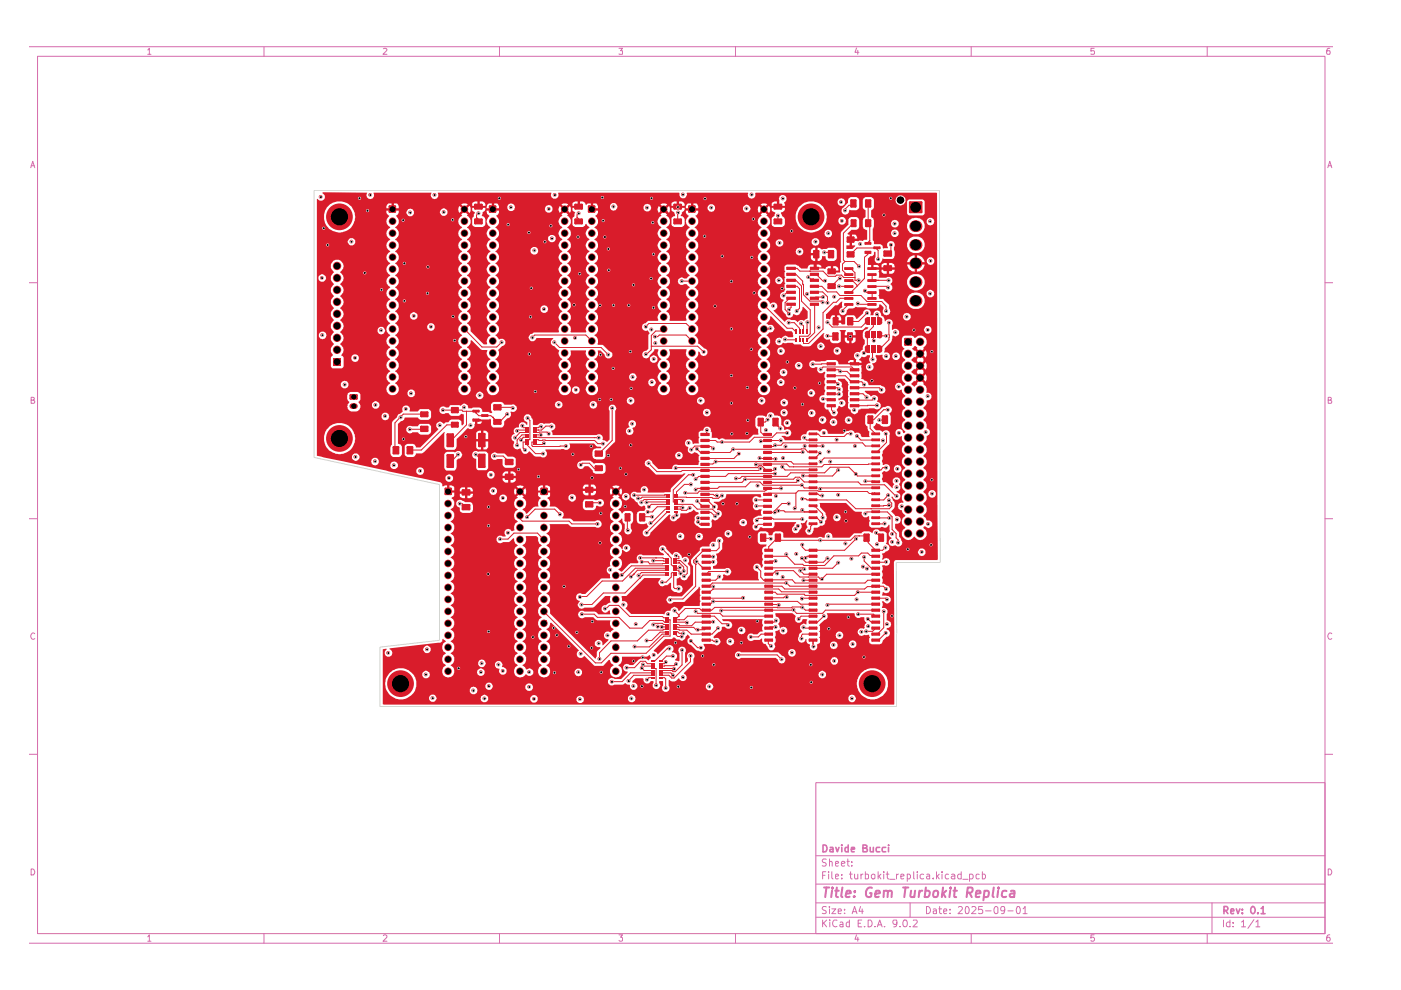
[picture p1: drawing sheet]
<svg xmlns="http://www.w3.org/2000/svg" width="297mm" height="210mm" viewBox="0 0 297 210" stroke-linecap="round" stroke-linejoin="round" font-family="sans-serif">
<g fill="none" stroke="#d56bad" stroke-width=".21">
<path d="M6.3 9.9h276.3M8 11.9h272.9v186.1h-272.9zM31.3 10.6l.4-.4v1.3M31.3 11.5h.7M56 9.9v2M81.3 10.3l.5-.1 .2 .4-.8 .9h.8M105.9 9.9v2M131.2 10.2h.8l-.4 .6h.4v.6h-.8M156 9.9v2M181.6 10.2l-.3 .9h.8M181.9 10.7v.8M205.9 9.9v2"/>
<path d="M232 10.2h-.7v.6h.6l.2 .2-.2 .5-.6-.1M255.9 9.9v2M281.9 10.2l-.5 .1-.1 .5v.6l.6 .1v-.7h-.5l-.1 .2M6.5 35.6l.4-1.4 .5 1.4M6.6 35.1h.7M281.5 35.6l.4-1.4 .5 1.4M281.6 35.1h.7M6.3 59.9h1.7M280.9 59.9h1.7M6.6 84.8h.6v-.5l-.6-.1v1.3h.6l.2-.4-.4-.3M281.6 84.8h.6v-.5l-.6-.1v1.3h.6l.2-.4-.4-.3M6.3 110h1.7"/>
<path d="M280.9 110h1.7M7.4 134.4a.57 .57 0 0 0-.8 0 .57 .57 0 0 0 0 .8l.3 .4 .5-.2M282.4 134.4a.57 .57 0 0 0-.8 0 .57 .57 0 0 0 0 .8l.3 .4 .5-.2M6.3 159.9h1.7M280.9 159.9h1.7M173 165.9h107.9v32.1h-107.9zM6.3 200h276.3M6.6 184.2a.71 .71 0 0 1 .7 .5 .71 .71 0 0 1-.2 .8h-.5zM31.3 198.6l.4-.4v1.4M31.3 199.6h.7M56 198v2M81.3 198.4l.1-.2h.4l.2 .4-.8 1h.8"/>
<path d="M105.9 198v2M131.2 198.2h.8l-.4 .5 .4 .2v.5l-.3 .2h-.3l-.2-.2M156 198v2M173 194.5h107.9M173 191.4h107.9M173 187.5h107.9M173 181.4h107.9M174.4 195.1v1.4M174.4 185.6h.5M174.6 195.7l.7 .8M175.1 184.8h-.7v1.6M175.2 192.3l-.6-.1-.3 .3 .3 .5 .5 .1v.5h-.8"/>
<path d="M175.2 182.2l-.6-.1-.3 .4 .3 .4h.3l.2 .1 .1 .4-.3 .2h-.6M175.3 195.1l-.9 .8M175.7 184.8v.2M175.7 185.3v1.1M175.9 192.2v.2M175.9 182.8l.1-.2 .4 .1v.9M175.9 182.1v1.5M175.9 192.7v1M175.9 195.1v.1M175.9 195.5v1M176.4 192.7h.8l-.8 1h.8M176.4 184.8v1.3l.2 .3"/>
<path d="M177.1 185.8l.7-.1-.2-.4-.4 .1-.1 .7 .2 .3 .4-.1M177.1 183.1l.7-.1-.2-.4-.4 .1-.1 .7 .2 .2h.4M177.5 195.2l-.6-.1a.74 .74 0 0 0-.4 .9 .74 .74 0 0 0 1 .4M177.7 193.2l.7-.1-.2-.4-.5 .1v.8h.6M178.1 195.6h.5l.1 .9M178.4 183.1l.8-.1-.1-.3-.5-.1-.2 .3 .1 .7h.6M178.5 186.2v.2M178.5 185.4v.2M178.7 195.9l-.6 .1v.2l.1 .3 .5-.1M179.1 193.6v.1M179.1 192.8v.2M179.6 182.6h.5"/>
<path d="M179.7 182.1v1.3l.4 .2M180.1 195.6l-.4-.1-.3 .3 .1 .6h.6M180.1 195.1v1.4M180.1 185.3h.6M180.3 184.8v1.3l.4 .3M180.6 183.5v.1M180.6 182.7v.2M180.7 193.7l.5-1.5 .5 1.5M180.8 193.3h.7M181.2 185.3l.1 1 .3 .1 .3-.2M181.6 198.2l-.3 .9h.8M181.9 185.3v1.1"/>
<path d="M181.9 198.7v.9M181.9 195.7h.6M182.5 192.2l-.4 1h.9M182.5 185.3v1.1M182.7 195.1h-.8v1.4h.8M182.8 192.7v1M183 185.3l-.5 .3M183.3 196.4v.1M183.5 185.4l.4-.1 .2 .2v.7l-.2 .2-.4-.1M183.5 184.8v1.6M184.1 195.1h.5a.78 .78 0 0 1 .3 .9 .78 .78 0 0 1-.8 .5zM184.7 185.6a.45 .45 0 0 1 .8-.1v.7l-.2 .2-.5-.2z"/>
<path d="M185.5 196.4v.1M186 196.5l.5-1.4 .5 1.4M186.2 196.1h.7M186.2 184.8v1.6M186.4 185.8l.4 .6M186.8 185.3l-.6 .6M187.4 184.8v.2M187.4 185.3v1.1M187.5 196.4v.1M187.9 185.3h.6M188.1 184.8v1.3l.4 .3M188.6 186.4h1.1"/>
<path d="M190.1 185.3v1.1M190.2 195.7l-.3 .3-.4-.1-.2-.2 .2-.6h.6a1.12 1.12 0 0 1-.4 1.4h-.2M190.5 185.3l-.4 .3M190.8 196.4v.1M191 185.8l.7-.1-.1-.3h-.6v.9h.6M191.6 195.2l.5-.1a.84 .84 0 0 1-.2 1.4l-.3-.1-.2-.4zM192.4 185.4l.4-.1 .2 .3v.4l-.2 .4-.4-.1M192.4 185.3v1.6M193 196.4v.1M193 191.4v3.1M193.6 195.2l.7-.1 .2 .4-1 1h1M193.7 184.8v1.5l.2 .1"/>
<path d="M194.5 184.8v.2M194.5 185.3v1.1M195.8 185.4a.52 .52 0 0 0-.7 .2l.1 .7h.6M196.4 192.2a.77 .77 0 0 1 .9 .8 .77 .77 0 0 1-.9 .7zM196.5 185.4h.5l.1 1M197.1 185.7l-.5 .1-.2 .2 .2 .4 .5-.1M197.9 192.8h.6v.9M197.9 186.2v.2M198.5 193.1l-.6 .1v.4h.6M198.5 184.8v1.6M198.7 185.8l.4 .6M199.1 192.7h.5"/>
<path d="M199.1 185.3l-.6 .6M199.2 192.2v1.3l.4 .2M199.7 184.8v.2M199.7 185.3v1.1M200.1 193.2l.6-.1-.1-.4-.4 .1-.1 .7 .1 .2 .5-.1M201.1 185.4l-.4-.1-.3 .3 .1 .6 .2 .2 .4-.1M201.4 193.6v.1M201.4 192.8v.2M201.8 185.4h.6v1M202.4 185.7l-.5 .1-.2 .2 .2 .4 .5-.1M203.2 192.4l.2-.2h.4a.45 .45 0 0 1 .2 .7l-.9 .8h.9M203.8 185.4l-.5-.1-.3 .3v.4l.3 .4 .5-.1"/>
<path d="M203.8 184.8v1.6M204.1 186.4h1.1M204.7 192.4l.3-.2a.88 .88 0 0 1 .1 1.5l-.4-.1zM205.6 185.4l.5-.1 .2 .3v.4l-.2 .4-.5-.1M205.6 185.3v1.6M205.9 198v2M206.1 192.4l.1-.2h.4l.2 .2 .1 .3-.9 1h.9M207.6 185.4l-.4-.1-.3 .3 .1 .7h.6M208.3 192.2h-.8l-.1 .8 .3-.2 .5 .1 .2 .2-.1 .5h-.9M208.3 185.4l.4-.1 .3 .3-.1 .6-.2 .2-.4-.1M208.3 184.8v1.6M209 193.1h1.1"/>
<path d="M211.1 192.2l.3 .1 .2 .2v1l-.4 .2a.81 .81 0 0 1-.6-.7 .81 .81 0 0 1 .5-.8zM213 192.9l-.1 .2-.6-.1a.6 .6 0 0 1 .1-.8l.5 .1a1.12 1.12 0 0 1-.3 1.4h-.3M213.7 193.1h1.1M215.6 192.3l.2-.1a.86 .86 0 0 1 .6 .7 .86 .86 0 0 1-.4 .8h-.2a1.1 1.1 0 0 1-.2-1.4zM216.9 192.7l.4-.5v1.5M216.9 193.7h.9M232 198.2h-.7v.7l.2-.2h.3l.3 .3v.3l-.3 .3h-.3l-.2-.2M255.9 198v2M257 191.4v6.6M259.4 195.1v1.4M260.8 195.6l-.5-.1-.3 .3 .1 .6h.7M260.8 195.1v1.4"/>
<path d="M261.5 196.4v.1M261.5 195.6v.1M263.2 195.5l.5-.4v1.4M263.2 196.5h.9M265.9 195l-1.3 1.8M266.3 195.5l.4-.4v1.4M266.3 196.5h.8M281.6 184.2a.71 .71 0 0 1 .7 .5 .71 .71 0 0 1-.2 .8h-.5zM281.9 198.2l-.5 .2a.92 .92 0 0 0 .1 1.2l.4-.1 .1-.5-.2-.3h-.3l-.2 .3"/>
</g>
<g fill="none" stroke="#d56bad" stroke-width=".34">
<path d="M174.5 179.2a.81 .81 0 0 1 .8 .4 .81 .81 0 0 1-.2 1h-.6zM176 179.7h.5l.1 .1v.8h-.6v-.5l.6-.1M177.2 179.7l.3 .9 .4-.9M178.5 179.2h.1M178.5 179.7v.9M179.8 179.2v1.4h-.5l-.1-.3v-.6h.6M183 179.8l.6-.1 .2-.1-.1-.4h-.7v1.4h.7l.2-.5-.4-.3M184.5 179.7l.1 .9 .6-.1M185.2 179.7v.9M186.5 179.7h-.6l-.1 .2 .1 .7h.6M187.8 179.7h-.6l-.2 .2 .2 .7h.6M188.4 179.2h.1"/>
<path d="M188.4 179.7v.9M180.5 180.1l.7-.1-.1-.3h-.5l-.1 .1 .1 .8h.5M259.5 193h.6a.47 .47 0 0 0 .3-.4 .47 .47 0 0 0-.3-.4h-.6v1.5M259.8 193l.5 .7M260.9 193.2l.7-.1-.1-.4-.5 .1-.1 .7 .2 .2 .4-.1M262.1 192.7l.4 1 .4-1M263.4 193.5v.2M263.4 192.8v.2M265.3 192.4l.3-.2a.82 .82 0 0 1 .5 .8 .82 .82 0 0 1-.5 .7 .93 .93 0 0 1-.3-1.3zM266.7 193.5v.2M267.4 192.6l.4-.4v1.5M267.4 193.7h.8"/>
</g>
<g fill="none" stroke="#d56bad" stroke-width=".42">
<path d="M174.7 188.2h1.1M175.2 188.2l-.2 2M176.4 188.8l-.2 1.4M176.5 188.2v.2M177.1 188.8h.7M177.4 188.2l-.2 1.7 .5 .3M178.6 188.2l-.2 1.7 .2 .3M179.4 189.5l1-.1-.1-.5h-.8l-.2 1 .2 .3 .6-.1M181.1 190l.1 .1h-.2l.1-.1v.2M181.2 188.9v.3M184.9 188.3a.77 .77 0 0 0-1 .2 1.18 1.18 0 0 0 0 1.6l.5 .1 .3-.2 .1-.6h-.4M185.5 189.5l1.1-.1-.1-.5-.6-.1-.3 .4-.1 .9h.8"/>
<path d="M187.4 189l.3-.2 .5 .1v1.3M187.4 188.8l-.1 1.4M188.3 189.2l.3-.4 .4 .1v1.3M191.5 188.2h1.1M192 188.2l-.3 2M193.2 188.8l-.1 1.3 .5 .1 .2-.2M194 188.8l-.2 1.4M194.9 188.8l-.1 1.4M195.5 188.8a.46 .46 0 0 0-.6 .5M196.2 188.9l.6-.1 .3 .2a.89 .89 0 0 1-.5 1.2l-.6-.1M196.3 188.2l-.3 2M198 189l.3-.2a.46 .46 0 0 1 .6 .5l-.1 .5a.52 .52 0 0 1-.5 .4 .52 .52 0 0 1-.5-.4z"/>
<path d="M199.9 188.2l-.2 2M199.9 189.4l.5 .8M200.6 188.8l-.8 .8M201.5 188.8l-.2 1.4M201.5 188.2v.2M202.1 188.8h.8M202.5 188.2l-.2 1.9 .4 .1M205 189.3l1-.1 .2-.4-.1-.5-.9-.1-.3 2M205.5 189.3l.5 .9M206.9 189.5l1-.1-.1-.5-.6-.1-.2 .4-.1 .9h.7M208.7 188.9a.64 .64 0 0 1 .9 .1l-.1 1-.3 .2-.5-.1M208.7 188.8l-.2 2.1"/>
<path d="M210.7 188.2l-.3 1.7 .3 .3M211.6 188.8l-.1 1.4M211.7 188.2v.2M213.4 188.9l-.5-.1-.3 .2-.1 1a.64 .64 0 0 0 .8 .1M214.3 188.9h.8l-.1 1.3M215.1 189.4h-.7l-.3 .3v.2l.2 .3 .7-.1"/>
</g>
<path d="M66.6 40.3h132.6l.1 79h-9.3l.1 30.5h-109.5v-12.6l12.6-1.4v-33.1l-26.6-5.7z" fill="none" stroke="#d0d2cd" stroke-width=".21"/>
<g fill="#d91c2b">
<path d="M193.3 81.2l.5-.5 .2 .2 .6-.7 .2 .4h.2l-.6 .6 .1 .2-.6 .6-.6-.5z"/>
<path d="M193.3 78.7l.5-.5 .2 .2 .6-.7 .2 .3 .2 .1-.6 .6 .1 .2-.1 .1 .6 .6-.4 .4-.6-.6a.64 .64 0 0 1-.7-.7z"/>
<path d="M193.3 76.2l.5-.6 .2 .2 .6-.7 .2 .4 .2 .1-.6 .6 .1 .1-.1 .2 .6 .6-.4 .3-.6-.6a.64 .64 0 0 1-.7-.6z"/>
<path d="M193.4 73.8l.7-.4 .4 .4-.1 .2 .6 .5-.4 .4-.6-.6-.2 .1-.4-.4z"/>
<path d="M68.5 40.8l9.4 .1-.1 .1a.89 .89 0 0 0 .8 1.2 .94 .94 0 0 0 .6-1.3h12.3v.1a.79 .79 0 0 0 .3 1.2 .79 .79 0 0 0 1.1-.6l-.1-.7h24.1a1.05 1.05 0 0 0 .4 1.2h.6l.3-.2 .2-.3v-.7h25.6l.1 .5 .5 .6h.5l.3-.2 .3-.5v-.4h12.8l.1 .8 .4 .3 .3 .1 5.8-.1 .2 .6-.1 1h1.2l-.2-.7 .3-.1 .3-.4-.1-.6a.81 .81 0 0 0-.9-.4 .81 .81 0 0 0-.7 .6h-5.5l.5-.3v-.8h.1h38.5l.1 77.7v.1h-8.9l-.4 .4 .1 30.2-108.3 .1-.1-.1v-4.5h.5a3.3 3.3 0 0 0 4.7 3.2h4.6v.3a.81 .81 0 0 0 .7 .5 .81 .81 0 0 0 .7-.4l.2-.4h9.3a.81 .81 0 0 0 .8 .9 .81 .81 0 0 0 .8-.8h8.9l.1 .4a.86 .86 0 0 0 1.5 0v-.3h8.2a.79 .79 0 0 0 .9 .9 .79 .79 0 0 0 .6-1.1h9.4v.4a.83 .83 0 0 0 1 .5 .83 .83 0 0 0 .6-.9h45.2l.2 .7 .3 .2h.5a.81 .81 0 0 0 .3-1.4 .81 .81 0 0 0-1.3 .5h-45.2v-.1a.77 .77 0 0 0-.9-.6 .77 .77 0 0 0-.7 .7h-9.4a.81 .81 0 0 0-.8-.5 .81 .81 0 0 0-.7 .7h-8.2v-.3a.84 .84 0 0 0-.9-.5 .84 .84 0 0 0-.7 .7h-8.9v-.2a.82 .82 0 0 0-.9-.6 .82 .82 0 0 0-.7 .7h-9.3l-.3-.5a.84 .84 0 0 0-1.3 .3v.2h-4.6a3.1 3.1 0 0 0 1.6-1.7h11.6v.4a.84 .84 0 0 0 1.3 .4 .84 .84 0 0 0 0-1.4 .84 .84 0 0 0-1.3 .5v.1h-11.6l.3-.9h14.6v.4a.81 .81 0 0 0 .7 .4 .81 .81 0 0 0 .8-.4v-.2h7v.3a.88 .88 0 0 0 1.3 .4l.2-.2a.83 .83 0 0 0-.1-.9 .83 .83 0 0 0-.8-.3l-.5 .3-.1 .4h-7v-.4l-.5-.5h-.5l-.2 .2-.3 .5h-14.6v-1l-.3-.8-.4-.6h1.9v.3l.3 .3 .2 .2h.6a.81 .81 0 0 0 .3-1.4 .81 .81 0 0 0-1.4 .6h-1.9l-.4-.5a3.3 3.3 0 0 0-3.5-.5 3.3 3.3 0 0 0-2 2.8h-.5v-7.1l.6-.2 .2 .2a.84 .84 0 0 0-.4 .8 .84 .84 0 0 0 .5 .7l.7-.1a1.04 1.04 0 0 0 .3-1.1l-.5-.4h7.1a.85 .85 0 0 0 1.4 .7l.1-.3a.84 .84 0 0 0-.7-1.1l-.4 .1-.4 .6h-7.1v-.1l10.8-1.2 .4-.3v-.4l.1-.2 .6 .5-.1 .2a1.19 1.19 0 0 0-.5 1.6l.1 .4 .5 .4-.1 .1a1.19 1.19 0 0 0-.5 1.7l.1 .4 .5 .3-.1 .2a1.19 1.19 0 0 0-.5 1.6 1.26 1.26 0 0 0 1.3 .8 1.26 1.26 0 0 0 1.1-1.1h4.8v.1a.84 .84 0 0 0 .8 .7 .84 .84 0 0 0 .8-.5v-.7a.85 .85 0 0 0-.9-.3 .85 .85 0 0 0-.7 .7h-4.8v-.5a1.1 1.1 0 0 0-.8-.9l.6-.5h5.3v.3a.81 .81 0 0 0 .7 .5 .81 .81 0 0 0 .7-.4l.1-.2h2v.4l.3 .4 .7 .2v.8a.86 .86 0 0 0 1.5-.1 1.16 1.16 0 0 0-1-1.1 .84 .84 0 0 0-.4-1.2h-.5l-.3 .1-.3 .5h-2a.78 .78 0 0 0-.6-.9 .78 .78 0 0 0-.9 .7h-5.3l.2-.5v-.8l-.8-.8 .6-.5 .2-1.1-.2-.5-.6-.5 .6-.5 .2-1.1-.2-.5-.6-.4 .6-.5 .2-1.1-.2-.5-.6-.4 .6-.6 .2-1.1-.2-.5-.6-.3 .2-.2a1.36 1.36 0 0 0 0-2.3l-.2-.1 .6-.5 .2-1.1-.2-.5-.6-.5 .6-.5 .2-1.1-.2-.5-.6-.4 .6-.5 .2-1.1-.2-.5-.6-.4 .1-.1a1.19 1.19 0 0 0 .6-1.6l-.1-.5-.6-.4a1.16 1.16 0 0 0 .8-1.3h9v.3a.79 .79 0 0 0 1.3 .3h1.3l.9-.8 .1 .1a1.49 1.49 0 0 0 .9 1.4l-.1 .2a1.19 1.19 0 0 0-.6 1.6l.2 .4 .5 .4-.2 .1a1.54 1.54 0 0 0-.5 1.8l.7 .6-.2 .2a1.36 1.36 0 0 0 0 2.2l.2 .1-.1 .2a1.19 1.19 0 0 0-.6 1.6l.2 .4 .5 .4-.1 .1a1.19 1.19 0 0 0-.6 1.7l.2 .4 .5 .3-.1 .2a1.26 1.26 0 0 0-.5 1.8l.6 .6-.2 .1a1.36 1.36 0 0 0 0 2.3l.2 .1-.1 .2a1.19 1.19 0 0 0-.6 1.6l.2 .4 .5 .3-.1 .2a1.19 1.19 0 0 0-.6 1.6l.2 .4 .5 .4-.1 .1a1.19 1.19 0 0 0-.6 1.7l.2 .4 .5 .3-.1 .2a1.19 1.19 0 0 0-.6 1.6 1.33 1.33 0 0 0 1.1 .8 1.33 1.33 0 0 0 1.3-.6h.1a.83 .83 0 0 0 1.1 .2 .83 .83 0 0 0 .3-1.1l-.7-.4-.8 .2-.2-.5-.5-.3 .5-.4 .2-.6v-.8l-.2-.4-.5-.3 .5-.5 .2-.6v-.6l-.2-.5-.5-.4 .5-.4 .2-.6v-.9l-.7-.6 .5-.4 .2-.6v-.7l-.2-.5-.5-.4 .5-.4 .2-.6v-.9l-.7-.6 .2-.2a1.36 1.36 0 0 0 0-2.3l-.2-.1 .5-.4 .2-.6v-.6l-.2-.5-.5-.5 .6-.5 .1-1.1-.2-.5-.5-.4 .6-.5 .1-1.1-.2-.5-.5-.4 .1-.1a1.19 1.19 0 0 0 .6-1.6l-.2-.5-.5-.4a1.1 1.1 0 0 0 .7-.9v-1h2.2l.4 .3 .2 1.1 .6 .5-.1 .2a1.19 1.19 0 0 0-.6 1.6l.1 .4 .6 .4-.2 .1a1.54 1.54 0 0 0-.5 1.8l.7 .6-.2 .2a1.36 1.36 0 0 0 0 2.2l.2 .1-.1 .2a1.19 1.19 0 0 0-.6 1.6l.1 .4 .6 .4-.1 .1a1.19 1.19 0 0 0-.6 1.7l.1 .4 .6 .3-.1 .2a1.26 1.26 0 0 0-.5 1.8l.6 .6-.2 .1a1.36 1.36 0 0 0 0 2.3l.2 .1-.1 .2a1.19 1.19 0 0 0-.6 1.6l.1 .4 .6 .3-.1 .2a1.19 1.19 0 0 0-.6 1.6l.1 .4 .6 .4-.1 .1a1.19 1.19 0 0 0-.6 1.7l.1 .4 .6 .3-.1 .2a1.19 1.19 0 0 0-.6 1.6 1.26 1.26 0 0 0 1.3 .8 1.26 1.26 0 0 0 1.1-1.1h5.2v.1a.82 .82 0 0 0 .7 .8 .82 .82 0 0 0 .9-.6v-.5l-.5-.5-.7 .1-.4 .6h-5.2a1.26 1.26 0 0 0-.7-1.4l.5-.4 .2-.6v-.8l-.2-.4-.5-.3 .5-.5 .2-.6v-.6l-.2-.5-.5-.4 .5-.4 .2-.6-.1-.9-.6-.6 .1-.2a1.34 1.34 0 0 0 .7-1.3h.2l5.8 5.9a.88 .88 0 0 0-.2 1.4 .88 .88 0 0 0 1.4-.2l2.2 2.1h1.8l1.2-1.3 .2 .1 .3 .7 .5 .3-.2 .2a1.54 1.54 0 0 0-.5 1.8 1.33 1.33 0 0 0 1.4 .6 1.33 1.33 0 0 0 1.1-1l-.1-.9-.7-.6 .6-.6 .2-.4v-.9h5.2l.7-.3 .2 .6-.5 .5-.5-.3h-1.2l-1.6 1.3h-.7a.84 .84 0 0 0-1.4 .4v.5l.2 .2 .3 .3h.5v.2l-1.4 1.4h-1.4a.82 .82 0 0 0-1.2 0 .82 .82 0 0 0 0 1.1 .82 .82 0 0 0 1.2 .1h1.7l.5-.4 .6 .4h.4a.91 .91 0 0 0 .3 .9 .91 .91 0 0 0 .9 .1l.4-.4a.84 .84 0 0 0-.2-.9 .84 .84 0 0 0-.8-.2v-.3l.6-.6h1.6l.1 .1v.5l.5 .5h.6l.5-.5h.5l.1 .4-.2 .3v.5l.5 .5h.5a.78 .78 0 0 0 .3-1.3l.1-.4h.7v1a.9 .9 0 0 0 .4 1.3h.5l.4-.3 .1-.3v-.6h7.7v.3a.81 .81 0 0 0 .7 .5 .81 .81 0 0 0 .8-.4 .79 .79 0 0 0-.4-1.1h31v.4a3.3 3.3 0 0 0 3.1 3.1 3.3 3.3 0 0 0 3.5-2.7 3.2 3.2 0 0 0-1.9-3.6 3.3 3.3 0 0 0-4.7 2.8l-31.4-.1-.6 .5-.1 .3-7.8-.1 .1-1.3 .6 .4h.5l.9-.7 .2 .1a.8 .8 0 0 0 .7 .5 .8 .8 0 0 0 .8-.5v-.5l-.4-.4h28.3a.83 .83 0 0 0 .7 .8 .83 .83 0 0 0 .9-.5l-.1-.7a.85 .85 0 0 0-.8-.3 .85 .85 0 0 0-.7 .7h-28.3l-.2-.2 1.9-2 .1-1.1 .3-.6-.1-.3h8.6v.3a.73 .73 0 0 0 .6 .6 .73 .73 0 0 0 .7-.2h7.4l.5 .4a.77 .77 0 0 0 .7 .8 .77 .77 0 0 0 .8-.6h9.6l.4 .7h.7a.81 .81 0 0 0 .1-1.4 .81 .81 0 0 0-1.2 .7h-9.6v-.5l-.2-.3-1.3-1h2.1a.83 .83 0 0 0 .6 .9 .83 .83 0 0 0 1-.6 .83 .83 0 0 0-.5-1l-.7 .1-.2 .2-.2 .4h-10l-.3-.2h-.5l-.3 .3-.2 .4h-8.6a.79 .79 0 0 0-1.1-.4 .79 .79 0 0 0-.3 1.2v.6l-.5 .4-.1-2.2a.8 .8 0 0 0-.1-1.1 .8 .8 0 0 0-1.1 .1 .8 .8 0 0 0 .1 1.1v1.6l-.2 .2-.8-.3 .5-.6-.1-.7-1-.5 .3-.4v-.5a1.02 1.02 0 0 0-1.6-.3l-1.7 1.7-.4-.4-.5-.3 2.4-2.5h1.4l.3-.3h.3l.5 .4 .7 .1a.85 .85 0 0 0 1.2-.8l.4-.3 .5 .4-.5 .7v.5l.1 .2 .5 .3 1.2 1.2 .5 .1a.86 .86 0 0 0 1.4-.7l-.4-.6 .1-.2h1.7l1.1 .4 .7-.5 .1-.5h1.3a.78 .78 0 0 0 .6 .9 .78 .78 0 0 0 .9-.6 .78 .78 0 0 0-.5-.9h-.5l-.4 .2-.1 .4h-1.4l-.3-.6h-1l-.1-.3 1.7-1.4h3.4v.3a.84 .84 0 0 0 1.2 .5 .86 .86 0 0 0 .4-.8 .86 .86 0 0 0-.6-.7 .78 .78 0 0 0-1 .7h-3.4v-.6l.6-.1a.84 .84 0 0 0 1.5 .1 .84 .84 0 0 0-.6-1.3h-1.1l-.3-.4h8.6v2.5a1.3 1.3 0 0 0-1.1 .7l-1.6-.2a.81 .81 0 0 0-.4 1.2 .81 .81 0 0 0 1.2 .2h1.3l.4-.4 .1 .7 .2 .4 .5 .1 .7 1.2 .3 .2 .7-.1 .4-.7-.1-.2a.57 .57 0 0 1 .2-.9l-.2-.8 .2-.5-.1-.9 .5-.1 .3-.2 .1 .5 .5 .5h.5l.5-.3a.89 .89 0 0 0-.7-1.3l-.7 .3-.4-1a.85 .85 0 0 0 .3-.9 .85 .85 0 0 0-.8-.6v-.7l3.6 .1a.8 .8 0 0 1 .4 1.3 .85 .85 0 0 0 .9 .7 .85 .85 0 0 0 .8-.8h.8l.2 .1-.2 .3v.7l-.7-.2-.7 .6v.5l.5 .6a1.61 1.61 0 0 0-.7 2l.2 .3a.94 .94 0 0 0 1.2-.6l.2-.1 .2 .9 .5 .2v.3a.74 .74 0 0 0 .6 1l.5-.1a.78 .78 0 0 0 .4-1.1h2.8v.3a.8 .8 0 0 0 1 .6 .8 .8 0 0 0 .5-1.1h2.5v.4a.86 .86 0 0 0 1.6 0l-.1-.7a.81 .81 0 0 0-.9-.4 .81 .81 0 0 0-.6 .7l-2.5-.1a.81 .81 0 0 0-.9-.4 .81 .81 0 0 0-.6 .7h-2.8l.7-.5v-.9h-.2l.2-.6h3.3a.82 .82 0 0 0 1 .8 .82 .82 0 0 0 .6-1.1 .82 .82 0 0 0-1.2-.4l-.4 .3v.4h-3.3v-.6l-.2-.1 .2-.4v-.8l-.2-.3 1.1-1.1 .5-.2 .2-.3-.1-.9h5.7l.1 .1v.4l.5 .5h.5l.3-.1h.8v.5l.4 .6-.4 .7a.31 .31 0 0 1 0 .4 .31 .31 0 0 1-.4 .1 .9 .9 0 0 0-1 1.2 .86 .86 0 0 0 1.4 .2l1 .1 .1 .4-.1 .2 .1 1.1 .4 .2h1.8a.74 .74 0 0 0 .6-.8l1.5-1.3v-.5l-.3-.4-.5-.2 .1-.2a.85 .85 0 0 0 .9-.8 .85 .85 0 0 0-.9-.9v-1.3l.2-.3v-.5l-.5-.5h-.7l.2-.5-.2-.8 .3-.1a1.03 1.03 0 0 0 1 .4l.5-.5a.91 .91 0 0 0-.9-1.1l-.9-.1 .2-.7h.1a.8 .8 0 0 0 1.4-.3v-.5l-.3-.4-1.4-.6 .2-.4v-.5l-.2-.2 .2-.6v-.5l-.2-.2 .2-1-.2-.3 .1-.2 .6 .1a.81 .81 0 0 0 1-.6v-.5l-.2-.1a.75 .75 0 0 0-1.3 0l-.2-.1 .2-.4v-.5l-.2-.2 .7-.5h6.9v.1a.84 .84 0 0 0 .7 .8 .84 .84 0 0 0 .9-.5v-.6l-.5-.5-.7 .1-.4 .6h-6.9a.85 .85 0 0 0 .9-.8 .85 .85 0 0 0-.8-.9l.2-.3v-1.9l-.6-.5h-.9l-.3-.3a.88 .88 0 0 0-1.2 .7l-.7-.4h-1.1l-.5 .5h-1.6l-1 .9h-3.6l-.1-.5a.8 .8 0 0 0-1.3-.4l-.3 .9-.7-.2-.7 .2h-7.2l-.1-.9-.6-.5h-1.1l-.4 .3-.3 .6h-.7l-.1-.6-.6-.3h-1.1l-.3 .2-.2 .4v1.7l.2 .4 .3 .1h1.3l-.1 .5a.76 .76 0 0 0-.8 .6v.5l.2 .2-.2 .5v.5l.2 .3-.2 1 .2 .4-.2 .5-.3-.1a.82 .82 0 0 0-.8-.8 .82 .82 0 0 0-.8 .8 .82 .82 0 0 0 .8 .8l.2 .3v1.2l.2 .5h-7.8l-.1-.2 .4-.5-.1-.5h.4a.82 .82 0 0 0 1.2-.3 .82 .82 0 0 0-.4-1.2h-.5l-.3 .2h-2.4l-.1-.6h.1a.88 .88 0 0 0 .5-1.4l.2-.7-.2-.4 .5-.2 .8-.8 .1-1.5a.87 .87 0 0 0-.4-1.2l-.6 .1a.74 .74 0 0 0-.4 1h-.2a.84 .84 0 0 0-1.2 .8v.2h-1.5l-.4 .2-.1 .7-1.9 1.9 .1 1 .3 .3v4.1l-2.3 2.3h-2.4a.83 .83 0 0 0-.9 .6 .83 .83 0 0 0 .6 1h.5l.4-.4h2.4l2.8-2.8 .1-.4 .3 .1 .1 .4-.1 .3v.8l.1 .2-.1 .2v.9l.1 .3-.1 .1-.1 .8h-3.3l-.9 1h-.3l-.2-.6-.6-.2-.7 .4-.1 .4h-.7l-.3 .2-.4 .6-7-.1-1.2-1.3a.77 .77 0 0 0 .5-.8 .77 .77 0 0 0-.6-.6l-.6-.1-.1-1h1l3.8-3.8h3.3l.2 .1a.8 .8 0 0 0-.4 1.2 .8 .8 0 0 0 1.2 .2 1.15 1.15 0 0 0 1.1-.5l.3 .1 .1 1.3 .4 .4 .6 .1a.82 .82 0 0 0 1.3-.5 .82 .82 0 0 0-1.1-.8l-.1-1.5 .6-.3 .2 .1a.8 .8 0 0 0 1.3 .4l.7-1.2v-1.5l-.5-.8a.8 .8 0 0 0-.2-1.3h-.5l-.4 .2-.2-.5a1.16 1.16 0 0 0-1.7-.5l-.2 .3h-.1l-1.2-1.2v-.3a.8 .8 0 0 0-.8-.5 .8 .8 0 0 0-.8 .6v.5l.3 .4 .8 .4-.1 .2h-4.4a.79 .79 0 0 0-1.2 .2 .79 .79 0 0 0 .2 1.1v.3l-.1 .1h-1.6l-1.7 1.8h-.3l-.5-.5 .6-.5 .2-1.1-.3-.5-.5-.4 .5-.4 .4-1.3a1 1 0 0 0 1.6 .1 .86 .86 0 0 0-.2-.9 .86 .86 0 0 0-.9-.2l-.5 .5v.4l-.1 .1-.8-.9a1.1 1.1 0 0 0 .8-.9l-.1-1-.7-.6a1.1 1.1 0 0 0 .8-1l-.1-.9-.7-.6 .7-.7 .2 .1v.7l.5 .3v1.1a.78 .78 0 0 0 .8 1.2 .78 .78 0 0 0 .4-1.3v-1h.3l.2-.6v-1.5l-.1-.3-.5-.3h-1.1l-.7 .5-.2-.4-.5-.3 .5-.4 .3-.6v-.8l-.3-.4-.5-.4 .3-.2-.1-.1h.6l.1 .5 .5 .3a.87 .87 0 0 0 1-.5l-.1-.6h.3l.1 .6 1.4 1.1a.78 .78 0 0 0 .4 .7 .78 .78 0 0 0 .9-.2 .74 .74 0 0 1 .1 1.2h-.9l-.5 .3-.2 .4 .1 1.7 .7 .4 1.3-.1 .4 .5-.5 .6-.3 .1-.3 .4-.1 .6 .1 .3a.82 .82 0 0 0 1.1 .2h6v.2a.82 .82 0 0 0 .9 .6 .82 .82 0 0 0 .7-.8h2.3v.3a.84 .84 0 0 0 1.2 .5l.4-.3 .1-.4-.2-.6-.3-.1h5l.1 .5 .8 .4 .7-.4v-.7a.84 .84 0 0 0-.8-.5 .84 .84 0 0 0-.8 .7l-5.6-.1-.4 .2-.2 .5h-2.3v-.2a.88 .88 0 0 0-1.4-.4l-.2 .6h-6l.4-.5v-.2l4-3.9 .3 .2-.2 .2v.5a.95 .95 0 0 0 .9 .5 .95 .95 0 0 0 .8-.5l.5-.5 .1-.7h1.4l1.4-.7 .4 .4 .6 .2v.3l-.6 .3-.2 .3v1.4l1.2 1 2.2-.1 .2-.3-.1-.9h6l.1 .6 .5 .2h.5l.5-.5v-.5a.84 .84 0 0 0-.9-.5 .84 .84 0 0 0-.7 .7h-6l.2-.6 .7 .3 .5-.3 .3-.4a.84 .84 0 0 0 .5-1.1 .84 .84 0 0 0-1-.5l.1-.3a.85 .85 0 0 0-.7-1.2l-.1-.2h1.1l.6-.5a.87 .87 0 0 0 1-1l7.2-.1 .2 .6-.5 .1a.84 .84 0 0 0-1.3 .3v.5l.2 .3a.91 .91 0 0 0 0 1.2 .91 .91 0 0 0 1 .3l.7-.1-.2 .4 .2 .9h-.8l-.2 .2a.83 .83 0 0 0-.8 .5 .83 .83 0 0 0 .1 .9v.2a.84 .84 0 0 0 .3 1.4l.6-.1 .5-.6h.4l.2 .2h2l.4-.5v-.8h4.6v.3h-.3l-.1 .5-.5 .5 .1 .6a.81 .81 0 0 0 .9 .5 .81 .81 0 0 0 .6-.8l.5-.5v-.5l-.2-.2 .1-.2a.77 .77 0 0 0 1.1-.6h.2l-.2 1 .2 .5a.83 .83 0 0 0 0 1.4 .83 .83 0 0 0 1.2-.6l.2-.7h.8l.5-.4h.5l.4-.3 .2-.4-.1-.3 .3-.4 .1-.5h1.4v.3a.84 .84 0 0 0 1.1 .5l.4-.5a.74 .74 0 0 0-.5-1h-.5l-.3 .2-.2 .5h-1.4l-.3-.4v-.4l-1.1-1.2-.1-1h5.6l1.7 1.7 .3 .2 1.4 .1a.86 .86 0 0 0 .5 1.1h.5l.3-.3 .2 .1v.7l.1 .2-.1 .3v.8l.4 .4h1.9l.5-.2a.84 .84 0 0 0 1.3-.4h.2l.1 1.2-.3 .5v.5l.6 .5-.1 .3a.79 .79 0 0 0-.4 1.1 .79 .79 0 0 0 1.2 .2l.2 .1a.86 .86 0 0 0 1 0 .86 .86 0 0 0 .4-.8l-.2-.3v-.3l-.5-.5-.1-1.1-.7-.7 .1-1a.86 .86 0 0 0 .9-.3 .86 .86 0 0 0 0-1l-.4-.3h-.6l-.9-1a1.55 1.55 0 0 0 .7-2l-.3-.4-.3-.6 .2-.1 .2 .2a.8 .8 0 0 0 .7 .5 .8 .8 0 0 0 .8-.5l-.1-.7-.8-.5 .5-.2 .4-.5v-.5l-.3-.5a.81 .81 0 0 0 .1-1 .81 .81 0 0 0-.8-.4l-.6 .5v.5l.3 .5-.5 .8-1-1.1-.9-.2-.2-.6 .2-1-.2-.4 .4-.3a.81 .81 0 0 0 1.3-.5h.8v.3l.5 .5 .7-.1a.92 .92 0 0 0 .4-1.1l-.6-.3a.72 .72 0 0 0-1 .7h-.8v-.5a.82 .82 0 0 0-1.3-.3h-.2l-.2-.8 .2-.4-.1-.6a2.45 2.45 0 0 1 1.2-2.4l.3-.3v-1.9a.84 .84 0 0 0-.5-.9 .84 .84 0 0 0-1 .3l-.5-.4h-.9l-.5-.5v-.3l.3-.1 .2-.6 .3 .1a.82 .82 0 0 1 .8 .5l.4 .2h1l.4-.2 .2-.4v-1.7l-.3-.4 .5-.6a.8 .8 0 0 0-.2-1 .8 .8 0 0 0-1.1 .1l-.6 .1-1.5 1.4-.3-.1h-1.4l-.5 .4v1.8l.3 .4 .2 .1 .1 .8 .4 .4v1.1h-1.6l-.4-.7-.2-.2h-1a.91 .91 0 0 0-1.3-.4 1.21 1.21 0 0 0-1.1 .6h-3.2l-.1-.1-.2-.7-.3-.2-.7 .1-.4 .4-.5-.3h-1.8a.76 .76 0 0 0-.6 .9h-.6l-.4 .2-.2 .3v.7h-3.4l-.7-.9h.7l.3 .2 .6-.1a.76 .76 0 0 0 .4-1.1l-.4-.3-.3-.1-.8 .1v-.5l-.5-.5v-.5h.5v.4a.82 .82 0 0 0 1.3 .3 .82 .82 0 0 0-.3-1.4h6.4v.4a.77 .77 0 0 0 .7 .6 .77 .77 0 0 0 .7-.4h.9l.1 .4a.86 .86 0 0 0 1.5-.1v-.5l-.2-.3h1.8a.82 .82 0 0 0 1.1 .8 .82 .82 0 0 0 .3-1.3 .82 .82 0 0 0-1.3 .2l-.1 .3h-1.8l-.1-.1a.9 .9 0 0 0-1.3 .6h-.8a.91 .91 0 0 0-.5-1.2h-.5l-.2 .1-.3 .5h-6.9l-.4 .3-.1 .4h-.5v-.7l-.2-.5-.3-.2-1-.1-.2-.4-.4-.3h1.9v.4l.5 .5 .7-.1 .3-.4v-.3h4.3v.3a.84 .84 0 0 0 1.2 .5l.3-.5a.74 .74 0 0 0-.5-1h-.5l-.3 .3-.2 .4h-4.3l-.2-.5a.84 .84 0 0 0-1.3 .2v.2h-2.4l-.3 .3-.2 .6h-.2l-.6-.2h-1l-.4 .2-.3 .4v1.6l.3 .5 .3 .2 .1 1.1-1.2 .1-.9 1h-5.1a.63 .63 0 0 0-1 0h-.2l-.4-.4h-1.2l.1-1.1-.2-.2v-.4l-.1-.4-.4-.2h-.6l-.3 .2-.2 .6h-.5l-.5 .4v.9l.2 .2-.2 .2 .1 .9-1.3 .2a.83 .83 0 0 0-.7-.9 .83 .83 0 0 0-1 .6 .83 .83 0 0 0 .7 1l-.1 .8 .3 .4 .6 .2 .7-.3 .4 .2 .5 .5-.2 .2v.9l.2 .1-.2 .7h-5.1l-.3 .3-.2 .6h-2.9l-1.3-1.2a.8 .8 0 0 0-.8-.8 .8 .8 0 0 0-.8 .8 .8 .8 0 0 0 .8 .8l1.6 1.6h5.6l.2-.2 .4 .1-3 3-.2 .9h-4.7l-.1-.1a.87 .87 0 0 0-.4-1.2l-.6 .1a.84 .84 0 0 0-.4 1.2h-.9l-.3-.1h-.5l-.3 .2-.2 .4h-.3a.81 .81 0 0 0-.9-.4 .81 .81 0 0 0-.6 .7h-.6l-.6-.6 .3-.3 .7 .6 .2-.4-.2-1-.7 .7-.3-.4 .7-.6a1.26 1.26 0 0 0-1.6 0l.8 .6-.4 .4-.7-.7-.2 .4 .2 1 .7-.6 .4 .3-.8 .7 .3 .2-.1 .1a1.19 1.19 0 0 0-.6 1.6l.2 .5 .5 .3-.1 .2a1.19 1.19 0 0 0-.6 1.6l.2 .4 .5 .3-.2 .2a1.47 1.47 0 0 0-.5 1.7l.2 .3 .5 .4-.2 .1a1.36 1.36 0 0 0 0 2.3l.2 .1-.1 .2a1.19 1.19 0 0 0-.6 1.6l.2 .4 .5 .4-.2 .1a1.47 1.47 0 0 0-.5 1.7 .9 .9 0 0 0-.8 .9 .9 .9 0 0 0 .7 .9v.8l-2 .1-3.1 3.2h-.9a.89 .89 0 0 0-1.2 .8l.2 .4 .6 .3v.2a.76 .76 0 0 0-.3 1 .76 .76 0 0 0 1 .4l.3-.2h1.9l2.5-2.4h1.1v1.4l-.4 .1-.5 .4h-.4l-.5 .5a.87 .87 0 0 0 .2 .9 .87 .87 0 0 0 .9 .1l.4-.4h.1l.2 .9h-2.5l-.8-.6h-2.2l-.2-.2a.9 .9 0 0 0-1.1 1.2 .86 .86 0 0 0 1.4 .2h1.8l.8 .6h2.8a1.57 1.57 0 0 0 .5 1.8l.2 .2-.8 .6a.81 .81 0 0 0-1.2 .4 .81 .81 0 0 0 .9 1v.3l-1.2 1.1-.1-.7a.8 .8 0 0 0-1.3-.3 .8 .8 0 0 0 .3 1.3h.5l.1 .3-.8 .7v1l-.3 .5-9.6-9.6v-.9l-.2-.5-.5-.3 .1-.2a1.36 1.36 0 0 0 0-2.3l-.1-.1 .6-.5 .1-1.1-.2-.5-.5-.5 .6-.5 .1-1.1-.2-.5-.5-.4 .6-.5 .1-1.1-.2-.5-.5-.4 .1-.1a1.19 1.19 0 0 0 .5-1.6l-.1-.5-.5-.4a1.1 1.1 0 0 0 .7-.9l-.1-1-.6-.6a1.1 1.1 0 0 0 .7-1l-.1-1h3.9l.8 .6h5a.8 .8 0 0 0 .9 .1 .8 .8 0 0 0 .4-.9l-.4-.5-.3-.1-.6 .2h-4.7l-.6-.6h-1.6v-.2l.2-.4v-.5l-.2-.2-1.6-1.2h-1.2l.1-.8h7v1l.2 .4 .4 .2h1.6a.93 .93 0 0 0 .6-1l1.1 .2a.84 .84 0 0 0 .5-1.2 .85 .85 0 0 0-1.4-.2l-.7-.1h-1.9l-.4 .7h-7l-.2-.7-.4-.3 .1-.1h4.4a.78 .78 0 0 0 .7 .8 .78 .78 0 0 0 .9-.6 .78 .78 0 0 0-.6-.9h-.5l-.3 .2-.2 .5h-4.3l.4-.4v-.7h-.9h7.9l.1 .4 .5 .2h1.6l.4-.2 .2-.7h-1.1v.9h-.5v-.9h-1.2v.3h-7.8l-.1-.4h.9v-.6h7v.2h2.8v-.3l-.5-.6h-.6v.9h-.5v-.9h-.8l-.4 .7h-7l-.1-.2-.5-.3h-.4v1h-.5v-1h-.4l-.6 .4v.7h.9v.4h-.9v.7l.6 .5-.4 .3-.2 .6 .1 .9h-.8l-.3 .2-1.4 1.3h-.2l-.2-.5-.5-.3 .6-.6 .1-.4v-.8l-.2-.4-.5-.4 .2-.2-.6-.7 .3-.3 .7 .6 .1-.4-.1-1-.7 .7-.3-.4 .6-.6a1.26 1.26 0 0 0-1.5 0l.8 .6-.4 .4-.7-.7-.2 .4 .2 1 .7-.6 .4 .3-.8 .7 .3 .2-.1 .1a1.19 1.19 0 0 0-.6 1.6l.2 .5 .5 .3-.1 .2a1.19 1.19 0 0 0-.6 1.6l.2 .4 .5 .4-.6 .5-.2 .4 .1 .9-.2 .1a.42 .42 0 0 1-.5 .1 .42 .42 0 0 1-.2-.4 .86 .86 0 0 0-1.2 .3 .86 .86 0 0 0 .2 1.2h-.6l-.3-.1h-.5l-.3 .2-.2 .5h-9a1.21 1.21 0 0 0-.8-1.1l.6-.5 .2-.6-.1-.9-.7-.6 .6-.6 .2-.4v-.8l-.8-.8 .6-.3 .2-1h.4a.88 .88 0 0 0 .8 1l.1 .8 .5 .3h1.6l.5-.5 .1-1.2-.4-.5-1.3-.1-.5-.3a.82 .82 0 0 0-1.4 .5h-.4v-.4l-.6-.7 .5-.3 .1-.4h1.2l.1 .5 .5 .2 7.8-.1a.8 .8 0 0 0 .6 .9 .8 .8 0 0 0 .9-.4l.1-.6a.84 .84 0 0 0-.9-.6 .84 .84 0 0 0-.7 .7h-6.1l.3-.1 .2-.7h-1.2v.9h-.5v-.9h-1.1v.2h-1.2v-.5h-.9v-.4h2.1v.2l6.3-.2v.2a.82 .82 0 0 0 .7 .7 .82 .82 0 0 0 .9-.5v-.6l-.5-.5-.7 .1-.4 .6h-3.5l-.2-.4-.3-.3h-.7v.9h-.5v-.9l-.9 .1-.2 .6h-2.1h.9l-.1-.8-.5-.3h-.4v1h-.5v-1h-.4l-.5 .3-.1-.6-.5-.4-4.4-.9h5.5v.3l.6 .6 .6-.1 .5-.5h10.5v.3l.5 .4h1.7l.5-.4v-.5h-1.1v.9h-.5v-.9h-1.1v.2h-10.5l-.1-.6-.6-.4h7.9v.4l.4 .4 .7 .1 .3-.3 .2-.6h1.7v.3h2.7v-.5l-.2-.3-.9-.2v1h-.5v-1l-.7 .1-.4 .6h-1.7l-.3-.6-.2-.1h-.6l-.5 .4v.3l-8.1-.1-.5 .3-.3 .5h-5.5l-7-1.5h6.4a.89 .89 0 0 0 1.3 .7l.2-.2a.83 .83 0 0 0-.1-.9 .83 .83 0 0 0-.8-.3l-.5 .3-.1 .4h-6.4l-9.5-2.1h6.3l.1 .6 .3 .3 .4 .1 3.3-.1a.83 .83 0 0 0 .6 .9 .83 .83 0 0 0 1-.6l-.1-.6a.82 .82 0 0 0-1.3-.3l-.2 .6h-2.9l.4-.5v-.5l-.5-.5-.7 .1-.2 .1-.2 .4h-6.3l-4.3-.9h6.5a.81 .81 0 0 0 1 .9 .81 .81 0 0 0 .6-1.1 .86 .86 0 0 0-1.6 0v.2h-6.5l-.9-.2v-3.8h1.5a3.3 3.3 0 0 0 2.3 3.3 3.3 3.3 0 0 0 3.7-1.2h8.1v1.6l.6 .4h1.2l.4-.2 .2-.4v-1.4h.6v1.6l.6 .4h1.2l.5-.4h6.1v2.7l.4 .6h1.8l.4-.7v-1.5l.4-.4a1.01 1.01 0 0 0 .8-.8h2.1l.2 .6 .7 .3v2l.4 .4h1.7l.4-.4v-2.7h.6v.4l.5 .5 1.9-.2 .1 1.3 .5 .6h1.7l.5-.4v-.3h13.1a.83 .83 0 0 0 .6 .9 .83 .83 0 0 0 1-.6h.8l.9 1 .1 .4 .5 .3h1.5l.4-.3 .2-.3v-1.1l-.3-.5-1.8-.1-.4 .1-.7-.6h-1.9l-.7 .3-.2 .5h-13.1v-1.3l-.2-.2-.3-.2h-1.1l-.7-.7h-1.5l-.6-.2-.5 .2-.3 .5h-.6v-.5l-.3-.3h-1.9l-.2-.2h-.5l-.2 .2-.3 .6h-2.1l-.4-.7-.7-.1-.3 .3-1.8-.1-.4 .3-.2 .4h-6.1l.1-.4h1.3l.4-.2 4.3-4.3v3.2l.4 .6h1.8l.4-.8h4.2v.4l.4 .3h1.7l.4-.4v-1.3h-1v1.7h-.5v-1.7h-1v1h-4.2v-1.5l1.1-1h3.1v1h2.5v-.3h4.9l.2 .5 .4 .3-.2 .7a.89 .89 0 0 0 .5 .8 .89 .89 0 0 0 .9 0l.1-.1 .1 .4a1.28 1.28 0 0 0 1.2 .8l.7-.5 .9 .9 .3 .2 1.9 .2 .6-.5v-.5l-.4-.5 .1-.2 3.8-.1 .3 .2h.5l.6-.5-.1-.9h5.1l.5 .6 1.1 .2-.1 .2h-1l-.5 .2-.3 .6a1.67 1.67 0 0 0 .3 1.4l.5 .2h1.3l.4-.2 .3-.4v-.3h14.7v.1a.82 .82 0 0 0 .8 .8 .82 .82 0 0 0 .8-.6v-.5l-.5-.5-.6 .1-.5 .6h-14.7v-.9l2-2v-2.3h2.3v.4a.84 .84 0 0 0 1.2 .5l.3-.4 .1-.3-.2-.7 .6-.5 .1-.7a.85 .85 0 0 0-1.2-.4 .85 .85 0 0 0-.1 1.4l-.6 .3-.2 .4h-2.3v-3.9h18.7a.79 .79 0 0 0 .8 .9 .79 .79 0 0 0 .7-1.1 .77 .77 0 0 0-.9-.5 .77 .77 0 0 0-.6 .7h-18.7v-.3a.82 .82 0 0 0-.3-1.3l-.6 .1a.75 .75 0 0 0-.3 1.2v6.1l-.5 .5-1-.4 .1-.7-.6-.5-.8 .1h-9.2l-.3-.9 .6-.2 .2-.4v-.5l-.2-.3-.4-.3-1.7 .3-.9-.2-.6 .4h-.8l-.1-1.1-.3-.4a.85 .85 0 0 0-.8-.7 .85 .85 0 0 0-.9 .7 1.12 1.12 0 0 0 .8 .9v.5h-.3v-.2l-.5-.3h-.5l-.5 .5v.6a.92 .92 0 0 0-.9 .4 .92 .92 0 0 0 0 1l-.6 .4-.1 .4h-4.9v-1.1l-.6-.4h-.4v1.8h-.5v-1.8a.78 .78 0 0 0-1 .8h-3.1l1.2-1.3a.95 .95 0 0 0 1.5-.7l-.1-.1 .2-.1h1.1l.4-.5h-1v.5h-.5v-.7l.3-.1v-.2h2.7l.2-.1 .2 .1v1.1l.4 .6h2l.4-.6v-.6l1.3-1.1 .1-1.1a.92 .92 0 0 0 1.3-.5 .88 .88 0 0 0-1-.9l-1.7-.1h10.7v.2a.81 .81 0 0 0 .9 .7 .81 .81 0 0 0 .8-.9h5.7v.4a.84 .84 0 0 0 1.2 .5l.3-.5a.78 .78 0 0 0-.5-1 .78 .78 0 0 0-1 .6h-5.7v-.1a.84 .84 0 0 0-.9-.6 .84 .84 0 0 0-.8 .7h-10.8l-.1-.2-.4-.3h-1.6l-.6 .5v1.2l.3 .4-.1 .3h-.4l-.3-.3h-1.3l-.2-.6-.5-.3-2.3 .2v-.3a.86 .86 0 0 0-.7-.7 .86 .86 0 0 0-.9 .5l-.3-.2h-1.9l-.4 .5h-.6l-.1-.2a.99 .99 0 0 0-1.2 .5l.1 .6a.75 .75 0 0 0 1.1 .3h.7l.3 .4 .3 .2h1.5l.5-.4h.6v2.1l-.4 .3-.1-.8-.6-.5h-1.5l-.7 .6h-.5l-.3 .4-.2-.1a.83 .83 0 0 0-.8-.4 .83 .83 0 0 0-.7 .6v.5l.4 .6-3.8 3.8h-.9l-.3-.6-.3-.2h-1.2l-.6 .4v.4h-.6a.73 .73 0 0 0-.8-.8v-3.1h1.7a.85 .85 0 0 0 1.2 .8l.1-.1h1.2l.6 .5h1.6l.4-.3 .2-.3v-1.2l-.4-.5h-2l-.4 .5-1.9-.1-.4 .3-.2 .4h-1.7v-1.1l.6-.6 .6-.3 .2-.5h2.8l.6 .5h1.6l.4-.2 .2-.4v-1.2l-.4-.5h-2l-.4 .5h-1.7v-.7a.83 .83 0 0 0-1.1-.5 .83 .83 0 0 0-.4 1.2l-.6 .6h-.3l-.3 .6-1 1-.1 4.9-.3 .6h-8.1l.3-.5a3.3 3.3 0 0 0-.7-3.8 3.3 3.3 0 0 0-3.7-.6 3.1 3.1 0 0 0-1.9 2.8h-1.5v-4.6h13.7v.3a.84 .84 0 0 0 1.2 .5l.3-.5a.74 .74 0 0 0-.5-1h-.5l-.2 .2-.3 .5h-13.7v-4.4h6.4v.8l.4 .5-.4 1 .2 .6 .7 .5h1.4a1.2 1.2 0 0 0 .4-1.4h2.6v.3l.2 .4 .3 .2h.5a.81 .81 0 0 0 .3-1.5 .81 .81 0 0 0-1.3 .6h-2.6l-.3-.6 .3-.3h56.6v.1a.81 .81 0 0 0 .9 .8 .81 .81 0 0 0 .7-.9h13.3v.3a.87 .87 0 0 0 1.2 .4l.3-.2 .1-.5h11.3a.81 .81 0 0 0 .5 .8 .81 .81 0 0 0 1-.4h3.3v.3l.2 .4 .3 .1h.5a.81 .81 0 0 0 .3-1.3 .81 .81 0 0 0-1.3 .5h-3.3l.1-.6-.5-.5-.7 .1-.4 .6h-11.3a.81 .81 0 0 0-.8-.7 .81 .81 0 0 0-.8 .7h-13.3v-.2a.84 .84 0 0 0-.9-.5 .84 .84 0 0 0-.7 .7h-56.6l.1-1.3-.6-.5h-1.5l-.5 .3-.2 .4h-6.4v-2.3h5.1v.2a.83 .83 0 0 0 1.2 .6 .83 .83 0 0 0 .2-1.3 .83 .83 0 0 0-1.4 .2v.3h-5.1v-10.5h.4v.3a.82 .82 0 0 0 1.3 .5 .82 .82 0 0 0 0-1.4 .82 .82 0 0 0-1.3 .5l-.4 .1v-12.1h.3v.3l.5 .5a.87 .87 0 0 0 .9-.2 .87 .87 0 0 0 .1-1 .82 .82 0 0 0-.8-.3 .82 .82 0 0 0-.7 .7h-.3v-2.6h2.9v.5l.7 1a1.37 1.37 0 0 0-.1 2.4l.1 .1a1.37 1.37 0 0 0-.1 2.4l.1 .2a1.37 1.37 0 0 0-.1 2.3l.1 .2a1.37 1.37 0 0 0-.1 2.4l.1 .1-.7 .9v.7l.7 1a1.37 1.37 0 0 0-.1 2.4l.1 .1a1.38 1.38 0 0 0-.2 2.2l-.5 .6v1.9l.4 .4 2.1-.1 .3-.3v-1.9h1.6v.2a.9 .9 0 0 0 1.3 .6l.2-.3a.83 .83 0 0 0-.1-.9 .83 .83 0 0 0-.8-.3l-.5 .3-.1 .4h-1.6l-.6-.4 .2-.3a1.27 1.27 0 0 0-.4-2.1l.4-.5a1.45 1.45 0 0 0-.4-2.1l.4-.4h7.6a.81 .81 0 0 0 .6 .9 .81 .81 0 0 0 .9-.6 .81 .81 0 0 0-.5-1h-.5l-.4 .3-.1 .4h-7.6l.1-.2a1.41 1.41 0 0 0-.5-1.9 1.37 1.37 0 0 0 .8-1.3 1.37 1.37 0 0 0-.8-1.2l.4-.5a1.45 1.45 0 0 0-.4-2.1 1.37 1.37 0 0 0 .8-1.2 1.37 1.37 0 0 0-.8-1.3l.4-.5a1.45 1.45 0 0 0-.4-2.1 1.36 1.36 0 0 0 .2-2.3 1.36 1.36 0 0 0-2.2 .9h-2.9v-5.1h6.5l.4 .7 .7 .1 .5-.5v-.6l-.5-.4h-.5l-.6 .7h-6.5v-5.4h1.5a3.3 3.3 0 0 0 2.8 3.4 3.3 3.3 0 0 0 3.6-2.3h6.8v.1a1.34 1.34 0 0 0 .9 1.2 1.37 1.37 0 0 0-.9 1.3 1.37 1.37 0 0 0 .9 1.3 1.37 1.37 0 0 0-.9 1.2 1.37 1.37 0 0 0 .9 1.3 1.37 1.37 0 0 0-.9 1.3 1.37 1.37 0 0 0 .9 1.2 1.37 1.37 0 0 0-.9 1.3 1.37 1.37 0 0 0 .9 1.3 1.37 1.37 0 0 0-.9 1.2 1.37 1.37 0 0 0 .9 1.3 1.37 1.37 0 0 0-.9 1.3 1.37 1.37 0 0 0 .9 1.3 1.41 1.41 0 0 0-.8 1.2 1.41 1.41 0 0 0 .8 1.3 1.37 1.37 0 0 0-.9 1.3 1.37 1.37 0 0 0 .9 1.2 1.37 1.37 0 0 0-.9 1.3 1.37 1.37 0 0 0 .9 1.3 1.37 1.37 0 0 0-.9 1.2 1.37 1.37 0 0 0 .9 1.3 1.37 1.37 0 0 0-.9 1.3 1.37 1.37 0 0 0 .9 1.3 1.37 1.37 0 0 0-.9 1.2 1.37 1.37 0 0 0 .9 1.3 1.37 1.37 0 0 0-.9 1.3 1.37 1.37 0 0 0 .9 1.2 1.35 1.35 0 0 0-.9 1.3 1.35 1.35 0 0 0 .9 1.3h.7l.7-.4h2.2v.2a.81 .81 0 0 0 1.3 .6 .81 .81 0 0 0 0-1.4 .81 .81 0 0 0-1.3 .6h-2.1l.2-.6v-.6l-.7-1a1.33 1.33 0 0 0 .4-2.1l-.4-.3 .7-1v-.7l-.4-.7-.3-.2v-.1l.3-.2a1.29 1.29 0 0 0-.2-2.1l-.1-.3 .3-.1 .4-.7v-.7l-.4-.7-.3-.1v-.2l.3-.2a1.36 1.36 0 0 0 .4-1.6h6.1v.2a.82 .82 0 0 0 .7 .7 .82 .82 0 0 0 .9-.5v-.6l-.5-.5-.7 .1-.4 .6h-6.1l-.7-.6 .7-1v-.7h2.4a.83 .83 0 0 0 .7 .9 .83 .83 0 0 0 .9-.5l-.1-.7a.85 .85 0 0 0-.8-.3 .85 .85 0 0 0-.7 .6h-2.4l-.4-.6-.3-.2v-.2l.4-.3a1.32 1.32 0 0 0-.3-2l-.1-.2 .4-.4a1.32 1.32 0 0 0-.3-1.9l-.1-.3 .3-.1a1.28 1.28 0 0 0 .4-1.6l-.1-.2-.6-.4v-.2l.3-.2a1.28 1.28 0 0 0 .4-1.5l-.4-.5-.3-.2 .7-1v-.7l-.4-.6-.3-.2v-.2l.4-.3a1.32 1.32 0 0 0-.3-2l-.1-.2 .6-.5 .1-.4v-.7l-.7-1 .6-.5 .1-.7h12.7v.1a1.34 1.34 0 0 0 .8 1.2 1.37 1.37 0 0 0-.8 1.3 1.37 1.37 0 0 0 .8 1.3 1.37 1.37 0 0 0-.8 1.2 1.37 1.37 0 0 0 .8 1.3 1.37 1.37 0 0 0-.8 1.3 1.37 1.37 0 0 0 .8 1.2 1.37 1.37 0 0 0-.8 1.3 1.37 1.37 0 0 0 .8 1.3 1.37 1.37 0 0 0-.8 1.2 1.37 1.37 0 0 0 .8 1.3 1.37 1.37 0 0 0-.8 1.3 1.37 1.37 0 0 0 .8 1.3 1.41 1.41 0 0 0-.8 1.2 1.41 1.41 0 0 0 .8 1.3 1.37 1.37 0 0 0-.8 1.3 1.37 1.37 0 0 0 .8 1.2 1.37 1.37 0 0 0-.8 1.3 1.37 1.37 0 0 0 .8 1.3 1.37 1.37 0 0 0-.9 1.2 1.37 1.37 0 0 0 .9 1.3 1.37 1.37 0 0 0-.8 1.3 1.37 1.37 0 0 0 .8 1.3 1.37 1.37 0 0 0-.8 1.2 1.37 1.37 0 0 0 .8 1.3 1.37 1.37 0 0 0-.8 1.3 1.37 1.37 0 0 0 .8 1.2 1.35 1.35 0 0 0-.8 1.3 1.35 1.35 0 0 0 .9 1.3h2.8l.4 .7 .7 .1a.81 .81 0 0 0 .5-.7 .81 .81 0 0 0-.4-.7l-.3-.2a1.02 1.02 0 0 0-.9 .8h-2.1l.2-.1a1.18 1.18 0 0 0 .6-1.8l-.6-.7a1.33 1.33 0 0 0 .4-2.1l-.4-.3 .8-1-.1-.9-.3-.5-.4-.2v-.1l.4-.2a1.29 1.29 0 0 0-.2-2.1l-.2-.3a1.66 1.66 0 0 0 .9-1.3v-.1l2.1 2 1.3 .2a1.49 1.49 0 0 0 .7 1.9 1.41 1.41 0 0 0-.7 1.8l.7 .7-.2 .2a1.19 1.19 0 0 0-.5 1.7l.7 .6-.2 .2a1.24 1.24 0 0 0-.6 1.2 1.24 1.24 0 0 0 .8 1.1l.8 .1 .6-.3a1.28 1.28 0 0 0 .3-1.5l-.3-.5-.4-.2 .1-.1a1.31 1.31 0 0 0 .1-2.3l-.2-.3 .4-.2 .4-.6-.1-.9-.3-.5-.4-.2v-.1l.4-.2a1.28 1.28 0 0 0 .3-1.5l-.1-.3 1.4-1 .1-.2v-.6l-.5-.5h-.5l-.2 .2-.4-.5h6.6l.2 .6 .3 .2h.6l.5-.6h3.5l.1 .1-.5 .5v.6l.3 .3 .5 .2 1 1a1.43 1.43 0 0 0 .7 1.8 1.41 1.41 0 0 0-.7 1.8l.7 .7-.2 .2a1.19 1.19 0 0 0-.5 1.7l.7 .6-.2 .2a1.24 1.24 0 0 0-.7 1.2 1.24 1.24 0 0 0 .9 1.1l.7 .1a1.16 1.16 0 0 0 1-1.2h.3v.3a.86 .86 0 0 0 1.3 .5l.2-.3a.83 .83 0 0 0-.1-.9 .83 .83 0 0 0-.8-.3l-.4 .3-.2 .4h-.3l-.1-.8-.6-.5v-.1a1.33 1.33 0 0 0 .4-2.1l-.4-.3 .7-1v-.7l-.1-.3-.6-.6v-.1l.3-.2a1.28 1.28 0 0 0 .3-1.5l3.3-.1a1.66 1.66 0 0 0 .8 1.9 1.41 1.41 0 0 0-.7 1.8l.7 .7-.2 .2a1.19 1.19 0 0 0-.5 1.7l.7 .6-.2 .2a1.24 1.24 0 0 0-.6 1.2 1.24 1.24 0 0 0 .8 1.1l.8 .1a1.21 1.21 0 0 0 1-1v-.6l-.2-.4-.6-.5 .3-.3h11.2v.3a.82 .82 0 0 0 1.3 .4 .82 .82 0 0 0-.3-1.4h-.5l-.3 .2-.2 .5h-11.2l.5-.7v-.4h6.6v.2a.8 .8 0 0 0 1.2 .4 .8 .8 0 0 0 0-1.3 .8 .8 0 0 0-1.2 .7h-6.6l-.3-.8-.5-.3 .8-1v-.7l-.8-1h11.8v.3a.82 .82 0 0 0 1.2 .5 .82 .82 0 0 0 .1-1.3l-.5-.3-.6 .3-.2 .5h-11.8l.5-.4 .3-.5v-.9h.5l.9 .9 .2 .5 .3 .3h.5l.6-.5v-.7l-.7-.4-1.2-1.2-1.2-.2v-1.2l-.7-.6 .8-1.1-.1-.8 9.4 .1a.96 .96 0 0 0 1.3 .7l.3 .5-.2 .5v2.9l-.5 .4h-.2a.81 .81 0 0 0-.5 1.3 .81 .81 0 0 0 1.4-.3l.9-.9 .1-.5h.8l.2 .2a1.35 1.35 0 0 0 .6 2 1.41 1.41 0 0 0-.7 1.8l.7 .7-.2 .2a1.19 1.19 0 0 0-.5 1.7l.7 .6-.2 .2a1.24 1.24 0 0 0-.7 1.2 1.24 1.24 0 0 0 .9 1.1l.7 .1a1.21 1.21 0 0 0 1-1v-.6l-.1-.4-.6-.5 .2-.3a1.24 1.24 0 0 0-.1-2.1l-.1-.3 .5-.3 .2-.5v-.7l-.2-.5-.5-.4 .7-1-.1-1.1h3.7a1.42 1.42 0 0 0 .7 2.1 1.37 1.37 0 0 0-.9 1.2 1.37 1.37 0 0 0 .9 1.3 1.37 1.37 0 0 0-.9 1.3 1.37 1.37 0 0 0 .9 1.2 1.35 1.35 0 0 0-.9 1.3 1.35 1.35 0 0 0 .9 1.3h.7l.6-.3 .4-.7v-.6l-.7-1a1.33 1.33 0 0 0 .4-2.1l-.4-.3 .7-1v-.7l-.4-.7-.3-.2v-.1l.3-.2a1.54 1.54 0 0 0 .4-1.4l.4 .2a.9 .9 0 0 0 1.3 .6l.2-.2a.88 .88 0 0 0-.7-1.3l-1.2-1v-.8l-.4-.7-.3-.1v-.2l.3-.2a1.29 1.29 0 0 0-.2-2.1l-.1-.2 .3-.2a1.28 1.28 0 0 0 .4-1.5l-.4-.5-.3-.2v-.2l.3-.2a1.29 1.29 0 0 0-.2-2.1l-.1-.2 .4-.4a1.32 1.32 0 0 0-.3-1.9l-.1-.3 .3-.1a1.28 1.28 0 0 0 .4-1.6l-.1-.2-.6-.4v-.2l.3-.2a1.28 1.28 0 0 0 .4-1.5l-.4-.5-.3-.2 .7-1v-.7l-.4-.6-.3-.2v-.2l.4-.3a1.32 1.32 0 0 0-.3-2l-.1-.2 .6-.5 .1-.4v-.7l-.7-1 .6-.5 .1-.7h12.7v.1a1.34 1.34 0 0 0 .8 1.2 1.37 1.37 0 0 0-.8 1.3 1.37 1.37 0 0 0 .8 1.3 1.37 1.37 0 0 0-.8 1.2 1.37 1.37 0 0 0 .8 1.3 1.37 1.37 0 0 0-.8 1.3 1.37 1.37 0 0 0 .8 1.2 1.37 1.37 0 0 0-.8 1.3 1.37 1.37 0 0 0 .8 1.3 1.37 1.37 0 0 0-.8 1.2 1.37 1.37 0 0 0 .8 1.3 1.37 1.37 0 0 0-.8 1.3 1.37 1.37 0 0 0 .8 1.3 1.41 1.41 0 0 0-.8 1.2 1.41 1.41 0 0 0 .8 1.3 1.37 1.37 0 0 0-.8 1.3 1.37 1.37 0 0 0 .8 1.2 1.37 1.37 0 0 0-.8 1.3 1.37 1.37 0 0 0 .8 1.3 1.37 1.37 0 0 0-.9 1.2 1.37 1.37 0 0 0 .9 1.3 1.37 1.37 0 0 0-.8 1.3 1.37 1.37 0 0 0 .8 1.3 1.37 1.37 0 0 0-.8 1.2 1.37 1.37 0 0 0 .8 1.3 1.37 1.37 0 0 0-.8 1.3 1.37 1.37 0 0 0 .8 1.2 1.35 1.35 0 0 0-.8 1.3 1.35 1.35 0 0 0 .9 1.3l.9-.1 .5-.4h8.2v.3a.81 .81 0 0 0 .7 .5 .81 .81 0 0 0 .8-.4 .77 .77 0 0 0-.5-1.1 .77 .77 0 0 0-1 .7h-8.2l.3-.5v-.6l-.8-1 .3-.2h1.9l.1 .4 .3 .3 .7 .1 .5-.5v-.6a.84 .84 0 0 0-.9-.5 .84 .84 0 0 0-.7 .8h-1.8a1.36 1.36 0 0 0-.1-2.1h2.5v.1a.9 .9 0 0 0 1.4 .6l.2-.4v-.5l-.5-.5-.7 .1-.2 .1-.2 .5h-2.7l-.1-.3 .6-.5 .2-.7h5.2a.82 .82 0 0 0 .7 .9 .82 .82 0 0 0 .9-.5v-.6h1.5l.1 .6a.78 .78 0 0 0 1.1 .1h.5v.7l.5 .5h.5l.4-.3 .3 .2-.2 .5v.5l.2 .2-.2 .5v.5l.2 .3-.2 1 .2 .4-.2 .9h-.3a.9 .9 0 0 0-.6 1.3l.4 .3h.6v1.1l.3 .3h.4l.1 .4 .6 .9a.86 .86 0 0 0 1.4-.7 .65 .65 0 0 1 .1-1.1v-.2a.83 .83 0 0 0 1.4-.2 .83 .83 0 0 0-.5-1.2l-.9 .1v-.3l.4-.1 .5-.5v-.5l-.2-.3 .2-.3v-.5l-.3-.6a.68 .68 0 0 0-.6-1l-.1-.4h1.4l.7 .8v.3l.2 .2-.2 .2v.9l.2 .1-.2 .3v.8l.2 .2-.2 .3v.8l.2 .2-.2 .2v.9l.5 .3a.9 .9 0 0 0 .5 .9 .9 .9 0 0 0 1-.2l.2-.6 .5-.2 2.9-.1 .1 .1a.99 .99 0 0 0 1.2-.5v-.5l-.1-.2-.6-.3 .1-.9a1.07 1.07 0 0 0-1.6-.3l-.1-.2-.5-.3-.6-.6 2.8-.1 .5 .6h.6a.74 .74 0 0 0 .6-.8 .74 .74 0 0 0-.6-.7h2.6l.1 .6 .4 .3 .9-.1a1.33 1.33 0 0 0 .7 1.2h.1l-.3 .3a1.26 1.26 0 0 0 .2 2.2l.1 .1-.3 .2a1.31 1.31 0 0 0 .2 2.2l.1 .1a1.38 1.38 0 0 0-.8 1.2 1.38 1.38 0 0 0 .7 1.3l.1 .1-.3 .2h-.2v-.1a.83 .83 0 0 0-1.4-.5 .83 .83 0 0 0 .3 1.4l.8-.1a1.43 1.43 0 0 0 .7 1.5l.1 .1-.3 .3a1.26 1.26 0 0 0 .2 2.2h.1l-.3 .3a1.26 1.26 0 0 0 .2 2.2l.1 .1-.3 .2a1.26 1.26 0 0 0 .2 2.2l.1 .1-.3 .3a1.26 1.26 0 0 0 .2 2.2l.1 .1-.6 .5a1.54 1.54 0 0 0 .2 1.8h-.1a.86 .86 0 0 0-1.1 .7 .74 .74 0 0 0 .8 .9l.2 .6 .6 .5a1.38 1.38 0 0 0-.8 1.2 1.38 1.38 0 0 0 .7 1.3l.1 .1-.3 .2a1.31 1.31 0 0 0-.2 1.8 1.31 1.31 0 0 0 1.8 .4l.5-.6a1.41 1.41 0 0 0 2 .6 1.27 1.27 0 0 0 .7-1.2 1.27 1.27 0 0 0-.7-1.1v-.3l.2-.2a.86 .86 0 0 0 1.2 .3 .86 .86 0 0 0 .3-1.2l-.4-.2h-.6l-.2-.5-.5-.5 .1-.2a1.34 1.34 0 0 0-.1-2.3l.1-.3a1.37 1.37 0 0 0 .2-2h.7v.2a.9 .9 0 0 0 1.4 .6l.2-.5v-.5l-.5-.5-.7 .1-.2 .2-.2 .4-.8-.1-.2-.4a1.27 1.27 0 0 0 .7-1.1 1.27 1.27 0 0 0-.7-1.2l.1-.2a1.34 1.34 0 0 0-.1-2.3l.1-.3a1.34 1.34 0 0 0-.1-2.3l.1-.2a1.34 1.34 0 0 0-.1-2.3v-.3l.7-.7 .1-.8a.78 .78 0 0 0 .6-.7 .78 .78 0 0 0-.6-.8l-.2-.2 .1-.7-.2-.5-.5-.4 .1-.2a1.34 1.34 0 0 0-.1-2.3v-.3l.7-.7v-.7l.6-.1 .3-.3v-.8a.89 .89 0 0 0-1-.5l.1-.9-.2-.4-.5-.4 .1-.3-.6-.6h.2l.1-.4 .6 .7 .1-.1a1.39 1.39 0 0 0 0-1.4l-.7 .6-.3-.4 .6-.6-.2-.1 .2-.2-.6-.7h.2l.1-.3 .6 .7 .1-.1a1.39 1.39 0 0 0 0-1.5l-.7 .6-.3-.3 .6-.6-.2-.2 .2-.1-.6-.7h.2l.1-.4 .6 .7 .1-.1a1.39 1.39 0 0 0 0-1.4l-.7 .6-.3-.4 .6-.5-.1-.4a1.35 1.35 0 0 0 .3-2 1.35 1.35 0 0 0-2.1 .1l-.7-.5h-1.5l-.4 .2-.2 .4v1.5l.3 .4 .2 .1v.2a1.26 1.26 0 0 0 .2 2.2l.1 .1-.6 .5a1.36 1.36 0 0 0 .5 1.9l.1 .2-.4 .3a1.24 1.24 0 0 0 .1 2l.3 .2-.4 .4-.3-.1a.77 .77 0 0 0-.8-.5 .77 .77 0 0 0-.7 .7h-2.6l-.5-.2-2.5-.1a1.01 1.01 0 0 0-.9-.9l-.3-.3-.4-.1 .1-2.9-4.9-.2v-.3h3.2v-.6h-.7l-.4 .3-.1 .3h-2l-.6-.6h-1.8l-.4 .3-1.1 .1h-1.1v-.2l-.5-.1-.3 .1-.3 .3-.1 .4h-1.5l-.5-.4h-.5l-.6 .6h-5.2l-.2-.6-.6-.6v-.1l.4-.2a1.44 1.44 0 0 0 .3-1.5h1.6l.3 .7a.86 .86 0 0 0 .9 0 .86 .86 0 0 0 .4-.8h10.3v.3a.82 .82 0 0 0 1.1 .5 .82 .82 0 0 0 .5-1.1 .86 .86 0 0 0-1.6 .1v.2h-10.3a.81 .81 0 0 0-.8-.7 .81 .81 0 0 0-.8 .8h-1.6l-.3-.5-.4-.2v-.2l.4-.1a1.28 1.28 0 0 0 .3-1.6l-.7-.8 .6-.5h.3a.82 .82 0 0 0 .8-.7 .82 .82 0 0 0-.6-.9l-.6 .1-.5-.4v-.1l.6-.6 .2-.8 .1-.1 3.1 3.1 1.4 .1 .2 .4v.9l-1-.1a.97 .97 0 0 0-1.4 .4l-.3-.1a.79 .79 0 0 0-.9 .6 .79 .79 0 0 0 .5 .9 .79 .79 0 0 0 1-.5h2.1l.3 .3h1.4l.5 .4h3v.3l.2 .3 .3 .2 .6-.1a.78 .78 0 0 0 .1-1.3 .78 .78 0 0 0-1.2 .6h-1.5l2.7-2.7h.3l-.2 .3v.5l.2 .3 .3 .2 .8-.1 .2 .6 .5 .3h1.1l.5-.3 .1-.4h.8l.2 .4 .4 .3h1.1l.6-.5v-.7h-.8v1.2h-.6v-1.2h-.9v.5h-.8v-1.7l-.3-.3 .1-.1 1.3 .1-.3 .5v.5h2.3v-.7l-.3-.3 .1-.1h1.6l.8-.7 .5 .2-.2 .3a.86 .86 0 0 0-1 .8 1.64 1.64 0 0 0 .4 1.5v.8l-.3 .5-.1 .7-.7 .6a.83 .83 0 0 0-1.1 .4 .83 .83 0 0 0 .5 1.1l-.1 .7h1.2l-.1-.3-.4-.3 .4-.7 .7 .1 .4-.1 .2-.3h.5v.5a1.15 1.15 0 0 0 .1 1.2 .84 .84 0 0 0-1 .9 .84 .84 0 0 0 1.2 .7 .84 .84 0 0 0 .2-1.4l.1-.2a.82 .82 0 0 0 .7-.4 .82 .82 0 0 0-.1-1v-.2l.3-.2 .7 .1 .4-.2 .2 .2-.1 .3a.88 .88 0 0 0 1.4 .5l.2-.6h.5a.83 .83 0 0 0 .6 .8 .83 .83 0 0 0 1-.5l-.1-.5a.79 .79 0 0 0-.8-.6 .79 .79 0 0 0-.7 .6v.2h-.5l-.2-.5-.3-.3-.6 .1v-.9l1.3-1.4 .3-.7v-.6l.7 .1 .6-.4 .1-.7-.3-.3h5.6l.2 .6a.84 .84 0 0 0 1.4-.3v-.5l-.5-.6-.7 .1-.4 .7h-5.6l-.7-.2-.4 .3v-1.1a.81 .81 0 0 0-.3-1.1 .81 .81 0 0 0-1.2 .3h-.1l-.1-.6-.3-.4h4.3v.3a.8 .8 0 0 0 1.1 .5 .8 .8 0 0 0 .3-1.2 .8 .8 0 0 0-1.3 0l-.1 .4h-4.3l-.4-.2a.84 .84 0 0 0-.5-1 .84 .84 0 0 0-1.1 .5l-.1 .4h-.6l.1-.6a.84 .84 0 0 0-1.2-.5l-.3 .3-.1 .4-1.3 1.2-.2-.1-.4-.7-1.6 .1-.3 .4-.1 1.5h-.6l-.1-.1v-.2h-1.2v-.3h-.2v-.3h1.4v-.5l-.5-.6h-.4v1.1h-.5v-1.1l-.7 .1-.3 .8-.9-.2v-.9l1.9-1.9h.6l.8-.7h.2v1.2h-.2a.8 .8 0 0 0-.4 .9 .8 .8 0 0 0 .6 .7 .86 .86 0 0 0 .9-1l.5-.4h.9l.4-.3 2.3 .1 .4 .2h1.9l.4-.2 .1-.6h.3l.6 .6v.3a.83 .83 0 0 0 .1 1.1 .83 .83 0 0 0 1.2 0 .83 .83 0 0 0-.1-1.2v-.8l-1-.9h4.8a1.82 1.82 0 0 0 1.4 1.8 1.87 1.87 0 0 0 1.9-.6 1.8 1.8 0 0 0-.1-2.5l-.5-.2h1.5v.3l.5 .5 .7-.1a.8 .8 0 0 0 0-1.3 .8 .8 0 0 0-1.2 .6l-1.6-.1a1.93 1.93 0 0 0-2.6 1.6h-4.8l-.3-.3-.8-.1v-.4l-.2-.2 .2-.3-.1-1h1.4a.82 .82 0 0 0 1 .3 .82 .82 0 0 0 .4-1l-.3-.5 .4-.5h3.1a1.85 1.85 0 0 0 2.3 1.9 1.85 1.85 0 0 0 1.2-2.7l-.3-.4a2.14 2.14 0 0 0-2.7 0l-.4 .7-.1 .5h-3.1v-.5l-.2-.2a.78 .78 0 0 0-1.1-.1h-1.5v-1.1l-.2-.3 .2-.1h.5l.1 .4 .3 .2h1.9l.3-.2 .2-.6h-1.2v.8h-.5v-.8h-1.1v.2h-.5v-.2h-1.4v-.3h-.3v-.2h1.7l-.1-.3h.6v.3h2.8l-.2-.7-.4-.2h-.6v.9h-.5v-.9h-.5l-.5 .2-.1 .4h-.6l-.2-.2h-.9v.5h-.5v-.5h-.7v-1.4l.4-.5h.6l.3-.3 .1-.6 .2 .1v1a.78 .78 0 0 0 0 1.1 .78 .78 0 0 0 1.1 0h6.6v.5l-1 .1a1.6 1.6 0 0 0 1.6 1.4v-.8h.5v.8l.3-.1a1.64 1.64 0 0 0 1.3-1.4h-1v-.5h1v-.4h.5v.2a.82 .82 0 0 0 .7 .8 .82 .82 0 0 0 .9-.6v-.5l-.5-.5h-.5l-.6 .6h-.5l-.5-.6-.8-.5h-.3v.9h-.5v-.9a1.8 1.8 0 0 0-1.6 1.5h-5.6l.4-.8 2.1 .1 .3-.2 .2-.5v-.9l-.2-.3 .2-1.2h2.6v.5a2.01 2.01 0 0 0 1.4 1.3 1.87 1.87 0 0 0 1.9-.6 1.76 1.76 0 0 0-.9-2.8 1.87 1.87 0 0 0-2 .6l-.4 1-2.6-.1a.84 .84 0 0 0-1.2-.5l-.4 .5 .2 .9-1.1 .1-.1-.7-.5-.2h-1.2l-.1-.6-.3-.3v-1.5h3.9a.82 .82 0 0 0 .5 .8h.7a.78 .78 0 0 0 .4-1.1l-.6-.4a.72 .72 0 0 0-1 .7h-3.9v-.9l.3-.5v-.6h3.6a.8 .8 0 0 0 .6 .8 .8 .8 0 0 0 1-.4h1.8v.5a2.01 2.01 0 0 0 1.4 1.4 1.87 1.87 0 0 0 1.9-.6 1.66 1.66 0 0 0 .2-2.2h-.1h.8a.79 .79 0 0 0 .8 .9 .79 .79 0 0 0 .7-1l-.1-.4-.2-.1-.7-.1-.4 .2-.1 .5h-.8a1.95 1.95 0 0 0-3.3 .5l-.1 .4h-1.8v-.2a.89 .89 0 0 0-.4-.8 .89 .89 0 0 0-.9 0l-.3 .6h-3.6l-.1-1-.5-.4v-1.4l.4-.3 .2-.3v-1.6h4.6v.1a1.09 1.09 0 0 0 .8 1 1.09 1.09 0 0 0 1.2-.5h.4v2.3l.3 .3 3 .1 .4-.3v-2.7l-.2-.3-3.1-.1-.3 .2-.1 .5-.4-.1a1.06 1.06 0 0 0-.7-1.5 1.06 1.06 0 0 0-1.3 1h-4.6l-.2-.4-.4-.2h-1.2l-.4 .2-.2 .4v1.6l.2 .3 .4 .3v1.4l-.4 .3-.2 .4v1.3l.2 .5 .8 .3v2h-.6l-.4 .3h-2.3v.9h.7v.2l-.6 .6h-1.2v-.8h.6v-1.4h1.6l-.2-.8-.2-.1h-.7v.9h-.5v-.9h-.3l-.1-.2 .8-.8h1.1l.3-.1 .3-.5v-1.5l-.3-.4-.3-.2h-1.1l-.4 .2-.2 .2v1.3l-1.6 1.6 .1 6.3-.3 .2 .1 1.9-1.7 .2-.1-.3-.3-.1v-.1h1.7a.78 .78 0 0 0-.6-1h-.5v1h-.6v-1h-.5l-.5 .3-.1 .3-2.5-.1v-.2h1.7l-.1-.4-.4-.2h-.7v.6h-.5v-.6h-.7a.93 .93 0 0 0-.6 .8h-1.3l-.6-.6-.6-.2h-1.9l-.4 .2-.1 1.1 .2 .2-.2 .2v.8l.2 .3-.2 .2v.8l.2 .3-.2 .1v.9l.2 .1a.72 .72 0 0 1-.7 .7l-.4 .4v.5l.3 .5 .5 .1-.4 .6v1.6l.3 .5a1.09 1.09 0 0 1 .7 .9l.3 .3h.5l.4-.3 .2-.5h.2a.85 .85 0 0 0 .8 .2 .85 .85 0 0 0 .6-.7l.3-.5 .1-.5 1 .9v1.4l-.7 .6-.2-.1a.78 .78 0 0 0-1.1 .4l-.7-.4h-.7l-.4-.2h-.4l-.7 .5-2.3-2.3v-.2a.82 .82 0 0 0 .8-.4 .82 .82 0 0 0-.2-.9l-.4-.3h-.4l-.5 .3-.4-.7-.4-.2v-.1l.4-.4a1.32 1.32 0 0 0-.2-1.9l-.2-.3 .6-.5 .2-.3v-.6h1.1v.3a.81 .81 0 0 0 .7 .5 .81 .81 0 0 0 .7-.4 .77 .77 0 0 0-.4-1.1 .77 .77 0 0 0-1 .7h-1.1l-.2-.5-.6-.4 .8-1.1-.1-.8-.3-.5-.4-.2v-.1l.6-.6 .2-.5h8.6l.2 .4 .4 .2h.3v-1.2h-.9v.6h-8.6l-.2-.8-.6-.6h6.2a.81 .81 0 0 0 .9 .9 .81 .81 0 0 0 .7-1h1.6v.4h.9v-1.1h.6v2.8l.5-.1a.74 .74 0 0 0 .4-.9h.7l.2 .8 .4 .2h1.2l.4-.2 .2-.4v-1.6l-.2-.3-.4-.3h-1.2l-.4 .3-.8 .1h-.3l-.4-.4h-1.2l-.4 .3-.2 .4h-1.6a.81 .81 0 0 0-1.2-.6l-.3 .4-.1 .3h-6.2l.4-.3a1.28 1.28 0 0 0 .3-1.5l-.1-.1h1.4a.83 .83 0 0 0 .6 .9 .83 .83 0 0 0 1-.5l-.1-.6h6.1v.3a.88 .88 0 0 0 1.3 .4l.3-.4v-.5a.84 .84 0 0 0-.9-.5 .84 .84 0 0 0-.7 .7h-6.1l-.1-.2a.84 .84 0 0 0-.8-.2 .84 .84 0 0 0-.6 .6h-1.4l-.2-.4-.4-.2v-.1l.6-.5 .2-.8h11.5v.2a.9 .9 0 0 0 1.3 .6 .83 .83 0 0 0-.1-1.4 .83 .83 0 0 0-1.2 .6h-11.5l-.2-.6-.6-.5 .8-1-.1-.8h.4l.1 1.4 .5 .2h1.6l.4-.2 .2-.4v-1.1l-.2-.3-.4-.3h2.9v.6a3.3 3.3 0 0 0 3.8 2.8 3.3 3.3 0 0 0 2.7-2.4h2.6l.2 .7a.86 .86 0 0 0 .9 0 .86 .86 0 0 0 .5-.8l-.5-.6-.6-.1-.4 .3-.1 .5h-2.6l.1-1-.3-1.2h3.4v.3a.84 .84 0 0 0 1.2 .5l.4-.3v-.6l1.6 .1 .4-.3 .2-.3v-1.6l-.5-.5-1.3-.1-.4 .2-.2 .4v.7l-1.2 1.1-.2 .4h-3.4l-.2-.3a2.8 2.8 0 0 0-2-1.5h4.8l.2 .6 .3 .2h.7a1.04 1.04 0 0 0 .3-1.1l-.5-.4a.72 .72 0 0 0-1 .7l-5.1-.1a3.4 3.4 0 0 0-3.8 3.1h-2.9l-.2-.7 .4-.2a.7 .7 0 0 0 .4-.8h-2.8l.1 .6 .6 .3 .1 .3-.2 .5-.5 .3-.1 .4h-.4l-.3-.6-.4-.1 .2-.3-.7-.7 .3-.1v-.3l.7 .8 .3-.5v-.6l-.3-.5-.7 .7v-.2l-.3-.1 .6-.6h1v.2h1.1v-.9h-.5l-.5 .3-.1 .4h-1l.1-.1a1.39 1.39 0 0 0-1.5 0l.7 .7-.1 .1-.2 .2-.7-.7a1.26 1.26 0 0 0 0 1.6l.7-.8 .3 .4-.7 .7 .3 .2-.8 .7v.5h-12.7v-.3l-.6-.9a.81 .81 0 0 0 .6-1h-1v-.5h1v-.2h2v.2a.81 .81 0 0 0 .8 .7 .81 .81 0 0 0 .8-.7h5.9v.3a.81 .81 0 0 0 .7 .5 .81 .81 0 0 0 .8-.4l.1-.4-.5-.7a.81 .81 0 0 0-1.1 .7h-5.9v-.4a.81 .81 0 0 0-.8-.5 .81 .81 0 0 0-.7 .6l-2.1 .1-.2-.8-.8-.1v1h-.5v-1h-.7l-.4 .6v.5h1v.5h-1a.81 .81 0 0 0 .6 1l-.2 .4a1.32 1.32 0 0 0 .5 2.1 1.37 1.37 0 0 0-.9 1.3 1.37 1.37 0 0 0 .9 1.3 1.37 1.37 0 0 0-.9 1.2 1.37 1.37 0 0 0 .9 1.3 1.37 1.37 0 0 0-.9 1.3 1.37 1.37 0 0 0 .9 1.2 1.37 1.37 0 0 0-.9 1.3 1.37 1.37 0 0 0 .9 1.3l-.7 .7-.9-.2a.8 .8 0 0 0-1 1 .8 .8 0 0 0 1.4 .3h.5l.7 .7-.2 .2a1.31 1.31 0 0 0-.7 1.2 1.31 1.31 0 0 0 .9 1.2 1.41 1.41 0 0 0-.8 1.2 1.41 1.41 0 0 0 .8 1.3 1.48 1.48 0 0 0-.7 1.9h-3.7l.1-1-.1-.4-.6-.4v-.2l.5-.3 .2-.5v-.7a1.06 1.06 0 0 0-.7-.9l.7-1-.1-.9-.6-.6 .7-1v-.7a1.06 1.06 0 0 0-.7-.8v-.2l.3-.2a1.28 1.28 0 0 0 .3-1.5l-.6-.8 .5-.4 .2-.5v-.7l-.7-1 .5-.3 .2-.5v-.7l-.1-.4-.5-.4-.1-.2 .6-.5 .1-.4v-.7a1.06 1.06 0 0 0-.7-.8l.7-1-.1-.8h.5v1.2l.6 .4h1.6l.4-.2 .2-.4v-1.1l-.5-.6h-.4l.3-.5v-.3l.4-.3 .2-.3v-.3h-2.8l.1 .6a.92 .92 0 0 1 .5 1.1l-.5 .3-.1 .4h-.5l-.1-.4-.5-.3 .1-.3-.6-.7 .2-.1 .2-.3 .7 .8 .1-.5-.1-.9v-.2l-.7 .7-.4-.3 .6-.6h1v.2h2.8a.78 .78 0 0 0-.6-.9h-.6v.9h-.5v-.9h-.5l-.5 .3-.1 .4-1-.1a1.39 1.39 0 0 0-1.4 0l.7 .7-.4 .3-.6-.7-.2 .5a.91 .91 0 0 0 .2 1l.6-.7 .4 .4-.7 .7 .3 .2-.2 .1a1.28 1.28 0 0 0-.5 1.8l.7 .6-.2 .2a1.19 1.19 0 0 0-.5 1.7l.7 .7-.2 .1a1.19 1.19 0 0 0-.5 1.7l.7 .7a1.37 1.37 0 0 0-.9 1.3 1.37 1.37 0 0 0 .9 1.2l-.6 .5-.3 .7 .1 .2a1.45 1.45 0 0 0 .8 1.2 1.41 1.41 0 0 0-.7 1.8l.6 .5 .1 .2-.2 .2a1.19 1.19 0 0 0-.5 1.7l.7 .7-.2 .1a1.19 1.19 0 0 0-.5 1.7l.7 .7-.2 .2a1.11 1.11 0 0 0-.5 1.6l-.1 .2h-2.1l-.5 .5-.6 .3-.2 .5h-9.4l-.7-.8 .6-.6 .2-.3v-.7l-.2-.4-.6-.4v-.2l.6-.5 .2-.3v-.7a1.06 1.06 0 0 0-.8-.9l.8-1-.1-.9-.7-.6 .8-1v-.7a1.06 1.06 0 0 0-.8-.8v-.2l.4-.2a1.28 1.28 0 0 0 .3-1.5l-.7-.8 .6-.6 .2-.3v-.7l-.8-1 .6-.5 .2-.3v-.7l-.2-.4-.6-.5v-.1l.6-.5 .2-.4v-.7a1.06 1.06 0 0 0-.8-.8l.8-1v-.7l-.3-.5-.3-.3 .1-.1a.87 .87 0 0 0 .5-1h-.9v-.5h.9v-.5h2.5v.4a.77 .77 0 0 0 .8 .6 .77 .77 0 0 0 .8-.7h5.5v.3a.83 .83 0 0 0 1.3 .4 .83 .83 0 0 0 0-1.3 .83 .83 0 0 0-1.3 .4v.2h-5.5a.75 .75 0 0 0-.6-.9h-.5l-.2 .1-.3 .5h-2.5l-.3-.5-.7-.1v1h-.5v-1h-.6l-.5 .4-.5-.7-.7-.1v1.1l-.3 .1v.2h-1.3l.1 .6 .5 .4-.2 .2v.5l-.4 .5 .1 1.6 .5 .2h1.6l.7-.6 .7 .7a1.41 1.41 0 0 0-.7 1.9l.7 .7-.2 .1a1.19 1.19 0 0 0-.5 1.7l.7 .7a1.37 1.37 0 0 0-.8 1.3 1.37 1.37 0 0 0 .8 1.2l-.5 .5-.3 .7v.2a1.45 1.45 0 0 0 .8 1.2 1.41 1.41 0 0 0-.7 1.8l.6 .5 .1 .2-.2 .2a1.19 1.19 0 0 0-.5 1.7l.7 .7-.2 .1a1.19 1.19 0 0 0-.5 1.7l.7 .7-.2 .2a1.19 1.19 0 0 0-.5 1.7l.7 .6-.2 .2a1.11 1.11 0 0 0-.5 1.6l-.1 .2-3.3-.1v-1.2l-.6-.6 .7-1-.1-1.1-.6-.4v-.2l.3-.2a1.36 1.36 0 0 0 .3-1.6l-.6-.6v-.1l.4-.4a1.32 1.32 0 0 0-.3-1.9l-.1-.3 .3-.1a1.28 1.28 0 0 0 .3-1.6v-.2l-.6-.4v-.2l.6-.4 .1-.5v-.6l-.1-.4-.6-.5 .7-1-.1-.8-.3-.5-.3-.2 .7-1-.1-1-.6-.6 .1-.2a1.29 1.29 0 0 0 .2-2.1l-.3-.2v-.2l.6-.5 .1-.3v-.7l-.4-.7-.3-.1 .1-.3-.6-.7 .2-.1 .2-.3 .7 .7a1.39 1.39 0 0 0 0-1.5l-.7 .7-.4-.3 .6-.6h1v.2h1.1v-.9h-.5l-.5 .3-.1 .4h-1l-.4-.3h-.6l-.4 .2 .7 .7-.1 .1-.3 .2-.6-.7-.2 .5a.91 .91 0 0 0 .2 1l.6-.7 .4 .4-.7 .7 .3 .2-.2 .1a1.28 1.28 0 0 0-.5 1.8l.7 .6-.2 .2a1.28 1.28 0 0 0-.5 1.8l.7 .6-.2 .1a1.28 1.28 0 0 0-.5 1.8l.7 .6a1.37 1.37 0 0 0-.9 1.3 1.37 1.37 0 0 0 .9 1.2l-.6 .5-.3 .6a1.56 1.56 0 0 0 .9 1.5 1.41 1.41 0 0 0-.7 1.8l.6 .5 .1 .2-.2 .2a1.19 1.19 0 0 0-.5 1.7l.7 .7-.2 .1a1.19 1.19 0 0 0-.5 1.7l.7 .7-.2 .2a1.19 1.19 0 0 0-.5 1.7l.7 .6-.2 .2a1.19 1.19 0 0 0-.5 1.7l-5.4 .1-.3 .2-.4 .1-.4 .7h-6.6l-.5-.3v-.2l.3-.1a1.28 1.28 0 0 0 .2-1.9l-.5-.4v-.1l.4-.2 .4-.7v-.7l-.2-.4-.6-.4v-.2l.5-.4h9.1v.2a.8 .8 0 0 0 1.2 .6 .8 .8 0 0 0 0-1.4 .8 .8 0 0 0-1.2 .6h-9.1l.3-.4v-.7l-.2-.4-.6-.5v-.1l.5-.4a1.32 1.32 0 0 0-.3-1.9l-.2-.3 .4-.1a1.28 1.28 0 0 0 .3-1.6l-.7-.8 .6-.4 .2-1.1-.8-1 .4-.2 .4-.7v-.7l-.8-1 7.5-.1v.3a.83 .83 0 0 0 1.3 .5 .83 .83 0 0 0 0-1.4 .83 .83 0 0 0-1.3 .5v.1h-7.2l.1-.1a1.36 1.36 0 0 0 .3-1.6l-.7-.6 .3-.3h10.9a.83 .83 0 0 0 .7 .9 .83 .83 0 0 0 .9-.6l-.1-.6a.85 .85 0 0 0-.8-.4 .85 .85 0 0 0-.7 .7h-10.8a1.29 1.29 0 0 0-.2-2.1l-.2-.3 .4-.1a1.28 1.28 0 0 0 .3-1.6l-.5-.7 .4-.3 .2-.7h-.9v-.5h.9v-.3h1.8a.82 .82 0 0 0 .5 .8h.7l.3-.5h6.4l.2 .6 .4 .3h.5l.5-.5v-.7a.92 .92 0 0 0-1.1-.3l-.4 .3-.1 .3h-6.4a.86 .86 0 0 0-.7-1.1 .73 .73 0 0 0-.8 .8h-1.8l-.3-.7-.7-.1v1h-.5v-1l-.8 .1-.2 .4-.1 .6h1v.5h-1l.1 .6 .5 .4v.1a1.43 1.43 0 0 0 .2 2.4 1.48 1.48 0 0 0-.7 2l.7 .6-.2 .1a1.28 1.28 0 0 0-.5 1.8l.7 .6a1.37 1.37 0 0 0-.8 1.3 1.37 1.37 0 0 0 .8 1.2l-.5 .5-.3 .6a1.56 1.56 0 0 0 .8 1.5 1.41 1.41 0 0 0-.7 1.8l.6 .5 .1 .2-.2 .2a1.19 1.19 0 0 0-.5 1.7l.7 .7-.2 .1a1.19 1.19 0 0 0-.5 1.7l.7 .7-.2 .2a1.19 1.19 0 0 0-.5 1.7l.7 .6-.2 .2a1.19 1.19 0 0 0-.5 1.7l.7 .7-.2 .1a1.6 1.6 0 0 0-.5 1.7l-.1 .1h-.6l-2.8-2.8-.1-1-.7-.6 .8-1-.1-.8-.3-.5-.4-.2v-.2l.4-.3a1.32 1.32 0 0 0-.2-2l-.2-.2 .4-.4a1.32 1.32 0 0 0-.2-1.9l-.2-.3 .4-.1a1.28 1.28 0 0 0 .3-1.6l-.3-.5-.4-.1v-.2l.4-.2a1.28 1.28 0 0 0 .3-1.5l-.3-.5-.4-.2 .8-1-.1-.8-.3-.5-.4-.2v-.2l.4-.3a1.32 1.32 0 0 0-.2-2l-.2-.2 .4-.2 .4-.7-.1-.8-.3-.5-.4-.2v-.2l.4-.1a1.31 1.31 0 0 0 .3-1.4l.4-.1 .1 1.4 .5 .2 1.8-.1 .4-.5v-1.1l-.4-.6h-.3l.1-.8 .2-.1a.7 .7 0 0 0 .4-.8h-2.8l.1 .6 .5 .4-.6 1.4h-.4l-.3-.6-.4-.1 .2-.3-.7-.7 .3-.1v-.3l.7 .8 .3-.5v-.6l-.3-.5-.7 .7v-.2l-.3-.1 .6-.6h1v.2h2.8a.78 .78 0 0 0-.6-.9h-.6v.9h-.5v-.9h-.5l-.5 .3-.1 .4h-1l.1-.1a1.39 1.39 0 0 0-1.5 0l.7 .7-.1 .1-.2 .2-.7-.7a1.26 1.26 0 0 0 0 1.6l.7-.8 .3 .4-.7 .7 .3 .2-.8 .7v.5h-12.7l-.1-.6-.5-.5 .6-.8h1.6l.5 .8h.6l.6-.5v-.4h5.5l.4 .8 .7 .1a.81 .81 0 0 0 .4-.7 .81 .81 0 0 0-.4-.8l-.2-.1a1.02 1.02 0 0 0-.9 .7l-5.5-.1a.82 .82 0 0 0-.9-.6 .82 .82 0 0 0-.8 .8h-1.6v-.3h-1v-.5h1v-.7l-.4-.4h-.6v1h-.5v-1h-.7l-.4 .6v.5h1v.5h-1a.81 .81 0 0 0 .6 1l-.5 .7-.1 .5h-6.8l.1-.1a3.4 3.4 0 0 0-2.8-4.1 3.2 3.2 0 0 0-3.7 3.1h-1.5v-3.6l.2-.1 .4 .4h.5l.4-.2 .2-.3v-.5l-.5-.5z"/>
</g>
<g fill="none" stroke="#d91c2b" stroke-width=".21">
<path d="M67.8 41.5h.4v.5h-.4zM68 58.7h.4v.5h-.4zM68.4 48.1h.4v.5h-.4zM69.2 51.7h.4v.4h-.4zM74.3 51h.4v.4h-.4zM76 41.8h.4v.4h-.4zM77.1 57.6h.4v.4h-.4zM77.7 44.4h.4v.4h-.4zM78.3 41.1h.4v.4h-.4zM85.2 46.4h.4v.5h-.4zM85.5 55.6h.4v.4h-.4zM86.7 44.8h.5v.5h-.5z"/>
<path d="M90.5 56.3h.4v.5h-.4zM91.9 41.1h.4v.4h-.4zM93.9 44.7h.4v.5h-.4zM95.7 46.3h.4v.5h-.4zM101 46.1l.4 .4M101.2 45h.4v.4h-.4zM101.3 46.6l.1 .3M101.3 46.3v.5M101.4 45.2l-.4 .4v.9M105.6 41.8h.4v.4h-.4zM107.5 47.4h.4v.4h-.4zM108.1 43.7h.4v.5h-.4z"/>
<path d="M111.9 49.1h.4v.4h-.4zM113.1 52.9h.4v.4h-.4zM115.3 51h.4v.4h-.4zM116.1 44.1h.4v.4h-.4zM116.6 47.6h.4v.5h-.4zM116.8 50.3h.4v.5h-.4zM117.4 41.1h.4v.4h-.4zM122.3 50h.4v.4h-.4zM122.3 46.1l.4 .3M122.5 45h.4v.4h-.4zM122.6 57.8h.5v.4h-.5zM122.7 45.2l-.4 .4v1l.4 .3"/>
<path d="M127.5 41.6h.4v.4h-.4zM127.6 46.5h.5v.5h-.5zM128 50h.4v.4h-.4zM128.7 52.5h.5v.5h-.5zM128.8 57h.4v.5h-.4zM129.8 43.6h.5v.4h-.5zM137 43.8h.4v.4h-.4zM137.8 58.8h.4v.4h-.4zM137.9 41.8h.4v.4h-.4zM138.1 46.9h.4v.5h-.4zM138.3 53.6h.4v.5h-.4zM143.5 43.6h.4v.5h-.4z"/>
<path d="M143.6 44.8h.4v.5h-.4zM143.8 45l-.1 1.9M144.3 59.4h.4v.4h-.4zM144.5 59.6h2.2M144.6 41h.4v.5h-.4zM149.1 49.8h.5v.5h-.5zM149.2 41.9h.4v.4h-.4zM150.6 43.8h.4v.4h-.4zM152.9 54h.4v.5h-.4zM154.8 59.4h.4v.4h-.4zM158 44h.4v.4h-.4zM159.1 41h.4v.5h-.4z"/>
<path d="M159.1 54.3h.4v.4h-.4zM159.5 46.2h.4v.4h-.4zM164.7 45.5h.4v.4h-.4zM164.9 59.2h.4v.5h-.4zM164.9 45.7v1.2M165.1 51.3h.4v.4h-.4zM165.7 41.9h.5v.4h-.5zM167.6 48.7h.4v.5h-.4zM167.7 59.4h1l1.2 1.2v3.2l1.9 1.9v5.1l-.5 .5h-1.8v.8M167.7 56.9h1.3l.6 .6h4.9l1.1 1.1h1.5l.3-.3h1l.5 .5h2.4M167.7 58.2h1l1.5 1.4v.6l.1 .2M169.3 53.1h.4v.5h-.4z"/>
<path d="M171.2 58.5h.4v.5h-.4zM171.4 58.8h.1M171.4 58.8l.5 .4M171.7 57.5h.1M171.9 59.2l.1 .2M171.9 59.2h.6M172.5 59.2h.1M172.5 59.2l.2 .2M172.7 51h.4v.4h-.4zM172.7 58.2h.4l1.5 1.5h.2l.1-.2M173.1 53.8v2.7l-.4 .4M174.5 53.3h.5v.4h-.5z"/>
<path d="M174.7 59.3h.4v.4h-.4zM174.8 53.5h1.1l.3 .3M175.4 49.2h.4v.5h-.4zM177.9 58.8h.4v.4h-.4zM178.1 59l-1.7 1.6M178.1 42.6h.4v.5h-.4zM178.3 46.6h.4v.4h-.4zM179 44.4h.4v.4h-.4zM179.2 55.5h1.9l1 1M179.2 55.5l-.6 .5v1.3l.9 .9h.4M179.6 59.4h1.1l1 1.1v.2M179.9 56.9h.4l1 .9v1.6h.7"/>
<path d="M180.3 53.9l1.4-1.3h4.2v.2l.3 .3v1.8M180.9 47.3l-2.1 2.1v5.7l.4 .4M180.9 43.2l.4 .3M181.4 43.5h-1.4l-.8 .9v.2M181.8 59.2h.4v.5h-.4zM181.9 56.3h.4v.4h-.4zM182.2 51.5h.4v.5h-.4zM184.1 47.3h.1M184.1 43.2v4.1M184.1 47.3l.3 .4v3.9M184.1 53.5l.1 .2M184.4 51l-.3 .6"/>
<path d="M184.4 53.5l-1.1 1v4.5l-1.6 1.7M184.9 59.4h.1M184.9 59.4h3.5M184.9 56.9h3.9M184.9 58.2v1.2M186 54.7h.4v.5h-.4zM187.2 45.3h.4v.5h-.4zM188.2 59.2h.4v.5h-.4zM188.6 41.8h.4v.4h-.4zM188.7 51.7h.4v.4h-.4zM188.9 51.9v1.9M189.4 47.2h.5v.4h-.5z"/>
<path d="M189.4 49.2h.5v.5h-.5zM197 46.7h.4v.4h-.4zM197.1 55.1h.4v.4h-.4zM68.1 70.8h.4v.5h-.4zM75.1 75.6h.4v.5h-.4zM80.6 69.8h.4v.4h-.4zM80.7 61.2h.4v.4h-.4zM85.5 63.5h.4v.5h-.4zM87.5 66.7h.4v.5h-.4zM90.4 61.9h.4v.5h-.4zM91.2 69h.4v.5h-.4zM95.8 66.8h.4v.5h-.4z"/>
<path d="M96.1 71.9h.5v.5h-.5zM98.5 69.8l3.7 3.8h3.1l1-1M106.1 72.3h.4v.5h-.4zM112 74.8h.4v.4h-.4zM112.2 66.9h.4v.5h-.4zM112.4 60.8h.4v.5h-.4zM112.7 71.3h.4v.5h-.4zM112.9 71.5l.5-.5h10.8l1.3 1.3M115.1 65.3h.4v.5h-.4zM117.3 72.3h.4v.5h-.4zM117.5 72.6l1.1 1.1h8.8l1.5 1.5M121.5 64.4h.4v.4h-.4z"/>
<path d="M121.7 71.4h.4v.5h-.4zM127 64.5h.4v.4h-.4zM127.1 75h.4v.4h-.4zM128.7 75h.5v.4h-.5zM129.8 77.8h.4v.5h-.4zM129.8 64.5h.5v.4h-.5zM133.1 64.5h.4v.4h-.4zM133.4 74.3h.4v.4h-.4zM133.9 79.7h.4v.4h-.4zM134.1 60.1h.4v.5h-.4zM136.7 69h.4v.5h-.4zM136.7 74.9h.4v.4h-.4z"/>
<path d="M136.9 69.3l.7-.7h7.9l1.2 1.2M137.9 69.6h.4v.5h-.4zM138.1 73.4h9.8l1.3 1.2M138.3 65h.4v.4h-.4zM138.4 75.9h.4v.4h-.4zM138.6 71.2h.5v.4h-.5zM138.7 72.5h.4v.5h-.4zM138.9 71.4h.5l.4-.4h5.7l1.2 1.3M140.7 69.8l-.4 .4h-1.3l-.9 .9v3.1l-1.2 .9M149 74.4h.4v.4h-.4zM151.3 64.6h.5v.5h-.5zM154.8 79.4h.4v.4h-.4z"/>
<path d="M154.8 69.5h.4v.4h-.4zM159.1 73.8h.4v.4h-.4zM159.6 61.8h.5v.5h-.5zM162 64.7l4.9 4.9h1.1l.7 .8M163.1 69.4h.4v.4h-.4zM163.3 69.6l-.1 .2h-1.2M163.7 64.6h.4v.5h-.4zM165 72.2h.4v.4h-.4zM165 72.4h.2M165.3 74.2h.4v.4h-.4zM165.6 60.9h.4v.5h-.4zM165.9 62.4h.4v.5h-.4z"/>
<path d="M165.9 78.7h.4v.4h-.4zM166.3 71.7h.4v.5h-.4zM166.5 72l2.2 .1M166.7 76.5h.4v.4h-.4zM167 68.2h.4v.4h-.4zM167.1 65.4h.4v.4h-.4zM167.1 66.3h.4v.5h-.4zM167.2 68.4h1.2l1.1 1.2v.8M167.7 63.2h-.3l-.9 1v1.4l.8 .9M167.7 62h-.8l-.8 .7M167.7 60.7h1.3l.5 .5v4.2l-.6 .6M167.7 64.5v.7l-.4 .4"/>
<path d="M168.7 65.7h.4v.5h-.4zM169.1 77.2h.4v.5h-.4zM169.5 62.1h.1M169.6 68.4h.4v.4h-.4zM169.8 68.6l.5 .5v1.3M170.3 60.3v.1M170.3 60.4h.1M170.3 60.4v2.1l1.4 1.3h2.5l.2 .3M170.9 62.1h.4v.4h-.4zM171 68.1h.4v.4h-.4zM171.2 68.3l-.1 2.1M172.1 77h.4v.4h-.4z"/>
<path d="M172.3 77.2h.1M172.7 60.7h.1M172.7 64.5v6l-1.6 1.6M172.7 62l1.7-.1 1 1v1.3M172.7 60.7h1.5l1.2 1.2h2l.7 .8h4.4l1.3 1.2h3.1l1 1v1.1M173.4 69.2h.4v.4h-.4zM173.8 78.1h.4v.4h-.4zM173.8 73.2h.4v.4h-.4zM174 78.3h.1M174 78.3l.5-.5h6.1l.6 .6M174.2 63.9h.4v.4h-.4zM174.3 62.8h.4v.4h-.4z"/>
<path d="M174.5 63h-1.5l-.3 .2M175.2 64h.4v.4h-.4zM175.2 68.1h.4v.4h-.4zM175.2 71h.4v.4h-.4zM175.4 64.2h.1M175.4 71.2l1.7 .1M176.3 77.1l-4 .1M176.3 78.4h1.5l.3 .3h1.5l.9 1h.7l.2 .1M176.3 79.7h2.9l1.3 1.2h2.2l.5 .6M176.7 62.7h.4v.4h-.4zM177.3 74.1h.4v.5h-.4zM177.7 60.5h.4v.4h-.4z"/>
<path d="M177.9 60.7h.1M177.9 60.7h2.4M177.9 78.5h.4v.5h-.4zM178.4 65.7h.5v.5h-.5zM179.4 61.8h.4l.1 .2M179.9 62h.1M179.9 63.2h-1.8l-.8 .9h-.6l-2.2 2.2v3.5l-3.1 3h-1.1v-.7M179.9 64.5l-1.3 1.4v.1M180.1 71.1h.4v.4h-.4zM181.6 75.1h.4v.5h-.4zM181.7 64.1h.4v.5h-.4zM181.7 60.7l-1.3 1.3h-.5"/>
<path d="M181.9 64.3l.2 .2h2.8M182.9 74.6h.4v.5h-.4zM183.2 61.4h.4v.5h-.4zM183.4 61.6l.3 .4h1.2v1.2M183.6 66.2h.4v.4h-.4zM183.8 66.4l-1.8 1.8h-1.7M183.9 68.1l-1.3 1.2h-6.2l-1-1M184.1 77.6h.4v.4h-.4zM184.8 76h.4v.4h-.4zM184.9 60.7h3.2l.2 .3M185 72h.5v.4h-.5zM185.2 74v.4l-.2 .2v1.6"/>
<path d="M185.2 68.1v1.2l-1.3 1.2v3.5M185.2 71l.1 1.2M185.7 66.4h.4v.5h-.4zM185.9 66.6l.3 .3v.8l.3 .4M186.5 71l.2 .2h1.2M187.7 65.7h.4v.5h-.4zM187.7 71h.4v.4h-.4zM187.7 75.3h.4v.4h-.4zM188.1 60.7h.4v.5h-.4zM188.3 68.2h.4v.4h-.4zM188.5 68.4v3.7l-2 1.9M189.6 70.2h.4v.5h-.4z"/>
<path d="M189.7 75.3h.4v.4h-.4zM192 66.9h.4v.5h-.4zM193.5 69.7h.4v.5h-.4zM196.5 69.7h.4v.5h-.4zM197 62h.4v.5h-.4zM197.3 74.3h.4v.4h-.4zM72.9 81.3h.4v.5h-.4zM75.1 96.6h.5v.5h-.5zM79.3 97.6h.4v.4h-.4zM79.4 85.6h.4v.5h-.4zM81.4 88h.4v.4h-.4zM83.3 98.4h.4v.5h-.4z"/>
<path d="M84.7 88.3h.4v.4h-.4zM84.9 88.4h.1M84.9 88.4v.1M84.9 88.4l-1.2 1.3v5.5l.3 .2M85.3 92.8h.4v.5h-.4zM85.8 86.5h.4v.4h-.4zM86.7 90.8h.4v.4h-.4zM86.9 83.2h.4v.4h-.4zM88.9 99.6h.4v.4h-.4zM89.2 90.4l.2 .3M89.2 90.4h.2l.5 .5M89.2 90.4v.6h-2.3"/>
<path d="M89.4 90.7h.3M89.4 90.7l.3 .2M89.9 87.8h-4.4l-.6 .6M93 89.9h.4v.5h-.4zM93.7 86.7h.4v.5h-.4zM93.9 87h4.1l.1 .2h2.4l.4 .3M96.4 90.1h-1.7l-5.4 5.3h-2.3M96.9 96.1h.4v.5h-.4zM97.1 96.4h.1M97.1 96.4l-1.3 1.4h-.4M98.2 86.1h.4v.5h-.4zM98.5 92.3h.4v.5h-.4z"/>
<path d="M98.9 87.2h.1M98.9 87.2v2.9l-3.2 3.3h-.3M99.5 89.9h.4v.5h-.4zM100.6 96.1h.4v.5h-.4zM100.8 96.4l1.4 1.3M100.9 87.5h.1M100.9 87.5l.6 .6h2.6l.4 .4M100.9 87.1v.4M101.5 83.6h.4v.4h-.4zM104.5 88.5h.1M104.6 96.5h.4v.4h-.4zM104.8 96.7h1.9l1.2 1.3"/>
<path d="M105.4 86.4h3.1l.2 .1M107.3 87.6h.4v.4h-.4zM107.5 87.8l-1.6 1.7h-.5l-.9-1M108.5 86.3h.4v.5h-.4zM109 92.6h.4v.4h-.4zM109.4 91.1h.4v.5h-.4zM109.4 94.2h.4v.4h-.4zM109.7 99.3h.4v.4h-.4zM110.3 93.1h.4v.4h-.4zM110.5 90h.4v.5h-.4zM110.7 90.3l.2 .4h.8M111.1 95.2h.4v.4h-.4z"/>
<path d="M111.6 88.4h.4v.5h-.4zM111.7 93.7h-.8v1.3l.4 .4M111.7 92.7h-.8l-.4 .6M111.7 92.2h-1l-1.1 1.1v1.1M111.7 91.2h-1.9l-.2 .2M111.7 91.7h-1.5l-1 1.1M111.7 94.2l1.8 2h1.6M111.8 88.6l.6 .6v4h-.7M113.2 82.8h.5v.4h-.5zM113.5 93.2h.6l.2 .2h11.8l.6 .7h1.1M113.5 93.7h-.7v.8l.1 .2 7.1-.1M113.5 92.7l13.4 .1"/>
<path d="M113.5 91.7l2.5-.1 .3 .4M113.5 92.2h1.1M114.1 91.2h.1M114.4 92h.4v.4h-.4zM114.5 90.2h.4v.4h-.4zM114.7 90.4h-.3l-.3 .3h-.6M114.9 96h.5v.4h-.5zM115.1 93.8h.4v.4h-.4zM115.3 94l-.2 .2h-1.6M116.1 91.7h.4v.5h-.4zM116.7 90.2h.4v.4h-.4zM116.9 90.4l-1.2-.1-.9 .9h-1.3"/>
<path d="M118.2 85.5h.5v.5h-.5zM119.8 94.4h.4v.4h-.4zM121.2 96h.4v.5h-.4zM121.9 82.4h.4v.5h-.4zM122.9 98.3h.4v.5h-.4zM123 98.7l.4-.5h1.6l1 1.1h1M125.1 94.4h.4v.4h-.4zM125.5 85.5h.4v.5h-.4zM126.7 92.6h.4v.4h-.4zM126.9 84.4h.4v.5h-.4zM127.6 93.8h.5v.5h-.5zM128.7 96.3h.5v.4h-.5z"/>
<path d="M129.3 84.4h.4v.5h-.4zM129.6 86.3h.4v.5h-.4zM129.8 86.5v6.9l-2.8 2.8M131.3 99h.4v.5h-.4zM133.2 91.1h.4v.5h-.4zM133.5 84.7h.4v.4h-.4zM133.5 94.1h.4v.4h-.4zM133.6 82.1h.4v.4h-.4zM133.8 89.6h.4v.5h-.4zM137.3 98h.4v.4h-.4zM137.5 98.2l1.8 1.8h5.1l.3-.3h4v.2M138 80.8h.4v.4h-.4z"/>
<path d="M143.1 99h.4v.5h-.4zM143.7 96.3h.4v.4h-.4zM145.8 93.7h.4v.4h-.4zM146.4 95.1h.4v.5h-.4zM147.5 94.9h.4v.5h-.4zM147.7 95.2l.8 .7h6.3l.6-.7h14.5h.8l.6 .6h1.1M148.3 84.7h.4v.4h-.4zM148.7 99.9h.1M149.7 87.2h.4v.5h-.4zM149.7 91h.4v.4h-.4zM149.9 91.2v.5l-.4 .4M151 94.9h.4v.4h-.4z"/>
<path d="M151.2 95.1l-.5-.4-3.4-.1-.7 .7M151.5 97.7h.4v.4h-.4zM151.7 97.9h.1M151.7 97.9l-.6 .5-1.6 .1M151.7 97.9h16l.5 .5h4.2M152.9 93.5h.4v.4h-.4zM154.8 85.2h.4v.5h-.4zM154.9 91.7h.4v.5h-.4zM155.2 95h.5v.5h-.5zM156.4 96h.4v.4h-.4zM156.6 96.2h.1M156.6 96.2l-1 1h-6.1"/>
<path d="M158.1 91.6h.4v.5h-.4zM158.2 81.9h.4v.4h-.4zM158.3 88.8h.4v.5h-.4zM160.1 98.2h.4v.5h-.4zM160.3 98.5h2.4M160.6 99.1h.1M160.6 99.1l.4-.4h.5l.9 1h1.6l.3-.3M160.6 99.1l-17.3 .1M160.8 96.9h.4v.4h-.4zM161 99.1h.4v.4h-.4zM161 97.1l2.3 .2M161.1 93.3h.4v.5h-.4z"/>
<path d="M161.2 99.3l-.3 .4h-12.1l-.1 .2M161.3 84.7h.4v.4h-.4zM162.2 91h.4v.4h-.4zM162.5 88.8h.4v.4h-.4zM162.7 98.5h.1M162.7 89l-.5 .5h-.9v2.1l.5 .5h.9M162.8 97.3h1.6M163.1 87.9h.4v.5h-.4zM164.1 99.2h.4v.4h-.4zM164.1 94.2h.4v.4h-.4zM164.2 97.1h.4v.4h-.4zM164.4 89.5v.3l1 1"/>
<path d="M165.2 90.6h.4v.5h-.4zM165.3 93.2h.4v.4h-.4zM165.3 80.8h.4v.4h-.4zM165.5 93.4h-2.8l-.1 .2h-1.3M165.7 98.8h.4v.4h-.4zM165.8 96.9h.4v.4h-.4zM165.9 99l.6 .7h5.9M166 85.1h.4v.5h-.4zM166 87.2h.4v.5h-.4zM166.3 94.4h.4v.5h-.4zM166.7 89.4h.4v.5h-.4zM166.7 91.6h.4v.4h-.4z"/>
<path d="M166.9 91.8h-2.2l-1 .9h-3.8l-1 1h-6.8l-.4-.3h-2.2M168.2 99h.1M168.3 82h.4v.4h-.4zM169.9 85.5h.4v.4h-.4zM170 95.6h.4v.5h-.4zM170.2 95.8l-7.5 .1M170.3 92.6h.4v.4h-.4zM170.4 94.4h.4v.4h-.4zM170.5 92.8l.5 .5h1.4M171.8 83.1h.4v.4h-.4zM171.8 87.3h.4v.5h-.4zM172.4 92h.1"/>
<path d="M172.4 97.1h.1M172.4 95.8h.1M172.4 93.3h.1M172.4 99.7h.1M172.4 94.6h.1M172.4 94.6h2M173.5 81h.4v.4h-.4zM173.6 95.9h.4v.4h-.4zM173.8 97.7h.4v.4h-.4zM173.8 96.1l-.9 1h-.5M174.1 88.8h.4v.4h-.4zM174.2 94.4h.4v.4h-.4z"/>
<path d="M174.3 84.4h.4v.4h-.4zM174.4 94.6h.1M174.5 91.6h.4v.4h-.4zM174.5 84.6h1.6l.2 .2M175.5 95.5h.4v.5h-.4zM175.8 97.7h.4v.4h-.4zM176.3 83.5h.1M176.3 86v.9l.5 .6M176.3 82.2h1.2l.4 .3M176.3 80.9h.8l.5 .5M176.3 83.5l1.6 .1M176.5 89.3h.4v.4h-.4z"/>
<path d="M176.6 87.2h.4v.5h-.4zM177.2 93h.4v.4h-.4zM177.4 81.2h.4v.5h-.4zM177.5 99.4h.4v.5h-.4zM177.7 83.3h.4v.5h-.4zM177.7 82.3h.4v.5h-.4zM177.7 99.7l-1.2 1.2-6.2-.1M178.2 85.2h.4v.5h-.4zM178.8 91h.4v.5h-.4zM179.7 88.8h.4v.5h-.4zM180.1 91.7h.4v.5h-.4zM180.3 91.9h-.7l-.6 .6h-5l-.5-.5h-1.1"/>
<path d="M180.9 86.7h.4v.5h-.4zM181.1 94.4h.4v.4h-.4zM181.2 83.5h1.8l.7 .7M181.2 82.2h5.2l.5 .4M181.5 92.2h.4v.5h-.4zM181.7 92.5l.8 .8h3.2M183 81.3h.4v.5h-.4zM183.5 84h.4v.5h-.4zM184.5 89.3h.1M184.6 80.5h.4v.4h-.4zM185.1 84.3h.4v.4h-.4zM185.3 84.5l-.4 .3h-3.7"/>
<path d="M185.7 97.1h.1M185.7 99.7h.1M185.7 95.8h.1M185.7 92h.1M185.7 93.3h.1M185.7 98.4l-10.9 .1-.6 .5h-6.8l-.6-.6-4.1 .1M185.7 97.1h-10.9l-.8 .8M185.7 94.6h-2.2l-.6-.7h-16.9l-.4 .5h-1.3l-.2 .3h-1.4M185.7 85.7h.4v.5h-.4zM185.9 85.9l-4.7 .1M186.2 88.8h.4v.5h-.4zM186.7 82.4h.4v.5h-.4z"/>
<path d="M187 93.2h.4v.4h-.4zM187.6 91.7h.4v.5h-.4zM187.6 89h.1M187.6 89l-1.2 .1M187.7 98.9h.4v.5h-.4zM187.8 91.9l.2 .2v1.7l-2 2h-.3M187.9 99.1h-.7l-.4 .6h-1.1M188 86.6h.4v.5h-.4zM188.4 86.9h-1l-2.1 2.1h-.8v1.8l1.2 1.2M190 99.2h.4v.4h-.4zM190.2 99.4v.2M190.3 81.7h.4v.5h-.4z"/>
<path d="M190.4 91.6h.4v.4h-.4zM192.5 80.1h.1M196.1 91.4h.4v.4h-.4zM196.5 83.8h.4v.4h-.4zM94.3 114.4h.1M95 101.1h.4v.5h-.4zM97.2 106.5h.5v.5h-.5zM97.5 106.8h.5l.8 .7M103.3 111.2h.5v.4h-.5zM103.3 107.2h.5v.5h-.5zM103.9 100.4h.4v.5h-.4zM104.4 103.8h.4v.5h-.4z"/>
<path d="M105.8 114.1h.4v.4h-.4zM106 114.3h1.7l1.3-1.3h5l1.2 1.4M106.4 105.4h.4v.4h-.4zM107.5 112.7h.4v.5h-.4zM109.6 109.3h.1M109.6 109.3l1.1 1.2h9.9l.6 .6h5.5M111.6 109.4h.4v.5h-.4zM111.8 109.6h.1M113.9 100.8h.4v.4h-.4zM115.2 114.4h.1M118.5 108.8h.4v.5h-.4zM118.7 109.1l-1.1-1.2h-4.1l-1.7 1.7"/>
<path d="M121 105.3h.4v.4h-.4zM125.3 101h.4v.5h-.4zM126.5 110.9h.4v.4h-.4zM126.7 111.1h.1M127 106.4h.4v.4h-.4zM127 114.8h.4v.5h-.4zM127.1 108.6h.4v.4h-.4zM127.2 106.6h-1.9l-.3 .3M130.8 109h.1M130.8 106.4h.1M130.8 109l-.3 .3M130.8 106.4l-.3 .4"/>
<path d="M132.3 107.1h.4v.5h-.4zM132.5 105h.4v.5h-.4zM132.5 100.3h.4v.4h-.4zM132.6 115.9h.4v.5h-.4zM132.9 112.2h.4v.5h-.4zM133 109.6l.1 2.8M134.2 104.8h.5v.4h-.5zM135.1 105.4h.4v.5h-.4zM135.5 118.1h.4v.4h-.4zM135.7 118.3h4.8l.2 .1h.7M135.8 106.3h.4v.4h-.4zM135.9 118.9h.4v.4h-.4z"/>
<path d="M136.1 119.1h1.3l.4 .4h3.6M136.4 103.6h.4v.4h-.4zM136.9 106.3h.4v.4h-.4zM136.9 112.7h.4v.5h-.4zM137.1 108.3h.4v.5h-.4zM137.4 107.2h.4v.5h-.4zM137.7 110.7h.4v.4h-.4zM138.1 109.3h.4v.5h-.4zM138.3 109.6h-2.2M138.3 118.6h.4v.5h-.4zM138.5 108.3h.1M138.5 108.3l-.2 .2h-1"/>
<path d="M138.5 118.9l2.9 .1M139 118.3h.1M140.3 116.2h.4v.4h-.4zM140.5 116.4l1.1 1.1M141 104.9h.1M141 104.9h.6M141 104.9l-6.5 .1M141.4 120h-7.5l-2.1 1.9M141.6 117.5h.1M141.6 117.5l.7 .9v1.3l.3 .3h.6M141.6 107.4h.1M141.6 107.4h-2.2l-.9 .9"/>
<path d="M141.6 105.9h-5l-.6 .6M141.6 107.9h-.5l-3 3h-.2M141.6 108.5l-4.5 4.4M141.6 106.9h-3.5l-.5 .5M141.6 106.4l-4.5 .1M141.6 105.4h-5.5l-.2 .3h-.6M142.5 109.5h.5v.5h-.5zM143.1 117.5h.4v.5h-.4zM143.2 119l1.1-.1 1.4 1.3v1.4l-.7 .6M143.2 109h.4v.4h-.4zM143.3 117.8l.6 .2v.4h-.7M143.4 108.5h.1"/>
<path d="M143.4 109.2h.1M143.4 107.4h1.2l.1 .2M143.4 105.9h1.3v.3M143.4 106.9h3.4l1 1h3.2l1 1h.2M143.4 108.5v.7M143.9 118.9h.1M144 113.5h.4v.4h-.4zM144 119.3h.1M144 119.3l-.8 .2M144 119.3l.9 .9v.9M144.1 105.9h.1M144.5 105.9h.4v.5h-.4z"/>
<path d="M144.5 107.4h.4v.4h-.4zM145.1 104.3h.4v.4h-.4zM145.1 118.6h.4v.4h-.4zM145.8 117.3h.5v.4h-.5zM146 107.5h.4v.4h-.4zM146.2 107.7l-.7 .5h-1l-.2-.3h-.9M146.3 102.5h.4v.4h-.4zM146.5 102.7h-1.4l-1.7 1.6v.6M146.8 100.4h.4v.5h-.4zM147 100.7h-1l-3.3 3.2v2.5h.7M147.3 103.6h.4v.4h-.4zM147.3 101.4h.4v.4h-.4z"/>
<path d="M147.5 118.8h.4v.5h-.4zM147.5 119.6h.1M147.5 118.4h.1M147.5 119.6v4.7l-2.7 2.7h-2.6l-.1 .2M147.5 118.4l-.4 .4v.5l.4 .3M147.6 106h.4v.5h-.4zM147.7 119l1.4 1.5h.7M147.8 109.6h.4v.4h-.4zM147.8 110.4h.4v.5h-.4zM147.8 106.3l1.1 1.1h.6M148 113.5h.4v.4h-.4zM148 109.8l1.5 .1"/>
<path d="M148 110.7l.3 .5h1.2M149.5 101h.1M149.5 104.8h1.7l.3 .3h.5M149.5 106.1h.5l1.4 1.3M149.5 108.6h1.2l.9 .9M149.8 117.9l1.4 .1M150.5 105.5h.1M151 118.9h.4v.4h-.4zM151 117.8h.4v.4h-.4zM151 115.3h.4v.5h-.4zM151.2 107.2h.4v.5h-.4zM151.2 119.1l-1.4 .1"/>
<path d="M151.4 109.3h.4v.4h-.4zM151.8 104.8h.4v.5h-.4zM152 108.7h.4v.4h-.4zM152.3 114.4h.4v.5h-.4zM152.5 114.6v1.6l-.6 .6-2.7-.1-1.7 1.7M152.9 104.8h.4v.5h-.4zM153 106.5h.5v.5h-.5zM153.1 105.1l-.8 .6h-1.2l-.1-.2-7.6-.1M154.1 112.9h.5v.4h-.5zM155.8 101.2h.4v.5h-.4zM156 106.5h.4v.5h-.4zM157.4 110.5h.4v.5h-.4z"/>
<path d="M157.8 101.4h.4v.4h-.4zM158 101.6h.1M158 101.6h10.2l.5-.4h.8l1 1h11.4l.6 .6h5l2.4 2.4h.2M158 101.6l-.7 .7h-7.8M158.7 113.6h.4v.4h-.4zM160.1 105.8h.4v.4h-.4zM160.1 111.5h.4v.4h-.4zM160.2 107.1h.4v.4h-.4zM160.2 110.1h.4v.4h-.4zM160.3 106l2.4 .1M160.4 107.3l2.3 .1M160.4 102.7h.4v.5h-.4z"/>
<path d="M161.8 114l.1 .1 1.5 .1M162.7 109.9h.1M162.7 103.5l-.6 .6h-13.8l-.4 .5-2.6-.1M162.7 111.2h-1.9l-.5 .5M163.2 114h.4v.4h-.4zM164 108.4h.5v.4h-.5zM164.1 100.2h.4v.4h-.4zM164.2 118.7h.4v.5h-.4zM164.3 104.9h.4v.5h-.4zM164.3 100.4h-9.9l-.6 .6h-5.6l-.7 .6M164.4 119h-1.2l-.2 .2M164.5 114.4h.1"/>
<path d="M164.8 108.1h.4v.4h-.4zM164.9 114h.1M164.9 114l-1.9 1.9v.8M165 108.3h1.2l.3 .2h5.9M165.4 103.3h.4v.5h-.4zM165.6 103.5h-2.8l-.4 .4M166.5 117.3h.4v.4h-.4zM166.7 117.5l.1 .4M166.8 117.9l1.7 1.7h1.7l.2 .3h4.4l2-2h5.2l.6-.6h1.4l.5 .5h.9l.3 .1M166.8 117.9h-3.8M167 106.5h.4v.5h-.4zM167.2 106.8h.1"/>
<path d="M167.2 106.8h-1.4l-1.5 1.5v.3h-1.6M168.3 107.6h.4v.4h-.4zM168.5 112h.4v.4h-.4zM168.6 117.2h.4v.5h-.4zM168.7 104.6l.5-.5h4.2l.3 .1h10.2l.4 .4h1l.1-.1 .3 .2M168.7 104.6h-5.7l-.3 .2M168.7 104.6v3l-.2 .2M169 111.3h.4v.4h-.4zM169 101.6h.4v.5h-.4zM169.2 101.9l-.4 .4h-6.1M169.8 102.6h.4v.5h-.4zM169.8 118.1h.4v.5h-.4z"/>
<path d="M169.9 105.5h.4v.5h-.4zM169.9 107.9h.4v.4h-.4zM169.9 115.3h.4v.4h-.4zM169.9 109.8h.4v.5h-.4zM170 118.4l.9 .8h3.7l.8-.8M170.1 100.6h.4v.5h-.4zM170.1 110.1h.1M170.1 105.7h.8l.2 .3h8.4l1.9 1.9h7.2l.5-.5v-.7l-.6-.6M170.1 110.1h-6.1l-.2-.2h-3l-.4 .4M170.1 108.1l.4 .4M170.6 118.1h.4v.4h-.4zM171.3 112.3h.4v.4h-.4z"/>
<path d="M171.6 119.2h.1M172.4 103.5h.1M172.4 104.7h.1M172.4 106h.1M172.4 107.3h.1M172.4 108.5h.1M172.4 111.1h.1M172.4 117.9h.1M172.4 103.5h-1.9l-.5-.6h-8.2l-.7-.7h-2l-1 1h-5.6l-.4 .3h-4.3l-.3 .3M172.4 104.7h1l.4 .4h.5M172.4 107.3l.5 .1 1.5 1.6v.7M172.4 109.8h.1"/>
<path d="M172.4 111.1l-.5 .5v.6l-.4 .3M172.4 117.9h-1.3l-.3 .4M172.5 109.8h.1M172.5 109.8l.8 .1M173.2 109.8l.9 .9M173.7 103.4h.4v.5h-.4zM173.7 114.3h.4v.5h-.4zM173.9 110.4h.4v.5h-.4zM174.1 104.8h.4v.5h-.4zM174.2 109.5h.4v.5h-.4zM175.2 118.1h.4v.5h-.4zM175.4 113.5h.4v.4h-.4z"/>
<path d="M177.2 109.4h.4v.5h-.4zM177.5 104.7h.4v.4h-.4zM177.5 119.1h.4v.4h-.4zM177.7 119.3l-1.2 1.2h-4.1M179 108.2h.4v.5h-.4zM179 115h.4v.5h-.4zM179.1 110.2h.4v.4h-.4zM180.3 118.2h.4v.5h-.4zM181.2 100.3h.4v.4h-.4zM181.3 114h.4v.4h-.4zM181.5 114.2l-2.4 2.5h-8.3l-.7-.7v-.5M182.1 113.6h.1"/>
<path d="M182.8 119.9h.4v.5h-.4zM183 117.9h.4v.4h-.4zM183.2 118.1v.9l1.5 1.5h1l-.2 .1M183.3 108.7h.4v.4h-.4zM183.3 101.8h.4v.4h-.4zM183.3 113.6h.1M183.3 113.6l.2 .1M183.5 113.7h.1M183.5 113.7l.1 .1M183.5 113.7l.6 .3v1.1l1.6 1.6M183.5 108.9l.3-.4h4.3l1 1.1v2.7l.9 .8v.9l.4 .5v.6M183.5 102h2l.2 .2"/>
<path d="M183.6 113.6h-2.3l-1 1h-14.8l-.6-.6M184.1 114.4h.1M184.7 107.9h.1M185.6 112.7h.4v.5h-.4zM185.6 102.1h.1M185.7 116.7h.1M185.7 117.9h.1M185.7 103.5h.1M185.7 104.7h.1M185.7 100.9h.1M185.7 111.1h.1M185.7 109.8h.1"/>
<path d="M185.7 107.3h.1M185.7 108.5h.1M185.7 105.9h.1M185.7 119.2h.1M185.7 100.9h-3.9l-1.8-1.8h-4l-1.2 1.1h-7.2l-.7 .8h-9.6l-.4 .4h-.9M185.7 103.5h-11.5l-.3 .1M185.7 109.8h2.9M185.7 105.9h.2M185.7 115.2h.4v.4h-.4zM185.8 112.9l.2 .3M185.9 105.9h.1M186 113.2h.1"/>
<path d="M186 113.2l.7 .3 .4 .5M186.9 113.8h.1M187 113.9h.1M187.3 110.8h.4v.4h-.4zM187.5 115.9h.4v.4h-.4zM187.5 111l-1.8 .1M187.7 118.9h.4v.4h-.4zM187.7 116.1l-.6 .6h-1.4M187.9 119.1l-2.2 .1M188.1 104.8h.4v.4h-.4zM188.3 105.9h.4v.4h-.4zM188.3 106.9h.4v.4h-.4z"/>
<path d="M188.3 105l-.9 1-1.7-.1M188.3 109.6h.5v.4h-.5zM188.5 106.1h.1M188.5 107.1l-2.8 .2M188.9 114.7h.4v.4h-.4zM188.9 113h.4v.4h-.4zM189.9 101.7h.4v.5h-.4zM189.9 103.1h.4v.4h-.4zM189.9 104.9h.4v.5h-.4zM190 109.9h.4v.5h-.4zM190.2 114.8h.4v.5h-.4zM191 107.1h.4v.5h-.4z"/>
<path d="M192.2 116.2h.5v.4h-.5zM195.2 116.8h.4v.4h-.4zM196.6 110.9h.4v.4h-.4zM197.2 115.3h.4v.4h-.4zM197.3 101.5h.4v.4h-.4zM197.4 104.4h.4v.5h-.4zM82.1 138.2h.4v.5h-.4zM90.3 137.4h.4v.5h-.4zM103.3 121.4h.4v.5h-.4zM103.3 133.6h.5v.5h-.5zM112.7 134.8h.4v.5h-.4zM115.2 127.1h.1"/>
<path d="M115.2 127.1l.5 .3M115.2 129.6l11 10.9h1.3l2-2h7.5l3.7-3.6h1.4v-3.5h-.7M115.4 139.6h.1M115.4 139.6l-.2 .2M115.6 131.8h.1M115.8 131.6l-.6 .6M117.1 132.9h.5v.4h-.5zM117.8 134.4h.4v.4h-.4zM119.3 124.1h.5v.4h-.5zM120.4 136.8h.4v.4h-.4zM122.1 133.8h.4v.4h-.4zM122.7 126.4h.4v.4h-.4z"/>
<path d="M122.9 138.4h.4v.4h-.4zM123.1 128h.4v.4h-.4zM123.2 130h.4v.4h-.4zM123.3 128.2h.1M123.4 130.2h2.6l.7 .7h4.5l2.3 2.3h2.6l1.7-1.6h2.7l.4 .3h.5M125.2 137.1h.4v.5h-.4zM125.4 131.5h.4v.5h-.4zM126.7 136.2h.4v.4h-.4zM126.9 139.5h.4v.4h-.4zM128.1 128.8h.4v.5h-.4zM128.3 129h.2l.7-.6h1.9l2.4 2.3h7l.2 .3h.7M128.6 134.5h.4v.4h-.4z"/>
<path d="M129.2 120.6h.4v.4h-.4zM130.6 139.6h.1M130.7 139.5l-.2 .3M131.6 121.7h.4v.4h-.4zM132 128h.4v.4h-.4zM133.6 122h.4v.5h-.4zM134.1 139.9h.4v.4h-.4zM134.3 136.9h.4v.4h-.4zM134.5 121.7h.1M134.5 121.7l-.7 .6M134.6 132.1h.4v.5h-.4zM135.2 121.8h.4v.4h-.4z"/>
<path d="M135.6 122.6h.1M136 122.3h.1M136 139.1h.4v.5h-.4zM136.9 135.6h.4v.4h-.4zM138.3 132.2h.4v.4h-.4zM138.4 138.6h.4v.5h-.4zM138.5 132.4l.2-.2h1.8l.2 .2h.7M139.2 132.6h.4v.5h-.4zM140.1 132.7h.4v.4h-.4zM140.2 123.2h.4v.5h-.4zM140.3 132.9h.1M140.3 132.9h1.1"/>
<path d="M141.4 134.5h-1l-2.7 2.7-3.2-.1M141.4 120.5h-6.7l-2.7 2.7h-4.3l-3.3 3.3-1.5 .1M141.4 121.9h-5.1l-3.8 3.8h-4.6l-2.4 2.5h-2.2M141.4 133.4h-.7l-.2 .2h-3l-2.4 2.3h-5.6l-2.4 2.5v1.3M141.4 133.9l-1.4 .1-1.8 1.8h-1.1M141.4 121.4h-5.4l-.6 .6M141.4 120.9h-6.3l-.6 .8M141.4 130h.5v.4h-.5zM141.7 137.3h.4v.4h-.4zM141.9 126.9h.4v.5h-.4zM141.9 137.5h-.4l-2.7 2.7h-.4M142.5 138.9h.4v.4h-.4z"/>
<path d="M142.7 139.1h-1.4l-1.1 1.1M142.7 121.9h.1M142.7 121.9h.5M142.7 121.9l.1 2.6 .3 .3h.7M142.8 129.2h.4v.5h-.4zM143 136h.4v.5h-.4zM143 129.5l.9 .9M143.2 133.9h.5l.3 .4h.9M143.2 120.9h.7v.3l.4 .4M143.2 132.9l3.9 .1 .5 .5h1.8l.4-.3M143.2 131.4h1.8l.8-.8h5.7l1.6 1.6h1.1l.1 .3M143.2 131.9l2.4 .1"/>
<path d="M143.2 134.5l.5 .5h.9M143.2 121.4h-.7l-.2 .2v.7l-1.1 1.1h-.8M143.6 124.6h.5v.4h-.5zM143.9 120.1h.4v.4h-.4zM143.9 130.6h.1M143.9 131.4h.1M143.9 130.4v.2M143.9 130.6l-.3 .4h-.4M144.1 121.4h.4v.4h-.4zM144.1 120.3l-.1 .2h-.8M144.3 134.7h.4v.5h-.4zM144.4 137.6h.4v.5h-.4z"/>
<path d="M144.6 137.8v3.2l-1.4 1.4h-.5l-.2-.2h-2.3M144.7 134.1h.4v.4h-.4zM144.7 120.9h.5v.4h-.5zM144.8 122h.4v.4h-.4zM145.4 131.8h.4v.4h-.4zM146.2 138.8h.4v.4h-.4zM146.3 135.7h.4v.4h-.4zM146.4 139v1.3l-3.5 3.5h-.5l-.6-.6h-1.6M146.5 135.9l1.4 1.4h.7M147.3 129.4h.4v.4h-.4zM147.5 129.6l.4 .4h4.8l.5 .6h9.8M147.7 133.3h.4v.4h-.4z"/>
<path d="M148.4 137.1h.4v.5h-.4zM148.7 138.8h.4v.4h-.4zM149.8 135.7h1.2l.3 .3h.6M149.8 128.1h.8l.6-.6h17.9l.7 .6h2.6M149.8 124.3h.6l.6-.7h15.7l.8 .7h4.9M150.6 125.4l-.1 .2M150.6 125.4h-.7l-.1 .2M151 127.3h.4v.4h-.4zM151 124.2h.4v.4h-.4zM151 131.6h.4v.4h-.4zM151.2 131.8l-3.8 .1-.8 .8h-2.5l-.2-.3h-.7M151.2 124.9h13.9l.6 .6 6.7 .1"/>
<path d="M151.2 124.4v.5M151.2 124.9l-.6 .5M151.7 135.8h.4v.4h-.4zM152 133h.4v.4h-.4zM152.2 133.2l-1.2 1.3h-4.4l-1-.9h-1.6l-.1-.2h-.7M152.3 122h.4v.5h-.4zM152.5 122.3l-.8 .7h-1.9M152.7 129.2h.4v.5h-.4zM154 120.9h.4v.5h-.4zM154.1 132.3h.5v.4h-.5zM154.2 121.2h-3.9l-.5 .6M154.6 135.8h.4v.4h-.4z"/>
<path d="M156.3 138.6h.5v.5h-.5zM156.5 138.9h8.3l.9 .9M156.9 136h.4v.5h-.4zM156.9 133.4h.4v.4h-.4zM157.4 126.5h.4v.5h-.4zM157.6 126.7l-7.8 .1M159 134.8h.4v.5h-.4zM160.2 120h.4v.4h-.4zM160.3 131.4h.4v.5h-.4zM160.4 120.2l.9 .9v1.2l.6 .7 6.1-.1 .6 .7h14.8l.6-.6h1.7M163 124.3h2.8l.6 .6h16.9l.6-.5 1.8-.1v.2M163 134.5h-1.6l-.6 .5h-1.6"/>
<path d="M163 135.7l-.1 .8 .6 .5M163 128.1l2.1 .2M163 120.5l7.3-.1 .2 .2M163 121.8h.7l.8-.8h3.7l1.4 1.3h4l.3 .5h.3l1.1-1h10.4M163 125.6h1.3l.5 .4h5.7l.2 .2h10.5l.7-.6h3.8M163.3 136.8h.4v.4h-.4zM164.2 132.7h.4v.4h-.4zM164.3 131.3h.4v.5h-.4zM164.4 132.9h-1.2l-.2 .3M164.5 131.6l-.4 .3h-1.1M164.6 121.4h.4v.4h-.4zM164.9 128h.4v.5h-.4z"/>
<path d="M165.5 139.6h.4v.4h-.4zM165.7 122.1h.5v.5h-.5zM165.8 133.5h.4v.4h-.4zM166.5 123.4h.4v.4h-.4zM166.6 126.4h.4v.4h-.4zM166.8 126.6h.1M166.8 126.6h-.5l-.2 .1-3.1 .1M167.7 138.1h.4v.5h-.4zM168 129.1h.4v.4h-.4zM168.2 129.3v.1M168.2 129.4l-15.3 .1M168.2 129.4l.7 .6h5.5l.6-.6h10.7"/>
<path d="M169.1 131h.4v.5h-.4zM169.5 120.8h.4v.4h-.4zM169.7 121l.7 .8h2M169.7 135.2h.4v.4h-.4zM169.8 126.7h.4v.4h-.4zM169.9 128.6h.4v.4h-.4zM170.1 122.8h.5v.4h-.5zM170.1 132.8h.5v.4h-.5zM170.3 120.4h.4v.5h-.4zM170.3 133l.3 .2h1.8M170.3 123h2.1M172.3 136.9h.4v.4h-.4z"/>
<path d="M172.4 135.9h.1M172.4 125.6h.1M172.4 124.3h.1M172.4 128.1h.1M172.4 126.8h.1M172.4 123h.1M172.4 121.8h.1M172.4 120.5h.1M172.4 133.2h.1M172.4 131.9h.1M172.4 134.5h.1M172.4 129.4h.1"/>
<path d="M172.4 130.6h.1M172.4 135.7l.1 1.4M172.4 134.5h-2.2l-.3 .2v.7M172.4 129.4h-1.6l-.8-.7h-2l-.2 .2-16.2-.1-.7 .6h-2.2l-.4-.4h-3l-1.4 1.4M172.4 130.6h-2.6l-.5 .6M172.4 126.8l-2.4 .1M174 122.5h.4v.5h-.4zM174.5 130.4h.4v.5h-.4zM174.7 130.6l-1.4 1.3h-.9M175.2 128h.4v.5h-.4zM175.5 133h.4v.5h-.4zM176.5 136.5h.4v.5h-.4z"/>
<path d="M176.7 139.9h.4v.4h-.4zM177.8 134.5h.4v.4h-.4zM179.6 130.6h.4v.4h-.4zM180.6 136.3h.4v.5h-.4zM181.4 126.9h.4v.4h-.4zM181.7 125.3h.4v.5h-.4zM181.7 130h.5v.4h-.5zM181.9 130.2h3.3l.5 .4M182.4 133.7h.4v.5h-.4zM182.9 139.1h.4v.4h-.4zM183.4 133.6h.4v.5h-.4zM183.6 120.3h.4v.5h-.4z"/>
<path d="M183.8 131h.4v.5h-.4zM183.9 132.5h.4v.5h-.4zM184 131.2l.7 .7h1M185.3 120.5l.2 .1M185.5 120.6h.1M185.7 121.8h.1M185.7 128.1h.1M185.7 125.6h.1M185.7 124.5h.1M185.7 126.8h.1M185.7 133.2h.1M185.7 134.5h.1"/>
<path d="M185.7 135.7h.1M185.7 131.9h.1M185.7 130.6h.1M185.7 129.4h.1M185.7 128.1h-10.2l-.1 .2M185.7 126.8h2.1l.2 .3M185.7 121.8l.1 .2h.4M185.7 133.2l-.7 .7h-1.4M185.9 124.3h1.4l.6 .6M187.2 129.4h.4v.4h-.4zM187.4 129.6v3.5l-1.2 1.2h-.4l-.1 .2M187.6 134h.4v.4h-.4z"/>
<path d="M187.7 124.7h.4v.4h-.4zM187.8 134.2l-1.5 1.5h-.6M187.8 132.1h.4v.5h-.4zM187.8 126.9h.4v.4h-.4zM188.9 130.3h.4v.5h-.4zM90.1 142.8h.4v.4h-.4zM91.5 147.8h.4v.4h-.4zM97 141.4h.4v.5h-.4zM100.1 146.2h.4v.4h-.4zM101.7 142.3h.4v.4h-.4zM101.9 140.4h.4v.5h-.4zM102.5 147.9h.4v.4h-.4z"/>
<path d="M103.4 145.2h.4v.5h-.4zM105.5 140.7h.4v.4h-.4zM106.4 142h.4v.5h-.4zM112 142.3h.4v.4h-.4zM112 145.4h.4v.4h-.4zM113 147.9h.4v.5h-.4zM117.3 142.4h.4v.4h-.4zM122.4 142.3h.4v.4h-.4zM122.7 148h.4v.5h-.4zM127.2 142.3h.4v.4h-.4zM129.5 144.3h.4v.4h-.4zM132.6 141.3h.4v.5h-.4z"/>
<path d="M133.1 144.1h.4v.5h-.4zM133.3 144.4h.1M133.7 147.9h.4v.4h-.4zM134.1 145.2h.4v.5h-.4zM135.9 141.4h.4v.5h-.4zM135.9 145.2h.4v.5h-.4zM136.1 141.6l.5 .6h1.8M136.1 140.7h.4v.4h-.4zM136.3 140.9l.4 .3h1.7M137 143.9h.4v.4h-.4zM138.4 142.7h-4.7l-1.8 1.8h-2.2M138.4 143.2h-4l-1.1 1.2"/>
<path d="M138.4 140.7h-1.2l-.4-.5h-1l-1.3 1.4h-1.7M138.4 143.7h-.8l-.4 .4M138.4 141.7h.7v3.6M138.9 145.1h.4v.4h-.4zM140.2 143.7h.7l.2 .2v2M140.2 142.7h2l.5 .5M140.2 141.7l2.7 .1M140.9 140.2h.4v.4h-.4zM140.9 145.7h.4v.4h-.4zM141.1 140.4l-.2 .3h-.7M142.5 142.9h.4v.5h-.4zM142.7 141.6h.4v.4h-.4z"/>
<path d="M143.1 140.6h.4v.4h-.4zM143.3 140.8l-.4 .3-2.7 .1M143.6 145.3h.4v.5h-.4zM144.6 143.4h.4v.4h-.4zM150.2 145.3h.4v.5h-.4zM151.1 140.7h.4v.4h-.4zM159.1 145.5h.4v.4h-.4zM171.7 140.7h.4v.4h-.4zM171.8 144.4h.4v.4h-.4zM174.1 142.8h.4v.4h-.4zM180.4 147.9h.4v.4h-.4z"/>
</g>
<path d="M148.9 122.9h1.6v.3h-1.6z" fill="#d91c2b"/>
<path d="M148.9 122.9h1.6v.3h-1.6z" fill="none" stroke="#d91c2b" stroke-width=".34"/>
<path d="M148.9 124.1h1.6v.4h-1.6z" fill="#d91c2b"/>
<path d="M148.9 124.1h1.6v.4h-1.6z" fill="none" stroke="#d91c2b" stroke-width=".34"/>
<path d="M148.9 125.4h1.6v.3h-1.6z" fill="#d91c2b"/>
<path d="M148.9 125.4h1.6v.3h-1.6z" fill="none" stroke="#d91c2b" stroke-width=".34"/>
<path d="M148.9 126.7h1.6v.3h-1.6z" fill="#d91c2b"/>
<path d="M148.9 126.7h1.6v.3h-1.6z" fill="none" stroke="#d91c2b" stroke-width=".34"/>
<path d="M148.9 127.9h1.6v.4h-1.6z" fill="#d91c2b"/>
<path d="M148.9 127.9h1.6v.4h-1.6z" fill="none" stroke="#d91c2b" stroke-width=".34"/>
<path d="M148.9 129.2h1.6v.3h-1.6z" fill="#d91c2b"/>
<path d="M148.9 129.2h1.6v.3h-1.6z" fill="none" stroke="#d91c2b" stroke-width=".34"/>
<path d="M148.9 130.5h1.6v.3h-1.6z" fill="#d91c2b"/>
<path d="M148.9 130.5h1.6v.3h-1.6z" fill="none" stroke="#d91c2b" stroke-width=".34"/>
<path d="M148.9 131.7h1.6v.4h-1.6z" fill="#d91c2b"/>
<path d="M148.9 131.7h1.6v.4h-1.6z" fill="none" stroke="#d91c2b" stroke-width=".34"/>
<path d="M148.9 133h1.6v.3h-1.6z" fill="#d91c2b"/>
<path d="M148.9 133h1.6v.3h-1.6z" fill="none" stroke="#d91c2b" stroke-width=".34"/>
<path d="M148.9 134.3h1.6v.3h-1.6z" fill="#d91c2b"/>
<path d="M148.9 134.3h1.6v.3h-1.6z" fill="none" stroke="#d91c2b" stroke-width=".34"/>
<path d="M148.9 135.6h1.6v.3h-1.6z" fill="#d91c2b"/>
<path d="M148.9 135.6h1.6v.3h-1.6z" fill="none" stroke="#d91c2b" stroke-width=".34"/>
<path d="M162.2 135.6h1.5v.3h-1.5z" fill="#d91c2b"/>
<path d="M162.2 135.6h1.5v.3h-1.5z" fill="none" stroke="#d91c2b" stroke-width=".34"/>
<path d="M162.2 134.3h1.5v.3h-1.5z" fill="#d91c2b"/>
<path d="M162.2 134.3h1.5v.3h-1.5z" fill="none" stroke="#d91c2b" stroke-width=".34"/>
<path d="M162.2 133h1.5v.3h-1.5z" fill="#d91c2b"/>
<path d="M162.2 133h1.5v.3h-1.5z" fill="none" stroke="#d91c2b" stroke-width=".34"/>
<path d="M162.2 131.7h1.5v.4h-1.5z" fill="#d91c2b"/>
<path d="M162.2 131.7h1.5v.4h-1.5z" fill="none" stroke="#d91c2b" stroke-width=".34"/>
<path d="M162.2 130.5h1.5v.3h-1.5z" fill="#d91c2b"/>
<path d="M162.2 130.5h1.5v.3h-1.5z" fill="none" stroke="#d91c2b" stroke-width=".34"/>
<path d="M162.2 129.2h1.5v.3h-1.5z" fill="#d91c2b"/>
<path d="M162.2 129.2h1.5v.3h-1.5z" fill="none" stroke="#d91c2b" stroke-width=".34"/>
<path d="M162.2 127.9h1.5v.4h-1.5z" fill="#d91c2b"/>
<path d="M162.2 127.9h1.5v.4h-1.5z" fill="none" stroke="#d91c2b" stroke-width=".34"/>
<path d="M162.2 126.7h1.5v.3h-1.5z" fill="#d91c2b"/>
<path d="M162.2 126.7h1.5v.3h-1.5z" fill="none" stroke="#d91c2b" stroke-width=".34"/>
<g fill="#d91c2b">
<path d="M162.2 125.4h1.5v.3h-1.5z"/>
<circle cx="115.3" cy="116.9" r=".8"/>
<circle cx="115.3" cy="119.5" r=".8"/>
<circle cx="115.3" cy="122" r=".8"/>
<circle cx="115.3" cy="124.5" r=".8"/>
<circle cx="115.3" cy="127.1" r=".8"/>
<circle cx="115.3" cy="129.6" r=".8"/>
<circle cx="115.3" cy="132.2" r=".8"/>
<circle cx="115.3" cy="134.7" r=".8"/>
<circle cx="115.3" cy="137.2" r=".8"/>
<circle cx="115.3" cy="139.8" r=".8"/>
<circle cx="115.3" cy="142.3" r=".8"/>
<circle cx="130.6" cy="142.3" r=".8"/>
<circle cx="130.6" cy="139.8" r=".8"/>
<circle cx="130.6" cy="137.2" r=".8"/>
<circle cx="130.6" cy="134.7" r=".8"/>
<circle cx="130.6" cy="132.2" r=".8"/>
<circle cx="130.6" cy="129.6" r=".8"/>
<circle cx="130.6" cy="127.1" r=".8"/>
<circle cx="130.6" cy="124.5" r=".8"/>
<circle cx="130.6" cy="122" r=".8"/>
<circle cx="130.6" cy="119.5" r=".8"/>
<circle cx="130.6" cy="116.9" r=".8"/>
<circle cx="130.6" cy="114.4" r=".8"/>
</g>
<path d="M162.2 125.4h1.5v.3h-1.5z" fill="none" stroke="#d91c2b" stroke-width=".34"/>
<path d="M162.2 124.1h1.5v.4h-1.5z" fill="#d91c2b"/>
<path d="M162.2 124.1h1.5v.4h-1.5z" fill="none" stroke="#d91c2b" stroke-width=".34"/>
<path d="M162.2 122.9h1.5v.3h-1.5z" fill="#d91c2b"/>
<path d="M162.2 122.9h1.5v.3h-1.5z" fill="none" stroke="#d91c2b" stroke-width=".34"/>
<path d="M162.2 121.6h1.5v.3h-1.5z" fill="#d91c2b"/>
<path d="M162.2 121.6h1.5v.3h-1.5z" fill="none" stroke="#d91c2b" stroke-width=".34"/>
<path d="M162.2 120.3h1.5v.4h-1.5z" fill="#d91c2b"/>
<path d="M162.2 120.3h1.5v.3h-1.5z" fill="none" stroke="#d91c2b" stroke-width=".34"/>
<path d="M162.2 119h1.5v.4h-1.5z" fill="#d91c2b"/>
<path d="M162.2 119h1.5v.4h-1.5z" fill="none" stroke="#d91c2b" stroke-width=".34"/>
<path d="M162.2 117.8h1.5v.3h-1.5z" fill="#d91c2b"/>
<path d="M162.2 117.8h1.5v.3h-1.5z" fill="none" stroke="#d91c2b" stroke-width=".34"/>
<path d="M162.2 116.5h1.5v.3h-1.5z" fill="#d91c2b"/>
<path d="M162.2 116.5h1.5v.3h-1.5z" fill="none" stroke="#d91c2b" stroke-width=".34"/>
<path d="M171.6 116.5h1.5v.3h-1.5z" fill="#d91c2b"/>
<path d="M171.6 116.5h1.5v.3h-1.5z" fill="none" stroke="#d91c2b" stroke-width=".34"/>
<path d="M171.6 117.8h1.5v.3h-1.5z" fill="#d91c2b"/>
<path d="M171.6 117.8h1.5v.3h-1.5z" fill="none" stroke="#d91c2b" stroke-width=".34"/>
<path d="M171.6 119h1.5v.4h-1.5z" fill="#d91c2b"/>
<path d="M171.6 119h1.5v.4h-1.5z" fill="none" stroke="#d91c2b" stroke-width=".34"/>
<path d="M171.6 120.3h1.5v.4h-1.5z" fill="#d91c2b"/>
<path d="M171.6 120.3h1.5v.3h-1.5z" fill="none" stroke="#d91c2b" stroke-width=".34"/>
<path d="M171.6 121.6h1.5v.3h-1.5z" fill="#d91c2b"/>
<path d="M171.6 121.6h1.5v.3h-1.5z" fill="none" stroke="#d91c2b" stroke-width=".34"/>
<path d="M171.6 122.9h1.5v.3h-1.5z" fill="#d91c2b"/>
<path d="M171.6 122.9h1.5v.3h-1.5z" fill="none" stroke="#d91c2b" stroke-width=".34"/>
<path d="M171.6 124.1h1.5v.4h-1.5z" fill="#d91c2b"/>
<path d="M171.6 124.1h1.5v.4h-1.5z" fill="none" stroke="#d91c2b" stroke-width=".34"/>
<path d="M171.6 125.4h1.5v.3h-1.5z" fill="#d91c2b"/>
<path d="M171.6 125.4h1.5v.3h-1.5z" fill="none" stroke="#d91c2b" stroke-width=".34"/>
<path d="M171.6 126.7h1.5v.3h-1.5z" fill="#d91c2b"/>
<path d="M171.6 126.7h1.5v.3h-1.5z" fill="none" stroke="#d91c2b" stroke-width=".34"/>
<path d="M171.6 127.9h1.5v.4h-1.5z" fill="#d91c2b"/>
<path d="M171.6 127.9h1.5v.4h-1.5z" fill="none" stroke="#d91c2b" stroke-width=".34"/>
<path d="M171.6 129.2h1.5v.3h-1.5z" fill="#d91c2b"/>
<path d="M171.6 129.2h1.5v.3h-1.5z" fill="none" stroke="#d91c2b" stroke-width=".34"/>
<path d="M171.6 130.5h1.5v.3h-1.5z" fill="#d91c2b"/>
<path d="M171.6 130.5h1.5v.3h-1.5z" fill="none" stroke="#d91c2b" stroke-width=".34"/>
<path d="M171.6 131.7h1.5v.4h-1.5z" fill="#d91c2b"/>
<path d="M171.6 131.7h1.5v.4h-1.5z" fill="none" stroke="#d91c2b" stroke-width=".34"/>
<path d="M171.6 133h1.5v.3h-1.5z" fill="#d91c2b"/>
<path d="M171.6 133h1.5v.3h-1.5z" fill="none" stroke="#d91c2b" stroke-width=".34"/>
<path d="M171.6 134.3h1.5v.3h-1.5z" fill="#d91c2b"/>
<path d="M171.6 134.3h1.5v.3h-1.5z" fill="none" stroke="#d91c2b" stroke-width=".34"/>
<path d="M171.6 135.6h1.5v.3h-1.5z" fill="#d91c2b"/>
<path d="M171.6 135.6h1.5v.3h-1.5z" fill="none" stroke="#d91c2b" stroke-width=".34"/>
<path d="M184.9 135.6h1.5v.3h-1.5z" fill="#d91c2b"/>
<path d="M184.9 135.6h1.5v.3h-1.5z" fill="none" stroke="#d91c2b" stroke-width=".34"/>
<path d="M184.9 134.3h1.5v.3h-1.5z" fill="#d91c2b"/>
<path d="M184.9 134.3h1.5v.3h-1.5z" fill="none" stroke="#d91c2b" stroke-width=".34"/>
<path d="M184.9 133h1.5v.3h-1.5z" fill="#d91c2b"/>
<path d="M184.9 133h1.5v.3h-1.5z" fill="none" stroke="#d91c2b" stroke-width=".34"/>
<path d="M184.9 131.7h1.5v.4h-1.5z" fill="#d91c2b"/>
<path d="M184.9 131.7h1.5v.4h-1.5z" fill="none" stroke="#d91c2b" stroke-width=".34"/>
<path d="M184.9 130.5h1.5v.3h-1.5z" fill="#d91c2b"/>
<path d="M184.9 130.5h1.5v.3h-1.5z" fill="none" stroke="#d91c2b" stroke-width=".34"/>
<g fill="#d91c2b">
<path d="M184.9 129.2h1.5v.3h-1.5z"/>
<circle cx="184.9" cy="144.9" r="2.84"/>
</g>
<path d="M184.9 129.2h1.5v.3h-1.5z" fill="none" stroke="#d91c2b" stroke-width=".34"/>
<path d="M184.9 127.9h1.5v.4h-1.5z" fill="#d91c2b"/>
<path d="M184.9 127.9h1.5v.4h-1.5z" fill="none" stroke="#d91c2b" stroke-width=".34"/>
<path d="M184.9 126.7h1.5v.3h-1.5z" fill="#d91c2b"/>
<path d="M184.9 126.7h1.5v.3h-1.5z" fill="none" stroke="#d91c2b" stroke-width=".34"/>
<path d="M184.9 125.4h1.5v.3h-1.5z" fill="#d91c2b"/>
<path d="M184.9 125.4h1.5v.3h-1.5z" fill="none" stroke="#d91c2b" stroke-width=".34"/>
<path d="M184.9 124.1h1.5v.4h-1.5z" fill="#d91c2b"/>
<path d="M184.9 124.1h1.5v.4h-1.5z" fill="none" stroke="#d91c2b" stroke-width=".34"/>
<path d="M184.9 122.9h1.5v.3h-1.5z" fill="#d91c2b"/>
<path d="M184.9 122.9h1.5v.3h-1.5z" fill="none" stroke="#d91c2b" stroke-width=".34"/>
<path d="M184.9 121.6h1.5v.3h-1.5z" fill="#d91c2b"/>
<path d="M184.9 121.6h1.5v.3h-1.5z" fill="none" stroke="#d91c2b" stroke-width=".34"/>
<path d="M184.9 120.3h1.5v.4h-1.5z" fill="#d91c2b"/>
<path d="M184.9 120.3h1.5v.3h-1.5z" fill="none" stroke="#d91c2b" stroke-width=".34"/>
<path d="M184.9 119h1.5v.4h-1.5z" fill="#d91c2b"/>
<path d="M184.9 119h1.5v.4h-1.5z" fill="none" stroke="#d91c2b" stroke-width=".34"/>
<path d="M184.9 117.8h1.5v.3h-1.5z" fill="#d91c2b"/>
<path d="M184.9 117.8h1.5v.3h-1.5z" fill="none" stroke="#d91c2b" stroke-width=".34"/>
<path d="M184.9 116.5h1.5v.3h-1.5z" fill="#d91c2b"/>
<path d="M184.9 116.5h1.5v.3h-1.5z" fill="none" stroke="#d91c2b" stroke-width=".34"/>
<g fill="#d91c2b">
<path d="M141 130.8h.8v.3h-.8z"/>
<path d="M141 131.3h.8v.3h-.8z"/>
<path d="M141 131.8h.8v.3h-.8z"/>
<path d="M141 132.2h.8v.4h-.8z"/>
<path d="M141 132.8h.8v.3h-.8z"/>
<path d="M141 133.3h.8v.3h-.8z"/>
<path d="M141 133.8h.8v.3h-.8z"/>
<path d="M141 134.3h.8v.3h-.8z"/>
<path d="M142.7 134.3h.9v.3h-.9z"/>
<path d="M142.7 133.8h.9v.3h-.9z"/>
<path d="M142.7 133.3h.9v.3h-.9z"/>
<path d="M142.7 132.8h.9v.3h-.9z"/>
<path d="M142.7 132.2h.9v.4h-.9z"/>
<path d="M142.7 131.8h.9v.3h-.9z"/>
<path d="M142.7 131.3h.9v.3h-.9z"/>
<path d="M142.7 130.8h.9v.3h-.9z"/>
<path d="M139.8 143.5h.8v.3h-.8z"/>
<path d="M139.8 143.1h.8v.2h-.8z"/>
<path d="M139.8 142.6h.8v.2h-.8z"/>
<path d="M139.8 142.1h.8v.2h-.8z"/>
<path d="M139.8 141.6h.8v.2h-.8z"/>
<path d="M139.8 141.1h.8v.2h-.8z"/>
<path d="M139.8 140.5h.8v.4h-.8z"/>
<path d="M139.8 140h.8v.4h-.8z"/>
<path d="M138 140h.9v.4h-.9z"/>
<path d="M138 140.5h.9v.4h-.9z"/>
<path d="M138 141.1h.9v.2h-.9z"/>
<path d="M138 141.6h.9v.2h-.9z"/>
<path d="M138 142.1h.9v.2h-.9z"/>
<path d="M138 142.6h.9v.2h-.9z"/>
<path d="M138 143.1h.9v.2h-.9z"/>
<path d="M138 143.5h.9v.3h-.9z"/>
<path d="M171.6 98.2h1.5v.3h-1.5z"/>
</g>
<path d="M171.6 98.2h1.5v.3h-1.5z" fill="none" stroke="#d91c2b" stroke-width=".34"/>
<path d="M171.6 99.5h1.5v.2h-1.5z" fill="#d91c2b"/>
<path d="M171.6 99.5h1.5v.2h-1.5z" fill="none" stroke="#d91c2b" stroke-width=".34"/>
<path d="M171.6 100.8h1.5v.2h-1.5z" fill="#d91c2b"/>
<path d="M171.6 100.8h1.5v.2h-1.5z" fill="none" stroke="#d91c2b" stroke-width=".34"/>
<path d="M171.6 102h1.5v.3h-1.5z" fill="#d91c2b"/>
<path d="M171.6 102h1.5v.3h-1.5z" fill="none" stroke="#d91c2b" stroke-width=".34"/>
<path d="M171.6 103.3h1.5v.2h-1.5z" fill="#d91c2b"/>
<path d="M171.6 103.3h1.5v.2h-1.5z" fill="none" stroke="#d91c2b" stroke-width=".34"/>
<path d="M171.6 104.6h1.5v.2h-1.5z" fill="#d91c2b"/>
<path d="M171.6 104.6h1.5v.2h-1.5z" fill="none" stroke="#d91c2b" stroke-width=".34"/>
<path d="M171.6 105.8h1.5v.3h-1.5z" fill="#d91c2b"/>
<path d="M171.6 105.8h1.5v.3h-1.5z" fill="none" stroke="#d91c2b" stroke-width=".34"/>
<path d="M171.6 107.1h1.5v.3h-1.5z" fill="#d91c2b"/>
<path d="M171.6 107.1h1.5v.3h-1.5z" fill="none" stroke="#d91c2b" stroke-width=".34"/>
<path d="M171.6 108.4h1.5v.2h-1.5z" fill="#d91c2b"/>
<path d="M171.6 108.4h1.5v.2h-1.5z" fill="none" stroke="#d91c2b" stroke-width=".34"/>
<path d="M171.6 109.6h1.5v.3h-1.5z" fill="#d91c2b"/>
<path d="M171.6 109.6h1.5v.3h-1.5z" fill="none" stroke="#d91c2b" stroke-width=".34"/>
<path d="M171.6 110.9h1.5v.3h-1.5z" fill="#d91c2b"/>
<path d="M171.6 110.9h1.5v.3h-1.5z" fill="none" stroke="#d91c2b" stroke-width=".34"/>
<path d="M184.9 110.9h1.5v.3h-1.5z" fill="#d91c2b"/>
<path d="M184.9 110.9h1.5v.3h-1.5z" fill="none" stroke="#d91c2b" stroke-width=".34"/>
<path d="M184.9 109.6h1.5v.3h-1.5z" fill="#d91c2b"/>
<path d="M184.9 109.6h1.5v.3h-1.5z" fill="none" stroke="#d91c2b" stroke-width=".34"/>
<path d="M184.9 108.4h1.5v.2h-1.5z" fill="#d91c2b"/>
<path d="M184.9 108.4h1.5v.2h-1.5z" fill="none" stroke="#d91c2b" stroke-width=".34"/>
<path d="M186.4 113.4h.8v1.2h-.8z" fill="#d91c2b"/>
<path d="M186.4 113.4h.8v1.2h-.8z" fill="none" stroke="#d91c2b" stroke-width=".51"/>
<path d="M183.3 113.4h.8v1.2h-.8z" fill="#d91c2b"/>
<path d="M183.3 113.4h.8v1.2h-.8z" fill="none" stroke="#d91c2b" stroke-width=".51"/>
<path d="M184.9 107.1h1.5v.3h-1.5z" fill="#d91c2b"/>
<path d="M184.9 107.1h1.5v.3h-1.5z" fill="none" stroke="#d91c2b" stroke-width=".34"/>
<path d="M184.9 105.8h1.5v.3h-1.5z" fill="#d91c2b"/>
<path d="M184.9 105.8h1.5v.3h-1.5z" fill="none" stroke="#d91c2b" stroke-width=".34"/>
<path d="M184.9 104.6h1.5v.2h-1.5z" fill="#d91c2b"/>
<path d="M184.9 104.6h1.5v.2h-1.5z" fill="none" stroke="#d91c2b" stroke-width=".34"/>
<path d="M184.9 103.3h1.5v.2h-1.5z" fill="#d91c2b"/>
<path d="M184.9 103.3h1.5v.2h-1.5z" fill="none" stroke="#d91c2b" stroke-width=".34"/>
<path d="M184.9 102h1.5v.3h-1.5z" fill="#d91c2b"/>
<path d="M184.9 102h1.5v.3h-1.5z" fill="none" stroke="#d91c2b" stroke-width=".34"/>
<path d="M184.9 100.8h1.5v.2h-1.5z" fill="#d91c2b"/>
<path d="M184.9 100.8h1.5v.2h-1.5z" fill="none" stroke="#d91c2b" stroke-width=".34"/>
<path d="M184.9 99.5h1.5v.2h-1.5z" fill="#d91c2b"/>
<path d="M184.9 99.5h1.5v.2h-1.5z" fill="none" stroke="#d91c2b" stroke-width=".34"/>
<path d="M184.9 98.2h1.5v.3h-1.5z" fill="#d91c2b"/>
<path d="M184.9 98.2h1.5v.3h-1.5z" fill="none" stroke="#d91c2b" stroke-width=".34"/>
<path d="M184.9 96.9h1.5v.3h-1.5z" fill="#d91c2b"/>
<path d="M184.9 96.9h1.5v.3h-1.5z" fill="none" stroke="#d91c2b" stroke-width=".34"/>
<path d="M184.9 95.7h1.5v.2h-1.5z" fill="#d91c2b"/>
<path d="M184.9 95.7h1.5v.2h-1.5z" fill="none" stroke="#d91c2b" stroke-width=".34"/>
<path d="M146.1 43.8h1.1v1.1h-1.1z" fill="#d91c2b"/>
<path d="M146.1 43.8h1.1v1.1h-1.1z" fill="none" stroke="#d91c2b" stroke-width=".51"/>
<g fill="#d91c2b">
<path d="M164 88.8h.8v1.4h-.8z"/>
<circle cx="146.7" cy="46.9" r=".8"/>
<circle cx="146.7" cy="49.4" r=".8"/>
<circle cx="146.7" cy="52" r=".8"/>
<circle cx="146.7" cy="54.5" r=".8"/>
<circle cx="146.7" cy="57.1" r=".8"/>
<circle cx="146.7" cy="59.6" r=".8"/>
<circle cx="146.7" cy="62.1" r=".8"/>
<circle cx="146.7" cy="64.7" r=".8"/>
<circle cx="146.7" cy="67.2" r=".8"/>
<circle cx="146.7" cy="69.8" r=".8"/>
<circle cx="146.7" cy="72.3" r=".8"/>
<circle cx="146.7" cy="74.8" r=".8"/>
<circle cx="146.7" cy="77.4" r=".8"/>
<circle cx="146.7" cy="79.9" r=".8"/>
<circle cx="162" cy="74.8" r=".8"/>
<circle cx="162" cy="72.3" r=".8"/>
<circle cx="162" cy="69.8" r=".8"/>
<circle cx="162" cy="67.2" r=".8"/>
<circle cx="162" cy="64.7" r=".8"/>
<circle cx="162" cy="62.1" r=".8"/>
<circle cx="162" cy="59.6" r=".8"/>
<circle cx="162" cy="57.1" r=".8"/>
<circle cx="162" cy="54.5" r=".8"/>
<circle cx="162" cy="52" r=".8"/>
<circle cx="162" cy="82.5" r=".8"/>
<circle cx="162" cy="79.9" r=".8"/>
<circle cx="162" cy="77.4" r=".8"/>
</g>
<path d="M164 88.8h.8v1.4h-.8z" fill="none" stroke="#d91c2b" stroke-width=".51"/>
<path d="M160.9 88.8h.8v1.4h-.8z" fill="#d91c2b"/>
<path d="M160.9 88.8h.8v1.4h-.8z" fill="none" stroke="#d91c2b" stroke-width=".51"/>
<path d="M148.7 91.9h1.6v.4h-1.6z" fill="#d91c2b"/>
<path d="M148.7 91.9h1.6v.4h-1.6z" fill="none" stroke="#d91c2b" stroke-width=".34"/>
<path d="M148.7 93.2h1.6v.4h-1.6z" fill="#d91c2b"/>
<path d="M148.7 93.2h1.6v.4h-1.6z" fill="none" stroke="#d91c2b" stroke-width=".34"/>
<path d="M148.7 94.5h1.6v.3h-1.6z" fill="#d91c2b"/>
<path d="M148.7 94.5h1.6v.3h-1.6z" fill="none" stroke="#d91c2b" stroke-width=".34"/>
<path d="M148.7 95.8h1.6v.3h-1.6z" fill="#d91c2b"/>
<path d="M148.7 95.8h1.6v.3h-1.6z" fill="none" stroke="#d91c2b" stroke-width=".34"/>
<path d="M148.7 97h1.6v.4h-1.6z" fill="#d91c2b"/>
<path d="M148.7 97h1.6v.4h-1.6z" fill="none" stroke="#d91c2b" stroke-width=".34"/>
<path d="M162 104.6h1.5v.4h-1.5z" fill="#d91c2b"/>
<path d="M162 104.6h1.5v.4h-1.5z" fill="none" stroke="#d91c2b" stroke-width=".34"/>
<path d="M162 103.4h1.5v.3h-1.5z" fill="#d91c2b"/>
<path d="M162 103.4h1.5v.3h-1.5z" fill="none" stroke="#d91c2b" stroke-width=".34"/>
<path d="M162 102.1h1.5v.3h-1.5z" fill="#d91c2b"/>
<path d="M162 102.1h1.5v.3h-1.5z" fill="none" stroke="#d91c2b" stroke-width=".34"/>
<path d="M162 100.8h1.5v.4h-1.5z" fill="#d91c2b"/>
<path d="M162 100.8h1.5v.4h-1.5z" fill="none" stroke="#d91c2b" stroke-width=".34"/>
<path d="M162 99.6h1.5v.3h-1.5z" fill="#d91c2b"/>
<path d="M162 99.6h1.5v.3h-1.5z" fill="none" stroke="#d91c2b" stroke-width=".34"/>
<path d="M162 98.3h1.5v.3h-1.5z" fill="#d91c2b"/>
<path d="M162 98.3h1.5v.3h-1.5z" fill="none" stroke="#d91c2b" stroke-width=".34"/>
<path d="M162 97h1.5v.4h-1.5z" fill="#d91c2b"/>
<path d="M162 97h1.5v.4h-1.5z" fill="none" stroke="#d91c2b" stroke-width=".34"/>
<path d="M162 95.8h1.5v.3h-1.5z" fill="#d91c2b"/>
<path d="M162 95.8h1.5v.3h-1.5z" fill="none" stroke="#d91c2b" stroke-width=".34"/>
<path d="M162 94.5h1.5v.3h-1.5z" fill="#d91c2b"/>
<path d="M162 94.5h1.5v.3h-1.5z" fill="none" stroke="#d91c2b" stroke-width=".34"/>
<path d="M162 93.2h1.5v.4h-1.5z" fill="#d91c2b"/>
<path d="M162 93.2h1.5v.4h-1.5z" fill="none" stroke="#d91c2b" stroke-width=".34"/>
<path d="M162 91.9h1.5v.4h-1.5z" fill="#d91c2b"/>
<path d="M162 91.9h1.5v.4h-1.5z" fill="none" stroke="#d91c2b" stroke-width=".34"/>
<path d="M114.8 103.6h1.1v1.1h-1.1z" fill="#d91c2b"/>
<path d="M114.8 103.6h1.1v1.1h-1.1z" fill="none" stroke="#d91c2b" stroke-width=".51"/>
<g fill="#d91c2b">
<path d="M132.7 109.1h.7v1.2h-.7z"/>
<circle cx="115.3" cy="106.8" r=".8"/>
<circle cx="115.3" cy="109.3" r=".8"/>
<circle cx="115.3" cy="111.8" r=".8"/>
<circle cx="115.3" cy="114.4" r=".8"/>
<circle cx="130.6" cy="111.8" r=".8"/>
<circle cx="130.6" cy="109.3" r=".8"/>
</g>
<path d="M132.7 109.1h.7v1.2h-.7z" fill="none" stroke="#d91c2b" stroke-width=".51"/>
<path d="M135.7 109.1h.9v1.2h-.9z" fill="#d91c2b"/>
<path d="M135.7 109.1h.9v1.2h-.9z" fill="none" stroke="#d91c2b" stroke-width=".51"/>
<g fill="#d91c2b">
<path d="M141 118.3h.8v.3h-.8z"/>
<path d="M141 118.8h.8v.3h-.8z"/>
<path d="M141 119.3h.8v.2h-.8z"/>
<path d="M141 119.8h.8v.3h-.8z"/>
<path d="M141 120.3h.8v.3h-.8z"/>
<path d="M141 120.8h.8v.3h-.8z"/>
<path d="M141 121.3h.8v.3h-.8z"/>
<path d="M141 121.8h.8v.3h-.8z"/>
<path d="M142.7 121.8h.9v.3h-.9z"/>
<path d="M142.7 121.3h.9v.3h-.9z"/>
<path d="M142.7 120.8h.9v.3h-.9z"/>
<path d="M142.7 120.3h.9v.3h-.9z"/>
<path d="M142.7 119.8h.9v.3h-.9z"/>
<path d="M142.7 119.3h.9v.2h-.9z"/>
<path d="M142.7 118.8h.9v.3h-.9z"/>
<path d="M142.7 118.3h.9v.3h-.9z"/>
<path d="M141.2 104.8h.9v.3h-.9z"/>
<path d="M141.2 105.3h.9v.3h-.9z"/>
<path d="M141.2 105.7h.9v.4h-.9z"/>
<path d="M141.2 106.3h.9v.3h-.9z"/>
<path d="M141.2 106.8h.9v.3h-.9z"/>
<path d="M141.2 107.3h.9v.3h-.9z"/>
<path d="M141.2 107.8h.9v.3h-.9z"/>
<path d="M141.2 108.3h.9v.3h-.9z"/>
<path d="M124.3 103.5h1.3v.7h-1.3z"/>
<circle cx="130.6" cy="106.8" r=".8"/>
<circle cx="130.6" cy="104.2" r=".8"/>
</g>
<path d="M124.3 103.5h1.3v.7h-1.3z" fill="none" stroke="#d91c2b" stroke-width=".51"/>
<path d="M124.3 106.5h1.3v.9h-1.3z" fill="#d91c2b"/>
<path d="M124.3 106.5h1.3v.9h-1.3z" fill="none" stroke="#d91c2b" stroke-width=".51"/>
<path d="M126.3 98.9h1.3v.8h-1.3z" fill="#d91c2b"/>
<path d="M126.3 98.9h1.3v.8h-1.3z" fill="none" stroke="#d91c2b" stroke-width=".51"/>
<path d="M126.3 95.8h1.3v.8h-1.3z" fill="#d91c2b"/>
<path d="M126.3 95.8h1.3v.8h-1.3z" fill="none" stroke="#d91c2b" stroke-width=".51"/>
<g fill="#d91c2b">
<path d="M143 46.6h1.4v.7h-1.4z"/>
<circle cx="146.7" cy="82.5" r=".8"/>
<circle cx="140.7" cy="82.5" r=".8"/>
<circle cx="140.7" cy="79.9" r=".8"/>
<circle cx="140.7" cy="74.8" r=".8"/>
<circle cx="125.5" cy="77.4" r=".8"/>
<circle cx="125.5" cy="79.9" r=".8"/>
<circle cx="125.5" cy="82.5" r=".8"/>
<circle cx="140.7" cy="77.4" r=".8"/>
<circle cx="140.7" cy="72.3" r=".8"/>
<circle cx="140.7" cy="69.8" r=".8"/>
<circle cx="140.7" cy="67.2" r=".8"/>
<circle cx="140.7" cy="64.7" r=".8"/>
<circle cx="140.7" cy="62.1" r=".8"/>
<circle cx="140.7" cy="59.6" r=".8"/>
<circle cx="140.7" cy="57.1" r=".8"/>
<circle cx="140.7" cy="54.5" r=".8"/>
<circle cx="140.7" cy="52" r=".8"/>
<circle cx="140.7" cy="49.4" r=".8"/>
<circle cx="140.7" cy="46.9" r=".8"/>
<circle cx="140.7" cy="44.4" r=".8"/>
</g>
<path d="M143 46.6h1.4v.7h-1.4z" fill="none" stroke="#d91c2b" stroke-width=".51"/>
<path d="M148.9 120.3h1.6v.4h-1.6z" fill="#d91c2b"/>
<path d="M148.9 120.3h1.6v.3h-1.6z" fill="none" stroke="#d91c2b" stroke-width=".34"/>
<path d="M148.9 121.6h1.6v.3h-1.6z" fill="#d91c2b"/>
<path d="M148.9 121.6h1.6v.3h-1.6z" fill="none" stroke="#d91c2b" stroke-width=".34"/>
<path d="M161.4 113.4h.8v1.2h-.8z" fill="#d91c2b"/>
<path d="M161.4 113.4h.8v1.2h-.8z" fill="none" stroke="#d91c2b" stroke-width=".51"/>
<path d="M164.5 113.4h.9v1.2h-.9z" fill="#d91c2b"/>
<path d="M164.5 113.4h.9v1.2h-.9z" fill="none" stroke="#d91c2b" stroke-width=".51"/>
<path d="M148.9 116.5h1.6v.3h-1.6z" fill="#d91c2b"/>
<path d="M148.9 116.5h1.6v.3h-1.6z" fill="none" stroke="#d91c2b" stroke-width=".34"/>
<path d="M148.9 117.8h1.6v.3h-1.6z" fill="#d91c2b"/>
<path d="M148.9 117.8h1.6v.3h-1.6z" fill="none" stroke="#d91c2b" stroke-width=".34"/>
<path d="M148.9 119h1.6v.4h-1.6z" fill="#d91c2b"/>
<path d="M148.9 119h1.6v.4h-1.6z" fill="none" stroke="#d91c2b" stroke-width=".34"/>
<g fill="#d91c2b">
<path d="M143 108.3h.8v.3h-.8z"/>
<path d="M148.7 108.5h1.6v.3h-1.6z"/>
</g>
<path d="M148.7 108.5h1.6v.3h-1.6z" fill="none" stroke="#d91c2b" stroke-width=".34"/>
<path d="M148.7 109.7h1.6v.4h-1.6z" fill="#d91c2b"/>
<path d="M148.7 109.7h1.6v.4h-1.6z" fill="none" stroke="#d91c2b" stroke-width=".34"/>
<path d="M148.7 111h1.6v.3h-1.6z" fill="#d91c2b"/>
<path d="M148.7 111h1.6v.3h-1.6z" fill="none" stroke="#d91c2b" stroke-width=".34"/>
<g fill="#d91c2b">
<path d="M143 107.8h.8v.3h-.8z"/>
<path d="M143 107.3h.8v.3h-.8z"/>
<path d="M143 106.8h.8v.3h-.8z"/>
<path d="M143 106.3h.8v.3h-.8z"/>
<path d="M143 105.7h.8v.4h-.8z"/>
<path d="M143 105.3h.8v.3h-.8z"/>
<path d="M143 104.8h.8v.3h-.8z"/>
<path d="M148.7 98.3h1.6v.3h-1.6z"/>
</g>
<path d="M148.7 98.3h1.6v.3h-1.6z" fill="none" stroke="#d91c2b" stroke-width=".34"/>
<path d="M148.7 99.6h1.6v.3h-1.6z" fill="#d91c2b"/>
<path d="M148.7 99.6h1.6v.3h-1.6z" fill="none" stroke="#d91c2b" stroke-width=".34"/>
<path d="M148.7 100.8h1.6v.4h-1.6z" fill="#d91c2b"/>
<path d="M148.7 100.8h1.6v.4h-1.6z" fill="none" stroke="#d91c2b" stroke-width=".34"/>
<path d="M148.7 102.1h1.6v.3h-1.6z" fill="#d91c2b"/>
<path d="M148.7 102.1h1.6v.3h-1.6z" fill="none" stroke="#d91c2b" stroke-width=".34"/>
<path d="M148.7 103.4h1.6v.3h-1.6z" fill="#d91c2b"/>
<path d="M148.7 103.4h1.6v.3h-1.6z" fill="none" stroke="#d91c2b" stroke-width=".34"/>
<path d="M148.7 104.6h1.6v.4h-1.6z" fill="#d91c2b"/>
<path d="M148.7 104.6h1.6v.4h-1.6z" fill="none" stroke="#d91c2b" stroke-width=".34"/>
<path d="M148.7 105.9h1.6v.4h-1.6z" fill="#d91c2b"/>
<path d="M148.7 105.9h1.6v.4h-1.6z" fill="none" stroke="#d91c2b" stroke-width=".34"/>
<path d="M148.7 107.2h1.6v.3h-1.6z" fill="#d91c2b"/>
<path d="M148.7 107.2h1.6v.3h-1.6z" fill="none" stroke="#d91c2b" stroke-width=".34"/>
<path d="M162 111h1.5v.3h-1.5z" fill="#d91c2b"/>
<path d="M162 111h1.5v.3h-1.5z" fill="none" stroke="#d91c2b" stroke-width=".34"/>
<path d="M162 109.7h1.5v.4h-1.5z" fill="#d91c2b"/>
<path d="M162 109.7h1.5v.4h-1.5z" fill="none" stroke="#d91c2b" stroke-width=".34"/>
<path d="M162 108.5h1.5v.3h-1.5z" fill="#d91c2b"/>
<path d="M162 108.5h1.5v.3h-1.5z" fill="none" stroke="#d91c2b" stroke-width=".34"/>
<path d="M162 107.2h1.5v.3h-1.5z" fill="#d91c2b"/>
<path d="M162 107.2h1.5v.3h-1.5z" fill="none" stroke="#d91c2b" stroke-width=".34"/>
<path d="M162 105.9h1.5v.4h-1.5z" fill="#d91c2b"/>
<path d="M162 105.9h1.5v.4h-1.5z" fill="none" stroke="#d91c2b" stroke-width=".34"/>
<g fill="#d91c2b">
<path d="M104.8 85.9h1.3v.9h-1.3z"/>
<circle cx="104.5" cy="69.8" r=".8"/>
<circle cx="104.5" cy="72.3" r=".8"/>
<circle cx="104.5" cy="74.8" r=".8"/>
<circle cx="98.5" cy="74.8" r=".8"/>
<circle cx="98.5" cy="72.3" r=".8"/>
<circle cx="98.5" cy="69.8" r=".8"/>
<circle cx="104.5" cy="82.5" r=".8"/>
<circle cx="119.7" cy="82.5" r=".8"/>
<circle cx="119.7" cy="79.9" r=".8"/>
<circle cx="119.7" cy="77.4" r=".8"/>
</g>
<path d="M104.8 85.9h1.3v.9h-1.3z" fill="none" stroke="#d91c2b" stroke-width=".51"/>
<g fill="#d91c2b">
<path d="M70.6 75.9h1.7v1.7h-1.7z"/>
<path d="M94.9 92.1h1.1v2.5h-1.1z"/>
<circle cx="71.5" cy="74.2" r=".89"/>
<circle cx="71.5" cy="71.6" r=".89"/>
<circle cx="71.5" cy="69.1" r=".89"/>
<circle cx="71.5" cy="66.5" r=".89"/>
</g>
<path d="M94.9 92.1h1.1v2.5h-1.1z" fill="none" stroke="#d91c2b" stroke-width=".51"/>
<path d="M94.9 96.5h1.1v2.5h-1.1z" fill="#d91c2b"/>
<path d="M94.9 96.5h1.1v2.5h-1.1z" fill="none" stroke="#d91c2b" stroke-width=".51"/>
<path d="M89.3 87.5h1.3v.7h-1.3z" fill="#d91c2b"/>
<path d="M89.3 87.5h1.3v.7h-1.3z" fill="none" stroke="#d91c2b" stroke-width=".51"/>
<path d="M95.8 86.5h1.2v.9h-1.2z" fill="#d91c2b"/>
<path d="M95.8 86.5h1.2v.9h-1.2z" fill="none" stroke="#d91c2b" stroke-width=".51"/>
<path d="M95.8 89.7h1.2v.7h-1.2z" fill="#d91c2b"/>
<path d="M95.8 89.7h1.2v.7h-1.2z" fill="none" stroke="#d91c2b" stroke-width=".51"/>
<path d="M89.3 90.5h1.3v.9h-1.3z" fill="#d91c2b"/>
<path d="M89.3 90.5h1.3v.9h-1.3z" fill="none" stroke="#d91c2b" stroke-width=".51"/>
<path d="M83.5 94.8h.9v1.3h-.9z" fill="#d91c2b"/>
<path d="M83.5 94.8h.9v1.3h-.9z" fill="none" stroke="#d91c2b" stroke-width=".51"/>
<path d="M86.4 94.8h1v1.3h-1z" fill="#d91c2b"/>
<path d="M86.4 94.8h1v1.3h-1z" fill="none" stroke="#d91c2b" stroke-width=".51"/>
<g fill="#d91c2b">
<path d="M74.3 83.8h1.3v.7h-1.3z"/>
<circle cx="72" cy="93" r="2.84"/>
</g>
<path d="M74.3 83.8h1.3v.7h-1.3z" fill="none" stroke="#d91c2b" stroke-width=".51"/>
<path d="M74.7 86.1h.6" fill="none" stroke="#d91c2b" stroke-width="1.2"/>
<g fill="#d91c2b">
<path d="M124.9 43.8h1.1v1.1h-1.1z"/>
<circle cx="83.2" cy="69.8" r=".8"/>
<circle cx="83.2" cy="72.3" r=".8"/>
<circle cx="83.2" cy="74.8" r=".8"/>
<circle cx="83.2" cy="77.4" r=".8"/>
<circle cx="83.2" cy="79.9" r=".8"/>
<circle cx="83.2" cy="82.5" r=".8"/>
<circle cx="104.5" cy="77.4" r=".8"/>
<circle cx="104.5" cy="79.9" r=".8"/>
<circle cx="98.5" cy="82.5" r=".8"/>
<circle cx="98.5" cy="79.9" r=".8"/>
<circle cx="98.5" cy="77.4" r=".8"/>
<circle cx="119.7" cy="69.8" r=".8"/>
<circle cx="119.7" cy="67.2" r=".8"/>
<circle cx="119.7" cy="64.7" r=".8"/>
<circle cx="125.5" cy="67.2" r=".8"/>
<circle cx="119.7" cy="62.1" r=".8"/>
<circle cx="119.7" cy="59.6" r=".8"/>
<circle cx="119.7" cy="57.1" r=".8"/>
<circle cx="119.7" cy="54.5" r=".8"/>
<circle cx="125.5" cy="62.1" r=".8"/>
<circle cx="125.5" cy="64.7" r=".8"/>
<circle cx="119.7" cy="49.4" r=".8"/>
<circle cx="119.7" cy="46.9" r=".8"/>
<circle cx="119.7" cy="44.4" r=".8"/>
</g>
<path d="M124.9 43.8h1.1v1.1h-1.1z" fill="none" stroke="#d91c2b" stroke-width=".51"/>
<g fill="#d91c2b">
<path d="M122 43.4h1.4v.8h-1.4z"/>
<circle cx="125.5" cy="46.9" r=".8"/>
</g>
<path d="M122 43.4h1.4v.8h-1.4z" fill="none" stroke="#d91c2b" stroke-width=".51"/>
<path d="M122 46.6h1.4v.7h-1.4z" fill="#d91c2b"/>
<path d="M122 46.6h1.4v.7h-1.4z" fill="none" stroke="#d91c2b" stroke-width=".51"/>
<g fill="#d91c2b">
<path d="M100.3 87h1.2v.3h-1.2z"/>
<circle cx="119.7" cy="52" r=".8"/>
<circle cx="125.5" cy="49.4" r=".8"/>
<circle cx="125.5" cy="52" r=".8"/>
<circle cx="125.5" cy="54.5" r=".8"/>
<circle cx="125.5" cy="57.1" r=".8"/>
<circle cx="125.5" cy="59.6" r=".8"/>
<circle cx="119.7" cy="74.8" r=".8"/>
<circle cx="119.7" cy="72.3" r=".8"/>
<circle cx="125.5" cy="69.8" r=".8"/>
<circle cx="125.5" cy="72.3" r=".8"/>
<circle cx="125.5" cy="74.8" r=".8"/>
</g>
<path d="M100.3 87h1.2v.3h-1.2z" fill="none" stroke="#d91c2b" stroke-width=".34"/>
<path d="M100.3 88.9h1.2v.3h-1.2z" fill="#d91c2b"/>
<path d="M100.3 88.9h1.2v.3h-1.2z" fill="none" stroke="#d91c2b" stroke-width=".34"/>
<path d="M102.2 88h1.2v.2h-1.2z" fill="#d91c2b"/>
<path d="M102.2 88h1.2v.2h-1.2z" fill="none" stroke="#d91c2b" stroke-width=".34"/>
<g fill="#d91c2b">
<path d="M111.3 90.6h.7v.2h-.7z"/>
<path d="M104.8 89.1h1.3v.7h-1.3z"/>
</g>
<path d="M104.8 89.1h1.3v.7h-1.3z" fill="none" stroke="#d91c2b" stroke-width=".51"/>
<path d="M101.6 92h1.1v2.6h-1.1z" fill="#d91c2b"/>
<path d="M101.6 92h1.1v2.6h-1.1z" fill="none" stroke="#d91c2b" stroke-width=".51"/>
<path d="M101.6 96.4h1.1v2.6h-1.1z" fill="#d91c2b"/>
<path d="M101.6 96.4h1.1v2.6h-1.1z" fill="none" stroke="#d91c2b" stroke-width=".51"/>
<path d="M107.3 100.7h1.3v.8h-1.3z" fill="#d91c2b"/>
<path d="M107.3 100.7h1.3v.8h-1.3z" fill="none" stroke="#d91c2b" stroke-width=".51"/>
<path d="M107.3 97.5h1.3v.9h-1.3z" fill="#d91c2b"/>
<path d="M107.3 97.5h1.3v.9h-1.3z" fill="none" stroke="#d91c2b" stroke-width=".51"/>
<g fill="#d91c2b">
<path d="M111.3 91.1h.7v.3h-.7z"/>
<path d="M111.3 91.5h.7v.4h-.7z"/>
<path d="M111.3 92h.7v.4h-.7z"/>
<path d="M111.3 92.5h.7v.4h-.7z"/>
<path d="M111.3 93h.7v.4h-.7z"/>
<path d="M111.3 93.6h.7v.3h-.7z"/>
<path d="M111.3 94.1h.7v.2h-.7z"/>
<path d="M113 94.1h.9v.2h-.9z"/>
<path d="M113 93.6h.9v.3h-.9z"/>
<path d="M113 93h.9v.4h-.9z"/>
<path d="M113 92.5h.9v.4h-.9z"/>
<path d="M113 92h.9v.4h-.9z"/>
<path d="M113 91.5h.9v.4h-.9z"/>
<path d="M113 91.1h.9v.3h-.9z"/>
<path d="M113 90.6h.9v.2h-.9z"/>
<path d="M82.6 43.8h1.1v1.1h-1.1z"/>
<circle cx="104.5" cy="49.4" r=".8"/>
<circle cx="104.5" cy="52" r=".8"/>
<circle cx="104.5" cy="54.5" r=".8"/>
<circle cx="98.5" cy="49.4" r=".8"/>
<circle cx="104.5" cy="57.1" r=".8"/>
<circle cx="104.5" cy="59.6" r=".8"/>
<circle cx="104.5" cy="62.1" r=".8"/>
<circle cx="98.5" cy="59.6" r=".8"/>
<circle cx="98.5" cy="57.1" r=".8"/>
<circle cx="98.5" cy="54.5" r=".8"/>
<circle cx="98.5" cy="52" r=".8"/>
<circle cx="71.5" cy="64" r=".89"/>
<circle cx="71.5" cy="61.5" r=".89"/>
<circle cx="71.5" cy="58.9" r=".89"/>
<circle cx="71.5" cy="56.4" r=".89"/>
<circle cx="72" cy="46" r="2.84"/>
</g>
<path d="M82.6 43.8h1.1v1.1h-1.1z" fill="none" stroke="#d91c2b" stroke-width=".51"/>
<g fill="#d91c2b">
<path d="M103.9 43.8h1.1v1.1h-1.1z"/>
<circle cx="83.2" cy="46.9" r=".8"/>
<circle cx="83.2" cy="49.4" r=".8"/>
<circle cx="83.2" cy="52" r=".8"/>
<circle cx="83.2" cy="54.5" r=".8"/>
<circle cx="83.2" cy="57.1" r=".8"/>
<circle cx="83.2" cy="59.6" r=".8"/>
<circle cx="83.2" cy="62.1" r=".8"/>
<circle cx="83.2" cy="64.7" r=".8"/>
<circle cx="83.2" cy="67.2" r=".8"/>
<circle cx="104.5" cy="64.7" r=".8"/>
<circle cx="104.5" cy="67.2" r=".8"/>
<circle cx="98.5" cy="67.2" r=".8"/>
<circle cx="98.5" cy="64.7" r=".8"/>
<circle cx="98.5" cy="62.1" r=".8"/>
</g>
<path d="M103.9 43.8h1.1v1.1h-1.1z" fill="none" stroke="#d91c2b" stroke-width=".51"/>
<g fill="#d91c2b">
<path d="M100.8 43.4h1.3v.8h-1.3z"/>
<circle cx="104.5" cy="46.9" r=".8"/>
<circle cx="98.5" cy="46.9" r=".8"/>
<circle cx="98.5" cy="44.4" r=".8"/>
</g>
<path d="M100.8 43.4h1.3v.8h-1.3z" fill="none" stroke="#d91c2b" stroke-width=".51"/>
<path d="M100.8 46.6h1.3v.7h-1.3z" fill="#d91c2b"/>
<path d="M100.8 46.6h1.3v.7h-1.3z" fill="none" stroke="#d91c2b" stroke-width=".51"/>
<path d="M94.5 103.6h1.1v1.1h-1.1z" fill="#d91c2b"/>
<path d="M94.5 103.6h1.1v1.1h-1.1z" fill="none" stroke="#d91c2b" stroke-width=".51"/>
<g fill="#d91c2b">
<path d="M98.1 104h1.4v.8h-1.4z"/>
<circle cx="95" cy="106.8" r=".8"/>
<circle cx="95" cy="109.3" r=".8"/>
<circle cx="95" cy="111.8" r=".8"/>
<circle cx="95" cy="114.4" r=".8"/>
</g>
<path d="M98.1 104h1.4v.8h-1.4z" fill="none" stroke="#d91c2b" stroke-width=".51"/>
<path d="M98.1 107.1h1.4v.9h-1.4z" fill="#d91c2b"/>
<path d="M98.1 107.1h1.4v.8h-1.4z" fill="none" stroke="#d91c2b" stroke-width=".51"/>
<g fill="#d91c2b">
<path d="M166.9 56.7h1.7v.4h-1.7z"/>
<circle cx="95" cy="116.9" r=".8"/>
<circle cx="95" cy="119.5" r=".8"/>
<circle cx="95" cy="122" r=".8"/>
<circle cx="95" cy="124.5" r=".8"/>
<circle cx="95" cy="127.1" r=".8"/>
<circle cx="95" cy="129.6" r=".8"/>
<circle cx="95" cy="132.2" r=".8"/>
<circle cx="95" cy="134.7" r=".8"/>
<circle cx="95" cy="137.2" r=".8"/>
<circle cx="95" cy="139.8" r=".8"/>
<circle cx="84.9" cy="144.9" r="2.84"/>
<circle cx="95" cy="142.3" r=".8"/>
<circle cx="110.2" cy="142.3" r=".8"/>
<circle cx="110.2" cy="139.8" r=".8"/>
<circle cx="110.2" cy="137.2" r=".8"/>
<circle cx="110.2" cy="134.7" r=".8"/>
<circle cx="110.2" cy="132.2" r=".8"/>
<circle cx="110.2" cy="129.6" r=".8"/>
<circle cx="110.2" cy="127.1" r=".8"/>
<circle cx="110.2" cy="124.5" r=".8"/>
<circle cx="110.2" cy="122" r=".8"/>
<circle cx="110.2" cy="119.5" r=".8"/>
<circle cx="110.2" cy="116.9" r=".8"/>
<circle cx="110.2" cy="114.4" r=".8"/>
<circle cx="110.2" cy="111.8" r=".8"/>
<circle cx="110.2" cy="109.3" r=".8"/>
<circle cx="110.2" cy="106.8" r=".8"/>
<circle cx="110.2" cy="104.2" r=".8"/>
<circle cx="162" cy="49.4" r=".8"/>
<circle cx="162" cy="46.9" r=".8"/>
<circle cx="162" cy="44.4" r=".8"/>
</g>
<path d="M166.9 56.7h1.7v.4h-1.7z" fill="none" stroke="#d91c2b" stroke-width=".34"/>
<path d="M164.3 43.4h1.3v.8h-1.3z" fill="#d91c2b"/>
<path d="M164.3 43.4h1.3v.8h-1.3z" fill="none" stroke="#d91c2b" stroke-width=".51"/>
<path d="M164.3 46.6h1.3v.7h-1.3z" fill="#d91c2b"/>
<path d="M164.3 46.6h1.3v.7h-1.3z" fill="none" stroke="#d91c2b" stroke-width=".51"/>
<path d="M143 43.4h1.4v.8h-1.4z" fill="#d91c2b"/>
<path d="M143 43.4h1.4v.8h-1.4z" fill="none" stroke="#d91c2b" stroke-width=".51"/>
<path d="M193 42.9h2.3v2.1h-2.3z" fill="#d91c2b"/>
<path d="M193 42.9h2.3v2.1h-2.3z" fill="none" stroke="#d91c2b" stroke-width=".51"/>
<path d="M194 48h.4M194 51.9h.4" fill="none" stroke="#d91c2b" stroke-width="2.5"/>
<path d="M180.5 42.5h.9v1.3h-.9z" fill="#d91c2b"/>
<path d="M180.5 42.5h.9v1.3h-.9z" fill="none" stroke="#d91c2b" stroke-width=".51"/>
<path d="M179.7 50.4h1.2v.8h-1.2z" fill="#d91c2b"/>
<path d="M179.7 50.4h1.2v.8h-1.2z" fill="none" stroke="#d91c2b" stroke-width=".51"/>
<g fill="#d91c2b">
<path d="M180.6 46.7h.8v1.2h-.8z"/>
<circle cx="172" cy="46" r="2.84"/>
</g>
<path d="M180.6 46.7h.8v1.2h-.8z" fill="none" stroke="#d91c2b" stroke-width=".51"/>
<path d="M166.9 64.3h1.7v.4h-1.7z" fill="#d91c2b"/>
<path d="M166.9 64.3h1.7v.4h-1.7z" fill="none" stroke="#d91c2b" stroke-width=".34"/>
<path d="M171.9 64.3h1.6v.4h-1.6z" fill="#d91c2b"/>
<path d="M171.9 64.3h1.6v.4h-1.6z" fill="none" stroke="#d91c2b" stroke-width=".34"/>
<path d="M171.9 63.1h1.6v.3h-1.6z" fill="#d91c2b"/>
<path d="M171.9 63.1h1.6v.3h-1.6z" fill="none" stroke="#d91c2b" stroke-width=".34"/>
<path d="M171.9 61.8h1.6v.3h-1.6z" fill="#d91c2b"/>
<path d="M171.9 61.8h1.6v.3h-1.6z" fill="none" stroke="#d91c2b" stroke-width=".34"/>
<path d="M171.9 60.5h1.6v.4h-1.6z" fill="#d91c2b"/>
<path d="M171.9 60.5h1.6v.4h-1.6z" fill="none" stroke="#d91c2b" stroke-width=".34"/>
<path d="M171.9 59.3h1.6v.3h-1.6z" fill="#d91c2b"/>
<path d="M171.9 59.3h1.6v.3h-1.6z" fill="none" stroke="#d91c2b" stroke-width=".34"/>
<path d="M171.9 58h1.6v.3h-1.6z" fill="#d91c2b"/>
<path d="M171.9 58h1.6v.3h-1.6z" fill="none" stroke="#d91c2b" stroke-width=".34"/>
<path d="M171.9 56.7h1.6v.4h-1.6z" fill="#d91c2b"/>
<path d="M171.9 56.7h1.6v.4h-1.6z" fill="none" stroke="#d91c2b" stroke-width=".34"/>
<path d="M194 55.8h.4M194 59.8h.4M194 63.8h.4" fill="none" stroke="#d91c2b" stroke-width="2.5"/>
<path d="M187.5 56.5h1.4v.7h-1.4z" fill="#d91c2b"/>
<path d="M187.5 56.5h1.4v.7h-1.4z" fill="none" stroke="#d91c2b" stroke-width=".51"/>
<path d="M184.1 56.8h1.6v.3h-1.6z" fill="#d91c2b"/>
<path d="M184.1 56.8h1.6v.3h-1.6z" fill="none" stroke="#d91c2b" stroke-width=".34"/>
<path d="M175.7 57.2h1.3v.7h-1.3z" fill="#d91c2b"/>
<path d="M175.7 57.1h1.3v.8h-1.3z" fill="none" stroke="#d91c2b" stroke-width=".51"/>
<path d="M175.7 60.3h1.3v.7h-1.3z" fill="#d91c2b"/>
<path d="M175.7 60.3h1.3v.7h-1.3z" fill="none" stroke="#d91c2b" stroke-width=".51"/>
<path d="M179.7 53.5h1.2v.9h-1.2z" fill="#d91c2b"/>
<path d="M179.7 53.5h1.2v.9h-1.2z" fill="none" stroke="#d91c2b" stroke-width=".51"/>
<path d="M172.6 53.3h.9v1.2h-.9z" fill="#d91c2b"/>
<path d="M172.6 53.3h.9v1.2h-.9z" fill="none" stroke="#d91c2b" stroke-width=".51"/>
<path d="M175.8 53.3h.8v1.2h-.8z" fill="#d91c2b"/>
<path d="M175.8 53.3h.8v1.2h-.8z" fill="none" stroke="#d91c2b" stroke-width=".51"/>
<path d="M179.2 56.8h1.6v.3h-1.6z" fill="#d91c2b"/>
<path d="M179.2 56.8h1.6v.3h-1.6z" fill="none" stroke="#d91c2b" stroke-width=".34"/>
<path d="M183.6 42.5h.9v1.3h-.9z" fill="#d91c2b"/>
<path d="M183.6 42.5h.9v1.3h-.9z" fill="none" stroke="#d91c2b" stroke-width=".51"/>
<path d="M187.5 53.3h1.4v.9h-1.4z" fill="#d91c2b"/>
<path d="M187.5 53.3h1.4v.9h-1.4z" fill="none" stroke="#d91c2b" stroke-width=".51"/>
<path d="M183.6 46.7h.9v1.2h-.9z" fill="#d91c2b"/>
<path d="M183.6 46.7h.9v1.2h-.9z" fill="none" stroke="#d91c2b" stroke-width=".51"/>
<path d="M183.5 51.5h1.1v.2h-1.1z" fill="#d91c2b"/>
<path d="M183.5 51.5h1.1v.2h-1.1z" fill="none" stroke="#d91c2b" stroke-width=".34"/>
<path d="M183.5 53.3h1.1v.4h-1.1z" fill="#d91c2b"/>
<path d="M183.5 53.3h1.1v.4h-1.1z" fill="none" stroke="#d91c2b" stroke-width=".34"/>
<path d="M185.3 52.4h1.2v.3h-1.2z" fill="#d91c2b"/>
<path d="M185.3 52.4h1.2v.3h-1.2z" fill="none" stroke="#d91c2b" stroke-width=".34"/>
<path d="M166.9 58h1.7v.3h-1.7z" fill="#d91c2b"/>
<path d="M166.9 58h1.7v.3h-1.7z" fill="none" stroke="#d91c2b" stroke-width=".34"/>
<path d="M166.9 59.3h1.7v.3h-1.7z" fill="#d91c2b"/>
<path d="M166.9 59.3h1.7v.3h-1.7z" fill="none" stroke="#d91c2b" stroke-width=".34"/>
<path d="M166.9 60.5h1.7v.4h-1.7z" fill="#d91c2b"/>
<path d="M166.9 60.5h1.7v.4h-1.7z" fill="none" stroke="#d91c2b" stroke-width=".34"/>
<path d="M166.9 61.8h1.7v.3h-1.7z" fill="#d91c2b"/>
<path d="M166.9 61.8h1.7v.3h-1.7z" fill="none" stroke="#d91c2b" stroke-width=".34"/>
<path d="M166.9 63.1h1.7v.3h-1.7z" fill="#d91c2b"/>
<path d="M166.9 63.1h1.7v.3h-1.7z" fill="none" stroke="#d91c2b" stroke-width=".34"/>
<g fill="#d91c2b">
<path d="M168.6 71.6h.3v.9h-.3z"/>
<path d="M169.3 71.6h.5v.9h-.5z"/>
<path d="M170.2 71.6h.3v.9h-.3z"/>
<path d="M170.9 71.6h.5v.9h-.5z"/>
<path d="M170.9 69.8h.5v1h-.5z"/>
<path d="M170.2 69.8h.3v1h-.3z"/>
<path d="M169.3 69.8h.5v1h-.5z"/>
<path d="M168.6 69.8h.3v1h-.3z"/>
<path d="M179.8 70.7h.8v1.3h-.8z"/>
</g>
<path d="M179.8 70.7h.8v1.3h-.8z" fill="none" stroke="#d91c2b" stroke-width=".51"/>
<path d="M176.7 70.7h.8v1.3h-.8z" fill="#d91c2b"/>
<path d="M176.7 70.7h.8v1.3h-.8z" fill="none" stroke="#d91c2b" stroke-width=".51"/>
<g fill="#d91c2b">
<path d="M183.4 70.7h1v.5h-1z"/>
<path d="M183.9 70.3h.6v1.4h-.6z"/>
<path d="M176.8 67.5h.7v1.2h-.7z"/>
<circle cx="183.9" cy="71.2" r=".55"/>
<circle cx="183.9" cy="70.7" r=".55"/>
</g>
<path d="M176.8 67.5h.7v1.2h-.7z" fill="none" stroke="#d91c2b" stroke-width=".51"/>
<path d="M179.8 67.5h.9v1.2h-.9z" fill="#d91c2b"/>
<path d="M179.8 67.5h.9v1.2h-.9z" fill="none" stroke="#d91c2b" stroke-width=".51"/>
<g fill="#d91c2b">
<path d="M183.4 67.8h1v.5h-1z"/>
<path d="M183.9 67.3h.6v1.5h-.6z"/>
<path d="M184.7 67.3h1v1.5h-1z"/>
<path d="M186 67.8h1v.5h-1z"/>
<path d="M185.9 67.3h.6v1.5h-.6z"/>
<path d="M179.2 58.1h1.6v.2h-1.6z"/>
<circle cx="183.9" cy="68.3" r=".55"/>
<circle cx="183.9" cy="67.8" r=".55"/>
<circle cx="186.5" cy="68.3" r=".55"/>
<circle cx="186.5" cy="67.8" r=".55"/>
</g>
<path d="M179.2 58.1h1.6v.2h-1.6z" fill="none" stroke="#d91c2b" stroke-width=".34"/>
<path d="M179.2 59.4h1.6v.2h-1.6z" fill="#d91c2b"/>
<path d="M179.2 59.4h1.6v.2h-1.6z" fill="none" stroke="#d91c2b" stroke-width=".34"/>
<path d="M179.2 60.6h1.6v.3h-1.6z" fill="#d91c2b"/>
<path d="M179.2 60.6h1.6v.3h-1.6z" fill="none" stroke="#d91c2b" stroke-width=".34"/>
<path d="M179.2 61.9h1.6v.2h-1.6z" fill="#d91c2b"/>
<path d="M179.2 61.9h1.6v.2h-1.6z" fill="none" stroke="#d91c2b" stroke-width=".34"/>
<path d="M179.2 63.2h1.6v.2h-1.6z" fill="#d91c2b"/>
<path d="M179.2 63.2h1.6v.2h-1.6z" fill="none" stroke="#d91c2b" stroke-width=".34"/>
<path d="M179.2 64.4h1.6v.3h-1.6z" fill="#d91c2b"/>
<path d="M179.2 64.4h1.6v.3h-1.6z" fill="none" stroke="#d91c2b" stroke-width=".34"/>
<path d="M184.1 64.4h1.6v.3h-1.6z" fill="#d91c2b"/>
<path d="M184.1 64.4h1.6v.3h-1.6z" fill="none" stroke="#d91c2b" stroke-width=".34"/>
<path d="M184.1 63.2h1.6v.2h-1.6z" fill="#d91c2b"/>
<path d="M184.1 63.2h1.6v.2h-1.6z" fill="none" stroke="#d91c2b" stroke-width=".34"/>
<path d="M184.1 61.9h1.6v.2h-1.6z" fill="#d91c2b"/>
<path d="M184.1 61.9h1.6v.2h-1.6z" fill="none" stroke="#d91c2b" stroke-width=".34"/>
<path d="M184.1 60.6h1.6v.3h-1.6z" fill="#d91c2b"/>
<path d="M184.1 60.6h1.6v.3h-1.6z" fill="none" stroke="#d91c2b" stroke-width=".34"/>
<path d="M184.1 59.4h1.6v.2h-1.6z" fill="#d91c2b"/>
<path d="M184.1 59.4h1.6v.2h-1.6z" fill="none" stroke="#d91c2b" stroke-width=".34"/>
<path d="M184.1 58.1h1.6v.2h-1.6z" fill="#d91c2b"/>
<path d="M184.1 58.1h1.6v.2h-1.6z" fill="none" stroke="#d91c2b" stroke-width=".34"/>
<path d="M171.6 91.9h1.5v.2h-1.5z" fill="#d91c2b"/>
<path d="M171.6 91.9h1.5v.2h-1.5z" fill="none" stroke="#d91c2b" stroke-width=".34"/>
<path d="M171.6 93.1h1.5v.3h-1.5z" fill="#d91c2b"/>
<path d="M171.6 93.1h1.5v.3h-1.5z" fill="none" stroke="#d91c2b" stroke-width=".34"/>
<path d="M171.6 94.4h1.5v.3h-1.5z" fill="#d91c2b"/>
<path d="M171.6 94.4h1.5v.3h-1.5z" fill="none" stroke="#d91c2b" stroke-width=".34"/>
<path d="M171.6 95.7h1.5v.2h-1.5z" fill="#d91c2b"/>
<path d="M171.6 95.7h1.5v.2h-1.5z" fill="none" stroke="#d91c2b" stroke-width=".34"/>
<path d="M171.6 96.9h1.5v.3h-1.5z" fill="#d91c2b"/>
<path d="M171.6 96.9h1.5v.3h-1.5z" fill="none" stroke="#d91c2b" stroke-width=".34"/>
<path d="M184.9 94.4h1.5v.3h-1.5z" fill="#d91c2b"/>
<path d="M184.9 94.4h1.5v.3h-1.5z" fill="none" stroke="#d91c2b" stroke-width=".34"/>
<path d="M184.9 93.1h1.5v.3h-1.5z" fill="#d91c2b"/>
<path d="M184.9 93.1h1.5v.3h-1.5z" fill="none" stroke="#d91c2b" stroke-width=".34"/>
<path d="M184.9 91.9h1.5v.2h-1.5z" fill="#d91c2b"/>
<path d="M184.9 91.9h1.5v.2h-1.5z" fill="none" stroke="#d91c2b" stroke-width=".34"/>
<path d="M187.2 88.3h.8v1.4h-.8z" fill="#d91c2b"/>
<path d="M187.2 88.3h.8v1.4h-.8z" fill="none" stroke="#d91c2b" stroke-width=".51"/>
<path d="M184.1 88.3h.8v1.4h-.8z" fill="#d91c2b"/>
<path d="M184.1 88.3h.8v1.4h-.8z" fill="none" stroke="#d91c2b" stroke-width=".51"/>
<path d="M175.4 77h1.6v.3h-1.6z" fill="#d91c2b"/>
<path d="M175.4 77h1.6v.3h-1.6z" fill="none" stroke="#d91c2b" stroke-width=".34"/>
<path d="M175.4 78.2h1.6v.4h-1.6z" fill="#d91c2b"/>
<path d="M175.4 78.2h1.6v.4h-1.6z" fill="none" stroke="#d91c2b" stroke-width=".34"/>
<path d="M175.4 79.5h1.6v.3h-1.6z" fill="#d91c2b"/>
<path d="M175.4 79.5h1.6v.3h-1.6z" fill="none" stroke="#d91c2b" stroke-width=".34"/>
<path d="M175.4 80.8h1.6v.3h-1.6z" fill="#d91c2b"/>
<path d="M175.4 80.8h1.6v.3h-1.6z" fill="none" stroke="#d91c2b" stroke-width=".34"/>
<path d="M175.4 82h1.6v.4h-1.6z" fill="#d91c2b"/>
<path d="M175.4 82h1.6v.4h-1.6z" fill="none" stroke="#d91c2b" stroke-width=".34"/>
<path d="M175.4 83.3h1.6v.4h-1.6z" fill="#d91c2b"/>
<path d="M175.4 83.3h1.6v.4h-1.6z" fill="none" stroke="#d91c2b" stroke-width=".34"/>
<path d="M175.4 84.6h1.6v.3h-1.6z" fill="#d91c2b"/>
<path d="M175.4 84.6h1.6v.3h-1.6z" fill="none" stroke="#d91c2b" stroke-width=".34"/>
<path d="M175.4 85.9h1.6v.3h-1.6z" fill="#d91c2b"/>
<path d="M175.4 85.9h1.6v.3h-1.6z" fill="none" stroke="#d91c2b" stroke-width=".34"/>
<path d="M180.3 85.9h1.7v.3h-1.7z" fill="#d91c2b"/>
<path d="M180.3 85.9h1.7v.3h-1.7z" fill="none" stroke="#d91c2b" stroke-width=".34"/>
<path d="M180.3 84.6h1.7v.3h-1.7z" fill="#d91c2b"/>
<path d="M180.3 84.6h1.7v.3h-1.7z" fill="none" stroke="#d91c2b" stroke-width=".34"/>
<path d="M180.3 83.3h1.7v.4h-1.7z" fill="#d91c2b"/>
<path d="M180.3 83.3h1.7v.4h-1.7z" fill="none" stroke="#d91c2b" stroke-width=".34"/>
<path d="M180.3 82h1.7v.4h-1.7z" fill="#d91c2b"/>
<path d="M180.3 82h1.7v.4h-1.7z" fill="none" stroke="#d91c2b" stroke-width=".34"/>
<path d="M180.3 80.8h1.7v.3h-1.7z" fill="#d91c2b"/>
<path d="M180.3 80.8h1.7v.3h-1.7z" fill="none" stroke="#d91c2b" stroke-width=".34"/>
<path d="M180.3 79.5h1.7v.3h-1.7z" fill="#d91c2b"/>
<path d="M180.3 79.5h1.7v.3h-1.7z" fill="none" stroke="#d91c2b" stroke-width=".34"/>
<path d="M180.3 78.2h1.7v.4h-1.7z" fill="#d91c2b"/>
<path d="M180.3 78.2h1.7v.4h-1.7z" fill="none" stroke="#d91c2b" stroke-width=".34"/>
<path d="M180.3 77h1.7v.3h-1.7z" fill="#d91c2b"/>
<path d="M180.3 77h1.7v.3h-1.7z" fill="none" stroke="#d91c2b" stroke-width=".34"/>
<g fill="#d91c2b">
<path d="M183.4 73.7h1v.6h-1z"/>
<path d="M183.9 73.2h.6v1.6h-.6z"/>
<path d="M184.7 73.2h1v1.6h-1z"/>
<path d="M186 73.7h1v.6h-1z"/>
<path d="M185.9 73.2h.6v1.6h-.6z"/>
<path d="M184.7 70.3h1v1.4h-1z"/>
<path d="M186 70.7h1v.5h-1z"/>
<path d="M185.9 70.3h.6v1.4h-.6z"/>
<path d="M191.9 71.9h1.2v1.2h-1.2z"/>
<circle cx="183.9" cy="74.3" r=".55"/>
<circle cx="183.9" cy="73.7" r=".55"/>
<circle cx="186.5" cy="74.3" r=".55"/>
<circle cx="186.5" cy="73.7" r=".55"/>
<circle cx="186.5" cy="71.2" r=".55"/>
<circle cx="186.5" cy="70.7" r=".55"/>
</g>
<path d="M191.9 71.9h1.2v1.2h-1.2z" fill="none" stroke="#d91c2b" stroke-width=".51"/>
<g fill="#d91c2b">
<circle cx="195.1" cy="72.5" r=".89"/>
<circle cx="192.5" cy="75" r=".89"/>
<circle cx="195.1" cy="75" r=".89"/>
<circle cx="192.5" cy="77.6" r=".89"/>
<circle cx="195.1" cy="77.6" r=".89"/>
<circle cx="192.5" cy="80.1" r=".89"/>
<circle cx="195.1" cy="80.1" r=".89"/>
<circle cx="192.5" cy="82.6" r=".89"/>
<circle cx="195.1" cy="82.6" r=".89"/>
<circle cx="192.5" cy="85.2" r=".89"/>
<circle cx="195.1" cy="85.2" r=".89"/>
<circle cx="192.5" cy="87.7" r=".89"/>
<circle cx="195.1" cy="87.7" r=".89"/>
<circle cx="192.5" cy="90.3" r=".89"/>
<circle cx="195.1" cy="90.3" r=".89"/>
<circle cx="192.5" cy="92.8" r=".89"/>
<circle cx="195.1" cy="92.8" r=".89"/>
<circle cx="192.5" cy="95.3" r=".89"/>
<circle cx="195.1" cy="95.3" r=".89"/>
<circle cx="192.5" cy="97.9" r=".89"/>
<circle cx="195.1" cy="97.9" r=".89"/>
<circle cx="192.5" cy="100.4" r=".89"/>
<circle cx="195.1" cy="100.4" r=".89"/>
<circle cx="192.5" cy="103" r=".89"/>
<circle cx="195.1" cy="103" r=".89"/>
<circle cx="192.5" cy="105.5" r=".89"/>
<circle cx="195.1" cy="105.5" r=".89"/>
<circle cx="192.5" cy="108" r=".89"/>
<circle cx="195.1" cy="108" r=".89"/>
<circle cx="192.5" cy="110.6" r=".89"/>
<circle cx="195.1" cy="110.6" r=".89"/>
<circle cx="192.5" cy="113.1" r=".89"/>
<circle cx="195.1" cy="113.1" r=".89"/>
</g>
<g fill="#000">
<circle cx="71.5" cy="56.4" r=".72"/>
<circle cx="71.5" cy="58.9" r=".72"/>
<circle cx="71.5" cy="56.4" r=".55"/>
<circle cx="71.5" cy="58.9" r=".55"/>
<circle cx="72" cy="46" r="1.82"/>
<circle cx="72" cy="46" r="1.65"/>
<circle cx="83.2" cy="54.5" r=".47"/>
<circle cx="83.2" cy="49.4" r=".47"/>
<circle cx="83.2" cy="57.1" r=".47"/>
<circle cx="83.2" cy="44.4" r=".47"/>
<circle cx="83.2" cy="46.9" r=".47"/>
<circle cx="83.2" cy="59.6" r=".47"/>
<circle cx="83.2" cy="52" r=".47"/>
<circle cx="83.2" cy="46.9" r=".64"/>
<circle cx="83.2" cy="59.6" r=".64"/>
<circle cx="83.2" cy="52" r=".64"/>
<circle cx="83.2" cy="57.1" r=".64"/>
<circle cx="83.2" cy="49.4" r=".64"/>
<circle cx="83.2" cy="44.4" r=".64"/>
<circle cx="83.2" cy="54.5" r=".64"/>
<circle cx="98.5" cy="54.5" r=".47"/>
<circle cx="98.5" cy="49.4" r=".47"/>
<circle cx="98.5" cy="57.1" r=".47"/>
<circle cx="98.5" cy="44.4" r=".47"/>
<circle cx="98.5" cy="59.6" r=".47"/>
<circle cx="98.5" cy="46.9" r=".47"/>
<circle cx="98.5" cy="52" r=".47"/>
<circle cx="98.5" cy="59.6" r=".64"/>
<circle cx="98.5" cy="46.9" r=".64"/>
<circle cx="98.5" cy="52" r=".64"/>
<circle cx="98.5" cy="49.4" r=".64"/>
<circle cx="98.5" cy="57.1" r=".64"/>
<circle cx="98.5" cy="44.4" r=".64"/>
<circle cx="98.5" cy="54.5" r=".64"/>
<circle cx="104.5" cy="54.5" r=".47"/>
<circle cx="104.5" cy="49.4" r=".47"/>
<circle cx="104.5" cy="46.9" r=".47"/>
<circle cx="104.5" cy="44.4" r=".47"/>
<circle cx="104.5" cy="57.1" r=".47"/>
<circle cx="104.5" cy="59.6" r=".47"/>
<circle cx="104.5" cy="52" r=".47"/>
<circle cx="104.5" cy="46.9" r=".64"/>
<circle cx="104.5" cy="59.6" r=".64"/>
<circle cx="104.5" cy="52" r=".64"/>
<circle cx="104.5" cy="57.1" r=".64"/>
<circle cx="104.5" cy="44.4" r=".64"/>
<circle cx="104.5" cy="49.4" r=".64"/>
<circle cx="104.5" cy="54.5" r=".64"/>
<circle cx="119.7" cy="49.4" r=".47"/>
<circle cx="119.7" cy="54.5" r=".47"/>
<circle cx="119.7" cy="59.6" r=".47"/>
<circle cx="119.7" cy="44.4" r=".47"/>
<circle cx="119.7" cy="46.9" r=".47"/>
<circle cx="119.7" cy="57.1" r=".47"/>
<circle cx="119.7" cy="52" r=".47"/>
<circle cx="119.7" cy="59.6" r=".64"/>
<circle cx="119.7" cy="46.9" r=".64"/>
<circle cx="119.7" cy="52" r=".64"/>
<circle cx="119.7" cy="49.4" r=".64"/>
<circle cx="119.7" cy="44.4" r=".64"/>
<circle cx="119.7" cy="57.1" r=".64"/>
<circle cx="119.7" cy="54.5" r=".64"/>
<circle cx="125.5" cy="54.5" r=".47"/>
<circle cx="125.5" cy="49.4" r=".47"/>
<circle cx="125.5" cy="46.9" r=".47"/>
<circle cx="125.5" cy="57.1" r=".47"/>
<circle cx="125.5" cy="44.4" r=".47"/>
<circle cx="125.5" cy="59.6" r=".47"/>
<circle cx="125.5" cy="52" r=".47"/>
<circle cx="125.5" cy="59.6" r=".64"/>
<circle cx="125.5" cy="46.9" r=".64"/>
<circle cx="125.5" cy="52" r=".64"/>
<circle cx="125.5" cy="57.1" r=".64"/>
<circle cx="125.5" cy="49.4" r=".64"/>
<circle cx="125.5" cy="44.4" r=".64"/>
<circle cx="125.5" cy="54.5" r=".64"/>
<circle cx="140.7" cy="54.5" r=".47"/>
<circle cx="140.7" cy="49.4" r=".47"/>
<circle cx="140.7" cy="59.6" r=".47"/>
<circle cx="140.7" cy="57.1" r=".47"/>
<circle cx="140.7" cy="46.9" r=".47"/>
<circle cx="140.7" cy="44.4" r=".47"/>
<circle cx="140.7" cy="52" r=".47"/>
<circle cx="140.7" cy="46.9" r=".64"/>
<circle cx="140.7" cy="59.6" r=".64"/>
<circle cx="140.7" cy="52" r=".64"/>
<circle cx="140.7" cy="44.4" r=".64"/>
<circle cx="140.7" cy="57.1" r=".64"/>
<circle cx="140.7" cy="49.4" r=".64"/>
<circle cx="140.7" cy="54.5" r=".64"/>
<circle cx="146.7" cy="54.5" r=".47"/>
<circle cx="146.7" cy="49.4" r=".47"/>
<circle cx="146.7" cy="46.9" r=".47"/>
<circle cx="146.7" cy="44.4" r=".47"/>
<circle cx="146.7" cy="57.1" r=".47"/>
<circle cx="146.7" cy="59.6" r=".47"/>
<circle cx="146.7" cy="52" r=".47"/>
<circle cx="146.7" cy="46.9" r=".64"/>
<circle cx="146.7" cy="59.6" r=".64"/>
<circle cx="146.7" cy="52" r=".64"/>
<circle cx="146.7" cy="49.4" r=".64"/>
<circle cx="146.7" cy="57.1" r=".64"/>
<circle cx="146.7" cy="44.4" r=".64"/>
<circle cx="146.7" cy="54.5" r=".64"/>
<circle cx="162" cy="49.4" r=".47"/>
<circle cx="162" cy="54.5" r=".47"/>
<circle cx="162" cy="44.4" r=".47"/>
<circle cx="162" cy="59.6" r=".47"/>
<circle cx="162" cy="57.1" r=".47"/>
<circle cx="162" cy="46.9" r=".47"/>
<circle cx="162" cy="52" r=".47"/>
<circle cx="162" cy="46.9" r=".64"/>
<circle cx="162" cy="59.6" r=".64"/>
<circle cx="162" cy="52" r=".64"/>
<circle cx="162" cy="44.4" r=".64"/>
<circle cx="162" cy="49.4" r=".64"/>
<circle cx="162" cy="57.1" r=".64"/>
<circle cx="162" cy="54.5" r=".64"/>
<circle cx="172" cy="46" r="1.82"/>
<circle cx="172" cy="46" r="1.65"/>
<circle cx="190.9" cy="42.4" r=".8"/>
<circle cx="194.1" cy="55.8" r="1.14"/>
<circle cx="194.1" cy="59.8" r="1.14"/>
<circle cx="194.1" cy="51.9" r="1.14"/>
<circle cx="194.1" cy="47.9" r="1.14"/>
<circle cx="194.1" cy="43.9" r="1.14"/>
<circle cx="194.1" cy="59.8" r=".97"/>
<circle cx="194.1" cy="55.8" r=".97"/>
<circle cx="194.1" cy="43.9" r=".97"/>
<circle cx="194.1" cy="47.9" r=".97"/>
<circle cx="194.1" cy="51.9" r=".97"/>
<circle cx="71.5" cy="64" r=".72"/>
<circle cx="71.5" cy="76.7" r=".72"/>
<circle cx="71.5" cy="69.1" r=".72"/>
<circle cx="71.5" cy="74.2" r=".72"/>
<circle cx="71.5" cy="61.5" r=".72"/>
<circle cx="71.5" cy="66.5" r=".72"/>
<circle cx="71.5" cy="71.6" r=".72"/>
<circle cx="71.5" cy="66.5" r=".55"/>
<circle cx="71.5" cy="74.2" r=".55"/>
<circle cx="71.5" cy="69.1" r=".55"/>
<circle cx="71.5" cy="64" r=".55"/>
<circle cx="71.5" cy="61.5" r=".55"/>
<circle cx="71.5" cy="71.6" r=".55"/>
<circle cx="71.5" cy="76.7" r=".55"/>
<circle cx="83.2" cy="67.2" r=".47"/>
<circle cx="83.2" cy="74.8" r=".47"/>
<circle cx="83.2" cy="79.9" r=".47"/>
<circle cx="83.2" cy="62.1" r=".47"/>
<circle cx="83.2" cy="72.3" r=".47"/>
<circle cx="83.2" cy="69.8" r=".47"/>
<circle cx="83.2" cy="64.7" r=".47"/>
<circle cx="83.2" cy="77.4" r=".47"/>
<circle cx="83.2" cy="72.3" r=".64"/>
<circle cx="83.2" cy="77.4" r=".64"/>
<circle cx="83.2" cy="64.7" r=".64"/>
<circle cx="83.2" cy="62.1" r=".64"/>
<circle cx="83.2" cy="74.8" r=".64"/>
<circle cx="83.2" cy="69.8" r=".64"/>
<circle cx="83.2" cy="79.9" r=".64"/>
<circle cx="83.2" cy="67.2" r=".64"/>
<circle cx="98.5" cy="79.9" r=".47"/>
<circle cx="98.5" cy="62.1" r=".47"/>
<circle cx="98.5" cy="67.2" r=".47"/>
<circle cx="98.5" cy="74.8" r=".47"/>
<circle cx="98.5" cy="72.3" r=".47"/>
<circle cx="98.5" cy="69.8" r=".47"/>
<circle cx="98.5" cy="64.7" r=".47"/>
<circle cx="98.5" cy="77.4" r=".47"/>
<circle cx="98.5" cy="72.3" r=".64"/>
<circle cx="98.5" cy="77.4" r=".64"/>
<circle cx="98.5" cy="64.7" r=".64"/>
<circle cx="98.5" cy="62.1" r=".64"/>
<circle cx="98.5" cy="69.8" r=".64"/>
<circle cx="98.5" cy="74.8" r=".64"/>
<circle cx="98.5" cy="79.9" r=".64"/>
<circle cx="98.5" cy="67.2" r=".64"/>
<circle cx="104.5" cy="74.8" r=".47"/>
<circle cx="104.5" cy="62.1" r=".47"/>
<circle cx="104.5" cy="79.9" r=".47"/>
<circle cx="104.5" cy="67.2" r=".47"/>
<circle cx="104.5" cy="69.8" r=".47"/>
<circle cx="104.5" cy="72.3" r=".47"/>
<circle cx="104.5" cy="64.7" r=".47"/>
<circle cx="104.5" cy="77.4" r=".47"/>
<circle cx="104.5" cy="72.3" r=".64"/>
<circle cx="104.5" cy="64.7" r=".64"/>
<circle cx="104.5" cy="77.4" r=".64"/>
<circle cx="104.5" cy="74.8" r=".64"/>
<circle cx="104.5" cy="62.1" r=".64"/>
<circle cx="104.5" cy="69.8" r=".64"/>
<circle cx="104.5" cy="79.9" r=".64"/>
<circle cx="104.5" cy="67.2" r=".64"/>
<circle cx="119.7" cy="67.2" r=".47"/>
<circle cx="119.7" cy="74.8" r=".47"/>
<circle cx="119.7" cy="62.1" r=".47"/>
<circle cx="119.7" cy="79.9" r=".47"/>
<circle cx="119.7" cy="69.8" r=".47"/>
<circle cx="119.7" cy="72.3" r=".47"/>
<circle cx="119.7" cy="77.4" r=".47"/>
<circle cx="119.7" cy="64.7" r=".47"/>
<circle cx="119.7" cy="72.3" r=".64"/>
<circle cx="119.7" cy="77.4" r=".64"/>
<circle cx="119.7" cy="64.7" r=".64"/>
<circle cx="119.7" cy="74.8" r=".64"/>
<circle cx="119.7" cy="69.8" r=".64"/>
<circle cx="119.7" cy="62.1" r=".64"/>
<circle cx="119.7" cy="67.2" r=".64"/>
<circle cx="119.7" cy="79.9" r=".64"/>
<circle cx="125.5" cy="62.1" r=".47"/>
<circle cx="125.5" cy="79.9" r=".47"/>
<circle cx="125.5" cy="67.2" r=".47"/>
<circle cx="125.5" cy="74.8" r=".47"/>
<circle cx="125.5" cy="69.8" r=".47"/>
<circle cx="125.5" cy="72.3" r=".47"/>
<circle cx="125.5" cy="64.7" r=".47"/>
<circle cx="125.5" cy="77.4" r=".47"/>
<circle cx="125.5" cy="72.3" r=".64"/>
<circle cx="125.5" cy="77.4" r=".64"/>
<circle cx="125.5" cy="64.7" r=".64"/>
<circle cx="125.5" cy="69.8" r=".64"/>
<circle cx="125.5" cy="74.8" r=".64"/>
<circle cx="125.5" cy="62.1" r=".64"/>
<circle cx="125.5" cy="79.9" r=".64"/>
<circle cx="125.5" cy="67.2" r=".64"/>
<circle cx="140.7" cy="79.9" r=".47"/>
<circle cx="140.7" cy="62.1" r=".47"/>
<circle cx="140.7" cy="74.8" r=".47"/>
<circle cx="140.7" cy="67.2" r=".47"/>
<circle cx="140.7" cy="72.3" r=".47"/>
<circle cx="140.7" cy="69.8" r=".47"/>
<circle cx="140.7" cy="64.7" r=".47"/>
<circle cx="140.7" cy="77.4" r=".47"/>
<circle cx="140.7" cy="72.3" r=".64"/>
<circle cx="140.7" cy="77.4" r=".64"/>
<circle cx="140.7" cy="64.7" r=".64"/>
<circle cx="140.7" cy="69.8" r=".64"/>
<circle cx="140.7" cy="74.8" r=".64"/>
<circle cx="140.7" cy="62.1" r=".64"/>
<circle cx="140.7" cy="67.2" r=".64"/>
<circle cx="140.7" cy="79.9" r=".64"/>
<circle cx="146.7" cy="62.1" r=".47"/>
<circle cx="146.7" cy="67.2" r=".47"/>
<circle cx="146.7" cy="74.8" r=".47"/>
<circle cx="146.7" cy="79.9" r=".47"/>
<circle cx="146.7" cy="72.3" r=".47"/>
<circle cx="146.7" cy="69.8" r=".47"/>
<circle cx="146.7" cy="64.7" r=".47"/>
<circle cx="146.7" cy="77.4" r=".47"/>
<circle cx="146.7" cy="72.3" r=".64"/>
<circle cx="146.7" cy="77.4" r=".64"/>
<circle cx="146.7" cy="64.7" r=".64"/>
<circle cx="146.7" cy="62.1" r=".64"/>
<circle cx="146.7" cy="69.8" r=".64"/>
<circle cx="146.7" cy="74.8" r=".64"/>
<circle cx="146.7" cy="67.2" r=".64"/>
<circle cx="146.7" cy="79.9" r=".64"/>
<circle cx="162" cy="67.2" r=".47"/>
<circle cx="162" cy="74.8" r=".47"/>
<circle cx="162" cy="62.1" r=".47"/>
<circle cx="162" cy="79.9" r=".47"/>
<circle cx="162" cy="72.3" r=".47"/>
<circle cx="162" cy="69.8" r=".47"/>
<circle cx="162" cy="64.7" r=".47"/>
<circle cx="162" cy="77.4" r=".47"/>
<circle cx="162" cy="72.3" r=".64"/>
<circle cx="162" cy="77.4" r=".64"/>
<circle cx="162" cy="64.7" r=".64"/>
<circle cx="162" cy="62.1" r=".64"/>
<circle cx="162" cy="69.8" r=".64"/>
<circle cx="162" cy="74.8" r=".64"/>
<circle cx="162" cy="79.9" r=".64"/>
<circle cx="162" cy="67.2" r=".64"/>
<circle cx="192.5" cy="72.5" r=".72"/>
<circle cx="192.5" cy="77.6" r=".72"/>
<circle cx="192.5" cy="75" r=".72"/>
<circle cx="192.5" cy="75" r=".55"/>
<circle cx="192.5" cy="77.6" r=".55"/>
<circle cx="192.5" cy="72.5" r=".55"/>
<circle cx="194.1" cy="63.8" r="1.14"/>
<circle cx="194.1" cy="63.8" r=".97"/>
<circle cx="195.1" cy="77.6" r=".72"/>
<circle cx="195.1" cy="72.5" r=".72"/>
<circle cx="195.1" cy="75" r=".72"/>
<circle cx="195.1" cy="75" r=".55"/>
<circle cx="195.1" cy="77.6" r=".55"/>
<circle cx="195.1" cy="72.5" r=".55"/>
<circle cx="72" cy="93" r="1.82"/>
<circle cx="72" cy="93" r="1.65"/>
<circle cx="75" cy="84.2" r=".38"/>
<circle cx="75" cy="86.1" r=".38"/>
<circle cx="75" cy="86.1" r=".55"/>
<circle cx="75" cy="84.2" r=".55"/>
<circle cx="83.2" cy="82.5" r=".47"/>
<circle cx="83.2" cy="82.5" r=".64"/>
<circle cx="98.5" cy="82.5" r=".47"/>
<circle cx="98.5" cy="82.5" r=".64"/>
<circle cx="104.5" cy="82.5" r=".47"/>
<circle cx="104.5" cy="82.5" r=".64"/>
<circle cx="119.7" cy="82.5" r=".47"/>
<circle cx="119.7" cy="82.5" r=".64"/>
<circle cx="125.5" cy="82.5" r=".47"/>
<circle cx="125.5" cy="82.5" r=".64"/>
<circle cx="140.7" cy="82.5" r=".47"/>
<circle cx="140.7" cy="82.5" r=".64"/>
<circle cx="146.7" cy="82.5" r=".47"/>
<circle cx="146.7" cy="82.5" r=".64"/>
<circle cx="162" cy="82.5" r=".47"/>
<circle cx="162" cy="82.5" r=".64"/>
<circle cx="192.5" cy="97.9" r=".72"/>
<circle cx="192.5" cy="85.2" r=".72"/>
<circle cx="192.5" cy="90.3" r=".72"/>
<circle cx="192.5" cy="95.3" r=".72"/>
<circle cx="192.5" cy="82.6" r=".72"/>
<circle cx="192.5" cy="92.8" r=".72"/>
<circle cx="192.5" cy="80.1" r=".72"/>
<circle cx="192.5" cy="87.7" r=".72"/>
<circle cx="192.5" cy="87.7" r=".55"/>
<circle cx="192.5" cy="90.3" r=".55"/>
<circle cx="192.5" cy="82.6" r=".55"/>
<circle cx="192.5" cy="80.1" r=".55"/>
<circle cx="192.5" cy="85.2" r=".55"/>
<circle cx="192.5" cy="95.3" r=".55"/>
<circle cx="192.5" cy="97.9" r=".55"/>
<circle cx="192.5" cy="92.8" r=".55"/>
<circle cx="195.1" cy="85.2" r=".72"/>
<circle cx="195.1" cy="90.3" r=".72"/>
<circle cx="195.1" cy="97.9" r=".72"/>
<circle cx="195.1" cy="82.6" r=".72"/>
<circle cx="195.1" cy="95.3" r=".72"/>
<circle cx="195.1" cy="80.1" r=".72"/>
<circle cx="195.1" cy="87.7" r=".72"/>
<circle cx="195.1" cy="92.8" r=".72"/>
<circle cx="195.1" cy="87.7" r=".55"/>
<circle cx="195.1" cy="80.1" r=".55"/>
<circle cx="195.1" cy="85.2" r=".55"/>
<circle cx="195.1" cy="92.8" r=".55"/>
<circle cx="195.1" cy="97.9" r=".55"/>
<circle cx="195.1" cy="82.6" r=".55"/>
<circle cx="195.1" cy="90.3" r=".55"/>
<circle cx="195.1" cy="95.3" r=".55"/>
<circle cx="95" cy="104.2" r=".47"/>
<circle cx="95" cy="109.3" r=".47"/>
<circle cx="95" cy="116.9" r=".47"/>
<circle cx="95" cy="119.5" r=".47"/>
<circle cx="95" cy="114.4" r=".47"/>
<circle cx="95" cy="111.8" r=".47"/>
<circle cx="95" cy="106.8" r=".47"/>
<circle cx="95" cy="114.4" r=".64"/>
<circle cx="95" cy="109.3" r=".64"/>
<circle cx="95" cy="106.8" r=".64"/>
<circle cx="95" cy="119.5" r=".64"/>
<circle cx="95" cy="111.8" r=".64"/>
<circle cx="95" cy="104.2" r=".64"/>
<circle cx="95" cy="116.9" r=".64"/>
<circle cx="110.2" cy="116.9" r=".47"/>
<circle cx="110.2" cy="104.2" r=".47"/>
<circle cx="110.2" cy="109.3" r=".47"/>
<circle cx="110.2" cy="119.5" r=".47"/>
<circle cx="110.2" cy="114.4" r=".47"/>
<circle cx="110.2" cy="111.8" r=".47"/>
<circle cx="110.2" cy="106.8" r=".47"/>
<circle cx="110.2" cy="109.3" r=".64"/>
<circle cx="110.2" cy="114.4" r=".64"/>
<circle cx="110.2" cy="119.5" r=".64"/>
<circle cx="110.2" cy="111.8" r=".64"/>
<circle cx="110.2" cy="106.8" r=".64"/>
<circle cx="110.2" cy="116.9" r=".64"/>
<circle cx="110.2" cy="104.2" r=".64"/>
<circle cx="115.3" cy="109.3" r=".47"/>
<circle cx="115.3" cy="116.9" r=".47"/>
<circle cx="115.3" cy="104.2" r=".47"/>
<circle cx="115.3" cy="119.5" r=".47"/>
<circle cx="115.3" cy="111.8" r=".47"/>
<circle cx="115.3" cy="114.4" r=".47"/>
<circle cx="115.3" cy="106.8" r=".47"/>
<circle cx="115.3" cy="114.4" r=".64"/>
<circle cx="115.3" cy="109.3" r=".64"/>
<circle cx="115.3" cy="111.8" r=".64"/>
<circle cx="115.3" cy="106.8" r=".64"/>
<circle cx="115.3" cy="119.5" r=".64"/>
<circle cx="115.3" cy="116.9" r=".64"/>
<circle cx="115.3" cy="104.2" r=".64"/>
<circle cx="130.6" cy="109.3" r=".47"/>
<circle cx="130.6" cy="104.2" r=".47"/>
<circle cx="130.6" cy="116.9" r=".47"/>
<circle cx="130.6" cy="119.5" r=".47"/>
<circle cx="130.6" cy="111.8" r=".47"/>
<circle cx="130.6" cy="114.4" r=".47"/>
<circle cx="130.6" cy="106.8" r=".47"/>
<circle cx="130.6" cy="114.4" r=".64"/>
<circle cx="130.6" cy="109.3" r=".64"/>
<circle cx="130.6" cy="111.8" r=".64"/>
<circle cx="130.6" cy="119.5" r=".64"/>
<circle cx="130.6" cy="106.8" r=".64"/>
<circle cx="130.6" cy="116.9" r=".64"/>
<circle cx="130.6" cy="104.2" r=".64"/>
<circle cx="192.5" cy="103" r=".72"/>
<circle cx="192.5" cy="110.6" r=".72"/>
<circle cx="192.5" cy="108" r=".72"/>
<circle cx="192.5" cy="100.4" r=".72"/>
<circle cx="192.5" cy="105.5" r=".72"/>
<circle cx="192.5" cy="113.1" r=".72"/>
<circle cx="192.5" cy="113.1" r=".55"/>
<circle cx="192.5" cy="100.4" r=".55"/>
<circle cx="192.5" cy="103" r=".55"/>
<circle cx="192.5" cy="105.5" r=".55"/>
<circle cx="192.5" cy="108" r=".55"/>
<circle cx="192.5" cy="110.6" r=".55"/>
<circle cx="195.1" cy="103" r=".72"/>
<circle cx="195.1" cy="110.6" r=".72"/>
<circle cx="195.1" cy="108" r=".72"/>
<circle cx="195.1" cy="100.4" r=".72"/>
<circle cx="195.1" cy="105.5" r=".72"/>
<circle cx="195.1" cy="113.1" r=".72"/>
<circle cx="195.1" cy="113.1" r=".55"/>
<circle cx="195.1" cy="100.4" r=".55"/>
<circle cx="195.1" cy="108" r=".55"/>
<circle cx="195.1" cy="105.5" r=".55"/>
<circle cx="195.1" cy="110.6" r=".55"/>
<circle cx="195.1" cy="103" r=".55"/>
<circle cx="95" cy="127.1" r=".47"/>
<circle cx="95" cy="139.8" r=".47"/>
<circle cx="95" cy="122" r=".47"/>
<circle cx="95" cy="134.7" r=".47"/>
<circle cx="95" cy="137.2" r=".47"/>
<circle cx="95" cy="124.5" r=".47"/>
<circle cx="95" cy="129.6" r=".47"/>
<circle cx="95" cy="132.2" r=".47"/>
<circle cx="95" cy="132.2" r=".64"/>
<circle cx="95" cy="129.6" r=".64"/>
<circle cx="95" cy="134.7" r=".64"/>
<circle cx="95" cy="122" r=".64"/>
<circle cx="95" cy="124.5" r=".64"/>
<circle cx="95" cy="137.2" r=".64"/>
<circle cx="95" cy="127.1" r=".64"/>
<circle cx="95" cy="139.8" r=".64"/>
<circle cx="110.2" cy="139.8" r=".47"/>
<circle cx="110.2" cy="127.1" r=".47"/>
<circle cx="110.2" cy="124.5" r=".47"/>
<circle cx="110.2" cy="134.7" r=".47"/>
<circle cx="110.2" cy="132.2" r=".47"/>
<circle cx="110.2" cy="129.6" r=".47"/>
<circle cx="110.2" cy="137.2" r=".47"/>
<circle cx="110.2" cy="122" r=".47"/>
<circle cx="110.2" cy="129.6" r=".64"/>
<circle cx="110.2" cy="132.2" r=".64"/>
<circle cx="110.2" cy="134.7" r=".64"/>
<circle cx="110.2" cy="122" r=".64"/>
<circle cx="110.2" cy="137.2" r=".64"/>
<circle cx="110.2" cy="124.5" r=".64"/>
<circle cx="110.2" cy="127.1" r=".64"/>
<circle cx="110.2" cy="139.8" r=".64"/>
<circle cx="115.3" cy="132.2" r=".47"/>
<circle cx="115.3" cy="129.6" r=".47"/>
<circle cx="115.3" cy="122" r=".47"/>
<circle cx="115.3" cy="134.7" r=".47"/>
<circle cx="115.3" cy="139.8" r=".47"/>
<circle cx="115.3" cy="137.2" r=".47"/>
<circle cx="115.3" cy="124.5" r=".47"/>
<circle cx="115.3" cy="127.1" r=".47"/>
<circle cx="115.3" cy="129.6" r=".64"/>
<circle cx="115.3" cy="132.2" r=".64"/>
<circle cx="115.3" cy="122" r=".64"/>
<circle cx="115.3" cy="134.7" r=".64"/>
<circle cx="115.3" cy="124.5" r=".64"/>
<circle cx="115.3" cy="137.2" r=".64"/>
<circle cx="115.3" cy="139.8" r=".64"/>
<circle cx="115.3" cy="127.1" r=".64"/>
<circle cx="130.6" cy="137.2" r=".47"/>
<circle cx="130.6" cy="132.2" r=".47"/>
<circle cx="130.6" cy="124.5" r=".47"/>
<circle cx="130.6" cy="122" r=".47"/>
<circle cx="130.6" cy="134.7" r=".47"/>
<circle cx="130.6" cy="129.6" r=".47"/>
<circle cx="130.6" cy="127.1" r=".47"/>
<circle cx="130.6" cy="139.8" r=".47"/>
<circle cx="130.6" cy="132.2" r=".64"/>
<circle cx="130.6" cy="129.6" r=".64"/>
<circle cx="130.6" cy="122" r=".64"/>
<circle cx="130.6" cy="134.7" r=".64"/>
<circle cx="130.6" cy="124.5" r=".64"/>
<circle cx="130.6" cy="137.2" r=".64"/>
<circle cx="130.6" cy="139.8" r=".64"/>
<circle cx="130.6" cy="127.1" r=".64"/>
<circle cx="84.9" cy="144.9" r="1.82"/>
<circle cx="84.9" cy="144.9" r="1.65"/>
<circle cx="95" cy="142.3" r=".47"/>
<circle cx="95" cy="142.3" r=".64"/>
<circle cx="110.2" cy="142.3" r=".47"/>
<circle cx="110.2" cy="142.3" r=".64"/>
<circle cx="115.3" cy="142.3" r=".47"/>
<circle cx="115.3" cy="142.3" r=".64"/>
<circle cx="130.6" cy="142.3" r=".47"/>
<circle cx="130.6" cy="142.3" r=".64"/>
<circle cx="184.9" cy="144.9" r="1.82"/>
<circle cx="184.9" cy="144.9" r="1.65"/>
</g>
<path d="M92.1 41.2l.3 .2-.1 .1-.4-.1z" fill="#ececec"/>
<path d="M92.1 41.2l.3 .2-.1 .1-.4-.1z" fill="none" stroke="#ececec" stroke-width=".21"/>
<path d="M86.9 44.9l.3 .2-.1 .2-.3-.2z" fill="#ececec"/>
<path d="M86.9 44.9l.3 .2-.1 .2-.3-.2z" fill="none" stroke="#ececec" stroke-width=".21"/>
<path d="M78.4 41.2l.3 .2-.1 .1-.3-.1z" fill="#ececec"/>
<path d="M78.4 41.2l.3 .2-.1 .1-.3-.1z" fill="none" stroke="#ececec" stroke-width=".21"/>
<path d="M77.8 44.5l.3 .2-.1 .1-.3-.1z" fill="#ececec"/>
<path d="M77.8 44.5l.3 .2-.1 .1-.3-.1z" fill="none" stroke="#ececec" stroke-width=".21"/>
<path d="M85.4 46.5l.3 .2-.1 .2-.3-.2z" fill="#ececec"/>
<path d="M85.4 46.5l.3 .2-.1 .2-.3-.2z" fill="none" stroke="#ececec" stroke-width=".21"/>
<path d="M83.4 98.5l.3 .2-.1 .2-.3-.2z" fill="#ececec"/>
<path d="M83.4 98.5l.3 .2-.1 .2-.3-.2z" fill="none" stroke="#ececec" stroke-width=".21"/>
<path d="M89 99.7l.3 .2-.1 .2-.3-.2z" fill="#ececec"/>
<path d="M89 99.7l.3 .2-.1 .2-.3-.2z" fill="none" stroke="#ececec" stroke-width=".21"/>
<path d="M86.8 90.9l.3 .2-.1 .1-.3-.1z" fill="#ececec"/>
<path d="M86.8 90.9l.3 .2-.1 .1-.3-.1z" fill="none" stroke="#ececec" stroke-width=".21"/>
<path d="M75.3 96.7l.3 .2-.1 .2-.3-.2z" fill="#ececec"/>
<path d="M75.3 96.7l.3 .2-.1 .2-.3-.2z" fill="none" stroke="#ececec" stroke-width=".21"/>
<path d="M79.4 97.6l.4 .2-.2 .2-.3-.2z" fill="#ececec"/>
<path d="M79.4 97.6l.4 .2-.2 .2-.3-.2z" fill="none" stroke="#ececec" stroke-width=".21"/>
<path d="M87.1 83.3l.3 .1-.1 .2-.3-.2z" fill="#ececec"/>
<path d="M87.1 83.3l.3 .1-.1 .2-.3-.2z" fill="none" stroke="#ececec" stroke-width=".21"/>
<path d="M79.5 85.7l.3 .2-.1 .2-.3-.2z" fill="#ececec"/>
<path d="M79.5 85.7l.3 .2-.1 .2-.3-.2z" fill="none" stroke="#ececec" stroke-width=".21"/>
<path d="M81.6 88.1l.3 .2-.1 .2-.4-.2z" fill="#ececec"/>
<path d="M81.6 88.1l.3 .2-.1 .2-.4-.2z" fill="none" stroke="#ececec" stroke-width=".21"/>
<path d="M75.2 75.7l.3 .2-.1 .2-.3-.2z" fill="#ececec"/>
<path d="M75.2 75.7l.3 .2-.1 .2-.3-.2z" fill="none" stroke="#ececec" stroke-width=".21"/>
<path d="M73 81.4l.3 .2-.1 .2-.3-.2z" fill="#ececec"/>
<path d="M73 81.4l.3 .2-.1 .2-.3-.2z" fill="none" stroke="#ececec" stroke-width=".21"/>
<path d="M93.8 86.8l.3 .2-.1 .2-.3-.2z" fill="#ececec"/>
<path d="M93.8 86.8l.3 .2-.1 .2-.3-.2z" fill="none" stroke="#ececec" stroke-width=".21"/>
<path d="M84.9 88.3l.3 .2-.1 .2-.3-.2z" fill="#ececec"/>
<path d="M84.9 88.3l.3 .2-.1 .2-.3-.2z" fill="none" stroke="#ececec" stroke-width=".21"/>
<path d="M80.7 69.9l.3 .2-.1 .1-.3-.1z" fill="#ececec"/>
<path d="M80.7 69.9l.3 .2-.1 .1-.3-.1z" fill="none" stroke="#ececec" stroke-width=".21"/>
<path d="M68.2 58.8l.3 .2-.1 .2-.3-.2z" fill="#ececec"/>
<path d="M68.2 58.8l.3 .2-.1 .2-.3-.2z" fill="none" stroke="#ececec" stroke-width=".21"/>
<path d="M68.3 70.9l.3 .2-.1 .2-.3-.2z" fill="#ececec"/>
<path d="M68.3 70.9l.3 .2-.1 .2-.3-.2z" fill="none" stroke="#ececec" stroke-width=".21"/>
<path d="M77.2 57.7l.4 .2-.2 .2-.3-.2z" fill="#ececec"/>
<path d="M77.2 57.7l.4 .2-.2 .2-.3-.2z" fill="none" stroke="#ececec" stroke-width=".21"/>
<path d="M80.8 61.2l.3 .2-.1 .2-.3-.2z" fill="#ececec"/>
<path d="M80.8 61.2l.3 .2-.1 .2-.3-.2z" fill="none" stroke="#ececec" stroke-width=".21"/>
<path d="M85.6 63.6l.3 .2-.1 .2-.3-.2z" fill="#ececec"/>
<path d="M85.6 63.6l.3 .2-.1 .2-.3-.2z" fill="none" stroke="#ececec" stroke-width=".21"/>
<path d="M96 66.9l.3 .2-.1 .2-.4-.2z" fill="#ececec"/>
<path d="M96 66.9l.3 .2-.1 .2-.4-.2z" fill="none" stroke="#ececec" stroke-width=".21"/>
<path d="M90.6 56.4l.3 .2-.1 .2-.3-.2z" fill="#ececec"/>
<path d="M90.6 56.4l.3 .2-.1 .2-.3-.2z" fill="none" stroke="#ececec" stroke-width=".21"/>
<path d="M85.6 55.6l.3 .2-.1 .2-.3-.2z" fill="#ececec"/>
<path d="M85.6 55.6l.3 .2-.1 .2-.3-.2z" fill="none" stroke="#ececec" stroke-width=".21"/>
<path d="M90.5 62l.3 .2-.1 .2-.3-.2z" fill="#ececec"/>
<path d="M90.5 62l.3 .2-.1 .2-.3-.2z" fill="none" stroke="#ececec" stroke-width=".21"/>
<path d="M87.7 66.8l.3 .2-.1 .2-.4-.2z" fill="#ececec"/>
<path d="M87.7 66.8l.3 .2-.1 .2-.4-.2z" fill="none" stroke="#ececec" stroke-width=".21"/>
<path d="M91.3 69.1l.3 .2-.1 .2-.3-.2z" fill="#ececec"/>
<path d="M91.3 69.1l.3 .2-.1 .2-.3-.2z" fill="none" stroke="#ececec" stroke-width=".21"/>
<path d="M67.9 41.6l.3 .2-.1 .2-.3-.2z" fill="#ececec"/>
<path d="M67.9 41.6l.3 .2-.1 .2-.3-.2z" fill="none" stroke="#ececec" stroke-width=".21"/>
<path d="M74.4 51.1l.4 .2-.1 .2-.4-.2z" fill="#ececec"/>
<path d="M74.4 51.1l.4 .2-.1 .2-.4-.2z" fill="none" stroke="#ececec" stroke-width=".21"/>
<path d="M69.4 51.8l.3 .1-.1 .2-.3-.2z" fill="#ececec"/>
<path d="M69.4 51.8l.3 .1-.1 .2-.3-.2z" fill="none" stroke="#ececec" stroke-width=".21"/>
<path d="M76.1 41.8l.4 .2-.2 .2-.3-.2z" fill="#ececec"/>
<path d="M76.1 41.8l.4 .2-.2 .2-.3-.2z" fill="none" stroke="#ececec" stroke-width=".21"/>
<path d="M68.5 48.2l.3 .2-.1 .2-.3-.2z" fill="#ececec"/>
<path d="M68.5 48.2l.3 .2-.1 .2-.3-.2z" fill="none" stroke="#ececec" stroke-width=".21"/>
<path d="M108.2 43.8l.3 .2-.1 .2-.3-.2z" fill="#ececec"/>
<path d="M108.2 43.8l.3 .2-.1 .2-.3-.2z" fill="none" stroke="#ececec" stroke-width=".21"/>
<path d="M94 44.8l.3 .2-.1 .2-.3-.2z" fill="#ececec"/>
<path d="M94 44.8l.3 .2-.1 .2-.3-.2z" fill="none" stroke="#ececec" stroke-width=".21"/>
<path d="M101.4 45.1l.3 .2-.1 .1-.3-.1z" fill="#ececec"/>
<path d="M101.4 45.1l.3 .2-.1 .1-.3-.1z" fill="none" stroke="#ececec" stroke-width=".21"/>
<path d="M95.9 46.4l.3 .2-.1 .2-.3-.2z" fill="#ececec"/>
<path d="M95.9 46.4l.3 .2-.1 .2-.3-.2z" fill="none" stroke="#ececec" stroke-width=".21"/>
<path d="M107.6 47.4l.3 .2-.1 .2-.3-.2z" fill="#ececec"/>
<path d="M107.6 47.4l.3 .2-.1 .2-.3-.2z" fill="none" stroke="#ececec" stroke-width=".21"/>
<path d="M105.8 41.8l.3 .2-.1 .2-.3-.2z" fill="#ececec"/>
<path d="M105.8 41.8l.3 .2-.1 .2-.3-.2z" fill="none" stroke="#ececec" stroke-width=".21"/>
<path d="M122.6 45.1l.3 .2-.1 .1-.3-.1z" fill="#ececec"/>
<path d="M122.6 45.1l.3 .2-.1 .1-.3-.1z" fill="none" stroke="#ececec" stroke-width=".21"/>
<path d="M130 43.6l.3 .2-.1 .2-.3-.2z" fill="#ececec"/>
<path d="M130 43.6l.3 .2-.1 .2-.3-.2z" fill="none" stroke="#ececec" stroke-width=".21"/>
<path d="M127.6 41.7l.3 .2-.1 .2-.3-.2z" fill="#ececec"/>
<path d="M127.6 41.7l.3 .2-.1 .2-.3-.2z" fill="none" stroke="#ececec" stroke-width=".21"/>
<path d="M127.8 46.6l.3 .2-.1 .2-.3-.2z" fill="#ececec"/>
<path d="M127.8 46.6l.3 .2-.1 .2-.3-.2z" fill="none" stroke="#ececec" stroke-width=".21"/>
<path d="M128.1 50.1l.3 .1-.1 .2-.3-.2z" fill="#ececec"/>
<path d="M128.1 50.1l.3 .1-.1 .2-.3-.2z" fill="none" stroke="#ececec" stroke-width=".21"/>
<path d="M128.9 52.6l.3 .2-.1 .2-.3-.2z" fill="#ececec"/>
<path d="M128.9 52.6l.3 .2-.1 .2-.3-.2z" fill="none" stroke="#ececec" stroke-width=".21"/>
<path d="M130 64.5l.3 .2-.1 .2-.3-.2z" fill="#ececec"/>
<path d="M130 64.5l.3 .2-.1 .2-.3-.2z" fill="none" stroke="#ececec" stroke-width=".21"/>
<path d="M122.8 57.9l.3 .1-.1 .2-.3-.2z" fill="#ececec"/>
<path d="M122.8 57.9l.3 .1-.1 .2-.3-.2z" fill="none" stroke="#ececec" stroke-width=".21"/>
<path d="M129 57.1l.3 .2-.1 .2-.3-.2z" fill="#ececec"/>
<path d="M129 57.1l.3 .2-.1 .2-.3-.2z" fill="none" stroke="#ececec" stroke-width=".21"/>
<path d="M127.1 64.5l.3 .2-.1 .2-.3-.2z" fill="#ececec"/>
<path d="M127.1 64.5l.3 .2-.1 .2-.3-.2z" fill="none" stroke="#ececec" stroke-width=".21"/>
<path d="M116.3 44.1l.3 .2-.1 .2-.3-.2z" fill="#ececec"/>
<path d="M116.3 44.1l.3 .2-.1 .2-.3-.2z" fill="none" stroke="#ececec" stroke-width=".21"/>
<path d="M117.5 41.2l.4 .2-.2 .1-.3-.1z" fill="#ececec"/>
<path d="M117.5 41.2l.4 .2-.2 .1-.3-.1z" fill="none" stroke="#ececec" stroke-width=".21"/>
<path d="M115.4 51.1l.3 .2-.1 .2-.3-.2z" fill="#ececec"/>
<path d="M115.4 51.1l.3 .2-.1 .2-.3-.2z" fill="none" stroke="#ececec" stroke-width=".21"/>
<path d="M122.5 50.1l.3 .1-.1 .2-.4-.2z" fill="#ececec"/>
<path d="M122.5 50.1l.3 .1-.1 .2-.4-.2z" fill="none" stroke="#ececec" stroke-width=".21"/>
<path d="M112 49.1l.4 .2-.2 .2-.3-.2z" fill="#ececec"/>
<path d="M112 49.1l.4 .2-.2 .2-.3-.2z" fill="none" stroke="#ececec" stroke-width=".21"/>
<path d="M116.7 47.7l.3 .2-.1 .2-.3-.2z" fill="#ececec"/>
<path d="M116.7 47.7l.3 .2-.1 .2-.3-.2z" fill="none" stroke="#ececec" stroke-width=".21"/>
<path d="M116.9 50.4l.4 .2-.1 .2-.4-.2z" fill="#ececec"/>
<path d="M116.9 50.4l.4 .2-.1 .2-.4-.2z" fill="none" stroke="#ececec" stroke-width=".21"/>
<path d="M113.2 52.9l.3 .2-.1 .2-.3-.2z" fill="#ececec"/>
<path d="M113.2 52.9l.3 .2-.1 .2-.3-.2z" fill="none" stroke="#ececec" stroke-width=".21"/>
<path d="M127.2 75l.3 .2-.1 .2-.3-.2z" fill="#ececec"/>
<path d="M127.2 75l.3 .2-.1 .2-.3-.2z" fill="none" stroke="#ececec" stroke-width=".21"/>
<path d="M112.5 60.9l.4 .2-.1 .2-.4-.2z" fill="#ececec"/>
<path d="M112.5 60.9l.4 .2-.1 .2-.4-.2z" fill="none" stroke="#ececec" stroke-width=".21"/>
<path d="M121.6 64.5l.3 .1-.1 .2-.3-.2z" fill="#ececec"/>
<path d="M121.6 64.5l.3 .1-.1 .2-.3-.2z" fill="none" stroke="#ececec" stroke-width=".21"/>
<path d="M115.3 65.4l.3 .2-.1 .2-.4-.2z" fill="#ececec"/>
<path d="M115.3 65.4l.3 .2-.1 .2-.4-.2z" fill="none" stroke="#ececec" stroke-width=".21"/>
<path d="M117.5 72.4l.3 .2-.1 .2-.4-.2z" fill="#ececec"/>
<path d="M117.5 72.4l.3 .2-.1 .2-.4-.2z" fill="none" stroke="#ececec" stroke-width=".21"/>
<path d="M101.6 83.7l.3 .2-.1 .2-.3-.2z" fill="#ececec"/>
<path d="M101.6 83.7l.3 .2-.1 .2-.3-.2z" fill="none" stroke="#ececec" stroke-width=".21"/>
<path d="M108.7 86.4l.3 .2-.1 .2-.4-.2z" fill="#ececec"/>
<path d="M108.7 86.4l.3 .2-.1 .2-.4-.2z" fill="none" stroke="#ececec" stroke-width=".21"/>
<path d="M114.1 100.9l.3 .1-.1 .2-.3-.2z" fill="#ececec"/>
<path d="M114.1 100.9l.3 .1-.1 .2-.3-.2z" fill="none" stroke="#ececec" stroke-width=".21"/>
<path d="M114.6 92.1l.3 .1-.1 .2-.3-.2z" fill="#ececec"/>
<path d="M114.6 92.1l.3 .1-.1 .2-.3-.2z" fill="none" stroke="#ececec" stroke-width=".21"/>
<path d="M114.7 90.3l.3 .2-.1 .2-.3-.2z" fill="#ececec"/>
<path d="M114.7 90.3l.3 .2-.1 .2-.3-.2z" fill="none" stroke="#ececec" stroke-width=".21"/>
<path d="M104.8 96.5l.3 .2-.1 .2-.4-.2z" fill="#ececec"/>
<path d="M104.8 96.5l.3 .2-.1 .2-.4-.2z" fill="none" stroke="#ececec" stroke-width=".21"/>
<path d="M100.8 96.2l.3 .2-.1 .2-.3-.2z" fill="#ececec"/>
<path d="M100.8 96.2l.3 .2-.1 .2-.3-.2z" fill="none" stroke="#ececec" stroke-width=".21"/>
<path d="M104.5 103.9l.3 .2-.1 .2-.3-.2z" fill="#ececec"/>
<path d="M104.5 103.9l.3 .2-.1 .2-.3-.2z" fill="none" stroke="#ececec" stroke-width=".21"/>
<path d="M97.1 96.2l.3 .2-.1 .2-.4-.2z" fill="#ececec"/>
<path d="M97.1 96.2l.3 .2-.1 .2-.4-.2z" fill="none" stroke="#ececec" stroke-width=".21"/>
<path d="M95.1 101.2l.3 .2-.1 .2-.3-.2z" fill="#ececec"/>
<path d="M95.1 101.2l.3 .2-.1 .2-.3-.2z" fill="none" stroke="#ececec" stroke-width=".21"/>
<path d="M106.5 105.4l.3 .2-.1 .2-.3-.2z" fill="#ececec"/>
<path d="M106.5 105.4l.3 .2-.1 .2-.3-.2z" fill="none" stroke="#ececec" stroke-width=".21"/>
<path d="M104 100.5l.3 .2-.1 .2-.3-.2z" fill="#ececec"/>
<path d="M104 100.5l.3 .2-.1 .2-.3-.2z" fill="none" stroke="#ececec" stroke-width=".21"/>
<path d="M99.7 90l.3 .2-.1 .2-.3-.2z" fill="#ececec"/>
<path d="M99.7 90l.3 .2-.1 .2-.3-.2z" fill="none" stroke="#ececec" stroke-width=".21"/>
<path d="M98.3 86.2l.3 .2-.1 .2-.3-.2z" fill="#ececec"/>
<path d="M98.3 86.2l.3 .2-.1 .2-.3-.2z" fill="none" stroke="#ececec" stroke-width=".21"/>
<path d="M93.2 90l.3 .2-.1 .2-.4-.2z" fill="#ececec"/>
<path d="M93.2 90l.3 .2-.1 .2-.4-.2z" fill="none" stroke="#ececec" stroke-width=".21"/>
<path d="M86 86.6l.3 .1-.1 .2-.3-.2z" fill="#ececec"/>
<path d="M86 86.6l.3 .1-.1 .2-.3-.2z" fill="none" stroke="#ececec" stroke-width=".21"/>
<path d="M85.5 92.9l.3 .2-.1 .2-.4-.2z" fill="#ececec"/>
<path d="M85.5 92.9l.3 .2-.1 .2-.4-.2z" fill="none" stroke="#ececec" stroke-width=".21"/>
<path d="M97.4 106.6l.3 .2-.1 .2-.3-.2z" fill="#ececec"/>
<path d="M97.4 106.6l.3 .2-.1 .2-.3-.2z" fill="none" stroke="#ececec" stroke-width=".21"/>
<path d="M103.5 111.3l.3 .2-.1 .2-.3-.2z" fill="#ececec"/>
<path d="M103.5 111.3l.3 .2-.1 .2-.3-.2z" fill="none" stroke="#ececec" stroke-width=".21"/>
<path d="M103.4 121.5l.3 .2-.1 .2-.3-.2z" fill="#ececec"/>
<path d="M103.4 121.5l.3 .2-.1 .2-.3-.2z" fill="none" stroke="#ececec" stroke-width=".21"/>
<path d="M103.5 107.3l.3 .2-.1 .2-.3-.2z" fill="#ececec"/>
<path d="M103.5 107.3l.3 .2-.1 .2-.3-.2z" fill="none" stroke="#ececec" stroke-width=".21"/>
<path d="M107.6 112.8l.3 .2-.1 .2-.3-.2z" fill="#ececec"/>
<path d="M107.6 112.8l.3 .2-.1 .2-.3-.2z" fill="none" stroke="#ececec" stroke-width=".21"/>
<path d="M105.9 114.2l.4 .1-.2 .2-.3-.2z" fill="#ececec"/>
<path d="M105.9 114.2l.4 .1-.2 .2-.3-.2z" fill="none" stroke="#ececec" stroke-width=".21"/>
<path d="M111.7 109.5l.3 .2-.1 .2-.3-.2z" fill="#ececec"/>
<path d="M111.7 109.5l.3 .2-.1 .2-.3-.2z" fill="none" stroke="#ececec" stroke-width=".21"/>
<path d="M125.7 85.6l.3 .2-.1 .2-.3-.2z" fill="#ececec"/>
<path d="M125.7 85.6l.3 .2-.1 .2-.3-.2z" fill="none" stroke="#ececec" stroke-width=".21"/>
<path d="M125.2 94.4l.4 .2-.1 .2-.4-.2z" fill="#ececec"/>
<path d="M125.2 94.4l.4 .2-.1 .2-.4-.2z" fill="none" stroke="#ececec" stroke-width=".21"/>
<path d="M115.3 93.8l.3 .2-.1 .2-.4-.2z" fill="#ececec"/>
<path d="M115.3 93.8l.3 .2-.1 .2-.4-.2z" fill="none" stroke="#ececec" stroke-width=".21"/>
<path d="M119.9 94.4l.3 .2-.1 .2-.3-.2z" fill="#ececec"/>
<path d="M119.9 94.4l.3 .2-.1 .2-.3-.2z" fill="none" stroke="#ececec" stroke-width=".21"/>
<path d="M116.9 90.3l.3 .2-.1 .2-.3-.2z" fill="#ececec"/>
<path d="M116.9 90.3l.3 .2-.1 .2-.3-.2z" fill="none" stroke="#ececec" stroke-width=".21"/>
<path d="M116.3 91.8l.3 .2-.1 .2-.3-.2z" fill="#ececec"/>
<path d="M116.3 91.8l.3 .2-.1 .2-.3-.2z" fill="none" stroke="#ececec" stroke-width=".21"/>
<path d="M118.4 85.6l.3 .2-.1 .2-.3-.2z" fill="#ececec"/>
<path d="M118.4 85.6l.3 .2-.1 .2-.3-.2z" fill="none" stroke="#ececec" stroke-width=".21"/>
<path d="M122 82.5l.3 .2-.1 .2-.3-.2z" fill="#ececec"/>
<path d="M122 82.5l.3 .2-.1 .2-.3-.2z" fill="none" stroke="#ececec" stroke-width=".21"/>
<path d="M125.4 101.1l.3 .2-.1 .2-.3-.2z" fill="#ececec"/>
<path d="M125.4 101.1l.3 .2-.1 .2-.3-.2z" fill="none" stroke="#ececec" stroke-width=".21"/>
<path d="M127.8 93.9l.3 .2-.1 .2-.3-.2z" fill="#ececec"/>
<path d="M127.8 93.9l.3 .2-.1 .2-.3-.2z" fill="none" stroke="#ececec" stroke-width=".21"/>
<path d="M126.9 92.6l.3 .2-.1 .2-.4-.2z" fill="#ececec"/>
<path d="M126.9 92.6l.3 .2-.1 .2-.4-.2z" fill="none" stroke="#ececec" stroke-width=".21"/>
<path d="M133.6 84.8l.3 .2-.1 .2-.3-.2z" fill="#ececec"/>
<path d="M133.6 84.8l.3 .2-.1 .2-.3-.2z" fill="none" stroke="#ececec" stroke-width=".21"/>
<path d="M134.1 79.8l.3 .2-.1 .2-.4-.2z" fill="#ececec"/>
<path d="M134.1 79.8l.3 .2-.1 .2-.4-.2z" fill="none" stroke="#ececec" stroke-width=".21"/>
<path d="M133.5 74.4l.4 .1-.2 .2-.3-.2z" fill="#ececec"/>
<path d="M133.5 74.4l.4 .1-.2 .2-.3-.2z" fill="none" stroke="#ececec" stroke-width=".21"/>
<path d="M138.5 65l.3 .2-.1 .2-.4-.2z" fill="#ececec"/>
<path d="M138.5 65l.3 .2-.1 .2-.4-.2z" fill="none" stroke="#ececec" stroke-width=".21"/>
<path d="M133.2 64.5l.3 .2-.1 .2-.3-.2z" fill="#ececec"/>
<path d="M133.2 64.5l.3 .2-.1 .2-.3-.2z" fill="none" stroke="#ececec" stroke-width=".21"/>
<path d="M133.7 82.2l.3 .1-.1 .2-.3-.2z" fill="#ececec"/>
<path d="M133.7 82.2l.3 .1-.1 .2-.3-.2z" fill="none" stroke="#ececec" stroke-width=".21"/>
<path d="M121.9 71.5l.3 .2-.1 .2-.3-.2z" fill="#ececec"/>
<path d="M121.9 71.5l.3 .2-.1 .2-.3-.2z" fill="none" stroke="#ececec" stroke-width=".21"/>
<path d="M128.9 75l.3 .2-.1 .2-.3-.2z" fill="#ececec"/>
<path d="M128.9 75l.3 .2-.1 .2-.3-.2z" fill="none" stroke="#ececec" stroke-width=".21"/>
<path d="M121.2 105.3l.3 .2-.1 .2-.3-.2z" fill="#ececec"/>
<path d="M121.2 105.3l.3 .2-.1 .2-.3-.2z" fill="none" stroke="#ececec" stroke-width=".21"/>
<path d="M132.6 105.1l.3 .2-.1 .2-.3-.2z" fill="#ececec"/>
<path d="M132.6 105.1l.3 .2-.1 .2-.3-.2z" fill="none" stroke="#ececec" stroke-width=".21"/>
<path d="M127.1 106.4l.3 .2-.1 .2-.3-.2z" fill="#ececec"/>
<path d="M127.1 106.4l.3 .2-.1 .2-.3-.2z" fill="none" stroke="#ececec" stroke-width=".21"/>
<path d="M131.4 99.1l.3 .2-.1 .2-.3-.2z" fill="#ececec"/>
<path d="M131.4 99.1l.3 .2-.1 .2-.3-.2z" fill="none" stroke="#ececec" stroke-width=".21"/>
<path d="M132.4 107.2l.4 .2-.2 .2-.3-.2z" fill="#ececec"/>
<path d="M132.4 107.2l.4 .2-.2 .2-.3-.2z" fill="none" stroke="#ececec" stroke-width=".21"/>
<path d="M137.5 107.3l.3 .2-.1 .2-.3-.2z" fill="#ececec"/>
<path d="M137.5 107.3l.3 .2-.1 .2-.3-.2z" fill="none" stroke="#ececec" stroke-width=".21"/>
<path d="M137 106.4l.3 .2-.1 .1-.3-.1z" fill="#ececec"/>
<path d="M137 106.4l.3 .2-.1 .1-.3-.1z" fill="none" stroke="#ececec" stroke-width=".21"/>
<path d="M135.2 105.5l.4 .2-.2 .2-.3-.2z" fill="#ececec"/>
<path d="M135.2 105.5l.4 .2-.2 .2-.3-.2z" fill="none" stroke="#ececec" stroke-width=".21"/>
<path d="M134.4 104.8l.3 .2-.1 .2-.3-.2z" fill="#ececec"/>
<path d="M134.4 104.8l.3 .2-.1 .2-.3-.2z" fill="none" stroke="#ececec" stroke-width=".21"/>
<path d="M137 112.8l.3 .2-.1 .2-.3-.2z" fill="#ececec"/>
<path d="M137 112.8l.3 .2-.1 .2-.3-.2z" fill="none" stroke="#ececec" stroke-width=".21"/>
<path d="M135.9 106.4l.3 .2-.1 .1-.3-.1z" fill="#ececec"/>
<path d="M135.9 106.4l.3 .2-.1 .1-.3-.1z" fill="none" stroke="#ececec" stroke-width=".21"/>
<path d="M135.7 118.1l.3 .2-.1 .2-.3-.2z" fill="#ececec"/>
<path d="M135.7 118.1l.3 .2-.1 .2-.3-.2z" fill="none" stroke="#ececec" stroke-width=".21"/>
<path d="M133.6 94.2l.3 .2-.1 .1-.3-.1z" fill="#ececec"/>
<path d="M133.6 94.2l.3 .2-.1 .1-.3-.1z" fill="none" stroke="#ececec" stroke-width=".21"/>
<path d="M132.6 100.4l.3 .1-.1 .2-.3-.2z" fill="#ececec"/>
<path d="M132.6 100.4l.3 .1-.1 .2-.3-.2z" fill="none" stroke="#ececec" stroke-width=".21"/>
<path d="M133.4 91.2l.3 .2-.1 .2-.3-.2z" fill="#ececec"/>
<path d="M133.4 91.2l.3 .2-.1 .2-.3-.2z" fill="none" stroke="#ececec" stroke-width=".21"/>
<path d="M134 89.7l.3 .2-.1 .2-.3-.2z" fill="#ececec"/>
<path d="M134 89.7l.3 .2-.1 .2-.3-.2z" fill="none" stroke="#ececec" stroke-width=".21"/>
<path d="M137.4 98.1l.4 .2-.2 .1-.3-.1z" fill="#ececec"/>
<path d="M137.4 98.1l.4 .2-.2 .1-.3-.1z" fill="none" stroke="#ececec" stroke-width=".21"/>
<path d="M100.3 146.2l.3 .2-.1 .2-.3-.2z" fill="#ececec"/>
<path d="M100.3 146.2l.3 .2-.1 .2-.3-.2z" fill="none" stroke="#ececec" stroke-width=".21"/>
<path d="M102.6 147.9l.4 .2-.2 .2-.3-.2z" fill="#ececec"/>
<path d="M102.6 147.9l.4 .2-.2 .2-.3-.2z" fill="none" stroke="#ececec" stroke-width=".21"/>
<path d="M101.9 142.3l.3 .2-.1 .2-.3-.2z" fill="#ececec"/>
<path d="M101.9 142.3l.3 .2-.1 .2-.3-.2z" fill="none" stroke="#ececec" stroke-width=".21"/>
<path d="M97.1 141.5l.4 .2-.2 .2-.3-.2z" fill="#ececec"/>
<path d="M97.1 141.5l.4 .2-.2 .2-.3-.2z" fill="none" stroke="#ececec" stroke-width=".21"/>
<path d="M103.6 145.3l.3 .2-.1 .2-.3-.2z" fill="#ececec"/>
<path d="M103.6 145.3l.3 .2-.1 .2-.3-.2z" fill="none" stroke="#ececec" stroke-width=".21"/>
<path d="M90.4 137.5l.4 .2-.1 .2-.4-.2z" fill="#ececec"/>
<path d="M90.4 137.5l.4 .2-.1 .2-.4-.2z" fill="none" stroke="#ececec" stroke-width=".21"/>
<path d="M91.6 147.9l.3 .1-.1 .2-.3-.2z" fill="#ececec"/>
<path d="M91.6 147.9l.3 .1-.1 .2-.3-.2z" fill="none" stroke="#ececec" stroke-width=".21"/>
<path d="M90.2 142.9l.3 .1-.1 .2-.3-.2z" fill="#ececec"/>
<path d="M90.2 142.9l.3 .1-.1 .2-.3-.2z" fill="none" stroke="#ececec" stroke-width=".21"/>
<path d="M82.2 138.3l.3 .2-.1 .2-.3-.2z" fill="#ececec"/>
<path d="M82.2 138.3l.3 .2-.1 .2-.3-.2z" fill="none" stroke="#ececec" stroke-width=".21"/>
<path d="M112.1 142.3l.3 .2-.1 .2-.3-.2z" fill="#ececec"/>
<path d="M112.1 142.3l.3 .2-.1 .2-.3-.2z" fill="none" stroke="#ececec" stroke-width=".21"/>
<path d="M117.5 142.4l.3 .2-.1 .2-.4-.2z" fill="#ececec"/>
<path d="M117.5 142.4l.3 .2-.1 .2-.4-.2z" fill="none" stroke="#ececec" stroke-width=".21"/>
<path d="M120.5 136.8l.3 .2-.1 .2-.3-.2z" fill="#ececec"/>
<path d="M120.5 136.8l.3 .2-.1 .2-.3-.2z" fill="none" stroke="#ececec" stroke-width=".21"/>
<path d="M118 134.5l.3 .2-.1 .2-.3-.2z" fill="#ececec"/>
<path d="M118 134.5l.3 .2-.1 .2-.3-.2z" fill="none" stroke="#ececec" stroke-width=".21"/>
<path d="M123 138.5l.4 .1-.2 .2-.3-.2z" fill="#ececec"/>
<path d="M123 138.5l.4 .1-.2 .2-.3-.2z" fill="none" stroke="#ececec" stroke-width=".21"/>
<path d="M112.1 145.5l.3 .2-.1 .2-.3-.2z" fill="#ececec"/>
<path d="M112.1 145.5l.3 .2-.1 .2-.3-.2z" fill="none" stroke="#ececec" stroke-width=".21"/>
<path d="M125.3 137.2l.3 .2-.1 .2-.3-.2z" fill="#ececec"/>
<path d="M125.3 137.2l.3 .2-.1 .2-.3-.2z" fill="none" stroke="#ececec" stroke-width=".21"/>
<path d="M137.1 144l.3 .1-.1 .2-.3-.2z" fill="#ececec"/>
<path d="M137.1 144l.3 .1-.1 .2-.3-.2z" fill="none" stroke="#ececec" stroke-width=".21"/>
<path d="M128.7 134.6l.3 .1-.1 .2-.3-.2z" fill="#ececec"/>
<path d="M128.7 134.6l.3 .1-.1 .2-.3-.2z" fill="none" stroke="#ececec" stroke-width=".21"/>
<path d="M129.6 144.4l.4 .2-.1 .2-.4-.2z" fill="#ececec"/>
<path d="M129.6 144.4l.4 .2-.1 .2-.4-.2z" fill="none" stroke="#ececec" stroke-width=".21"/>
<path d="M133.2 144.2l.3 .2-.1 .2-.3-.2z" fill="#ececec"/>
<path d="M133.2 144.2l.3 .2-.1 .2-.3-.2z" fill="none" stroke="#ececec" stroke-width=".21"/>
<path d="M136.3 140.7l.3 .2-.1 .2-.4-.2z" fill="#ececec"/>
<path d="M136.3 140.7l.3 .2-.1 .2-.4-.2z" fill="none" stroke="#ececec" stroke-width=".21"/>
<path d="M123.3 130.1l.3 .2-.1 .1-.3-.1z" fill="#ececec"/>
<path d="M123.3 130.1l.3 .2-.1 .1-.3-.1z" fill="none" stroke="#ececec" stroke-width=".21"/>
<path d="M134.7 132.2l.3 .2-.1 .2-.3-.2z" fill="#ececec"/>
<path d="M134.7 132.2l.3 .2-.1 .2-.3-.2z" fill="none" stroke="#ececec" stroke-width=".21"/>
<path d="M133.7 122.1l.3 .2-.1 .2-.3-.2z" fill="#ececec"/>
<path d="M133.7 122.1l.3 .2-.1 .2-.3-.2z" fill="none" stroke="#ececec" stroke-width=".21"/>
<path d="M131.8 121.8l.3 .2-.1 .2-.3-.2z" fill="#ececec"/>
<path d="M131.8 121.8l.3 .2-.1 .2-.3-.2z" fill="none" stroke="#ececec" stroke-width=".21"/>
<path d="M135.3 121.9l.3 .1-.1 .2-.3-.2z" fill="#ececec"/>
<path d="M135.3 121.9l.3 .1-.1 .2-.3-.2z" fill="none" stroke="#ececec" stroke-width=".21"/>
<path d="M123.2 128l.3 .2-.1 .2-.3-.2z" fill="#ececec"/>
<path d="M123.2 128l.3 .2-.1 .2-.3-.2z" fill="none" stroke="#ececec" stroke-width=".21"/>
<path d="M122.9 126.4l.3 .2-.1 .2-.3-.2z" fill="#ececec"/>
<path d="M122.9 126.4l.3 .2-.1 .2-.3-.2z" fill="none" stroke="#ececec" stroke-width=".21"/>
<path d="M103.5 133.7l.3 .2-.1 .2-.3-.2z" fill="#ececec"/>
<path d="M103.5 133.7l.3 .2-.1 .2-.3-.2z" fill="none" stroke="#ececec" stroke-width=".21"/>
<path d="M105.6 140.7l.3 .2-.1 .2-.3-.2z" fill="#ececec"/>
<path d="M105.6 140.7l.3 .2-.1 .2-.3-.2z" fill="none" stroke="#ececec" stroke-width=".21"/>
<path d="M106.5 142.1l.3 .2-.1 .2-.3-.2z" fill="#ececec"/>
<path d="M106.5 142.1l.3 .2-.1 .2-.3-.2z" fill="none" stroke="#ececec" stroke-width=".21"/>
<path d="M102 140.5l.4 .2-.1 .2-.4-.2z" fill="#ececec"/>
<path d="M102 140.5l.4 .2-.1 .2-.4-.2z" fill="none" stroke="#ececec" stroke-width=".21"/>
<path d="M127 84.5l.3 .2-.1 .2-.3-.2z" fill="#ececec"/>
<path d="M127 84.5l.3 .2-.1 .2-.3-.2z" fill="none" stroke="#ececec" stroke-width=".21"/>
<path d="M121.4 96.1l.3 .2-.1 .2-.4-.2z" fill="#ececec"/>
<path d="M121.4 96.1l.3 .2-.1 .2-.4-.2z" fill="none" stroke="#ececec" stroke-width=".21"/>
<path d="M128.9 96.4l.3 .2-.1 .2-.3-.2z" fill="#ececec"/>
<path d="M128.9 96.4l.3 .2-.1 .2-.3-.2z" fill="none" stroke="#ececec" stroke-width=".21"/>
<path d="M129.9 77.9l.3 .2-.1 .2-.3-.2z" fill="#ececec"/>
<path d="M129.9 77.9l.3 .2-.1 .2-.3-.2z" fill="none" stroke="#ececec" stroke-width=".21"/>
<path d="M129.5 84.5l.3 .2-.1 .2-.3-.2z" fill="#ececec"/>
<path d="M129.5 84.5l.3 .2-.1 .2-.3-.2z" fill="none" stroke="#ececec" stroke-width=".21"/>
<path d="M109.8 99.3l.4 .2-.2 .2-.3-.2z" fill="#ececec"/>
<path d="M109.8 99.3l.4 .2-.2 .2-.3-.2z" fill="none" stroke="#ececec" stroke-width=".21"/>
<path d="M98.7 92.4l.3 .2-.1 .2-.3-.2z" fill="#ececec"/>
<path d="M98.7 92.4l.3 .2-.1 .2-.3-.2z" fill="none" stroke="#ececec" stroke-width=".21"/>
<path d="M110.4 93.2l.3 .1-.1 .2-.3-.2z" fill="#ececec"/>
<path d="M110.4 93.2l.3 .1-.1 .2-.3-.2z" fill="none" stroke="#ececec" stroke-width=".21"/>
<path d="M109.6 91.2l.3 .2-.1 .2-.3-.2z" fill="#ececec"/>
<path d="M109.6 91.2l.3 .2-.1 .2-.3-.2z" fill="none" stroke="#ececec" stroke-width=".21"/>
<path d="M115.1 96l.3 .2-.1 .2-.3-.2z" fill="#ececec"/>
<path d="M115.1 96l.3 .2-.1 .2-.3-.2z" fill="none" stroke="#ececec" stroke-width=".21"/>
<path d="M109.2 92.6l.3 .2-.1 .2-.3-.2z" fill="#ececec"/>
<path d="M109.2 92.6l.3 .2-.1 .2-.3-.2z" fill="none" stroke="#ececec" stroke-width=".21"/>
<path d="M111.3 95.3l.3 .2-.1 .1-.3-.1z" fill="#ececec"/>
<path d="M111.3 95.3l.3 .2-.1 .1-.3-.1z" fill="none" stroke="#ececec" stroke-width=".21"/>
<path d="M109.6 94.3l.3 .1-.1 .2-.3-.2z" fill="#ececec"/>
<path d="M109.6 94.3l.3 .1-.1 .2-.3-.2z" fill="none" stroke="#ececec" stroke-width=".21"/>
<path d="M112.1 74.9l.3 .2-.1 .1-.3-.1z" fill="#ececec"/>
<path d="M112.1 74.9l.3 .2-.1 .1-.3-.1z" fill="none" stroke="#ececec" stroke-width=".21"/>
<path d="M113.4 82.8l.3 .2-.1 .2-.3-.2z" fill="#ececec"/>
<path d="M113.4 82.8l.3 .2-.1 .2-.3-.2z" fill="none" stroke="#ececec" stroke-width=".21"/>
<path d="M107.5 87.7l.3 .1-.1 .2-.3-.2z" fill="#ececec"/>
<path d="M107.5 87.7l.3 .1-.1 .2-.3-.2z" fill="none" stroke="#ececec" stroke-width=".21"/>
<path d="M110.7 90.1l.3 .2-.1 .2-.3-.2z" fill="#ececec"/>
<path d="M110.7 90.1l.3 .2-.1 .2-.3-.2z" fill="none" stroke="#ececec" stroke-width=".21"/>
<path d="M111.8 88.5l.3 .2-.1 .2-.3-.2z" fill="#ececec"/>
<path d="M111.8 88.5l.3 .2-.1 .2-.3-.2z" fill="none" stroke="#ececec" stroke-width=".21"/>
<path d="M96.3 72l.3 .2-.1 .2-.3-.2z" fill="#ececec"/>
<path d="M96.3 72l.3 .2-.1 .2-.3-.2z" fill="none" stroke="#ececec" stroke-width=".21"/>
<path d="M112.4 67l.3 .2-.1 .2-.3-.2z" fill="#ececec"/>
<path d="M112.4 67l.3 .2-.1 .2-.3-.2z" fill="none" stroke="#ececec" stroke-width=".21"/>
<path d="M112.8 71.4l.3 .2-.1 .2-.3-.2z" fill="#ececec"/>
<path d="M112.8 71.4l.3 .2-.1 .2-.3-.2z" fill="none" stroke="#ececec" stroke-width=".21"/>
<path d="M106.3 72.4l.3 .2-.1 .2-.3-.2z" fill="#ececec"/>
<path d="M106.3 72.4l.3 .2-.1 .2-.3-.2z" fill="none" stroke="#ececec" stroke-width=".21"/>
<path d="M196.2 91.5l.3 .2-.1 .1-.3-.1z" fill="#ececec"/>
<path d="M196.2 91.5l.3 .2-.1 .1-.3-.1z" fill="none" stroke="#ececec" stroke-width=".21"/>
<path d="M190.5 91.6l.3 .2-.1 .2-.3-.2z" fill="#ececec"/>
<path d="M190.5 91.6l.3 .2-.1 .2-.3-.2z" fill="none" stroke="#ececec" stroke-width=".21"/>
<path d="M190.2 99.3l.3 .1-.1 .2-.3-.2z" fill="#ececec"/>
<path d="M190.2 99.3l.3 .1-.1 .2-.3-.2z" fill="none" stroke="#ececec" stroke-width=".21"/>
<path d="M187.7 91.8l.3 .2-.1 .2-.3-.2z" fill="#ececec"/>
<path d="M187.7 91.8l.3 .2-.1 .2-.3-.2z" fill="none" stroke="#ececec" stroke-width=".21"/>
<path d="M186.4 88.9l.3 .2-.1 .2-.3-.2z" fill="#ececec"/>
<path d="M186.4 88.9l.3 .2-.1 .2-.3-.2z" fill="none" stroke="#ececec" stroke-width=".21"/>
<path d="M178.3 85.3l.3 .2-.1 .2-.3-.2z" fill="#ececec"/>
<path d="M178.3 85.3l.3 .2-.1 .2-.3-.2z" fill="none" stroke="#ececec" stroke-width=".21"/>
<path d="M179.9 88.9l.3 .2-.1 .2-.4-.2z" fill="#ececec"/>
<path d="M179.9 88.9l.3 .2-.1 .2-.4-.2z" fill="none" stroke="#ececec" stroke-width=".21"/>
<path d="M188.2 86.7l.3 .2-.1 .2-.4-.2z" fill="#ececec"/>
<path d="M188.2 86.7l.3 .2-.1 .2-.4-.2z" fill="none" stroke="#ececec" stroke-width=".21"/>
<path d="M185.9 85.8l.3 .2-.1 .2-.3-.2z" fill="#ececec"/>
<path d="M185.9 85.8l.3 .2-.1 .2-.3-.2z" fill="none" stroke="#ececec" stroke-width=".21"/>
<path d="M174.6 91.6l.3 .2-.1 .2-.3-.2z" fill="#ececec"/>
<path d="M174.6 91.6l.3 .2-.1 .2-.3-.2z" fill="none" stroke="#ececec" stroke-width=".21"/>
<path d="M176.7 87.3l.3 .2-.1 .2-.3-.2z" fill="#ececec"/>
<path d="M176.7 87.3l.3 .2-.1 .2-.3-.2z" fill="none" stroke="#ececec" stroke-width=".21"/>
<path d="M174.3 88.8l.3 .2-.1 .2-.3-.2z" fill="#ececec"/>
<path d="M174.3 88.8l.3 .2-.1 .2-.3-.2z" fill="none" stroke="#ececec" stroke-width=".21"/>
<path d="M178.9 91.1l.3 .2-.1 .2-.3-.2z" fill="#ececec"/>
<path d="M178.9 91.1l.3 .2-.1 .2-.3-.2z" fill="none" stroke="#ececec" stroke-width=".21"/>
<path d="M173.9 97.7l.3 .2-.1 .2-.3-.2z" fill="#ececec"/>
<path d="M173.9 97.7l.3 .2-.1 .2-.3-.2z" fill="none" stroke="#ececec" stroke-width=".21"/>
<path d="M176 97.7l.3 .2-.1 .2-.3-.2z" fill="#ececec"/>
<path d="M176 97.7l.3 .2-.1 .2-.3-.2z" fill="none" stroke="#ececec" stroke-width=".21"/>
<path d="M170.1 95.7l.3 .2-.1 .2-.3-.2z" fill="#ececec"/>
<path d="M170.1 95.7l.3 .2-.1 .2-.3-.2z" fill="none" stroke="#ececec" stroke-width=".21"/>
<path d="M173.8 103.5l.4 .2-.2 .2-.3-.2z" fill="#ececec"/>
<path d="M173.8 103.5l.4 .2-.2 .2-.3-.2z" fill="none" stroke="#ececec" stroke-width=".21"/>
<path d="M174.3 104.9l.3 .2-.1 .2-.3-.2z" fill="#ececec"/>
<path d="M174.3 104.9l.3 .2-.1 .2-.3-.2z" fill="none" stroke="#ececec" stroke-width=".21"/>
<path d="M170 105.6l.3 .2-.1 .2-.3-.2z" fill="#ececec"/>
<path d="M170 105.6l.3 .2-.1 .2-.3-.2z" fill="none" stroke="#ececec" stroke-width=".21"/>
<path d="M170 108l.3 .2-.1 .1-.3-.1z" fill="#ececec"/>
<path d="M170 108l.3 .2-.1 .1-.3-.1z" fill="none" stroke="#ececec" stroke-width=".21"/>
<path d="M177.7 104.8l.3 .1-.1 .2-.4-.2z" fill="#ececec"/>
<path d="M177.7 104.8l.3 .1-.1 .2-.4-.2z" fill="none" stroke="#ececec" stroke-width=".21"/>
<path d="M168.4 107.6l.3 .2-.1 .2-.3-.2z" fill="#ececec"/>
<path d="M168.4 107.6l.3 .2-.1 .2-.3-.2z" fill="none" stroke="#ececec" stroke-width=".21"/>
<path d="M181.2 94.4l.3 .2-.1 .2-.3-.2z" fill="#ececec"/>
<path d="M181.2 94.4l.3 .2-.1 .2-.3-.2z" fill="none" stroke="#ececec" stroke-width=".21"/>
<path d="M187.1 93.2l.4 .2-.2 .2-.3-.2z" fill="#ececec"/>
<path d="M187.1 93.2l.4 .2-.2 .2-.3-.2z" fill="none" stroke="#ececec" stroke-width=".21"/>
<path d="M181.6 92.3l.3 .2-.1 .2-.3-.2z" fill="#ececec"/>
<path d="M181.6 92.3l.3 .2-.1 .2-.3-.2z" fill="none" stroke="#ececec" stroke-width=".21"/>
<path d="M181.4 100.4l.3 .1-.1 .2-.3-.2z" fill="#ececec"/>
<path d="M181.4 100.4l.3 .1-.1 .2-.3-.2z" fill="none" stroke="#ececec" stroke-width=".21"/>
<path d="M187.8 99l.3 .2-.1 .2-.3-.2z" fill="#ececec"/>
<path d="M187.8 99l.3 .2-.1 .2-.3-.2z" fill="none" stroke="#ececec" stroke-width=".21"/>
<path d="M161.4 84.8l.3 .2-.1 .2-.3-.2z" fill="#ececec"/>
<path d="M161.4 84.8l.3 .2-.1 .2-.3-.2z" fill="none" stroke="#ececec" stroke-width=".21"/>
<path d="M148.4 84.8l.4 .2-.2 .2-.3-.2z" fill="#ececec"/>
<path d="M148.4 84.8l.4 .2-.2 .2-.3-.2z" fill="none" stroke="#ececec" stroke-width=".21"/>
<path d="M166.1 85.2l.4 .2-.2 .2-.3-.2z" fill="#ececec"/>
<path d="M166.1 85.2l.4 .2-.2 .2-.3-.2z" fill="none" stroke="#ececec" stroke-width=".21"/>
<path d="M158.4 88.9l.3 .2-.1 .2-.3-.2z" fill="#ececec"/>
<path d="M158.4 88.9l.3 .2-.1 .2-.3-.2z" fill="none" stroke="#ececec" stroke-width=".21"/>
<path d="M155 85.3l.3 .2-.1 .2-.3-.2z" fill="#ececec"/>
<path d="M155 85.3l.3 .2-.1 .2-.3-.2z" fill="none" stroke="#ececec" stroke-width=".21"/>
<path d="M162.7 88.8l.3 .2-.1 .2-.3-.2z" fill="#ececec"/>
<path d="M162.7 88.8l.3 .2-.1 .2-.3-.2z" fill="none" stroke="#ececec" stroke-width=".21"/>
<path d="M162.3 91l.3 .2-.1 .2-.3-.2z" fill="#ececec"/>
<path d="M162.3 91l.3 .2-.1 .2-.3-.2z" fill="none" stroke="#ececec" stroke-width=".21"/>
<path d="M161.2 93.4l.3 .2-.1 .2-.3-.2z" fill="#ececec"/>
<path d="M161.2 93.4l.3 .2-.1 .2-.3-.2z" fill="none" stroke="#ececec" stroke-width=".21"/>
<path d="M158.3 91.7l.3 .2-.1 .2-.3-.2z" fill="#ececec"/>
<path d="M158.3 91.7l.3 .2-.1 .2-.3-.2z" fill="none" stroke="#ececec" stroke-width=".21"/>
<path d="M155 91.8l.4 .2-.1 .2-.4-.2z" fill="#ececec"/>
<path d="M155 91.8l.4 .2-.1 .2-.4-.2z" fill="none" stroke="#ececec" stroke-width=".21"/>
<path d="M151.2 94.9l.3 .2-.1 .2-.4-.2z" fill="#ececec"/>
<path d="M151.2 94.9l.3 .2-.1 .2-.4-.2z" fill="none" stroke="#ececec" stroke-width=".21"/>
<path d="M155.4 95.1l.3 .2-.1 .2-.3-.2z" fill="#ececec"/>
<path d="M155.4 95.1l.3 .2-.1 .2-.3-.2z" fill="none" stroke="#ececec" stroke-width=".21"/>
<path d="M157.9 101.5l.3 .1-.1 .2-.3-.2z" fill="#ececec"/>
<path d="M157.9 101.5l.3 .1-.1 .2-.3-.2z" fill="none" stroke="#ececec" stroke-width=".21"/>
<path d="M156 101.3l.3 .2-.1 .2-.3-.2z" fill="#ececec"/>
<path d="M156 101.3l.3 .2-.1 .2-.3-.2z" fill="none" stroke="#ececec" stroke-width=".21"/>
<path d="M160.2 105.9l.3 .1-.1 .2-.3-.2z" fill="#ececec"/>
<path d="M160.2 105.9l.3 .1-.1 .2-.3-.2z" fill="none" stroke="#ececec" stroke-width=".21"/>
<path d="M160.3 107.1l.3 .2-.1 .2-.3-.2z" fill="#ececec"/>
<path d="M160.3 107.1l.3 .2-.1 .2-.3-.2z" fill="none" stroke="#ececec" stroke-width=".21"/>
<path d="M147.4 103.7l.3 .1-.1 .2-.3-.2z" fill="#ececec"/>
<path d="M147.4 103.7l.3 .1-.1 .2-.3-.2z" fill="none" stroke="#ececec" stroke-width=".21"/>
<path d="M147.4 101.5l.3 .1-.1 .2-.3-.2z" fill="#ececec"/>
<path d="M147.4 101.5l.3 .1-.1 .2-.3-.2z" fill="none" stroke="#ececec" stroke-width=".21"/>
<path d="M146.9 100.5l.3 .2-.1 .2-.3-.2z" fill="#ececec"/>
<path d="M146.9 100.5l.3 .2-.1 .2-.3-.2z" fill="none" stroke="#ececec" stroke-width=".21"/>
<path d="M146.4 102.6l.3 .1-.1 .2-.3-.2z" fill="#ececec"/>
<path d="M146.4 102.6l.3 .1-.1 .2-.3-.2z" fill="none" stroke="#ececec" stroke-width=".21"/>
<path d="M146.2 107.6l.3 .1-.1 .2-.4-.2z" fill="#ececec"/>
<path d="M146.2 107.6l.3 .1-.1 .2-.4-.2z" fill="none" stroke="#ececec" stroke-width=".21"/>
<path d="M147.8 106.1l.3 .2-.1 .2-.3-.2z" fill="#ececec"/>
<path d="M147.8 106.1l.3 .2-.1 .2-.3-.2z" fill="none" stroke="#ececec" stroke-width=".21"/>
<path d="M151.7 97.7l.3 .2-.1 .2-.3-.2z" fill="#ececec"/>
<path d="M151.7 97.7l.3 .2-.1 .2-.3-.2z" fill="none" stroke="#ececec" stroke-width=".21"/>
<path d="M146.5 95.2l.3 .2-.1 .2-.3-.2z" fill="#ececec"/>
<path d="M146.5 95.2l.3 .2-.1 .2-.3-.2z" fill="none" stroke="#ececec" stroke-width=".21"/>
<path d="M145.9 93.7l.3 .2-.1 .2-.3-.2z" fill="#ececec"/>
<path d="M145.9 93.7l.3 .2-.1 .2-.3-.2z" fill="none" stroke="#ececec" stroke-width=".21"/>
<path d="M143.9 96.4l.3 .2-.1 .2-.3-.2z" fill="#ececec"/>
<path d="M143.9 96.4l.3 .2-.1 .2-.3-.2z" fill="none" stroke="#ececec" stroke-width=".21"/>
<path d="M147.7 95l.3 .2-.1 .2-.3-.2z" fill="#ececec"/>
<path d="M147.7 95l.3 .2-.1 .2-.3-.2z" fill="none" stroke="#ececec" stroke-width=".21"/>
<path d="M143.2 99.1l.3 .2-.1 .2-.3-.2z" fill="#ececec"/>
<path d="M143.2 99.1l.3 .2-.1 .2-.3-.2z" fill="none" stroke="#ececec" stroke-width=".21"/>
<path d="M129.7 86.4l.3 .2-.1 .2-.3-.2z" fill="#ececec"/>
<path d="M129.7 86.4l.3 .2-.1 .2-.3-.2z" fill="none" stroke="#ececec" stroke-width=".21"/>
<path d="M144.6 106l.3 .2-.1 .2-.3-.2z" fill="#ececec"/>
<path d="M144.6 106l.3 .2-.1 .2-.3-.2z" fill="none" stroke="#ececec" stroke-width=".21"/>
<path d="M144.6 107.5l.3 .2-.1 .1-.3-.1z" fill="#ececec"/>
<path d="M144.6 107.5l.3 .2-.1 .1-.3-.1z" fill="none" stroke="#ececec" stroke-width=".21"/>
<path d="M145.2 104.3l.3 .2-.1 .2-.3-.2z" fill="#ececec"/>
<path d="M145.2 104.3l.3 .2-.1 .2-.3-.2z" fill="none" stroke="#ececec" stroke-width=".21"/>
<path d="M136.5 103.7l.3 .1-.1 .2-.3-.2z" fill="#ececec"/>
<path d="M136.5 103.7l.3 .1-.1 .2-.3-.2z" fill="none" stroke="#ececec" stroke-width=".21"/>
<path d="M153.2 106.6l.3 .2-.1 .2-.3-.2z" fill="#ececec"/>
<path d="M153.2 106.6l.3 .2-.1 .2-.3-.2z" fill="none" stroke="#ececec" stroke-width=".21"/>
<path d="M156.2 106.6l.3 .2-.1 .2-.4-.2z" fill="#ececec"/>
<path d="M156.2 106.6l.3 .2-.1 .2-.4-.2z" fill="none" stroke="#ececec" stroke-width=".21"/>
<path d="M153 104.9l.3 .2-.1 .2-.3-.2z" fill="#ececec"/>
<path d="M153 104.9l.3 .2-.1 .2-.3-.2z" fill="none" stroke="#ececec" stroke-width=".21"/>
<path d="M151.9 104.9l.3 .2-.1 .2-.3-.2z" fill="#ececec"/>
<path d="M151.9 104.9l.3 .2-.1 .2-.3-.2z" fill="none" stroke="#ececec" stroke-width=".21"/>
<path d="M151.3 107.3l.3 .2-.1 .2-.3-.2z" fill="#ececec"/>
<path d="M151.3 107.3l.3 .2-.1 .2-.3-.2z" fill="none" stroke="#ececec" stroke-width=".21"/>
<path d="M165.5 103.4l.4 .2-.1 .2-.4-.2z" fill="#ececec"/>
<path d="M165.5 103.4l.4 .2-.1 .2-.4-.2z" fill="none" stroke="#ececec" stroke-width=".21"/>
<path d="M164.4 105l.4 .2-.1 .2-.4-.2z" fill="#ececec"/>
<path d="M164.4 105l.4 .2-.1 .2-.4-.2z" fill="none" stroke="#ececec" stroke-width=".21"/>
<path d="M164.2 108.5l.3 .2-.1 .2-.3-.2z" fill="#ececec"/>
<path d="M164.2 108.5l.3 .2-.1 .2-.3-.2z" fill="none" stroke="#ececec" stroke-width=".21"/>
<path d="M167.2 106.6l.3 .2-.1 .2-.4-.2z" fill="#ececec"/>
<path d="M167.2 106.6l.3 .2-.1 .2-.4-.2z" fill="none" stroke="#ececec" stroke-width=".21"/>
<path d="M165 108.1l.3 .2-.1 .2-.4-.2z" fill="#ececec"/>
<path d="M165 108.1l.3 .2-.1 .2-.4-.2z" fill="none" stroke="#ececec" stroke-width=".21"/>
<path d="M185.7 112.8l.3 .2-.1 .2-.3-.2z" fill="#ececec"/>
<path d="M185.7 112.8l.3 .2-.1 .2-.3-.2z" fill="none" stroke="#ececec" stroke-width=".21"/>
<path d="M179.2 108.3l.3 .2-.1 .2-.3-.2z" fill="#ececec"/>
<path d="M179.2 108.3l.3 .2-.1 .2-.3-.2z" fill="none" stroke="#ececec" stroke-width=".21"/>
<path d="M179.3 110.3l.3 .1-.1 .2-.3-.2z" fill="#ececec"/>
<path d="M179.3 110.3l.3 .1-.1 .2-.3-.2z" fill="none" stroke="#ececec" stroke-width=".21"/>
<path d="M183.4 108.7l.3 .2-.1 .2-.3-.2z" fill="#ececec"/>
<path d="M183.4 108.7l.3 .2-.1 .2-.3-.2z" fill="none" stroke="#ececec" stroke-width=".21"/>
<path d="M185.9 115.3l.3 .1-.1 .2-.3-.2z" fill="#ececec"/>
<path d="M185.9 115.3l.3 .1-.1 .2-.3-.2z" fill="none" stroke="#ececec" stroke-width=".21"/>
<path d="M177.3 109.5l.3 .2-.1 .2-.3-.2z" fill="#ececec"/>
<path d="M177.3 109.5l.3 .2-.1 .2-.3-.2z" fill="none" stroke="#ececec" stroke-width=".21"/>
<path d="M181.5 114.1l.3 .2-.1 .1-.3-.1z" fill="#ececec"/>
<path d="M181.5 114.1l.3 .2-.1 .1-.3-.1z" fill="none" stroke="#ececec" stroke-width=".21"/>
<path d="M197.6 104.5l.3 .2-.1 .2-.4-.2z" fill="#ececec"/>
<path d="M197.6 104.5l.3 .2-.1 .2-.4-.2z" fill="none" stroke="#ececec" stroke-width=".21"/>
<path d="M197.5 101.5l.3 .2-.1 .2-.3-.2z" fill="#ececec"/>
<path d="M197.5 101.5l.3 .2-.1 .2-.3-.2z" fill="none" stroke="#ececec" stroke-width=".21"/>
<path d="M190 101.8l.3 .2-.1 .2-.3-.2z" fill="#ececec"/>
<path d="M190 101.8l.3 .2-.1 .2-.3-.2z" fill="none" stroke="#ececec" stroke-width=".21"/>
<path d="M190 103.1l.3 .2-.1 .2-.3-.2z" fill="#ececec"/>
<path d="M190 103.1l.3 .2-.1 .2-.3-.2z" fill="none" stroke="#ececec" stroke-width=".21"/>
<path d="M197.3 115.3l.3 .2-.1 .2-.3-.2z" fill="#ececec"/>
<path d="M197.3 115.3l.3 .2-.1 .2-.3-.2z" fill="none" stroke="#ececec" stroke-width=".21"/>
<path d="M189.1 114.7l.3 .2-.1 .2-.3-.2z" fill="#ececec"/>
<path d="M189.1 114.7l.3 .2-.1 .2-.3-.2z" fill="none" stroke="#ececec" stroke-width=".21"/>
<path d="M189.1 113.1l.3 .1-.1 .2-.3-.2z" fill="#ececec"/>
<path d="M189.1 113.1l.3 .1-.1 .2-.3-.2z" fill="none" stroke="#ececec" stroke-width=".21"/>
<path d="M190.1 110l.3 .2-.1 .2-.3-.2z" fill="#ececec"/>
<path d="M190.1 110l.3 .2-.1 .2-.3-.2z" fill="none" stroke="#ececec" stroke-width=".21"/>
<path d="M188.5 109.7l.3 .2-.1 .1-.3-.1z" fill="#ececec"/>
<path d="M188.5 109.7l.3 .2-.1 .1-.3-.1z" fill="none" stroke="#ececec" stroke-width=".21"/>
<path d="M196.7 110.9l.3 .2-.1 .2-.3-.2z" fill="#ececec"/>
<path d="M196.7 110.9l.3 .2-.1 .2-.3-.2z" fill="none" stroke="#ececec" stroke-width=".21"/>
<path d="M190.4 114.9l.3 .2-.1 .2-.4-.2z" fill="#ececec"/>
<path d="M190.4 114.9l.3 .2-.1 .2-.4-.2z" fill="none" stroke="#ececec" stroke-width=".21"/>
<path d="M187.5 110.9l.3 .1-.1 .2-.3-.2z" fill="#ececec"/>
<path d="M187.5 110.9l.3 .1-.1 .2-.3-.2z" fill="none" stroke="#ececec" stroke-width=".21"/>
<path d="M171.5 112.4l.3 .2-.1 .2-.3-.2z" fill="#ececec"/>
<path d="M171.5 112.4l.3 .2-.1 .2-.3-.2z" fill="none" stroke="#ececec" stroke-width=".21"/>
<path d="M173.8 114.4l.4 .2-.2 .2-.3-.2z" fill="#ececec"/>
<path d="M173.8 114.4l.4 .2-.2 .2-.3-.2z" fill="none" stroke="#ececec" stroke-width=".21"/>
<path d="M174.4 109.6l.3 .2-.1 .2-.4-.2z" fill="#ececec"/>
<path d="M174.4 109.6l.3 .2-.1 .2-.4-.2z" fill="none" stroke="#ececec" stroke-width=".21"/>
<path d="M174 110.5l.3 .2-.1 .2-.3-.2z" fill="#ececec"/>
<path d="M174 110.5l.3 .2-.1 .2-.3-.2z" fill="none" stroke="#ececec" stroke-width=".21"/>
<path d="M190 105l.3 .2-.1 .2-.3-.2z" fill="#ececec"/>
<path d="M190 105l.3 .2-.1 .2-.3-.2z" fill="none" stroke="#ececec" stroke-width=".21"/>
<path d="M188.4 105.9l.3 .2-.1 .2-.3-.2z" fill="#ececec"/>
<path d="M188.4 105.9l.3 .2-.1 .2-.3-.2z" fill="none" stroke="#ececec" stroke-width=".21"/>
<path d="M188.4 107l.3 .1-.1 .2-.3-.2z" fill="#ececec"/>
<path d="M188.4 107l.3 .1-.1 .2-.3-.2z" fill="none" stroke="#ececec" stroke-width=".21"/>
<path d="M188.2 104.8l.4 .2-.2 .2-.3-.2z" fill="#ececec"/>
<path d="M188.2 104.8l.4 .2-.2 .2-.3-.2z" fill="none" stroke="#ececec" stroke-width=".21"/>
<path d="M191.1 107.2l.3 .2-.1 .2-.3-.2z" fill="#ececec"/>
<path d="M191.1 107.2l.3 .2-.1 .2-.3-.2z" fill="none" stroke="#ececec" stroke-width=".21"/>
<path d="M183.4 101.9l.3 .2-.1 .2-.3-.2z" fill="#ececec"/>
<path d="M183.4 101.9l.3 .2-.1 .2-.3-.2z" fill="none" stroke="#ececec" stroke-width=".21"/>
<path d="M195.4 116.9l.3 .2-.1 .1-.4-.1z" fill="#ececec"/>
<path d="M195.4 116.9l.3 .2-.1 .1-.4-.1z" fill="none" stroke="#ececec" stroke-width=".21"/>
<path d="M192.4 116.3l.3 .2-.1 .1-.3-.1z" fill="#ececec"/>
<path d="M192.4 116.3l.3 .2-.1 .1-.3-.1z" fill="none" stroke="#ececec" stroke-width=".21"/>
<path d="M187.6 115.9l.4 .2-.1 .2-.4-.2z" fill="#ececec"/>
<path d="M187.6 115.9l.4 .2-.1 .2-.4-.2z" fill="none" stroke="#ececec" stroke-width=".21"/>
<path d="M187.8 119l.3 .2-.1 .2-.3-.2z" fill="#ececec"/>
<path d="M187.8 119l.3 .2-.1 .2-.3-.2z" fill="none" stroke="#ececec" stroke-width=".21"/>
<path d="M180.7 136.4l.3 .2-.1 .2-.3-.2z" fill="#ececec"/>
<path d="M180.7 136.4l.3 .2-.1 .2-.3-.2z" fill="none" stroke="#ececec" stroke-width=".21"/>
<path d="M176.8 140l.3 .2-.1 .2-.3-.2z" fill="#ececec"/>
<path d="M176.8 140l.3 .2-.1 .2-.3-.2z" fill="none" stroke="#ececec" stroke-width=".21"/>
<path d="M183.1 139.1l.3 .2-.1 .2-.3-.2z" fill="#ececec"/>
<path d="M183.1 139.1l.3 .2-.1 .2-.3-.2z" fill="none" stroke="#ececec" stroke-width=".21"/>
<path d="M183.6 133.7l.3 .2-.1 .2-.3-.2z" fill="#ececec"/>
<path d="M183.6 133.7l.3 .2-.1 .2-.3-.2z" fill="none" stroke="#ececec" stroke-width=".21"/>
<path d="M177.9 134.6l.3 .1-.1 .2-.3-.2z" fill="#ececec"/>
<path d="M177.9 134.6l.3 .1-.1 .2-.3-.2z" fill="none" stroke="#ececec" stroke-width=".21"/>
<path d="M176.6 136.6l.4 .2-.2 .2-.3-.2z" fill="#ececec"/>
<path d="M176.6 136.6l.4 .2-.2 .2-.3-.2z" fill="none" stroke="#ececec" stroke-width=".21"/>
<path d="M179.8 130.7l.3 .2-.1 .1-.3-.1z" fill="#ececec"/>
<path d="M179.8 130.7l.3 .2-.1 .1-.3-.1z" fill="none" stroke="#ececec" stroke-width=".21"/>
<path d="M183.9 131.1l.3 .2-.1 .2-.3-.2z" fill="#ececec"/>
<path d="M183.9 131.1l.3 .2-.1 .2-.3-.2z" fill="none" stroke="#ececec" stroke-width=".21"/>
<path d="M181.9 130.1l.3 .2-.1 .1-.3-.1z" fill="#ececec"/>
<path d="M181.9 130.1l.3 .2-.1 .1-.3-.1z" fill="none" stroke="#ececec" stroke-width=".21"/>
<path d="M182.6 133.8l.3 .2-.1 .2-.3-.2z" fill="#ececec"/>
<path d="M182.6 133.8l.3 .2-.1 .2-.3-.2z" fill="none" stroke="#ececec" stroke-width=".21"/>
<path d="M184 132.6l.3 .2-.1 .2-.3-.2z" fill="#ececec"/>
<path d="M184 132.6l.3 .2-.1 .2-.3-.2z" fill="none" stroke="#ececec" stroke-width=".21"/>
<path d="M188 132.2l.3 .2-.1 .2-.3-.2z" fill="#ececec"/>
<path d="M188 132.2l.3 .2-.1 .2-.3-.2z" fill="none" stroke="#ececec" stroke-width=".21"/>
<path d="M189 130.4l.3 .2-.1 .2-.3-.2z" fill="#ececec"/>
<path d="M189 130.4l.3 .2-.1 .2-.3-.2z" fill="none" stroke="#ececec" stroke-width=".21"/>
<path d="M187.3 129.5l.3 .2-.1 .2-.3-.2z" fill="#ececec"/>
<path d="M187.3 129.5l.3 .2-.1 .2-.3-.2z" fill="none" stroke="#ececec" stroke-width=".21"/>
<path d="M187.7 134.1l.3 .1-.1 .2-.3-.2z" fill="#ececec"/>
<path d="M187.7 134.1l.3 .1-.1 .2-.3-.2z" fill="none" stroke="#ececec" stroke-width=".21"/>
<path d="M181.8 125.4l.3 .2-.1 .2-.3-.2z" fill="#ececec"/>
<path d="M181.8 125.4l.3 .2-.1 .2-.3-.2z" fill="none" stroke="#ececec" stroke-width=".21"/>
<path d="M187.8 124.7l.3 .2-.1 .2-.3-.2z" fill="#ececec"/>
<path d="M187.8 124.7l.3 .2-.1 .2-.3-.2z" fill="none" stroke="#ececec" stroke-width=".21"/>
<path d="M183.8 120.4l.3 .2-.1 .2-.4-.2z" fill="#ececec"/>
<path d="M183.8 120.4l.3 .2-.1 .2-.4-.2z" fill="none" stroke="#ececec" stroke-width=".21"/>
<path d="M182.9 120l.3 .2-.1 .2-.3-.2z" fill="#ececec"/>
<path d="M182.9 120l.3 .2-.1 .2-.3-.2z" fill="none" stroke="#ececec" stroke-width=".21"/>
<path d="M183.2 118l.3 .2-.1 .1-.4-.1z" fill="#ececec"/>
<path d="M183.2 118l.3 .2-.1 .1-.4-.1z" fill="none" stroke="#ececec" stroke-width=".21"/>
<path d="M188 126.9l.3 .2-.1 .2-.3-.2z" fill="#ececec"/>
<path d="M188 126.9l.3 .2-.1 .2-.3-.2z" fill="none" stroke="#ececec" stroke-width=".21"/>
<path d="M197.1 46.8l.3 .1-.1 .2-.3-.2z" fill="#ececec"/>
<path d="M197.1 46.8l.3 .1-.1 .2-.3-.2z" fill="none" stroke="#ececec" stroke-width=".21"/>
<path d="M189.6 47.3l.3 .2-.1 .1-.3-.1z" fill="#ececec"/>
<path d="M189.6 47.3l.3 .2-.1 .1-.3-.1z" fill="none" stroke="#ececec" stroke-width=".21"/>
<path d="M189.6 49.3l.3 .2-.1 .2-.3-.2z" fill="#ececec"/>
<path d="M189.6 49.3l.3 .2-.1 .2-.3-.2z" fill="none" stroke="#ececec" stroke-width=".21"/>
<path d="M188.7 41.8l.4 .2-.1 .2-.4-.2z" fill="#ececec"/>
<path d="M188.7 41.8l.4 .2-.1 .2-.4-.2z" fill="none" stroke="#ececec" stroke-width=".21"/>
<path d="M187.3 45.4l.3 .2-.1 .2-.3-.2z" fill="#ececec"/>
<path d="M187.3 45.4l.3 .2-.1 .2-.3-.2z" fill="none" stroke="#ececec" stroke-width=".21"/>
<path d="M169.4 53.2l.4 .2-.2 .2-.3-.2z" fill="#ececec"/>
<path d="M169.4 53.2l.4 .2-.2 .2-.3-.2z" fill="none" stroke="#ececec" stroke-width=".21"/>
<path d="M165.2 51.3l.3 .2-.1 .2-.3-.2z" fill="#ececec"/>
<path d="M165.2 51.3l.3 .2-.1 .2-.3-.2z" fill="none" stroke="#ececec" stroke-width=".21"/>
<path d="M164.9 45.6l.3 .2-.1 .2-.3-.2z" fill="#ececec"/>
<path d="M164.9 45.6l.3 .2-.1 .2-.3-.2z" fill="none" stroke="#ececec" stroke-width=".21"/>
<path d="M167.7 48.8l.4 .2-.1 .2-.4-.2z" fill="#ececec"/>
<path d="M167.7 48.8l.4 .2-.1 .2-.4-.2z" fill="none" stroke="#ececec" stroke-width=".21"/>
<path d="M172.8 51.1l.3 .2-.1 .2-.3-.2z" fill="#ececec"/>
<path d="M172.8 51.1l.3 .2-.1 .2-.3-.2z" fill="none" stroke="#ececec" stroke-width=".21"/>
<path d="M174.4 63.9l.3 .2-.1 .2-.4-.2z" fill="#ececec"/>
<path d="M174.4 63.9l.3 .2-.1 .2-.4-.2z" fill="none" stroke="#ececec" stroke-width=".21"/>
<path d="M174.4 62.8l.4 .2-.2 .2-.3-.2z" fill="#ececec"/>
<path d="M174.4 62.8l.4 .2-.2 .2-.3-.2z" fill="none" stroke="#ececec" stroke-width=".21"/>
<path d="M175.4 64l.3 .2-.1 .2-.3-.2z" fill="#ececec"/>
<path d="M175.4 64l.3 .2-.1 .2-.3-.2z" fill="none" stroke="#ececec" stroke-width=".21"/>
<path d="M175.4 68.2l.3 .2-.1 .2-.3-.2z" fill="#ececec"/>
<path d="M175.4 68.2l.3 .2-.1 .2-.3-.2z" fill="none" stroke="#ececec" stroke-width=".21"/>
<path d="M179.1 44.5l.3 .2-.1 .1-.3-.1z" fill="#ececec"/>
<path d="M179.1 44.5l.3 .2-.1 .1-.3-.1z" fill="none" stroke="#ececec" stroke-width=".21"/>
<path d="M175.5 49.3l.4 .2-.2 .2-.3-.2z" fill="#ececec"/>
<path d="M175.5 49.3l.4 .2-.2 .2-.3-.2z" fill="none" stroke="#ececec" stroke-width=".21"/>
<path d="M178.4 46.7l.3 .2-.1 .2-.3-.2z" fill="#ececec"/>
<path d="M178.4 46.7l.3 .2-.1 .2-.3-.2z" fill="none" stroke="#ececec" stroke-width=".21"/>
<path d="M178.2 42.7l.4 .2-.1 .2-.4-.2z" fill="#ececec"/>
<path d="M178.2 42.7l.4 .2-.1 .2-.4-.2z" fill="none" stroke="#ececec" stroke-width=".21"/>
<path d="M188.8 51.8l.3 .1-.1 .2-.3-.2z" fill="#ececec"/>
<path d="M188.8 51.8l.3 .1-.1 .2-.3-.2z" fill="none" stroke="#ececec" stroke-width=".21"/>
<path d="M182.3 51.6l.3 .2-.1 .2-.3-.2z" fill="#ececec"/>
<path d="M182.3 51.6l.3 .2-.1 .2-.3-.2z" fill="none" stroke="#ececec" stroke-width=".21"/>
<path d="M182 59.3l.3 .2-.1 .2-.3-.2z" fill="#ececec"/>
<path d="M182 59.3l.3 .2-.1 .2-.3-.2z" fill="none" stroke="#ececec" stroke-width=".21"/>
<path d="M188.3 59.3l.3 .2-.1 .2-.3-.2z" fill="#ececec"/>
<path d="M188.3 59.3l.3 .2-.1 .2-.3-.2z" fill="none" stroke="#ececec" stroke-width=".21"/>
<path d="M182.1 56.3l.3 .2-.1 .2-.4-.2z" fill="#ececec"/>
<path d="M182.1 56.3l.3 .2-.1 .2-.4-.2z" fill="none" stroke="#ececec" stroke-width=".21"/>
<path d="M186.1 54.8l.3 .2-.1 .2-.3-.2z" fill="#ececec"/>
<path d="M186.1 54.8l.3 .2-.1 .2-.3-.2z" fill="none" stroke="#ececec" stroke-width=".21"/>
<path d="M167.2 65.5l.4 .2-.2 .1-.3-.1z" fill="#ececec"/>
<path d="M167.2 65.5l.4 .2-.2 .1-.3-.1z" fill="none" stroke="#ececec" stroke-width=".21"/>
<path d="M165.7 61l.3 .2-.1 .2-.3-.2z" fill="#ececec"/>
<path d="M165.7 61l.3 .2-.1 .2-.3-.2z" fill="none" stroke="#ececec" stroke-width=".21"/>
<path d="M171.1 68.2l.3 .2-.1 .2-.3-.2z" fill="#ececec"/>
<path d="M171.1 68.2l.3 .2-.1 .2-.3-.2z" fill="none" stroke="#ececec" stroke-width=".21"/>
<path d="M167.2 66.4l.4 .2-.2 .2-.3-.2z" fill="#ececec"/>
<path d="M167.2 66.4l.4 .2-.2 .2-.3-.2z" fill="none" stroke="#ececec" stroke-width=".21"/>
<path d="M166.1 62.5l.3 .2-.1 .2-.4-.2z" fill="#ececec"/>
<path d="M166.1 62.5l.3 .2-.1 .2-.4-.2z" fill="none" stroke="#ececec" stroke-width=".21"/>
<path d="M168.9 65.8l.3 .2-.1 .2-.4-.2z" fill="#ececec"/>
<path d="M168.9 65.8l.3 .2-.1 .2-.4-.2z" fill="none" stroke="#ececec" stroke-width=".21"/>
<path d="M188.2 60.8l.4 .2-.2 .2-.3-.2z" fill="#ececec"/>
<path d="M188.2 60.8l.4 .2-.2 .2-.3-.2z" fill="none" stroke="#ececec" stroke-width=".21"/>
<path d="M181.8 64.2l.3 .2-.1 .2-.3-.2z" fill="#ececec"/>
<path d="M181.8 64.2l.3 .2-.1 .2-.3-.2z" fill="none" stroke="#ececec" stroke-width=".21"/>
<path d="M183.8 66.2l.3 .2-.1 .2-.4-.2z" fill="#ececec"/>
<path d="M183.8 66.2l.3 .2-.1 .2-.4-.2z" fill="none" stroke="#ececec" stroke-width=".21"/>
<path d="M183.3 61.5l.3 .2-.1 .2-.3-.2z" fill="#ececec"/>
<path d="M183.3 61.5l.3 .2-.1 .2-.3-.2z" fill="none" stroke="#ececec" stroke-width=".21"/>
<path d="M185.9 66.5l.3 .2-.1 .2-.3-.2z" fill="#ececec"/>
<path d="M185.9 66.5l.3 .2-.1 .2-.3-.2z" fill="none" stroke="#ececec" stroke-width=".21"/>
<path d="M187.8 65.8l.3 .2-.1 .2-.3-.2z" fill="#ececec"/>
<path d="M187.8 65.8l.3 .2-.1 .2-.3-.2z" fill="none" stroke="#ececec" stroke-width=".21"/>
<path d="M171.1 62.2l.3 .2-.1 .1-.4-.1z" fill="#ececec"/>
<path d="M171.1 62.2l.3 .2-.1 .1-.4-.1z" fill="none" stroke="#ececec" stroke-width=".21"/>
<path d="M177.8 60.6l.3 .1-.1 .2-.3-.2z" fill="#ececec"/>
<path d="M177.8 60.6l.3 .1-.1 .2-.3-.2z" fill="none" stroke="#ececec" stroke-width=".21"/>
<path d="M174.9 59.4l.3 .2-.1 .2-.3-.2z" fill="#ececec"/>
<path d="M174.9 59.4l.3 .2-.1 .2-.3-.2z" fill="none" stroke="#ececec" stroke-width=".21"/>
<path d="M178 58.9l.3 .2-.1 .1-.3-.1z" fill="#ececec"/>
<path d="M178 58.9l.3 .2-.1 .1-.3-.1z" fill="none" stroke="#ececec" stroke-width=".21"/>
<path d="M171.3 58.6l.3 .2-.1 .2-.3-.2z" fill="#ececec"/>
<path d="M171.3 58.6l.3 .2-.1 .2-.3-.2z" fill="none" stroke="#ececec" stroke-width=".21"/>
<path d="M171.9 83.2l.3 .2-.1 .1-.3-.1z" fill="#ececec"/>
<path d="M171.9 83.2l.3 .2-.1 .1-.3-.1z" fill="none" stroke="#ececec" stroke-width=".21"/>
<path d="M172 87.4l.3 .2-.1 .2-.3-.2z" fill="#ececec"/>
<path d="M172 87.4l.3 .2-.1 .2-.3-.2z" fill="none" stroke="#ececec" stroke-width=".21"/>
<path d="M170 85.5l.3 .2-.1 .2-.3-.2z" fill="#ececec"/>
<path d="M170 85.5l.3 .2-.1 .2-.3-.2z" fill="none" stroke="#ececec" stroke-width=".21"/>
<path d="M166.1 87.3l.4 .2-.2 .2-.3-.2z" fill="#ececec"/>
<path d="M166.1 87.3l.4 .2-.2 .2-.3-.2z" fill="none" stroke="#ececec" stroke-width=".21"/>
<path d="M174.4 84.4l.4 .2-.2 .2-.3-.2z" fill="#ececec"/>
<path d="M174.4 84.4l.4 .2-.2 .2-.3-.2z" fill="none" stroke="#ececec" stroke-width=".21"/>
<path d="M177.8 83.4l.3 .2-.1 .2-.3-.2z" fill="#ececec"/>
<path d="M177.8 83.4l.3 .2-.1 .2-.3-.2z" fill="none" stroke="#ececec" stroke-width=".21"/>
<path d="M170.5 94.4l.4 .2-.2 .2-.3-.2z" fill="#ececec"/>
<path d="M170.5 94.4l.4 .2-.2 .2-.3-.2z" fill="none" stroke="#ececec" stroke-width=".21"/>
<path d="M170.2 100.7l.3 .2-.1 .2-.3-.2z" fill="#ececec"/>
<path d="M170.2 100.7l.3 .2-.1 .2-.3-.2z" fill="none" stroke="#ececec" stroke-width=".21"/>
<path d="M177.7 99.5l.3 .2-.1 .2-.4-.2z" fill="#ececec"/>
<path d="M177.7 99.5l.3 .2-.1 .2-.4-.2z" fill="none" stroke="#ececec" stroke-width=".21"/>
<path d="M170.5 92.6l.3 .2-.1 .2-.4-.2z" fill="#ececec"/>
<path d="M170.5 92.6l.3 .2-.1 .2-.4-.2z" fill="none" stroke="#ececec" stroke-width=".21"/>
<path d="M170 102.7l.3 .2-.1 .2-.4-.2z" fill="#ececec"/>
<path d="M170 102.7l.3 .2-.1 .2-.4-.2z" fill="none" stroke="#ececec" stroke-width=".21"/>
<path d="M164.3 100.3l.3 .2-.1 .1-.3-.1z" fill="#ececec"/>
<path d="M164.3 100.3l.3 .2-.1 .1-.3-.1z" fill="none" stroke="#ececec" stroke-width=".21"/>
<path d="M165.8 98.8l.3 .2-.1 .2-.3-.2z" fill="#ececec"/>
<path d="M165.8 98.8l.3 .2-.1 .2-.3-.2z" fill="none" stroke="#ececec" stroke-width=".21"/>
<path d="M164.3 99.3l.3 .1-.1 .2-.3-.2z" fill="#ececec"/>
<path d="M164.3 99.3l.3 .1-.1 .2-.3-.2z" fill="none" stroke="#ececec" stroke-width=".21"/>
<path d="M161.1 99.2l.4 .2-.2 .1-.3-.1z" fill="#ececec"/>
<path d="M161.1 99.2l.4 .2-.2 .1-.3-.1z" fill="none" stroke="#ececec" stroke-width=".21"/>
<path d="M164.4 97.1l.3 .2-.1 .2-.3-.2z" fill="#ececec"/>
<path d="M164.4 97.1l.3 .2-.1 .2-.3-.2z" fill="none" stroke="#ececec" stroke-width=".21"/>
<path d="M161 97l.3 .2-.1 .1-.3-.1z" fill="#ececec"/>
<path d="M161 97l.3 .2-.1 .1-.3-.1z" fill="none" stroke="#ececec" stroke-width=".21"/>
<path d="M160.2 98.3l.3 .2-.1 .2-.3-.2z" fill="#ececec"/>
<path d="M160.2 98.3l.3 .2-.1 .2-.3-.2z" fill="none" stroke="#ececec" stroke-width=".21"/>
<path d="M160.6 102.8l.3 .2-.1 .2-.4-.2z" fill="#ececec"/>
<path d="M160.6 102.8l.3 .2-.1 .2-.4-.2z" fill="none" stroke="#ececec" stroke-width=".21"/>
<path d="M166 97l.3 .2-.1 .1-.3-.1z" fill="#ececec"/>
<path d="M166 97l.3 .2-.1 .1-.3-.1z" fill="none" stroke="#ececec" stroke-width=".21"/>
<path d="M165.4 90.7l.3 .2-.1 .2-.3-.2z" fill="#ececec"/>
<path d="M165.4 90.7l.3 .2-.1 .2-.3-.2z" fill="none" stroke="#ececec" stroke-width=".21"/>
<path d="M166.8 89.5l.3 .2-.1 .2-.3-.2z" fill="#ececec"/>
<path d="M166.8 89.5l.3 .2-.1 .2-.3-.2z" fill="none" stroke="#ececec" stroke-width=".21"/>
<path d="M166.5 94.5l.3 .2-.1 .2-.3-.2z" fill="#ececec"/>
<path d="M166.5 94.5l.3 .2-.1 .2-.3-.2z" fill="none" stroke="#ececec" stroke-width=".21"/>
<path d="M165.5 93.2l.3 .2-.1 .2-.3-.2z" fill="#ececec"/>
<path d="M165.5 93.2l.3 .2-.1 .2-.3-.2z" fill="none" stroke="#ececec" stroke-width=".21"/>
<path d="M164.3 94.3l.3 .1-.1 .2-.3-.2z" fill="#ececec"/>
<path d="M164.3 94.3l.3 .1-.1 .2-.3-.2z" fill="none" stroke="#ececec" stroke-width=".21"/>
<path d="M166.8 91.6l.3 .2-.1 .2-.3-.2z" fill="#ececec"/>
<path d="M166.8 91.6l.3 .2-.1 .2-.3-.2z" fill="none" stroke="#ececec" stroke-width=".21"/>
<path d="M177.3 93.1l.3 .2-.1 .1-.3-.1z" fill="#ececec"/>
<path d="M177.3 93.1l.3 .2-.1 .1-.3-.1z" fill="none" stroke="#ececec" stroke-width=".21"/>
<path d="M174.4 94.4l.3 .2-.1 .2-.4-.2z" fill="#ececec"/>
<path d="M174.4 94.4l.3 .2-.1 .2-.4-.2z" fill="none" stroke="#ececec" stroke-width=".21"/>
<path d="M173.8 96l.3 .1-.1 .2-.3-.2z" fill="#ececec"/>
<path d="M173.8 96l.3 .1-.1 .2-.3-.2z" fill="none" stroke="#ececec" stroke-width=".21"/>
<path d="M175.6 95.6l.3 .2-.1 .2-.3-.2z" fill="#ececec"/>
<path d="M175.6 95.6l.3 .2-.1 .2-.3-.2z" fill="none" stroke="#ececec" stroke-width=".21"/>
<path d="M176.6 89.3l.4 .2-.2 .2-.3-.2z" fill="#ececec"/>
<path d="M176.6 89.3l.4 .2-.2 .2-.3-.2z" fill="none" stroke="#ececec" stroke-width=".21"/>
<path d="M180.3 91.8l.3 .2-.1 .2-.3-.2z" fill="#ececec"/>
<path d="M180.3 91.8l.3 .2-.1 .2-.3-.2z" fill="none" stroke="#ececec" stroke-width=".21"/>
<path d="M181 86.8l.4 .2-.2 .2-.3-.2z" fill="#ececec"/>
<path d="M181 86.8l.4 .2-.2 .2-.3-.2z" fill="none" stroke="#ececec" stroke-width=".21"/>
<path d="M156.6 96l.3 .2-.1 .2-.3-.2z" fill="#ececec"/>
<path d="M156.6 96l.3 .2-.1 .2-.3-.2z" fill="none" stroke="#ececec" stroke-width=".21"/>
<path d="M153 93.6l.3 .2-.1 .2-.3-.2z" fill="#ececec"/>
<path d="M153 93.6l.3 .2-.1 .2-.3-.2z" fill="none" stroke="#ececec" stroke-width=".21"/>
<path d="M149.8 87.3l.3 .2-.1 .2-.3-.2z" fill="#ececec"/>
<path d="M149.8 87.3l.3 .2-.1 .2-.3-.2z" fill="none" stroke="#ececec" stroke-width=".21"/>
<path d="M163.3 88l.3 .2-.1 .2-.3-.2z" fill="#ececec"/>
<path d="M163.3 88l.3 .2-.1 .2-.3-.2z" fill="none" stroke="#ececec" stroke-width=".21"/>
<path d="M149.8 91l.3 .2-.1 .2-.3-.2z" fill="#ececec"/>
<path d="M149.8 91l.3 .2-.1 .2-.3-.2z" fill="none" stroke="#ececec" stroke-width=".21"/>
<path d="M158.2 44.1l.3 .1-.1 .2-.3-.2z" fill="#ececec"/>
<path d="M158.2 44.1l.3 .1-.1 .2-.3-.2z" fill="none" stroke="#ececec" stroke-width=".21"/>
<path d="M174.7 53.4l.3 .2-.1 .1-.3-.1z" fill="#ececec"/>
<path d="M174.7 53.4l.3 .2-.1 .1-.3-.1z" fill="none" stroke="#ececec" stroke-width=".21"/>
<path d="M165.9 41.9l.3 .2-.1 .2-.3-.2z" fill="#ececec"/>
<path d="M165.9 41.9l.3 .2-.1 .2-.3-.2z" fill="none" stroke="#ececec" stroke-width=".21"/>
<path d="M159.3 41.1l.3 .2-.1 .2-.3-.2z" fill="#ececec"/>
<path d="M159.3 41.1l.3 .2-.1 .2-.3-.2z" fill="none" stroke="#ececec" stroke-width=".21"/>
<path d="M159.6 46.3l.3 .1-.1 .2-.3-.2z" fill="#ececec"/>
<path d="M159.6 46.3l.3 .1-.1 .2-.3-.2z" fill="none" stroke="#ececec" stroke-width=".21"/>
<path d="M144.7 41.1l.3 .2-.1 .2-.3-.2z" fill="#ececec"/>
<path d="M144.7 41.1l.3 .2-.1 .2-.3-.2z" fill="none" stroke="#ececec" stroke-width=".21"/>
<path d="M150.7 43.9l.3 .2-.1 .2-.3-.2z" fill="#ececec"/>
<path d="M150.7 43.9l.3 .2-.1 .2-.3-.2z" fill="none" stroke="#ececec" stroke-width=".21"/>
<path d="M143.7 44.9l.3 .2-.1 .2-.3-.2z" fill="#ececec"/>
<path d="M143.7 44.9l.3 .2-.1 .2-.3-.2z" fill="none" stroke="#ececec" stroke-width=".21"/>
<path d="M149.3 49.9l.3 .2-.1 .2-.3-.2z" fill="#ececec"/>
<path d="M149.3 49.9l.3 .2-.1 .2-.3-.2z" fill="none" stroke="#ececec" stroke-width=".21"/>
<path d="M143.6 43.7l.3 .2-.1 .2-.3-.2z" fill="#ececec"/>
<path d="M143.6 43.7l.3 .2-.1 .2-.3-.2z" fill="none" stroke="#ececec" stroke-width=".21"/>
<path d="M149.4 41.9l.3 .2-.1 .2-.3-.2z" fill="#ececec"/>
<path d="M149.4 41.9l.3 .2-.1 .2-.3-.2z" fill="none" stroke="#ececec" stroke-width=".21"/>
<path d="M155 79.4l.3 .2-.1 .2-.3-.2z" fill="#ececec"/>
<path d="M155 79.4l.3 .2-.1 .2-.3-.2z" fill="none" stroke="#ececec" stroke-width=".21"/>
<path d="M155 69.5l.3 .2-.1 .2-.3-.2z" fill="#ececec"/>
<path d="M155 69.5l.3 .2-.1 .2-.3-.2z" fill="none" stroke="#ececec" stroke-width=".21"/>
<path d="M159.2 73.9l.3 .1-.1 .2-.3-.2z" fill="#ececec"/>
<path d="M159.2 73.9l.3 .1-.1 .2-.3-.2z" fill="none" stroke="#ececec" stroke-width=".21"/>
<path d="M158.4 82l.3 .2-.1 .2-.4-.2z" fill="#ececec"/>
<path d="M158.4 82l.3 .2-.1 .2-.4-.2z" fill="none" stroke="#ececec" stroke-width=".21"/>
<path d="M163.3 69.5l.3 .1-.1 .2-.3-.2z" fill="#ececec"/>
<path d="M163.3 69.5l.3 .1-.1 .2-.3-.2z" fill="none" stroke="#ececec" stroke-width=".21"/>
<path d="M149.1 74.4l.3 .2-.1 .2-.3-.2z" fill="#ececec"/>
<path d="M149.1 74.4l.3 .2-.1 .2-.3-.2z" fill="none" stroke="#ececec" stroke-width=".21"/>
<path d="M165.1 72.2l.3 .2-.1 .2-.3-.2z" fill="#ececec"/>
<path d="M165.1 72.2l.3 .2-.1 .2-.3-.2z" fill="none" stroke="#ececec" stroke-width=".21"/>
<path d="M137.1 43.9l.3 .2-.1 .2-.3-.2z" fill="#ececec"/>
<path d="M137.1 43.9l.3 .2-.1 .2-.3-.2z" fill="none" stroke="#ececec" stroke-width=".21"/>
<path d="M138.5 53.7l.3 .2-.1 .2-.4-.2z" fill="#ececec"/>
<path d="M138.5 53.7l.3 .2-.1 .2-.4-.2z" fill="none" stroke="#ececec" stroke-width=".21"/>
<path d="M138 41.8l.3 .2-.1 .2-.3-.2z" fill="#ececec"/>
<path d="M138 41.8l.3 .2-.1 .2-.3-.2z" fill="none" stroke="#ececec" stroke-width=".21"/>
<path d="M138.3 47l.3 .2-.1 .2-.3-.2z" fill="#ececec"/>
<path d="M138.3 47l.3 .2-.1 .2-.3-.2z" fill="none" stroke="#ececec" stroke-width=".21"/>
<path d="M165 59.3l.4 .2-.2 .2-.3-.2z" fill="#ececec"/>
<path d="M165 59.3l.4 .2-.2 .2-.3-.2z" fill="none" stroke="#ececec" stroke-width=".21"/>
<path d="M153 54.1l.3 .2-.1 .2-.3-.2z" fill="#ececec"/>
<path d="M153 54.1l.3 .2-.1 .2-.3-.2z" fill="none" stroke="#ececec" stroke-width=".21"/>
<path d="M155 59.5l.3 .1-.1 .2-.3-.2z" fill="#ececec"/>
<path d="M155 59.5l.3 .1-.1 .2-.3-.2z" fill="none" stroke="#ececec" stroke-width=".21"/>
<path d="M159.8 61.9l.3 .2-.1 .2-.3-.2z" fill="#ececec"/>
<path d="M159.8 61.9l.3 .2-.1 .2-.3-.2z" fill="none" stroke="#ececec" stroke-width=".21"/>
<path d="M159.3 54.4l.3 .2-.1 .2-.3-.2z" fill="#ececec"/>
<path d="M159.3 54.4l.3 .2-.1 .2-.3-.2z" fill="none" stroke="#ececec" stroke-width=".21"/>
<path d="M151.5 64.7l.3 .2-.1 .2-.3-.2z" fill="#ececec"/>
<path d="M151.5 64.7l.3 .2-.1 .2-.3-.2z" fill="none" stroke="#ececec" stroke-width=".21"/>
<path d="M163.9 64.7l.3 .2-.1 .2-.4-.2z" fill="#ececec"/>
<path d="M163.9 64.7l.3 .2-.1 .2-.4-.2z" fill="none" stroke="#ececec" stroke-width=".21"/>
<path d="M137.9 58.9l.4 .2-.1 .1-.4-.1z" fill="#ececec"/>
<path d="M137.9 58.9l.4 .2-.1 .1-.4-.1z" fill="none" stroke="#ececec" stroke-width=".21"/>
<path d="M134.2 60.2l.3 .2-.1 .2-.3-.2z" fill="#ececec"/>
<path d="M134.2 60.2l.3 .2-.1 .2-.3-.2z" fill="none" stroke="#ececec" stroke-width=".21"/>
<path d="M144.5 59.5l.3 .1-.1 .2-.3-.2z" fill="#ececec"/>
<path d="M144.5 59.5l.3 .1-.1 .2-.3-.2z" fill="none" stroke="#ececec" stroke-width=".21"/>
<path d="M136.8 69.1l.4 .2-.1 .2-.4-.2z" fill="#ececec"/>
<path d="M136.8 69.1l.4 .2-.1 .2-.4-.2z" fill="none" stroke="#ececec" stroke-width=".21"/>
<path d="M138 69.7l.3 .2-.1 .2-.3-.2z" fill="#ececec"/>
<path d="M138 69.7l.3 .2-.1 .2-.3-.2z" fill="none" stroke="#ececec" stroke-width=".21"/>
<path d="M138.8 71.2l.3 .2-.1 .2-.3-.2z" fill="#ececec"/>
<path d="M138.8 71.2l.3 .2-.1 .2-.3-.2z" fill="none" stroke="#ececec" stroke-width=".21"/>
<path d="M138.1 80.9l.3 .2-.1 .2-.3-.2z" fill="#ececec"/>
<path d="M138.1 80.9l.3 .2-.1 .2-.3-.2z" fill="none" stroke="#ececec" stroke-width=".21"/>
<path d="M138.9 72.6l.3 .2-.1 .2-.3-.2z" fill="#ececec"/>
<path d="M138.9 72.6l.3 .2-.1 .2-.3-.2z" fill="none" stroke="#ececec" stroke-width=".21"/>
<path d="M138.5 76l.4 .2-.2 .1-.3-.1z" fill="#ececec"/>
<path d="M138.5 76l.4 .2-.2 .1-.3-.1z" fill="none" stroke="#ececec" stroke-width=".21"/>
<path d="M136.8 75l.4 .1-.1 .2-.4-.2z" fill="#ececec"/>
<path d="M136.8 75l.4 .1-.1 .2-.4-.2z" fill="none" stroke="#ececec" stroke-width=".21"/>
<path d="M187.8 71.1l.3 .1-.1 .2-.3-.2z" fill="#ececec"/>
<path d="M187.8 71.1l.3 .1-.1 .2-.3-.2z" fill="none" stroke="#ececec" stroke-width=".21"/>
<path d="M187.8 75.4l.3 .2-.1 .2-.3-.2z" fill="#ececec"/>
<path d="M187.8 75.4l.3 .2-.1 .2-.3-.2z" fill="none" stroke="#ececec" stroke-width=".21"/>
<path d="M185.2 72.1l.3 .2-.1 .2-.3-.2z" fill="#ececec"/>
<path d="M185.2 72.1l.3 .2-.1 .2-.3-.2z" fill="none" stroke="#ececec" stroke-width=".21"/>
<path d="M184.9 76.1l.4 .1-.2 .2-.3-.2z" fill="#ececec"/>
<path d="M184.9 76.1l.4 .1-.2 .2-.3-.2z" fill="none" stroke="#ececec" stroke-width=".21"/>
<path d="M183.1 74.7l.3 .2-.1 .2-.3-.2z" fill="#ececec"/>
<path d="M183.1 74.7l.3 .2-.1 .2-.3-.2z" fill="none" stroke="#ececec" stroke-width=".21"/>
<path d="M178.6 65.8l.3 .2-.1 .2-.3-.2z" fill="#ececec"/>
<path d="M178.6 65.8l.3 .2-.1 .2-.3-.2z" fill="none" stroke="#ececec" stroke-width=".21"/>
<path d="M173.5 69.3l.3 .2-.1 .2-.3-.2z" fill="#ececec"/>
<path d="M173.5 69.3l.3 .2-.1 .2-.3-.2z" fill="none" stroke="#ececec" stroke-width=".21"/>
<path d="M176.8 62.8l.3 .1-.1 .2-.3-.2z" fill="#ececec"/>
<path d="M176.8 62.8l.3 .1-.1 .2-.3-.2z" fill="none" stroke="#ececec" stroke-width=".21"/>
<path d="M175.4 71.1l.3 .1-.1 .2-.3-.2z" fill="#ececec"/>
<path d="M175.4 71.1l.3 .1-.1 .2-.3-.2z" fill="none" stroke="#ececec" stroke-width=".21"/>
<path d="M180.2 71.1l.3 .2-.1 .2-.3-.2z" fill="#ececec"/>
<path d="M180.2 71.1l.3 .2-.1 .2-.3-.2z" fill="none" stroke="#ececec" stroke-width=".21"/>
<path d="M177.4 74.2l.3 .2-.1 .2-.3-.2z" fill="#ececec"/>
<path d="M177.4 74.2l.3 .2-.1 .2-.3-.2z" fill="none" stroke="#ececec" stroke-width=".21"/>
<path d="M197.1 62.1l.3 .2-.1 .2-.3-.2z" fill="#ececec"/>
<path d="M197.1 62.1l.3 .2-.1 .2-.3-.2z" fill="none" stroke="#ececec" stroke-width=".21"/>
<path d="M196.6 69.8l.3 .2-.1 .2-.3-.2z" fill="#ececec"/>
<path d="M196.6 69.8l.3 .2-.1 .2-.3-.2z" fill="none" stroke="#ececec" stroke-width=".21"/>
<path d="M192.1 67l.3 .2-.1 .2-.3-.2z" fill="#ececec"/>
<path d="M192.1 67l.3 .2-.1 .2-.3-.2z" fill="none" stroke="#ececec" stroke-width=".21"/>
<path d="M197.2 55.1l.3 .2-.1 .2-.3-.2z" fill="#ececec"/>
<path d="M197.2 55.1l.3 .2-.1 .2-.3-.2z" fill="none" stroke="#ececec" stroke-width=".21"/>
<path d="M193.7 69.8l.3 .2-.1 .2-.4-.2z" fill="#ececec"/>
<path d="M193.7 69.8l.3 .2-.1 .2-.4-.2z" fill="none" stroke="#ececec" stroke-width=".21"/>
<path d="M188.4 68.3l.3 .2-.1 .1-.3-.1z" fill="#ececec"/>
<path d="M188.4 68.3l.3 .2-.1 .1-.3-.1z" fill="none" stroke="#ececec" stroke-width=".21"/>
<path d="M189.8 70.3l.3 .2-.1 .2-.3-.2z" fill="#ececec"/>
<path d="M189.8 70.3l.3 .2-.1 .2-.3-.2z" fill="none" stroke="#ececec" stroke-width=".21"/>
<path d="M169.3 77.3l.3 .2-.1 .2-.3-.2z" fill="#ececec"/>
<path d="M169.3 77.3l.3 .2-.1 .2-.3-.2z" fill="none" stroke="#ececec" stroke-width=".21"/>
<path d="M165.5 80.9l.3 .2-.1 .2-.3-.2z" fill="#ececec"/>
<path d="M165.5 80.9l.3 .2-.1 .2-.3-.2z" fill="none" stroke="#ececec" stroke-width=".21"/>
<path d="M173.7 81l.3 .2-.1 .2-.3-.2z" fill="#ececec"/>
<path d="M173.7 81l.3 .2-.1 .2-.3-.2z" fill="none" stroke="#ececec" stroke-width=".21"/>
<path d="M168.4 82.1l.3 .2-.1 .1-.3-.1z" fill="#ececec"/>
<path d="M168.4 82.1l.3 .2-.1 .1-.3-.1z" fill="none" stroke="#ececec" stroke-width=".21"/>
<path d="M166.1 78.8l.3 .2-.1 .1-.4-.1z" fill="#ececec"/>
<path d="M166.1 78.8l.3 .2-.1 .1-.4-.1z" fill="none" stroke="#ececec" stroke-width=".21"/>
<path d="M172.2 77.1l.4 .2-.2 .1-.3-.1z" fill="#ececec"/>
<path d="M172.2 77.1l.4 .2-.2 .1-.3-.1z" fill="none" stroke="#ececec" stroke-width=".21"/>
<path d="M173.9 78.2l.3 .2-.1 .1-.3-.1z" fill="#ececec"/>
<path d="M173.9 78.2l.3 .2-.1 .1-.3-.1z" fill="none" stroke="#ececec" stroke-width=".21"/>
<path d="M189.8 75.4l.4 .2-.1 .2-.4-.2z" fill="#ececec"/>
<path d="M189.8 75.4l.4 .2-.1 .2-.4-.2z" fill="none" stroke="#ececec" stroke-width=".21"/>
<path d="M196.6 83.8l.3 .2-.1 .2-.3-.2z" fill="#ececec"/>
<path d="M196.6 83.8l.3 .2-.1 .2-.3-.2z" fill="none" stroke="#ececec" stroke-width=".21"/>
<path d="M190.4 81.8l.4 .2-.2 .2-.3-.2z" fill="#ececec"/>
<path d="M190.4 81.8l.4 .2-.2 .2-.3-.2z" fill="none" stroke="#ececec" stroke-width=".21"/>
<path d="M197.5 74.4l.3 .1-.1 .2-.3-.2z" fill="#ececec"/>
<path d="M197.5 74.4l.3 .1-.1 .2-.3-.2z" fill="none" stroke="#ececec" stroke-width=".21"/>
<path d="M173.9 73.3l.3 .1-.1 .2-.3-.2z" fill="#ececec"/>
<path d="M173.9 73.3l.3 .1-.1 .2-.3-.2z" fill="none" stroke="#ececec" stroke-width=".21"/>
<path d="M165.5 74.3l.3 .2-.1 .2-.3-.2z" fill="#ececec"/>
<path d="M165.5 74.3l.3 .2-.1 .2-.3-.2z" fill="none" stroke="#ececec" stroke-width=".21"/>
<path d="M166.8 76.6l.3 .2-.1 .1-.3-.1z" fill="#ececec"/>
<path d="M166.8 76.6l.3 .2-.1 .1-.3-.1z" fill="none" stroke="#ececec" stroke-width=".21"/>
<path d="M166.4 71.8l.3 .2-.1 .2-.3-.2z" fill="#ececec"/>
<path d="M166.4 71.8l.3 .2-.1 .2-.3-.2z" fill="none" stroke="#ececec" stroke-width=".21"/>
<path d="M169.8 68.4l.3 .2-.1 .2-.3-.2z" fill="#ececec"/>
<path d="M169.8 68.4l.3 .2-.1 .2-.3-.2z" fill="none" stroke="#ececec" stroke-width=".21"/>
<path d="M167.2 68.3l.3 .2-.1 .1-.4-.1z" fill="#ececec"/>
<path d="M167.2 68.3l.3 .2-.1 .1-.4-.1z" fill="none" stroke="#ececec" stroke-width=".21"/>
<path d="M184.3 77.7l.3 .2-.1 .1-.4-.1z" fill="#ececec"/>
<path d="M184.3 77.7l.3 .2-.1 .1-.4-.1z" fill="none" stroke="#ececec" stroke-width=".21"/>
<path d="M181.7 75.2l.3 .2-.1 .2-.3-.2z" fill="#ececec"/>
<path d="M181.7 75.2l.3 .2-.1 .2-.3-.2z" fill="none" stroke="#ececec" stroke-width=".21"/>
<path d="M178.1 78.6l.3 .2-.1 .2-.3-.2z" fill="#ececec"/>
<path d="M178.1 78.6l.3 .2-.1 .2-.3-.2z" fill="none" stroke="#ececec" stroke-width=".21"/>
<path d="M177.8 82.4l.3 .2-.1 .2-.3-.2z" fill="#ececec"/>
<path d="M177.8 82.4l.3 .2-.1 .2-.3-.2z" fill="none" stroke="#ececec" stroke-width=".21"/>
<path d="M177.6 81.3l.3 .2-.1 .2-.3-.2z" fill="#ececec"/>
<path d="M177.6 81.3l.3 .2-.1 .2-.3-.2z" fill="none" stroke="#ececec" stroke-width=".21"/>
<path d="M184.8 80.5l.3 .2-.1 .2-.3-.2z" fill="#ececec"/>
<path d="M184.8 80.5l.3 .2-.1 .2-.3-.2z" fill="none" stroke="#ececec" stroke-width=".21"/>
<path d="M183.2 81.4l.3 .2-.1 .2-.4-.2z" fill="#ececec"/>
<path d="M183.2 81.4l.3 .2-.1 .2-.4-.2z" fill="none" stroke="#ececec" stroke-width=".21"/>
<path d="M183.7 84.1l.3 .2-.1 .2-.3-.2z" fill="#ececec"/>
<path d="M183.7 84.1l.3 .2-.1 .2-.3-.2z" fill="none" stroke="#ececec" stroke-width=".21"/>
<path d="M186.8 82.5l.3 .2-.1 .2-.3-.2z" fill="#ececec"/>
<path d="M186.8 82.5l.3 .2-.1 .2-.3-.2z" fill="none" stroke="#ececec" stroke-width=".21"/>
<path d="M185.3 84.4l.3 .1-.1 .2-.3-.2z" fill="#ececec"/>
<path d="M185.3 84.4l.3 .1-.1 .2-.3-.2z" fill="none" stroke="#ececec" stroke-width=".21"/>
<path d="M174.3 142.9l.3 .1-.1 .2-.3-.2z" fill="#ececec"/>
<path d="M174.3 142.9l.3 .1-.1 .2-.3-.2z" fill="none" stroke="#ececec" stroke-width=".21"/>
<path d="M180.5 147.9l.3 .2-.1 .2-.3-.2z" fill="#ececec"/>
<path d="M180.5 147.9l.3 .2-.1 .2-.3-.2z" fill="none" stroke="#ececec" stroke-width=".21"/>
<path d="M159.2 145.6l.3 .2-.1 .1-.3-.1z" fill="#ececec"/>
<path d="M159.2 145.6l.3 .2-.1 .1-.3-.1z" fill="none" stroke="#ececec" stroke-width=".21"/>
<path d="M171.9 144.5l.3 .2-.1 .1-.3-.1z" fill="#ececec"/>
<path d="M171.9 144.5l.3 .2-.1 .1-.3-.1z" fill="none" stroke="#ececec" stroke-width=".21"/>
<path d="M171.8 140.7l.3 .2-.1 .2-.3-.2z" fill="#ececec"/>
<path d="M171.8 140.7l.3 .2-.1 .2-.3-.2z" fill="none" stroke="#ececec" stroke-width=".21"/>
<path d="M150.3 145.4l.3 .2-.1 .2-.3-.2z" fill="#ececec"/>
<path d="M150.3 145.4l.3 .2-.1 .2-.3-.2z" fill="none" stroke="#ececec" stroke-width=".21"/>
<path d="M143.7 145.4l.3 .2-.1 .2-.3-.2z" fill="#ececec"/>
<path d="M143.7 145.4l.3 .2-.1 .2-.3-.2z" fill="none" stroke="#ececec" stroke-width=".21"/>
<path d="M151.2 140.7l.4 .2-.2 .2-.3-.2z" fill="#ececec"/>
<path d="M151.2 140.7l.4 .2-.2 .2-.3-.2z" fill="none" stroke="#ececec" stroke-width=".21"/>
<path d="M146.3 138.9l.3 .2-.1 .2-.3-.2z" fill="#ececec"/>
<path d="M146.3 138.9l.3 .2-.1 .2-.3-.2z" fill="none" stroke="#ececec" stroke-width=".21"/>
<path d="M144.7 143.4l.3 .2-.1 .2-.3-.2z" fill="#ececec"/>
<path d="M144.7 143.4l.3 .2-.1 .2-.3-.2z" fill="none" stroke="#ececec" stroke-width=".21"/>
<path d="M136.2 139.2l.3 .2-.1 .2-.3-.2z" fill="#ececec"/>
<path d="M136.2 139.2l.3 .2-.1 .2-.3-.2z" fill="none" stroke="#ececec" stroke-width=".21"/>
<path d="M134.2 140l.3 .2-.1 .2-.3-.2z" fill="#ececec"/>
<path d="M134.2 140l.3 .2-.1 .2-.3-.2z" fill="none" stroke="#ececec" stroke-width=".21"/>
<path d="M138.5 138.7l.4 .2-.2 .2-.3-.2z" fill="#ececec"/>
<path d="M138.5 138.7l.4 .2-.2 .2-.3-.2z" fill="none" stroke="#ececec" stroke-width=".21"/>
<path d="M136 141.5l.3 .2-.1 .2-.3-.2z" fill="#ececec"/>
<path d="M136 141.5l.3 .2-.1 .2-.3-.2z" fill="none" stroke="#ececec" stroke-width=".21"/>
<path d="M141.1 140.2l.3 .2-.1 .2-.3-.2z" fill="#ececec"/>
<path d="M141.1 140.2l.3 .2-.1 .2-.3-.2z" fill="none" stroke="#ececec" stroke-width=".21"/>
<path d="M134.5 136.9l.3 .2-.1 .2-.3-.2z" fill="#ececec"/>
<path d="M134.5 136.9l.3 .2-.1 .2-.3-.2z" fill="none" stroke="#ececec" stroke-width=".21"/>
<path d="M139.4 132.7l.3 .2-.1 .2-.3-.2z" fill="#ececec"/>
<path d="M139.4 132.7l.3 .2-.1 .2-.3-.2z" fill="none" stroke="#ececec" stroke-width=".21"/>
<path d="M137 135.7l.3 .1-.1 .2-.3-.2z" fill="#ececec"/>
<path d="M137 135.7l.3 .1-.1 .2-.3-.2z" fill="none" stroke="#ececec" stroke-width=".21"/>
<path d="M138.5 132.3l.3 .2-.1 .1-.4-.1z" fill="#ececec"/>
<path d="M138.5 132.3l.3 .2-.1 .1-.4-.1z" fill="none" stroke="#ececec" stroke-width=".21"/>
<path d="M140.2 132.8l.3 .2-.1 .2-.3-.2z" fill="#ececec"/>
<path d="M140.2 132.8l.3 .2-.1 .2-.3-.2z" fill="none" stroke="#ececec" stroke-width=".21"/>
<path d="M134.2 145.3l.3 .2-.1 .2-.3-.2z" fill="#ececec"/>
<path d="M134.2 145.3l.3 .2-.1 .2-.3-.2z" fill="none" stroke="#ececec" stroke-width=".21"/>
<path d="M136 145.3l.3 .2-.1 .2-.3-.2z" fill="#ececec"/>
<path d="M136 145.3l.3 .2-.1 .2-.3-.2z" fill="none" stroke="#ececec" stroke-width=".21"/>
<path d="M139 145.1l.4 .2-.1 .2-.4-.2z" fill="#ececec"/>
<path d="M139 145.1l.4 .2-.1 .2-.4-.2z" fill="none" stroke="#ececec" stroke-width=".21"/>
<path d="M141.1 145.7l.3 .2-.1 .2-.3-.2z" fill="#ececec"/>
<path d="M141.1 145.7l.3 .2-.1 .2-.3-.2z" fill="none" stroke="#ececec" stroke-width=".21"/>
<path d="M143.1 136.1l.3 .2-.1 .2-.3-.2z" fill="#ececec"/>
<path d="M143.1 136.1l.3 .2-.1 .2-.3-.2z" fill="none" stroke="#ececec" stroke-width=".21"/>
<path d="M142.9 141.7l.3 .2-.1 .1-.4-.1z" fill="#ececec"/>
<path d="M142.9 141.7l.3 .2-.1 .1-.4-.1z" fill="none" stroke="#ececec" stroke-width=".21"/>
<path d="M142.6 143l.3 .2-.1 .2-.3-.2z" fill="#ececec"/>
<path d="M142.6 143l.3 .2-.1 .2-.3-.2z" fill="none" stroke="#ececec" stroke-width=".21"/>
<path d="M143.3 140.7l.3 .1-.1 .2-.3-.2z" fill="#ececec"/>
<path d="M143.3 140.7l.3 .1-.1 .2-.3-.2z" fill="none" stroke="#ececec" stroke-width=".21"/>
<path d="M142.6 139l.3 .1-.1 .2-.3-.2z" fill="#ececec"/>
<path d="M142.6 139l.3 .1-.1 .2-.3-.2z" fill="none" stroke="#ececec" stroke-width=".21"/>
<path d="M141.8 137.4l.4 .1-.2 .2-.3-.2z" fill="#ececec"/>
<path d="M141.8 137.4l.4 .1-.2 .2-.3-.2z" fill="none" stroke="#ececec" stroke-width=".21"/>
<path d="M154.7 135.8l.3 .2-.1 .2-.3-.2z" fill="#ececec"/>
<path d="M154.7 135.8l.3 .2-.1 .2-.3-.2z" fill="none" stroke="#ececec" stroke-width=".21"/>
<path d="M166 133.5l.3 .2-.1 .2-.3-.2z" fill="#ececec"/>
<path d="M166 133.5l.3 .2-.1 .2-.3-.2z" fill="none" stroke="#ececec" stroke-width=".21"/>
<path d="M167.8 138.2l.3 .2-.1 .2-.3-.2z" fill="#ececec"/>
<path d="M167.8 138.2l.3 .2-.1 .2-.3-.2z" fill="none" stroke="#ececec" stroke-width=".21"/>
<path d="M157.1 136.1l.3 .2-.1 .2-.3-.2z" fill="#ececec"/>
<path d="M157.1 136.1l.3 .2-.1 .2-.3-.2z" fill="none" stroke="#ececec" stroke-width=".21"/>
<path d="M163.4 136.8l.3 .2-.1 .2-.3-.2z" fill="#ececec"/>
<path d="M163.4 136.8l.3 .2-.1 .2-.3-.2z" fill="none" stroke="#ececec" stroke-width=".21"/>
<path d="M159.1 134.9l.3 .2-.1 .2-.3-.2z" fill="#ececec"/>
<path d="M159.1 134.9l.3 .2-.1 .2-.3-.2z" fill="none" stroke="#ececec" stroke-width=".21"/>
<path d="M156.5 138.7l.3 .2-.1 .2-.3-.2z" fill="#ececec"/>
<path d="M156.5 138.7l.3 .2-.1 .2-.3-.2z" fill="none" stroke="#ececec" stroke-width=".21"/>
<path d="M157.1 133.5l.3 .1-.1 .2-.3-.2z" fill="#ececec"/>
<path d="M157.1 133.5l.3 .1-.1 .2-.3-.2z" fill="none" stroke="#ececec" stroke-width=".21"/>
<path d="M160.5 131.5l.3 .2-.1 .2-.3-.2z" fill="#ececec"/>
<path d="M160.5 131.5l.3 .2-.1 .2-.3-.2z" fill="none" stroke="#ececec" stroke-width=".21"/>
<path d="M157.5 126.6l.3 .2-.1 .2-.3-.2z" fill="#ececec"/>
<path d="M157.5 126.6l.3 .2-.1 .2-.3-.2z" fill="none" stroke="#ececec" stroke-width=".21"/>
<path d="M164.4 132.8l.3 .2-.1 .2-.3-.2z" fill="#ececec"/>
<path d="M164.4 132.8l.3 .2-.1 .2-.3-.2z" fill="none" stroke="#ececec" stroke-width=".21"/>
<path d="M165.9 122.2l.3 .2-.1 .2-.3-.2z" fill="#ececec"/>
<path d="M165.9 122.2l.3 .2-.1 .2-.3-.2z" fill="none" stroke="#ececec" stroke-width=".21"/>
<path d="M164.4 131.4l.4 .2-.1 .2-.4-.2z" fill="#ececec"/>
<path d="M164.4 131.4l.4 .2-.1 .2-.4-.2z" fill="none" stroke="#ececec" stroke-width=".21"/>
<path d="M166.7 126.4l.3 .2-.1 .2-.3-.2z" fill="#ececec"/>
<path d="M166.7 126.4l.3 .2-.1 .2-.3-.2z" fill="none" stroke="#ececec" stroke-width=".21"/>
<path d="M151.8 135.8l.3 .2-.1 .2-.3-.2z" fill="#ececec"/>
<path d="M151.8 135.8l.3 .2-.1 .2-.3-.2z" fill="none" stroke="#ececec" stroke-width=".21"/>
<path d="M148.9 138.9l.3 .2-.1 .2-.3-.2z" fill="#ececec"/>
<path d="M148.9 138.9l.3 .2-.1 .2-.3-.2z" fill="none" stroke="#ececec" stroke-width=".21"/>
<path d="M148.5 137.2l.3 .2-.1 .2-.3-.2z" fill="#ececec"/>
<path d="M148.5 137.2l.3 .2-.1 .2-.3-.2z" fill="none" stroke="#ececec" stroke-width=".21"/>
<path d="M146.4 135.7l.3 .2-.1 .2-.3-.2z" fill="#ececec"/>
<path d="M146.4 135.7l.3 .2-.1 .2-.3-.2z" fill="none" stroke="#ececec" stroke-width=".21"/>
<path d="M144.6 137.7l.3 .2-.1 .2-.4-.2z" fill="#ececec"/>
<path d="M144.6 137.7l.3 .2-.1 .2-.4-.2z" fill="none" stroke="#ececec" stroke-width=".21"/>
<path d="M151.2 127.4l.3 .2-.1 .1-.4-.1z" fill="#ececec"/>
<path d="M151.2 127.4l.3 .2-.1 .1-.4-.1z" fill="none" stroke="#ececec" stroke-width=".21"/>
<path d="M151.2 124.2l.3 .2-.1 .2-.4-.2z" fill="#ececec"/>
<path d="M151.2 124.2l.3 .2-.1 .2-.4-.2z" fill="none" stroke="#ececec" stroke-width=".21"/>
<path d="M152.4 122.1l.3 .2-.1 .2-.3-.2z" fill="#ececec"/>
<path d="M152.4 122.1l.3 .2-.1 .2-.3-.2z" fill="none" stroke="#ececec" stroke-width=".21"/>
<path d="M152.2 133l.3 .2-.1 .2-.3-.2z" fill="#ececec"/>
<path d="M152.2 133l.3 .2-.1 .2-.3-.2z" fill="none" stroke="#ececec" stroke-width=".21"/>
<path d="M151.2 131.7l.3 .2-.1 .2-.4-.2z" fill="#ececec"/>
<path d="M151.2 131.7l.3 .2-.1 .2-.4-.2z" fill="none" stroke="#ececec" stroke-width=".21"/>
<path d="M154.3 132.4l.3 .1-.1 .2-.3-.2z" fill="#ececec"/>
<path d="M154.3 132.4l.3 .1-.1 .2-.3-.2z" fill="none" stroke="#ececec" stroke-width=".21"/>
<path d="M152.8 129.3l.4 .2-.1 .2-.4-.2z" fill="#ececec"/>
<path d="M152.8 129.3l.4 .2-.1 .2-.4-.2z" fill="none" stroke="#ececec" stroke-width=".21"/>
<path d="M144.8 134.1l.3 .2-.1 .2-.3-.2z" fill="#ececec"/>
<path d="M144.8 134.1l.3 .2-.1 .2-.3-.2z" fill="none" stroke="#ececec" stroke-width=".21"/>
<path d="M145.6 131.8l.3 .2-.1 .2-.3-.2z" fill="#ececec"/>
<path d="M145.6 131.8l.3 .2-.1 .2-.3-.2z" fill="none" stroke="#ececec" stroke-width=".21"/>
<path d="M147.9 133.4l.3 .2-.1 .1-.4-.1z" fill="#ececec"/>
<path d="M147.9 133.4l.3 .2-.1 .1-.4-.1z" fill="none" stroke="#ececec" stroke-width=".21"/>
<path d="M144.5 134.8l.3 .2-.1 .2-.3-.2z" fill="#ececec"/>
<path d="M144.5 134.8l.3 .2-.1 .2-.3-.2z" fill="none" stroke="#ececec" stroke-width=".21"/>
<path d="M147.4 129.5l.3 .2-.1 .2-.3-.2z" fill="#ececec"/>
<path d="M147.4 129.5l.3 .2-.1 .2-.3-.2z" fill="none" stroke="#ececec" stroke-width=".21"/>
<path d="M163.3 114.1l.4 .2-.1 .1-.4-.1z" fill="#ececec"/>
<path d="M163.3 114.1l.4 .2-.1 .1-.4-.1z" fill="none" stroke="#ececec" stroke-width=".21"/>
<path d="M158.9 113.6l.3 .2-.1 .2-.4-.2z" fill="#ececec"/>
<path d="M158.9 113.6l.3 .2-.1 .2-.4-.2z" fill="none" stroke="#ececec" stroke-width=".21"/>
<path d="M160.4 120.1l.3 .2-.1 .2-.3-.2z" fill="#ececec"/>
<path d="M160.4 120.1l.3 .2-.1 .2-.3-.2z" fill="none" stroke="#ececec" stroke-width=".21"/>
<path d="M164.4 118.8l.3 .2-.1 .2-.3-.2z" fill="#ececec"/>
<path d="M164.4 118.8l.3 .2-.1 .2-.3-.2z" fill="none" stroke="#ececec" stroke-width=".21"/>
<path d="M175.5 113.6l.4 .1-.2 .2-.3-.2z" fill="#ececec"/>
<path d="M175.5 113.6l.4 .1-.2 .2-.3-.2z" fill="none" stroke="#ececec" stroke-width=".21"/>
<path d="M179.2 115.1l.3 .2-.1 .2-.3-.2z" fill="#ececec"/>
<path d="M179.2 115.1l.3 .2-.1 .2-.3-.2z" fill="none" stroke="#ececec" stroke-width=".21"/>
<path d="M181.6 126.9l.3 .2-.1 .2-.4-.2z" fill="#ececec"/>
<path d="M181.6 126.9l.3 .2-.1 .2-.4-.2z" fill="none" stroke="#ececec" stroke-width=".21"/>
<path d="M175.4 118.2l.3 .2-.1 .2-.3-.2z" fill="#ececec"/>
<path d="M175.4 118.2l.3 .2-.1 .2-.3-.2z" fill="none" stroke="#ececec" stroke-width=".21"/>
<path d="M174.2 122.6l.3 .2-.1 .2-.3-.2z" fill="#ececec"/>
<path d="M174.2 122.6l.3 .2-.1 .2-.3-.2z" fill="none" stroke="#ececec" stroke-width=".21"/>
<path d="M177.7 119.1l.3 .2-.1 .2-.4-.2z" fill="#ececec"/>
<path d="M177.7 119.1l.3 .2-.1 .2-.4-.2z" fill="none" stroke="#ececec" stroke-width=".21"/>
<path d="M175.4 128.1l.3 .2-.1 .2-.3-.2z" fill="#ececec"/>
<path d="M175.4 128.1l.3 .2-.1 .2-.3-.2z" fill="none" stroke="#ececec" stroke-width=".21"/>
<path d="M180.4 118.3l.4 .2-.1 .2-.4-.2z" fill="#ececec"/>
<path d="M180.4 118.3l.4 .2-.1 .2-.4-.2z" fill="none" stroke="#ececec" stroke-width=".21"/>
<path d="M170.3 122.9l.3 .2-.1 .2-.3-.2z" fill="#ececec"/>
<path d="M170.3 122.9l.3 .2-.1 .2-.3-.2z" fill="none" stroke="#ececec" stroke-width=".21"/>
<path d="M170 118.2l.3 .2-.1 .2-.4-.2z" fill="#ececec"/>
<path d="M170 118.2l.3 .2-.1 .2-.4-.2z" fill="none" stroke="#ececec" stroke-width=".21"/>
<path d="M166.6 123.5l.4 .2-.1 .1-.4-.1z" fill="#ececec"/>
<path d="M166.6 123.5l.4 .2-.1 .1-.4-.1z" fill="none" stroke="#ececec" stroke-width=".21"/>
<path d="M166.6 117.4l.4 .2-.1 .1-.4-.1z" fill="#ececec"/>
<path d="M166.6 117.4l.4 .2-.1 .1-.4-.1z" fill="none" stroke="#ececec" stroke-width=".21"/>
<path d="M170.7 118.1l.3 .2-.1 .2-.3-.2z" fill="#ececec"/>
<path d="M170.7 118.1l.3 .2-.1 .2-.3-.2z" fill="none" stroke="#ececec" stroke-width=".21"/>
<path d="M170 128.6l.3 .2-.1 .2-.3-.2z" fill="#ececec"/>
<path d="M170 128.6l.3 .2-.1 .2-.3-.2z" fill="none" stroke="#ececec" stroke-width=".21"/>
<path d="M170 115.3l.3 .2-.1 .2-.3-.2z" fill="#ececec"/>
<path d="M170 115.3l.3 .2-.1 .2-.3-.2z" fill="none" stroke="#ececec" stroke-width=".21"/>
<path d="M170.5 120.5l.3 .2-.1 .2-.4-.2z" fill="#ececec"/>
<path d="M170.5 120.5l.3 .2-.1 .2-.4-.2z" fill="none" stroke="#ececec" stroke-width=".21"/>
<path d="M172.4 136.9l.3 .2-.1 .2-.3-.2z" fill="#ececec"/>
<path d="M172.4 136.9l.3 .2-.1 .2-.3-.2z" fill="none" stroke="#ececec" stroke-width=".21"/>
<path d="M175.6 133.1l.3 .2-.1 .2-.3-.2z" fill="#ececec"/>
<path d="M175.6 133.1l.3 .2-.1 .2-.3-.2z" fill="none" stroke="#ececec" stroke-width=".21"/>
<path d="M170.3 132.9l.3 .2-.1 .1-.3-.1z" fill="#ececec"/>
<path d="M170.3 132.9l.3 .2-.1 .1-.3-.1z" fill="none" stroke="#ececec" stroke-width=".21"/>
<path d="M174.6 130.5l.3 .2-.1 .2-.3-.2z" fill="#ececec"/>
<path d="M174.6 130.5l.3 .2-.1 .2-.3-.2z" fill="none" stroke="#ececec" stroke-width=".21"/>
<path d="M169.9 135.2l.3 .2-.1 .2-.3-.2z" fill="#ececec"/>
<path d="M169.9 135.2l.3 .2-.1 .2-.3-.2z" fill="none" stroke="#ececec" stroke-width=".21"/>
<path d="M165.6 139.6l.3 .2-.1 .2-.3-.2z" fill="#ececec"/>
<path d="M165.6 139.6l.3 .2-.1 .2-.3-.2z" fill="none" stroke="#ececec" stroke-width=".21"/>
<path d="M133.8 147.9l.3 .2-.1 .2-.3-.2z" fill="#ececec"/>
<path d="M133.8 147.9l.3 .2-.1 .2-.3-.2z" fill="none" stroke="#ececec" stroke-width=".21"/>
<path d="M122.9 148.1l.3 .2-.1 .2-.3-.2z" fill="#ececec"/>
<path d="M122.9 148.1l.3 .2-.1 .2-.3-.2z" fill="none" stroke="#ececec" stroke-width=".21"/>
<path d="M127.4 142.3l.3 .2-.1 .2-.3-.2z" fill="#ececec"/>
<path d="M127.4 142.3l.3 .2-.1 .2-.3-.2z" fill="none" stroke="#ececec" stroke-width=".21"/>
<path d="M127 139.6l.3 .1-.1 .2-.3-.2z" fill="#ececec"/>
<path d="M127 139.6l.3 .1-.1 .2-.3-.2z" fill="none" stroke="#ececec" stroke-width=".21"/>
<path d="M126.9 136.3l.3 .1-.1 .2-.4-.2z" fill="#ececec"/>
<path d="M126.9 136.3l.3 .1-.1 .2-.4-.2z" fill="none" stroke="#ececec" stroke-width=".21"/>
<path d="M132.8 141.4l.3 .2-.1 .2-.3-.2z" fill="#ececec"/>
<path d="M132.8 141.4l.3 .2-.1 .2-.3-.2z" fill="none" stroke="#ececec" stroke-width=".21"/>
<path d="M125.5 131.6l.3 .2-.1 .2-.3-.2z" fill="#ececec"/>
<path d="M125.5 131.6l.3 .2-.1 .2-.3-.2z" fill="none" stroke="#ececec" stroke-width=".21"/>
<path d="M119.5 124.1l.3 .2-.1 .2-.3-.2z" fill="#ececec"/>
<path d="M119.5 124.1l.3 .2-.1 .2-.3-.2z" fill="none" stroke="#ececec" stroke-width=".21"/>
<path d="M127.1 114.9l.3 .2-.1 .2-.3-.2z" fill="#ececec"/>
<path d="M127.1 114.9l.3 .2-.1 .2-.3-.2z" fill="none" stroke="#ececec" stroke-width=".21"/>
<path d="M128.2 128.9l.3 .2-.1 .2-.3-.2z" fill="#ececec"/>
<path d="M128.2 128.9l.3 .2-.1 .2-.3-.2z" fill="none" stroke="#ececec" stroke-width=".21"/>
<path d="M129.3 120.7l.3 .2-.1 .1-.3-.1z" fill="#ececec"/>
<path d="M129.3 120.7l.3 .2-.1 .1-.3-.1z" fill="none" stroke="#ececec" stroke-width=".21"/>
<path d="M132.1 128l.3 .2-.1 .2-.3-.2z" fill="#ececec"/>
<path d="M132.1 128l.3 .2-.1 .2-.3-.2z" fill="none" stroke="#ececec" stroke-width=".21"/>
<path d="M132.7 116l.3 .2-.1 .2-.3-.2z" fill="#ececec"/>
<path d="M132.7 116l.3 .2-.1 .2-.3-.2z" fill="none" stroke="#ececec" stroke-width=".21"/>
<path d="M137.3 108.4l.3 .2-.1 .2-.3-.2z" fill="#ececec"/>
<path d="M137.3 108.4l.3 .2-.1 .2-.3-.2z" fill="none" stroke="#ececec" stroke-width=".21"/>
<path d="M138.5 118.7l.3 .2-.1 .2-.4-.2z" fill="#ececec"/>
<path d="M138.5 118.7l.3 .2-.1 .2-.4-.2z" fill="none" stroke="#ececec" stroke-width=".21"/>
<path d="M140.4 116.3l.3 .2-.1 .1-.3-.1z" fill="#ececec"/>
<path d="M140.4 116.3l.3 .2-.1 .1-.3-.1z" fill="none" stroke="#ececec" stroke-width=".21"/>
<path d="M133 112.3l.3 .2-.1 .2-.3-.2z" fill="#ececec"/>
<path d="M133 112.3l.3 .2-.1 .2-.3-.2z" fill="none" stroke="#ececec" stroke-width=".21"/>
<path d="M138.2 109.4l.3 .2-.1 .2-.3-.2z" fill="#ececec"/>
<path d="M138.2 109.4l.3 .2-.1 .2-.3-.2z" fill="none" stroke="#ececec" stroke-width=".21"/>
<path d="M122.5 142.3l.4 .2-.2 .2-.3-.2z" fill="#ececec"/>
<path d="M122.5 142.3l.4 .2-.2 .2-.3-.2z" fill="none" stroke="#ececec" stroke-width=".21"/>
<path d="M113.1 148l.4 .2-.2 .2-.3-.2z" fill="#ececec"/>
<path d="M113.1 148l.4 .2-.2 .2-.3-.2z" fill="none" stroke="#ececec" stroke-width=".21"/>
<path d="M122.2 133.9l.3 .2-.1 .2-.3-.2z" fill="#ececec"/>
<path d="M122.2 133.9l.3 .2-.1 .2-.3-.2z" fill="none" stroke="#ececec" stroke-width=".21"/>
<path d="M112.9 134.9l.3 .2-.1 .2-.3-.2z" fill="#ececec"/>
<path d="M112.9 134.9l.3 .2-.1 .2-.3-.2z" fill="none" stroke="#ececec" stroke-width=".21"/>
<path d="M117.3 133l.3 .1-.1 .2-.3-.2z" fill="#ececec"/>
<path d="M117.3 133l.3 .1-.1 .2-.3-.2z" fill="none" stroke="#ececec" stroke-width=".21"/>
<path d="M137.9 110.8l.3 .2-.1 .1-.3-.1z" fill="#ececec"/>
<path d="M137.9 110.8l.3 .2-.1 .1-.3-.1z" fill="none" stroke="#ececec" stroke-width=".21"/>
<path d="M143.4 109.1l.3 .2-.1 .2-.3-.2z" fill="#ececec"/>
<path d="M143.4 109.1l.3 .2-.1 .2-.3-.2z" fill="none" stroke="#ececec" stroke-width=".21"/>
<path d="M152.2 108.7l.3 .2-.1 .2-.3-.2z" fill="#ececec"/>
<path d="M152.2 108.7l.3 .2-.1 .2-.3-.2z" fill="none" stroke="#ececec" stroke-width=".21"/>
<path d="M147.9 109.7l.4 .2-.2 .1-.3-.1z" fill="#ececec"/>
<path d="M147.9 109.7l.4 .2-.2 .1-.3-.1z" fill="none" stroke="#ececec" stroke-width=".21"/>
<path d="M151.6 109.3l.3 .2-.1 .2-.3-.2z" fill="#ececec"/>
<path d="M151.6 109.3l.3 .2-.1 .2-.3-.2z" fill="none" stroke="#ececec" stroke-width=".21"/>
<path d="M142.7 109.6l.3 .2-.1 .2-.3-.2z" fill="#ececec"/>
<path d="M142.7 109.6l.3 .2-.1 .2-.3-.2z" fill="none" stroke="#ececec" stroke-width=".21"/>
<path d="M136 119l.3 .2-.1 .2-.3-.2z" fill="#ececec"/>
<path d="M136 119l.3 .2-.1 .2-.3-.2z" fill="none" stroke="#ececec" stroke-width=".21"/>
<path d="M142.9 129.3l.4 .2-.2 .2-.3-.2z" fill="#ececec"/>
<path d="M142.9 129.3l.4 .2-.2 .2-.3-.2z" fill="none" stroke="#ececec" stroke-width=".21"/>
<path d="M140.3 123.3l.3 .2-.1 .2-.3-.2z" fill="#ececec"/>
<path d="M140.3 123.3l.3 .2-.1 .2-.3-.2z" fill="none" stroke="#ececec" stroke-width=".21"/>
<path d="M144 120.2l.4 .2-.2 .1-.3-.1z" fill="#ececec"/>
<path d="M144 120.2l.4 .2-.2 .1-.3-.1z" fill="none" stroke="#ececec" stroke-width=".21"/>
<path d="M143.3 117.6l.3 .2-.1 .2-.3-.2z" fill="#ececec"/>
<path d="M143.3 117.6l.3 .2-.1 .2-.3-.2z" fill="none" stroke="#ececec" stroke-width=".21"/>
<path d="M143.8 124.7l.3 .1-.1 .2-.3-.2z" fill="#ececec"/>
<path d="M143.8 124.7l.3 .1-.1 .2-.3-.2z" fill="none" stroke="#ececec" stroke-width=".21"/>
<path d="M142 127l.3 .2-.1 .2-.3-.2z" fill="#ececec"/>
<path d="M142 127l.3 .2-.1 .2-.3-.2z" fill="none" stroke="#ececec" stroke-width=".21"/>
<path d="M141.6 130.1l.3 .2-.1 .1-.3-.1z" fill="#ececec"/>
<path d="M141.6 130.1l.3 .2-.1 .1-.3-.1z" fill="none" stroke="#ececec" stroke-width=".21"/>
<path d="M127.3 108.7l.3 .1-.1 .2-.3-.2z" fill="#ececec"/>
<path d="M127.3 108.7l.3 .1-.1 .2-.3-.2z" fill="none" stroke="#ececec" stroke-width=".21"/>
<path d="M126.6 110.9l.3 .2-.1 .2-.3-.2z" fill="#ececec"/>
<path d="M126.6 110.9l.3 .2-.1 .2-.3-.2z" fill="none" stroke="#ececec" stroke-width=".21"/>
<path d="M123 98.4l.4 .2-.2 .2-.3-.2z" fill="#ececec"/>
<path d="M123 98.4l.4 .2-.2 .2-.3-.2z" fill="none" stroke="#ececec" stroke-width=".21"/>
<path d="M118.6 108.9l.4 .2-.2 .2-.3-.2z" fill="#ececec"/>
<path d="M118.6 108.9l.4 .2-.2 .2-.3-.2z" fill="none" stroke="#ececec" stroke-width=".21"/>
<path d="M145.2 118.6l.3 .2-.1 .2-.3-.2z" fill="#ececec"/>
<path d="M145.2 118.6l.3 .2-.1 .2-.3-.2z" fill="none" stroke="#ececec" stroke-width=".21"/>
<path d="M148.1 113.6l.3 .1-.1 .2-.3-.2z" fill="#ececec"/>
<path d="M148.1 113.6l.3 .1-.1 .2-.3-.2z" fill="none" stroke="#ececec" stroke-width=".21"/>
<path d="M144.1 113.6l.3 .1-.1 .2-.3-.2z" fill="#ececec"/>
<path d="M144.1 113.6l.3 .1-.1 .2-.3-.2z" fill="none" stroke="#ececec" stroke-width=".21"/>
<path d="M146 117.4l.3 .2-.1 .1-.3-.1z" fill="#ececec"/>
<path d="M146 117.4l.3 .2-.1 .1-.3-.1z" fill="none" stroke="#ececec" stroke-width=".21"/>
<path d="M147.6 118.9l.3 .2-.1 .2-.3-.2z" fill="#ececec"/>
<path d="M147.6 118.9l.3 .2-.1 .2-.3-.2z" fill="none" stroke="#ececec" stroke-width=".21"/>
<path d="M144.2 121.4l.3 .2-.1 .2-.3-.2z" fill="#ececec"/>
<path d="M144.2 121.4l.3 .2-.1 .2-.3-.2z" fill="none" stroke="#ececec" stroke-width=".21"/>
<path d="M144.9 120.9l.3 .2-.1 .2-.3-.2z" fill="#ececec"/>
<path d="M144.9 120.9l.3 .2-.1 .2-.3-.2z" fill="none" stroke="#ececec" stroke-width=".21"/>
<path d="M145 122l.3 .2-.1 .2-.3-.2z" fill="#ececec"/>
<path d="M145 122l.3 .2-.1 .2-.3-.2z" fill="none" stroke="#ececec" stroke-width=".21"/>
<path d="M147.9 110.5l.4 .2-.2 .2-.3-.2z" fill="#ececec"/>
<path d="M147.9 110.5l.4 .2-.2 .2-.3-.2z" fill="none" stroke="#ececec" stroke-width=".21"/>
<path d="M151.2 119l.3 .2-.1 .2-.4-.2z" fill="#ececec"/>
<path d="M151.2 119l.3 .2-.1 .2-.4-.2z" fill="none" stroke="#ececec" stroke-width=".21"/>
<path d="M154.1 121l.3 .2-.1 .2-.3-.2z" fill="#ececec"/>
<path d="M154.1 121l.3 .2-.1 .2-.3-.2z" fill="none" stroke="#ececec" stroke-width=".21"/>
<path d="M151.2 117.9l.3 .2-.1 .2-.4-.2z" fill="#ececec"/>
<path d="M151.2 117.9l.3 .2-.1 .2-.4-.2z" fill="none" stroke="#ececec" stroke-width=".21"/>
<path d="M151.2 115.4l.3 .2-.1 .2-.4-.2z" fill="#ececec"/>
<path d="M151.2 115.4l.3 .2-.1 .2-.4-.2z" fill="none" stroke="#ececec" stroke-width=".21"/>
<path d="M152.4 114.5l.3 .2-.1 .2-.3-.2z" fill="#ececec"/>
<path d="M152.4 114.5l.3 .2-.1 .2-.3-.2z" fill="none" stroke="#ececec" stroke-width=".21"/>
<path d="M154.3 113l.3 .2-.1 .1-.3-.1z" fill="#ececec"/>
<path d="M154.3 113l.3 .2-.1 .1-.3-.1z" fill="none" stroke="#ececec" stroke-width=".21"/>
<path d="M157.5 110.6l.3 .2-.1 .2-.3-.2z" fill="#ececec"/>
<path d="M157.5 110.6l.3 .2-.1 .2-.3-.2z" fill="none" stroke="#ececec" stroke-width=".21"/>
<path d="M160.2 111.5l.3 .2-.1 .2-.3-.2z" fill="#ececec"/>
<path d="M160.2 111.5l.3 .2-.1 .2-.3-.2z" fill="none" stroke="#ececec" stroke-width=".21"/>
<path d="M160.4 110.2l.3 .2-.1 .2-.3-.2z" fill="#ececec"/>
<path d="M160.4 110.2l.3 .2-.1 .2-.3-.2z" fill="none" stroke="#ececec" stroke-width=".21"/>
<path d="M170 126.8l.3 .2-.1 .1-.4-.1z" fill="#ececec"/>
<path d="M170 126.8l.3 .2-.1 .1-.4-.1z" fill="none" stroke="#ececec" stroke-width=".21"/>
<path d="M169.6 120.8l.3 .2-.1 .2-.3-.2z" fill="#ececec"/>
<path d="M169.6 120.8l.3 .2-.1 .2-.3-.2z" fill="none" stroke="#ececec" stroke-width=".21"/>
<path d="M165 128.1l.4 .2-.2 .2-.3-.2z" fill="#ececec"/>
<path d="M165 128.1l.4 .2-.2 .2-.3-.2z" fill="none" stroke="#ececec" stroke-width=".21"/>
<path d="M169.3 131.1l.3 .2-.1 .2-.3-.2z" fill="#ececec"/>
<path d="M169.3 131.1l.3 .2-.1 .2-.3-.2z" fill="none" stroke="#ececec" stroke-width=".21"/>
<path d="M164.7 121.4l.3 .2-.1 .2-.3-.2z" fill="#ececec"/>
<path d="M164.7 121.4l.3 .2-.1 .2-.3-.2z" fill="none" stroke="#ececec" stroke-width=".21"/>
<path d="M168.2 129.1l.3 .2-.1 .2-.3-.2z" fill="#ececec"/>
<path d="M168.2 129.1l.3 .2-.1 .2-.3-.2z" fill="none" stroke="#ececec" stroke-width=".21"/>
<path d="M170 109.9l.3 .2-.1 .2-.3-.2z" fill="#ececec"/>
<path d="M170 109.9l.3 .2-.1 .2-.3-.2z" fill="none" stroke="#ececec" stroke-width=".21"/>
<path d="M169.1 111.4l.3 .1-.1 .2-.3-.2z" fill="#ececec"/>
<path d="M169.1 111.4l.3 .1-.1 .2-.3-.2z" fill="none" stroke="#ececec" stroke-width=".21"/>
<path d="M168.6 112l.3 .2-.1 .2-.3-.2z" fill="#ececec"/>
<path d="M168.6 112l.3 .2-.1 .2-.3-.2z" fill="none" stroke="#ececec" stroke-width=".21"/>
<path d="M168.8 117.3l.3 .2-.1 .2-.3-.2z" fill="#ececec"/>
<path d="M168.8 117.3l.3 .2-.1 .2-.3-.2z" fill="none" stroke="#ececec" stroke-width=".21"/>
<path d="M169.1 101.7l.3 .2-.1 .2-.3-.2z" fill="#ececec"/>
<path d="M169.1 101.7l.3 .2-.1 .2-.3-.2z" fill="none" stroke="#ececec" stroke-width=".21"/>
<g fill="#000">
<path d="M67.9 41.6l.3 .2-.1 .2-.3-.2zM68.2 58.8l.3 .2-.1 .2-.3-.2zM68.5 48.2l.3 .2-.1 .2-.3-.2zM69.4 51.8l.3 .1-.1 .2-.3-.2zM74.4 51.1l.4 .2-.1 .2-.4-.2zM76.1 41.8l.4 .2-.2 .2-.3-.2zM77.2 57.7l.4 .2-.2 .2-.3-.2zM77.8 44.5l.3 .2-.1 .1-.3-.1zM78.4 41.2l.3 .2-.1 .1-.3-.1zM85.4 46.5l.3 .2-.1 .2-.3-.2zM85.6 55.6l.3 .2-.1 .2-.3-.2zM86.9 44.9l.3 .2-.1 .2-.3-.2z"/>
<path d="M90.6 56.4l.3 .2-.1 .2-.3-.2zM92.1 41.2l.3 .2-.1 .1-.4-.1zM94 44.8l.3 .2-.1 .2-.3-.2zM95.9 46.4l.3 .2-.1 .2-.3-.2zM101.4 45.1l.3 .2-.1 .1-.3-.1zM105.8 41.8l.3 .2-.1 .2-.3-.2zM107.6 47.4l.3 .2-.1 .2-.3-.2zM108.2 43.8l.3 .2-.1 .2-.3-.2zM112 49.1l.4 .2-.2 .2-.3-.2zM113.2 52.9l.3 .2-.1 .2-.3-.2zM115.4 51.1l.3 .2-.1 .2-.3-.2zM116.3 44.1l.3 .2-.1 .2-.3-.2z"/>
<path d="M116.7 47.7l.3 .2-.1 .2-.3-.2zM116.9 50.4l.4 .2-.1 .2-.4-.2zM117.5 41.2l.4 .2-.2 .1-.3-.1zM122.5 50.1l.3 .1-.1 .2-.4-.2zM122.6 45.1l.3 .2-.1 .1-.3-.1zM122.8 57.9l.3 .1-.1 .2-.3-.2zM127.6 41.7l.3 .2-.1 .2-.3-.2zM127.8 46.6l.3 .2-.1 .2-.3-.2zM128.1 50.1l.3 .1-.1 .2-.3-.2zM128.9 52.6l.3 .2-.1 .2-.3-.2zM129 57.1l.3 .2-.1 .2-.3-.2zM130 43.6l.3 .2-.1 .2-.3-.2z"/>
<path d="M137.1 43.9l.3 .2-.1 .2-.3-.2zM137.9 58.9l.4 .2-.1 .1-.4-.1zM138 41.8l.3 .2-.1 .2-.3-.2zM138.3 47l.3 .2-.1 .2-.3-.2zM138.5 53.7l.3 .2-.1 .2-.4-.2zM143.6 43.7l.3 .2-.1 .2-.3-.2zM143.7 44.9l.3 .2-.1 .2-.3-.2zM144.5 59.5l.3 .1-.1 .2-.3-.2zM144.7 41.1l.3 .2-.1 .2-.3-.2zM149.3 49.9l.3 .2-.1 .2-.3-.2zM149.4 41.9l.3 .2-.1 .2-.3-.2zM150.7 43.9l.3 .2-.1 .2-.3-.2z"/>
<path d="M153 54.1l.3 .2-.1 .2-.3-.2zM155 59.5l.3 .1-.1 .2-.3-.2zM158.2 44.1l.3 .1-.1 .2-.3-.2zM159.3 41.1l.3 .2-.1 .2-.3-.2zM159.3 54.4l.3 .2-.1 .2-.3-.2zM159.6 46.3l.3 .1-.1 .2-.3-.2zM164.9 45.6l.3 .2-.1 .2-.3-.2zM165 59.3l.4 .2-.2 .2-.3-.2zM165.2 51.3l.3 .2-.1 .2-.3-.2zM165.9 41.9l.3 .2-.1 .2-.3-.2zM167.7 48.8l.4 .2-.1 .2-.4-.2zM169.4 53.2l.4 .2-.2 .2-.3-.2z"/>
<path d="M171.3 58.6l.3 .2-.1 .2-.3-.2zM172.8 51.1l.3 .2-.1 .2-.3-.2zM174.7 53.4l.3 .2-.1 .1-.3-.1zM174.9 59.4l.3 .2-.1 .2-.3-.2zM175.5 49.3l.4 .2-.2 .2-.3-.2zM178 58.9l.3 .2-.1 .1-.3-.1zM178.2 42.7l.4 .2-.1 .2-.4-.2zM178.4 46.7l.3 .2-.1 .2-.3-.2zM179.1 44.5l.3 .2-.1 .1-.3-.1zM182 59.3l.3 .2-.1 .2-.3-.2zM182.1 56.3l.3 .2-.1 .2-.4-.2zM182.3 51.6l.3 .2-.1 .2-.3-.2z"/>
<path d="M186.1 54.8l.3 .2-.1 .2-.3-.2zM187.3 45.4l.3 .2-.1 .2-.3-.2zM188.3 59.3l.3 .2-.1 .2-.3-.2zM188.7 41.8l.4 .2-.1 .2-.4-.2zM188.8 51.8l.3 .1-.1 .2-.3-.2zM189.6 47.3l.3 .2-.1 .1-.3-.1zM189.6 49.3l.3 .2-.1 .2-.3-.2zM197.1 46.8l.3 .1-.1 .2-.3-.2zM197.2 55.1l.3 .2-.1 .2-.3-.2zM68.3 70.9l.3 .2-.1 .2-.3-.2zM75.2 75.7l.3 .2-.1 .2-.3-.2zM80.7 69.9l.3 .2-.1 .1-.3-.1z"/>
<path d="M80.8 61.2l.3 .2-.1 .2-.3-.2zM85.6 63.6l.3 .2-.1 .2-.3-.2zM87.7 66.8l.3 .2-.1 .2-.4-.2zM90.5 62l.3 .2-.1 .2-.3-.2zM91.3 69.1l.3 .2-.1 .2-.3-.2zM96 66.9l.3 .2-.1 .2-.4-.2zM96.3 72l.3 .2-.1 .2-.3-.2zM106.3 72.4l.3 .2-.1 .2-.3-.2zM112.1 74.9l.3 .2-.1 .1-.3-.1zM112.4 67l.3 .2-.1 .2-.3-.2zM112.5 60.9l.4 .2-.1 .2-.4-.2zM112.8 71.4l.3 .2-.1 .2-.3-.2z"/>
<path d="M115.3 65.4l.3 .2-.1 .2-.4-.2zM117.5 72.4l.3 .2-.1 .2-.4-.2zM121.6 64.5l.3 .1-.1 .2-.3-.2zM121.9 71.5l.3 .2-.1 .2-.3-.2zM127.1 64.5l.3 .2-.1 .2-.3-.2zM127.2 75l.3 .2-.1 .2-.3-.2zM128.9 75l.3 .2-.1 .2-.3-.2zM129.9 77.9l.3 .2-.1 .2-.3-.2zM130 64.5l.3 .2-.1 .2-.3-.2zM133.2 64.5l.3 .2-.1 .2-.3-.2zM133.5 74.4l.4 .1-.2 .2-.3-.2zM134.1 79.8l.3 .2-.1 .2-.4-.2z"/>
<path d="M134.2 60.2l.3 .2-.1 .2-.3-.2zM136.8 69.1l.4 .2-.1 .2-.4-.2zM136.8 75l.4 .1-.1 .2-.4-.2zM138 69.7l.3 .2-.1 .2-.3-.2zM138.5 65l.3 .2-.1 .2-.4-.2zM138.5 76l.4 .2-.2 .1-.3-.1zM138.8 71.2l.3 .2-.1 .2-.3-.2zM138.9 72.6l.3 .2-.1 .2-.3-.2zM149.1 74.4l.3 .2-.1 .2-.3-.2zM151.5 64.7l.3 .2-.1 .2-.3-.2zM155 79.4l.3 .2-.1 .2-.3-.2zM155 69.5l.3 .2-.1 .2-.3-.2z"/>
<path d="M159.2 73.9l.3 .1-.1 .2-.3-.2zM159.8 61.9l.3 .2-.1 .2-.3-.2zM163.3 69.5l.3 .1-.1 .2-.3-.2zM163.9 64.7l.3 .2-.1 .2-.4-.2zM165.1 72.2l.3 .2-.1 .2-.3-.2zM165.5 74.3l.3 .2-.1 .2-.3-.2zM165.7 61l.3 .2-.1 .2-.3-.2zM166.1 62.5l.3 .2-.1 .2-.4-.2zM166.1 78.8l.3 .2-.1 .1-.4-.1zM166.4 71.8l.3 .2-.1 .2-.3-.2zM166.8 76.6l.3 .2-.1 .1-.3-.1zM167.2 68.3l.3 .2-.1 .1-.4-.1z"/>
<path d="M167.2 65.5l.4 .2-.2 .1-.3-.1zM167.2 66.4l.4 .2-.2 .2-.3-.2zM168.9 65.8l.3 .2-.1 .2-.4-.2zM169.3 77.3l.3 .2-.1 .2-.3-.2zM169.8 68.4l.3 .2-.1 .2-.3-.2zM171.1 62.2l.3 .2-.1 .1-.4-.1zM171.1 68.2l.3 .2-.1 .2-.3-.2zM172.2 77.1l.4 .2-.2 .1-.3-.1zM173.5 69.3l.3 .2-.1 .2-.3-.2zM173.9 78.2l.3 .2-.1 .1-.3-.1zM173.9 73.3l.3 .1-.1 .2-.3-.2zM174.4 63.9l.3 .2-.1 .2-.4-.2z"/>
<path d="M174.4 62.8l.4 .2-.2 .2-.3-.2zM175.4 64l.3 .2-.1 .2-.3-.2zM175.4 68.2l.3 .2-.1 .2-.3-.2zM175.4 71.1l.3 .1-.1 .2-.3-.2zM176.8 62.8l.3 .1-.1 .2-.3-.2zM177.4 74.2l.3 .2-.1 .2-.3-.2zM177.8 60.6l.3 .1-.1 .2-.3-.2zM178.1 78.6l.3 .2-.1 .2-.3-.2zM178.6 65.8l.3 .2-.1 .2-.3-.2zM180.2 71.1l.3 .2-.1 .2-.3-.2zM181.7 75.2l.3 .2-.1 .2-.3-.2zM181.8 64.2l.3 .2-.1 .2-.3-.2z"/>
<path d="M183.1 74.7l.3 .2-.1 .2-.3-.2zM183.3 61.5l.3 .2-.1 .2-.3-.2zM183.8 66.2l.3 .2-.1 .2-.4-.2zM184.3 77.7l.3 .2-.1 .1-.4-.1zM184.9 76.1l.4 .1-.2 .2-.3-.2zM185.2 72.1l.3 .2-.1 .2-.3-.2zM185.9 66.5l.3 .2-.1 .2-.3-.2zM187.8 65.8l.3 .2-.1 .2-.3-.2zM187.8 71.1l.3 .1-.1 .2-.3-.2zM187.8 75.4l.3 .2-.1 .2-.3-.2zM188.2 60.8l.4 .2-.2 .2-.3-.2zM188.4 68.3l.3 .2-.1 .1-.3-.1z"/>
<path d="M189.8 70.3l.3 .2-.1 .2-.3-.2zM189.8 75.4l.4 .2-.1 .2-.4-.2zM192.1 67l.3 .2-.1 .2-.3-.2zM193.7 69.8l.3 .2-.1 .2-.4-.2zM196.6 69.8l.3 .2-.1 .2-.3-.2zM197.1 62.1l.3 .2-.1 .2-.3-.2zM197.5 74.4l.3 .1-.1 .2-.3-.2zM73 81.4l.3 .2-.1 .2-.3-.2zM75.3 96.7l.3 .2-.1 .2-.3-.2zM79.4 97.6l.4 .2-.2 .2-.3-.2zM79.5 85.7l.3 .2-.1 .2-.3-.2zM81.6 88.1l.3 .2-.1 .2-.4-.2z"/>
<path d="M83.4 98.5l.3 .2-.1 .2-.3-.2zM84.9 88.3l.3 .2-.1 .2-.3-.2zM85.5 92.9l.3 .2-.1 .2-.4-.2zM86 86.6l.3 .1-.1 .2-.3-.2zM86.8 90.9l.3 .2-.1 .1-.3-.1zM87.1 83.3l.3 .1-.1 .2-.3-.2zM89 99.7l.3 .2-.1 .2-.3-.2zM93.2 90l.3 .2-.1 .2-.4-.2zM93.8 86.8l.3 .2-.1 .2-.3-.2zM97.1 96.2l.3 .2-.1 .2-.4-.2zM98.3 86.2l.3 .2-.1 .2-.3-.2zM98.7 92.4l.3 .2-.1 .2-.3-.2z"/>
<path d="M99.7 90l.3 .2-.1 .2-.3-.2zM100.8 96.2l.3 .2-.1 .2-.3-.2zM101.6 83.7l.3 .2-.1 .2-.3-.2zM104.8 96.5l.3 .2-.1 .2-.4-.2zM107.5 87.7l.3 .1-.1 .2-.3-.2zM108.7 86.4l.3 .2-.1 .2-.4-.2zM109.2 92.6l.3 .2-.1 .2-.3-.2zM109.6 91.2l.3 .2-.1 .2-.3-.2zM109.6 94.3l.3 .1-.1 .2-.3-.2zM109.8 99.3l.4 .2-.2 .2-.3-.2zM110.4 93.2l.3 .1-.1 .2-.3-.2zM110.7 90.1l.3 .2-.1 .2-.3-.2z"/>
<path d="M111.3 95.3l.3 .2-.1 .1-.3-.1zM111.8 88.5l.3 .2-.1 .2-.3-.2zM113.4 82.8l.3 .2-.1 .2-.3-.2zM114.6 92.1l.3 .1-.1 .2-.3-.2zM114.7 90.3l.3 .2-.1 .2-.3-.2zM115.1 96l.3 .2-.1 .2-.3-.2zM115.3 93.8l.3 .2-.1 .2-.4-.2zM116.3 91.8l.3 .2-.1 .2-.3-.2zM116.9 90.3l.3 .2-.1 .2-.3-.2zM118.4 85.6l.3 .2-.1 .2-.3-.2zM119.9 94.4l.3 .2-.1 .2-.3-.2zM121.4 96.1l.3 .2-.1 .2-.4-.2z"/>
<path d="M122 82.5l.3 .2-.1 .2-.3-.2zM123 98.4l.4 .2-.2 .2-.3-.2zM125.2 94.4l.4 .2-.1 .2-.4-.2zM125.7 85.6l.3 .2-.1 .2-.3-.2zM126.9 92.6l.3 .2-.1 .2-.4-.2zM127 84.5l.3 .2-.1 .2-.3-.2zM127.8 93.9l.3 .2-.1 .2-.3-.2zM128.9 96.4l.3 .2-.1 .2-.3-.2zM129.5 84.5l.3 .2-.1 .2-.3-.2zM129.7 86.4l.3 .2-.1 .2-.3-.2zM131.4 99.1l.3 .2-.1 .2-.3-.2zM133.4 91.2l.3 .2-.1 .2-.3-.2z"/>
<path d="M133.6 84.8l.3 .2-.1 .2-.3-.2zM133.6 94.2l.3 .2-.1 .1-.3-.1zM133.7 82.2l.3 .1-.1 .2-.3-.2zM134 89.7l.3 .2-.1 .2-.3-.2zM137.4 98.1l.4 .2-.2 .1-.3-.1zM138.1 80.9l.3 .2-.1 .2-.3-.2zM143.2 99.1l.3 .2-.1 .2-.3-.2zM143.9 96.4l.3 .2-.1 .2-.3-.2zM145.9 93.7l.3 .2-.1 .2-.3-.2zM146.5 95.2l.3 .2-.1 .2-.3-.2zM147.7 95l.3 .2-.1 .2-.3-.2zM148.4 84.8l.4 .2-.2 .2-.3-.2z"/>
<path d="M149.8 87.3l.3 .2-.1 .2-.3-.2zM149.8 91l.3 .2-.1 .2-.3-.2zM151.2 94.9l.3 .2-.1 .2-.4-.2zM151.7 97.7l.3 .2-.1 .2-.3-.2zM153 93.6l.3 .2-.1 .2-.3-.2zM155 85.3l.3 .2-.1 .2-.3-.2zM155 91.8l.4 .2-.1 .2-.4-.2zM155.4 95.1l.3 .2-.1 .2-.3-.2zM156.6 96l.3 .2-.1 .2-.3-.2zM158.3 91.7l.3 .2-.1 .2-.3-.2zM158.4 82l.3 .2-.1 .2-.4-.2zM158.4 88.9l.3 .2-.1 .2-.3-.2z"/>
<path d="M160.2 98.3l.3 .2-.1 .2-.3-.2zM161 97l.3 .2-.1 .1-.3-.1zM161.1 99.2l.4 .2-.2 .1-.3-.1zM161.2 93.4l.3 .2-.1 .2-.3-.2zM161.4 84.8l.3 .2-.1 .2-.3-.2zM162.3 91l.3 .2-.1 .2-.3-.2zM162.7 88.8l.3 .2-.1 .2-.3-.2zM163.3 88l.3 .2-.1 .2-.3-.2zM164.3 99.3l.3 .1-.1 .2-.3-.2zM164.3 94.3l.3 .1-.1 .2-.3-.2zM164.4 97.1l.3 .2-.1 .2-.3-.2zM165.4 90.7l.3 .2-.1 .2-.3-.2z"/>
<path d="M165.5 93.2l.3 .2-.1 .2-.3-.2zM165.5 80.9l.3 .2-.1 .2-.3-.2zM165.8 98.8l.3 .2-.1 .2-.3-.2zM166 97l.3 .2-.1 .1-.3-.1zM166.1 85.2l.4 .2-.2 .2-.3-.2zM166.1 87.3l.4 .2-.2 .2-.3-.2zM166.5 94.5l.3 .2-.1 .2-.3-.2zM166.8 89.5l.3 .2-.1 .2-.3-.2zM166.8 91.6l.3 .2-.1 .2-.3-.2zM168.4 82.1l.3 .2-.1 .1-.3-.1zM170 85.5l.3 .2-.1 .2-.3-.2zM170.1 95.7l.3 .2-.1 .2-.3-.2z"/>
<path d="M170.5 92.6l.3 .2-.1 .2-.4-.2zM170.5 94.4l.4 .2-.2 .2-.3-.2zM171.9 83.2l.3 .2-.1 .1-.3-.1zM172 87.4l.3 .2-.1 .2-.3-.2zM173.7 81l.3 .2-.1 .2-.3-.2zM173.8 96l.3 .1-.1 .2-.3-.2zM173.9 97.7l.3 .2-.1 .2-.3-.2zM174.3 88.8l.3 .2-.1 .2-.3-.2zM174.4 94.4l.3 .2-.1 .2-.4-.2zM174.4 84.4l.4 .2-.2 .2-.3-.2zM174.6 91.6l.3 .2-.1 .2-.3-.2zM175.6 95.6l.3 .2-.1 .2-.3-.2z"/>
<path d="M176 97.7l.3 .2-.1 .2-.3-.2zM176.6 89.3l.4 .2-.2 .2-.3-.2zM176.7 87.3l.3 .2-.1 .2-.3-.2zM177.3 93.1l.3 .2-.1 .1-.3-.1zM177.6 81.3l.3 .2-.1 .2-.3-.2zM177.7 99.5l.3 .2-.1 .2-.4-.2zM177.8 83.4l.3 .2-.1 .2-.3-.2zM177.8 82.4l.3 .2-.1 .2-.3-.2zM178.3 85.3l.3 .2-.1 .2-.3-.2zM178.9 91.1l.3 .2-.1 .2-.3-.2zM179.9 88.9l.3 .2-.1 .2-.4-.2zM180.3 91.8l.3 .2-.1 .2-.3-.2z"/>
<path d="M181 86.8l.4 .2-.2 .2-.3-.2zM181.2 94.4l.3 .2-.1 .2-.3-.2zM181.6 92.3l.3 .2-.1 .2-.3-.2zM183.2 81.4l.3 .2-.1 .2-.4-.2zM183.7 84.1l.3 .2-.1 .2-.3-.2zM184.8 80.5l.3 .2-.1 .2-.3-.2zM185.3 84.4l.3 .1-.1 .2-.3-.2zM185.9 85.8l.3 .2-.1 .2-.3-.2zM186.4 88.9l.3 .2-.1 .2-.3-.2zM186.8 82.5l.3 .2-.1 .2-.3-.2zM187.1 93.2l.4 .2-.2 .2-.3-.2zM187.7 91.8l.3 .2-.1 .2-.3-.2z"/>
<path d="M187.8 99l.3 .2-.1 .2-.3-.2zM188.2 86.7l.3 .2-.1 .2-.4-.2zM190.2 99.3l.3 .1-.1 .2-.3-.2zM190.4 81.8l.4 .2-.2 .2-.3-.2zM190.5 91.6l.3 .2-.1 .2-.3-.2zM196.2 91.5l.3 .2-.1 .1-.3-.1zM196.6 83.8l.3 .2-.1 .2-.3-.2zM95.1 101.2l.3 .2-.1 .2-.3-.2zM97.4 106.6l.3 .2-.1 .2-.3-.2zM103.5 111.3l.3 .2-.1 .2-.3-.2zM103.5 107.3l.3 .2-.1 .2-.3-.2zM104 100.5l.3 .2-.1 .2-.3-.2z"/>
<path d="M104.5 103.9l.3 .2-.1 .2-.3-.2zM105.9 114.2l.4 .1-.2 .2-.3-.2zM106.5 105.4l.3 .2-.1 .2-.3-.2zM107.6 112.8l.3 .2-.1 .2-.3-.2zM111.7 109.5l.3 .2-.1 .2-.3-.2zM114.1 100.9l.3 .1-.1 .2-.3-.2zM118.6 108.9l.4 .2-.2 .2-.3-.2zM121.2 105.3l.3 .2-.1 .2-.3-.2zM125.4 101.1l.3 .2-.1 .2-.3-.2zM126.6 110.9l.3 .2-.1 .2-.3-.2zM127.1 106.4l.3 .2-.1 .2-.3-.2zM127.1 114.9l.3 .2-.1 .2-.3-.2z"/>
<path d="M127.3 108.7l.3 .1-.1 .2-.3-.2zM132.4 107.2l.4 .2-.2 .2-.3-.2zM132.6 105.1l.3 .2-.1 .2-.3-.2zM132.6 100.4l.3 .1-.1 .2-.3-.2zM132.7 116l.3 .2-.1 .2-.3-.2zM133 112.3l.3 .2-.1 .2-.3-.2zM134.4 104.8l.3 .2-.1 .2-.3-.2zM135.2 105.5l.4 .2-.2 .2-.3-.2zM135.7 118.1l.3 .2-.1 .2-.3-.2zM135.9 106.4l.3 .2-.1 .1-.3-.1zM136 119l.3 .2-.1 .2-.3-.2zM136.5 103.7l.3 .1-.1 .2-.3-.2z"/>
<path d="M137 106.4l.3 .2-.1 .1-.3-.1zM137 112.8l.3 .2-.1 .2-.3-.2zM137.3 108.4l.3 .2-.1 .2-.3-.2zM137.5 107.3l.3 .2-.1 .2-.3-.2zM137.9 110.8l.3 .2-.1 .1-.3-.1zM138.2 109.4l.3 .2-.1 .2-.3-.2zM138.5 118.7l.3 .2-.1 .2-.4-.2zM140.4 116.3l.3 .2-.1 .1-.3-.1zM142.7 109.6l.3 .2-.1 .2-.3-.2zM143.3 117.6l.3 .2-.1 .2-.3-.2zM143.4 109.1l.3 .2-.1 .2-.3-.2zM144.1 113.6l.3 .1-.1 .2-.3-.2z"/>
<path d="M144.6 106l.3 .2-.1 .2-.3-.2zM144.6 107.5l.3 .2-.1 .1-.3-.1zM145.2 104.3l.3 .2-.1 .2-.3-.2zM145.2 118.6l.3 .2-.1 .2-.3-.2zM146 117.4l.3 .2-.1 .1-.3-.1zM146.2 107.6l.3 .1-.1 .2-.4-.2zM146.4 102.6l.3 .1-.1 .2-.3-.2zM146.9 100.5l.3 .2-.1 .2-.3-.2zM147.4 103.7l.3 .1-.1 .2-.3-.2zM147.4 101.5l.3 .1-.1 .2-.3-.2zM147.6 118.9l.3 .2-.1 .2-.3-.2zM147.8 106.1l.3 .2-.1 .2-.3-.2z"/>
<path d="M147.9 109.7l.4 .2-.2 .1-.3-.1zM147.9 110.5l.4 .2-.2 .2-.3-.2zM148.1 113.6l.3 .1-.1 .2-.3-.2zM151.2 119l.3 .2-.1 .2-.4-.2zM151.2 117.9l.3 .2-.1 .2-.4-.2zM151.2 115.4l.3 .2-.1 .2-.4-.2zM151.3 107.3l.3 .2-.1 .2-.3-.2zM151.6 109.3l.3 .2-.1 .2-.3-.2zM151.9 104.9l.3 .2-.1 .2-.3-.2zM152.2 108.7l.3 .2-.1 .2-.3-.2zM152.4 114.5l.3 .2-.1 .2-.3-.2zM153 104.9l.3 .2-.1 .2-.3-.2z"/>
<path d="M153.2 106.6l.3 .2-.1 .2-.3-.2zM154.3 113l.3 .2-.1 .1-.3-.1zM156 101.3l.3 .2-.1 .2-.3-.2zM156.2 106.6l.3 .2-.1 .2-.4-.2zM157.5 110.6l.3 .2-.1 .2-.3-.2zM157.9 101.5l.3 .1-.1 .2-.3-.2zM158.9 113.6l.3 .2-.1 .2-.4-.2zM160.2 105.9l.3 .1-.1 .2-.3-.2zM160.2 111.5l.3 .2-.1 .2-.3-.2zM160.3 107.1l.3 .2-.1 .2-.3-.2zM160.4 110.2l.3 .2-.1 .2-.3-.2zM160.6 102.8l.3 .2-.1 .2-.4-.2z"/>
<path d="M163.3 114.1l.4 .2-.1 .1-.4-.1zM164.2 108.5l.3 .2-.1 .2-.3-.2zM164.3 100.3l.3 .2-.1 .1-.3-.1zM164.4 118.8l.3 .2-.1 .2-.3-.2zM164.4 105l.4 .2-.1 .2-.4-.2zM165 108.1l.3 .2-.1 .2-.4-.2zM165.5 103.4l.4 .2-.1 .2-.4-.2zM166.6 117.4l.4 .2-.1 .1-.4-.1zM167.2 106.6l.3 .2-.1 .2-.4-.2zM168.4 107.6l.3 .2-.1 .2-.3-.2zM168.6 112l.3 .2-.1 .2-.3-.2zM168.8 117.3l.3 .2-.1 .2-.3-.2z"/>
<path d="M169.1 111.4l.3 .1-.1 .2-.3-.2zM169.1 101.7l.3 .2-.1 .2-.3-.2zM170 102.7l.3 .2-.1 .2-.4-.2zM170 118.2l.3 .2-.1 .2-.4-.2zM170 105.6l.3 .2-.1 .2-.3-.2zM170 108l.3 .2-.1 .1-.3-.1zM170 115.3l.3 .2-.1 .2-.3-.2zM170 109.9l.3 .2-.1 .2-.3-.2zM170.2 100.7l.3 .2-.1 .2-.3-.2zM170.7 118.1l.3 .2-.1 .2-.3-.2zM171.5 112.4l.3 .2-.1 .2-.3-.2zM173.8 103.5l.4 .2-.2 .2-.3-.2z"/>
<path d="M173.8 114.4l.4 .2-.2 .2-.3-.2zM174 110.5l.3 .2-.1 .2-.3-.2zM174.3 104.9l.3 .2-.1 .2-.3-.2zM174.4 109.6l.3 .2-.1 .2-.4-.2zM175.4 118.2l.3 .2-.1 .2-.3-.2zM175.5 113.6l.4 .1-.2 .2-.3-.2zM177.3 109.5l.3 .2-.1 .2-.3-.2zM177.7 104.8l.3 .1-.1 .2-.4-.2zM177.7 119.1l.3 .2-.1 .2-.4-.2zM179.2 108.3l.3 .2-.1 .2-.3-.2zM179.2 115.1l.3 .2-.1 .2-.3-.2zM179.3 110.3l.3 .1-.1 .2-.3-.2z"/>
<path d="M180.4 118.3l.4 .2-.1 .2-.4-.2zM181.4 100.4l.3 .1-.1 .2-.3-.2zM181.5 114.1l.3 .2-.1 .1-.3-.1zM183.2 118l.3 .2-.1 .1-.4-.1zM183.4 108.7l.3 .2-.1 .2-.3-.2zM183.4 101.9l.3 .2-.1 .2-.3-.2zM185.7 112.8l.3 .2-.1 .2-.3-.2zM185.9 115.3l.3 .1-.1 .2-.3-.2zM187.5 110.9l.3 .1-.1 .2-.3-.2zM187.6 115.9l.4 .2-.1 .2-.4-.2zM187.8 119l.3 .2-.1 .2-.3-.2zM188.2 104.8l.4 .2-.2 .2-.3-.2z"/>
<path d="M188.4 105.9l.3 .2-.1 .2-.3-.2zM188.4 107l.3 .1-.1 .2-.3-.2zM188.5 109.7l.3 .2-.1 .1-.3-.1zM189.1 114.7l.3 .2-.1 .2-.3-.2zM189.1 113.1l.3 .1-.1 .2-.3-.2zM190 101.8l.3 .2-.1 .2-.3-.2zM190 103.1l.3 .2-.1 .2-.3-.2zM190 105l.3 .2-.1 .2-.3-.2zM190.1 110l.3 .2-.1 .2-.3-.2zM190.4 114.9l.3 .2-.1 .2-.4-.2zM191.1 107.2l.3 .2-.1 .2-.3-.2zM192.4 116.3l.3 .2-.1 .1-.3-.1z"/>
<path d="M195.4 116.9l.3 .2-.1 .1-.4-.1zM196.7 110.9l.3 .2-.1 .2-.3-.2zM197.3 115.3l.3 .2-.1 .2-.3-.2zM197.5 101.5l.3 .2-.1 .2-.3-.2zM197.6 104.5l.3 .2-.1 .2-.4-.2zM82.2 138.3l.3 .2-.1 .2-.3-.2zM90.4 137.5l.4 .2-.1 .2-.4-.2zM103.4 121.5l.3 .2-.1 .2-.3-.2zM103.5 133.7l.3 .2-.1 .2-.3-.2zM112.9 134.9l.3 .2-.1 .2-.3-.2zM117.3 133l.3 .1-.1 .2-.3-.2zM118 134.5l.3 .2-.1 .2-.3-.2z"/>
<path d="M119.5 124.1l.3 .2-.1 .2-.3-.2zM120.5 136.8l.3 .2-.1 .2-.3-.2zM122.2 133.9l.3 .2-.1 .2-.3-.2zM122.9 126.4l.3 .2-.1 .2-.3-.2zM123 138.5l.4 .1-.2 .2-.3-.2zM123.2 128l.3 .2-.1 .2-.3-.2zM123.3 130.1l.3 .2-.1 .1-.3-.1zM125.3 137.2l.3 .2-.1 .2-.3-.2zM125.5 131.6l.3 .2-.1 .2-.3-.2zM126.9 136.3l.3 .1-.1 .2-.4-.2zM127 139.6l.3 .1-.1 .2-.3-.2zM128.2 128.9l.3 .2-.1 .2-.3-.2z"/>
<path d="M128.7 134.6l.3 .1-.1 .2-.3-.2zM129.3 120.7l.3 .2-.1 .1-.3-.1zM131.8 121.8l.3 .2-.1 .2-.3-.2zM132.1 128l.3 .2-.1 .2-.3-.2zM133.7 122.1l.3 .2-.1 .2-.3-.2zM134.5 136.9l.3 .2-.1 .2-.3-.2zM134.7 132.2l.3 .2-.1 .2-.3-.2zM135.3 121.9l.3 .1-.1 .2-.3-.2zM136.2 139.2l.3 .2-.1 .2-.3-.2zM137 135.7l.3 .1-.1 .2-.3-.2zM138.5 132.3l.3 .2-.1 .1-.4-.1zM138.5 138.7l.4 .2-.2 .2-.3-.2z"/>
<path d="M139.4 132.7l.3 .2-.1 .2-.3-.2zM140.2 132.8l.3 .2-.1 .2-.3-.2zM140.3 123.3l.3 .2-.1 .2-.3-.2zM141.6 130.1l.3 .2-.1 .1-.3-.1zM141.8 137.4l.4 .1-.2 .2-.3-.2zM142 127l.3 .2-.1 .2-.3-.2zM142.6 139l.3 .1-.1 .2-.3-.2zM142.9 129.3l.4 .2-.2 .2-.3-.2zM143.1 136.1l.3 .2-.1 .2-.3-.2zM143.8 124.7l.3 .1-.1 .2-.3-.2zM144 120.2l.4 .2-.2 .1-.3-.1zM144.2 121.4l.3 .2-.1 .2-.3-.2z"/>
<path d="M144.5 134.8l.3 .2-.1 .2-.3-.2zM144.6 137.7l.3 .2-.1 .2-.4-.2zM144.8 134.1l.3 .2-.1 .2-.3-.2zM144.9 120.9l.3 .2-.1 .2-.3-.2zM145 122l.3 .2-.1 .2-.3-.2zM145.6 131.8l.3 .2-.1 .2-.3-.2zM146.3 138.9l.3 .2-.1 .2-.3-.2zM146.4 135.7l.3 .2-.1 .2-.3-.2zM147.4 129.5l.3 .2-.1 .2-.3-.2zM147.9 133.4l.3 .2-.1 .1-.4-.1zM148.5 137.2l.3 .2-.1 .2-.3-.2zM148.9 138.9l.3 .2-.1 .2-.3-.2z"/>
<path d="M151.2 127.4l.3 .2-.1 .1-.4-.1zM151.2 124.2l.3 .2-.1 .2-.4-.2zM151.2 131.7l.3 .2-.1 .2-.4-.2zM151.8 135.8l.3 .2-.1 .2-.3-.2zM152.2 133l.3 .2-.1 .2-.3-.2zM152.4 122.1l.3 .2-.1 .2-.3-.2zM152.8 129.3l.4 .2-.1 .2-.4-.2zM154.1 121l.3 .2-.1 .2-.3-.2zM154.3 132.4l.3 .1-.1 .2-.3-.2zM154.7 135.8l.3 .2-.1 .2-.3-.2zM156.5 138.7l.3 .2-.1 .2-.3-.2zM157.1 136.1l.3 .2-.1 .2-.3-.2z"/>
<path d="M157.1 133.5l.3 .1-.1 .2-.3-.2zM157.5 126.6l.3 .2-.1 .2-.3-.2zM159.1 134.9l.3 .2-.1 .2-.3-.2zM160.4 120.1l.3 .2-.1 .2-.3-.2zM160.5 131.5l.3 .2-.1 .2-.3-.2zM163.4 136.8l.3 .2-.1 .2-.3-.2zM164.4 132.8l.3 .2-.1 .2-.3-.2zM164.4 131.4l.4 .2-.1 .2-.4-.2zM164.7 121.4l.3 .2-.1 .2-.3-.2zM165 128.1l.4 .2-.2 .2-.3-.2zM165.6 139.6l.3 .2-.1 .2-.3-.2zM165.9 122.2l.3 .2-.1 .2-.3-.2z"/>
<path d="M166 133.5l.3 .2-.1 .2-.3-.2zM166.6 123.5l.4 .2-.1 .1-.4-.1zM166.7 126.4l.3 .2-.1 .2-.3-.2zM167.8 138.2l.3 .2-.1 .2-.3-.2zM168.2 129.1l.3 .2-.1 .2-.3-.2zM169.3 131.1l.3 .2-.1 .2-.3-.2zM169.6 120.8l.3 .2-.1 .2-.3-.2zM169.9 135.2l.3 .2-.1 .2-.3-.2zM170 126.8l.3 .2-.1 .1-.4-.1zM170 128.6l.3 .2-.1 .2-.3-.2zM170.3 122.9l.3 .2-.1 .2-.3-.2zM170.3 132.9l.3 .2-.1 .1-.3-.1z"/>
<path d="M170.5 120.5l.3 .2-.1 .2-.4-.2zM172.4 136.9l.3 .2-.1 .2-.3-.2zM174.2 122.6l.3 .2-.1 .2-.3-.2zM174.6 130.5l.3 .2-.1 .2-.3-.2zM175.4 128.1l.3 .2-.1 .2-.3-.2zM175.6 133.1l.3 .2-.1 .2-.3-.2zM176.6 136.6l.4 .2-.2 .2-.3-.2zM177.9 134.6l.3 .1-.1 .2-.3-.2zM179.8 130.7l.3 .2-.1 .1-.3-.1zM180.7 136.4l.3 .2-.1 .2-.3-.2zM181.6 126.9l.3 .2-.1 .2-.4-.2zM181.8 125.4l.3 .2-.1 .2-.3-.2z"/>
<path d="M181.9 130.1l.3 .2-.1 .1-.3-.1zM182.6 133.8l.3 .2-.1 .2-.3-.2zM182.9 120l.3 .2-.1 .2-.3-.2zM183.1 139.1l.3 .2-.1 .2-.3-.2zM183.6 133.7l.3 .2-.1 .2-.3-.2zM183.8 120.4l.3 .2-.1 .2-.4-.2zM183.9 131.1l.3 .2-.1 .2-.3-.2zM184 132.6l.3 .2-.1 .2-.3-.2zM187.3 129.5l.3 .2-.1 .2-.3-.2zM187.7 134.1l.3 .1-.1 .2-.3-.2zM187.8 124.7l.3 .2-.1 .2-.3-.2zM188 132.2l.3 .2-.1 .2-.3-.2z"/>
<path d="M188 126.9l.3 .2-.1 .2-.3-.2zM189 130.4l.3 .2-.1 .2-.3-.2zM90.2 142.9l.3 .1-.1 .2-.3-.2zM91.6 147.9l.3 .1-.1 .2-.3-.2zM97.1 141.5l.4 .2-.2 .2-.3-.2zM100.3 146.2l.3 .2-.1 .2-.3-.2zM101.9 142.3l.3 .2-.1 .2-.3-.2zM102 140.5l.4 .2-.1 .2-.4-.2zM102.6 147.9l.4 .2-.2 .2-.3-.2zM103.6 145.3l.3 .2-.1 .2-.3-.2zM105.6 140.7l.3 .2-.1 .2-.3-.2zM106.5 142.1l.3 .2-.1 .2-.3-.2z"/>
<path d="M112.1 142.3l.3 .2-.1 .2-.3-.2zM112.1 145.5l.3 .2-.1 .2-.3-.2zM113.1 148l.4 .2-.2 .2-.3-.2zM117.5 142.4l.3 .2-.1 .2-.4-.2zM122.5 142.3l.4 .2-.2 .2-.3-.2zM122.9 148.1l.3 .2-.1 .2-.3-.2zM127.4 142.3l.3 .2-.1 .2-.3-.2zM129.6 144.4l.4 .2-.1 .2-.4-.2zM132.8 141.4l.3 .2-.1 .2-.3-.2zM133.2 144.2l.3 .2-.1 .2-.3-.2zM133.8 147.9l.3 .2-.1 .2-.3-.2zM134.2 140l.3 .2-.1 .2-.3-.2z"/>
<path d="M134.2 145.3l.3 .2-.1 .2-.3-.2zM136 141.5l.3 .2-.1 .2-.3-.2zM136 145.3l.3 .2-.1 .2-.3-.2zM136.3 140.7l.3 .2-.1 .2-.4-.2zM137.1 144l.3 .1-.1 .2-.3-.2zM139 145.1l.4 .2-.1 .2-.4-.2zM141.1 140.2l.3 .2-.1 .2-.3-.2zM141.1 145.7l.3 .2-.1 .2-.3-.2zM142.6 143l.3 .2-.1 .2-.3-.2zM142.9 141.7l.3 .2-.1 .1-.4-.1zM143.3 140.7l.3 .1-.1 .2-.3-.2zM143.7 145.4l.3 .2-.1 .2-.3-.2z"/>
<path d="M144.7 143.4l.3 .2-.1 .2-.3-.2zM150.3 145.4l.3 .2-.1 .2-.3-.2zM151.2 140.7l.4 .2-.2 .2-.3-.2zM159.2 145.6l.3 .2-.1 .1-.3-.1zM171.8 140.7l.3 .2-.1 .2-.3-.2zM171.9 144.5l.3 .2-.1 .1-.3-.1zM174.3 142.9l.3 .1-.1 .2-.3-.2zM176.8 140l.3 .2-.1 .2-.3-.2zM180.5 147.9l.3 .2-.1 .2-.3-.2z"/>
</g>
</svg>
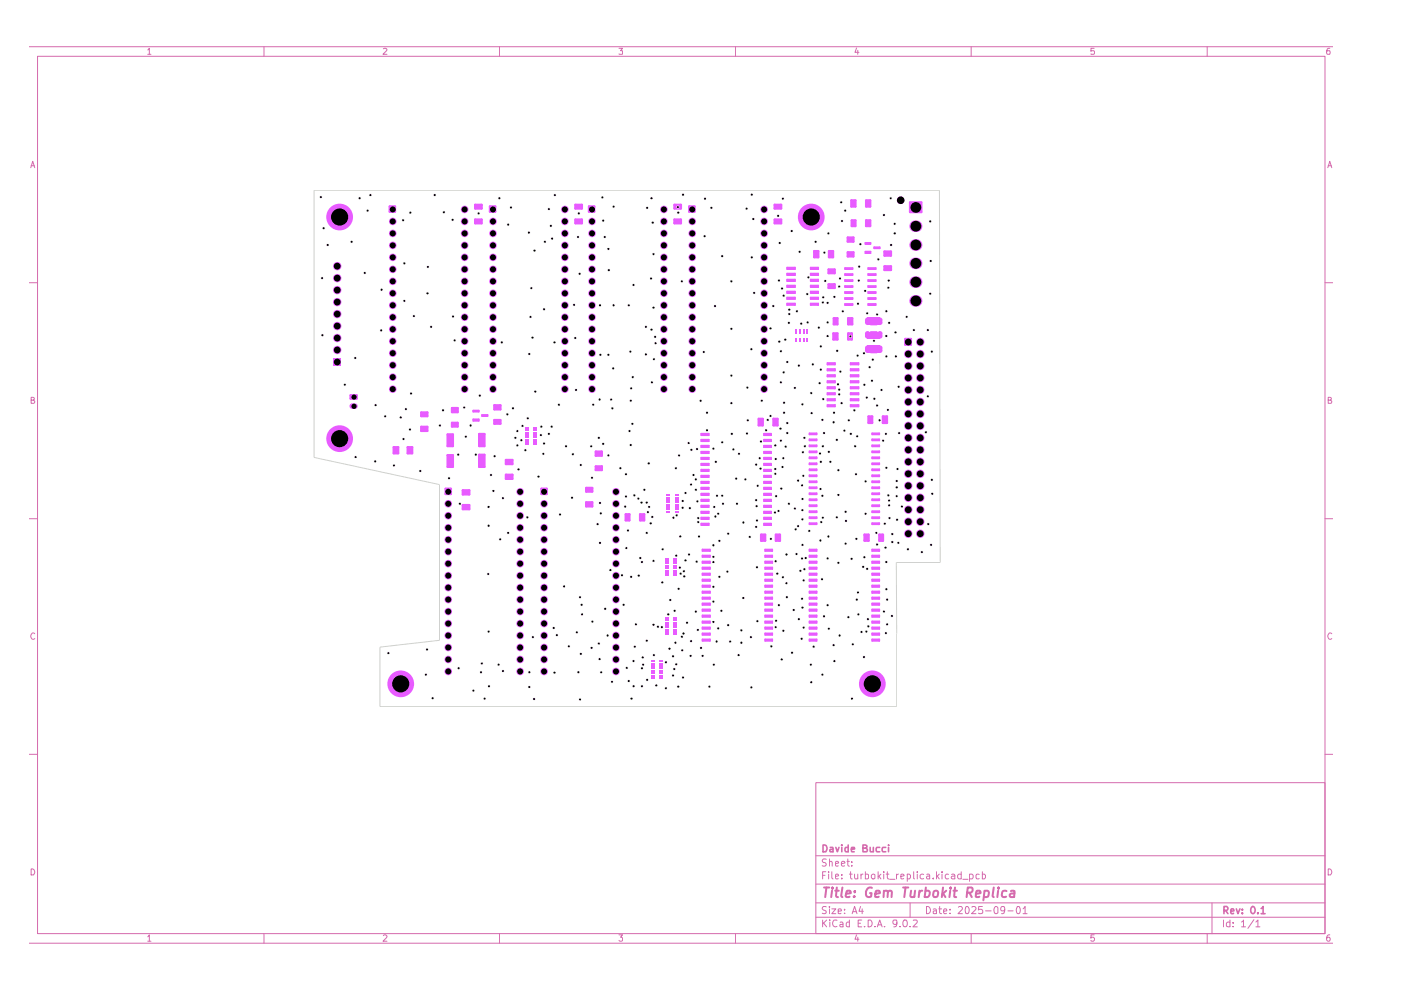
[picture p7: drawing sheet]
<svg xmlns="http://www.w3.org/2000/svg" width="297mm" height="210mm" viewBox="0 0 297 210" stroke-linecap="round" stroke-linejoin="round" font-family="sans-serif">
<g fill="none" stroke="#d56bad" stroke-width=".21">
<path d="M6.3 9.9h276.3M8 11.9h272.9v186.1h-272.9zM31.3 10.6l.4-.4v1.3M31.3 11.5h.7M56 9.9v2M81.3 10.3l.5-.1 .2 .4-.8 .9h.8M105.9 9.9v2M131.2 10.2h.8l-.4 .6h.4v.6h-.8M156 9.9v2M181.6 10.2l-.3 .9h.8M181.9 10.7v.8M205.9 9.9v2"/>
<path d="M232 10.2h-.7v.6h.6l.2 .2-.2 .5-.6-.1M255.9 9.9v2M281.9 10.2l-.5 .1-.1 .5v.6l.6 .1v-.7h-.5l-.1 .2M6.5 35.6l.4-1.4 .5 1.4M6.6 35.1h.7M281.5 35.6l.4-1.4 .5 1.4M281.6 35.1h.7M6.3 59.9h1.7M280.9 59.9h1.7M6.6 84.8h.6v-.5l-.6-.1v1.3h.6l.2-.4-.4-.3M281.6 84.8h.6v-.5l-.6-.1v1.3h.6l.2-.4-.4-.3M6.3 110h1.7"/>
<path d="M280.9 110h1.7M7.4 134.4a.57 .57 0 0 0-.8 0 .57 .57 0 0 0 0 .8l.3 .4 .5-.2M282.4 134.4a.57 .57 0 0 0-.8 0 .57 .57 0 0 0 0 .8l.3 .4 .5-.2M6.3 159.9h1.7M280.9 159.9h1.7M173 165.9h107.9v32.1h-107.9zM6.3 200h276.3M6.6 184.2a.71 .71 0 0 1 .7 .5 .71 .71 0 0 1-.2 .8h-.5zM31.3 198.6l.4-.4v1.4M31.3 199.6h.7M56 198v2M81.3 198.4l.1-.2h.4l.2 .4-.8 1h.8"/>
<path d="M105.9 198v2M131.2 198.2h.8l-.4 .5 .4 .2v.5l-.3 .2h-.3l-.2-.2M156 198v2M173 194.5h107.9M173 191.4h107.9M173 187.5h107.9M173 181.4h107.9M174.4 195.1v1.4M174.4 185.6h.5M174.6 195.7l.7 .8M175.1 184.8h-.7v1.6M175.2 192.3l-.6-.1-.3 .3 .3 .5 .5 .1v.5h-.8"/>
<path d="M175.2 182.2l-.6-.1-.3 .4 .3 .4h.3l.2 .1 .1 .4-.3 .2h-.6M175.3 195.1l-.9 .8M175.7 184.8v.2M175.7 185.3v1.1M175.9 192.2v.2M175.9 182.8l.1-.2 .4 .1v.9M175.9 182.1v1.5M175.9 192.7v1M175.9 195.1v.1M175.9 195.5v1M176.4 192.7h.8l-.8 1h.8M176.4 184.8v1.3l.2 .3"/>
<path d="M177.1 185.8l.7-.1-.2-.4-.4 .1-.1 .7 .2 .3 .4-.1M177.1 183.1l.7-.1-.2-.4-.4 .1-.1 .7 .2 .2h.4M177.5 195.2l-.6-.1a.74 .74 0 0 0-.4 .9 .74 .74 0 0 0 1 .4M177.7 193.2l.7-.1-.2-.4-.5 .1v.8h.6M178.1 195.6h.5l.1 .9M178.4 183.1l.8-.1-.1-.3-.5-.1-.2 .3 .1 .7h.6M178.5 186.2v.2M178.5 185.4v.2M178.7 195.9l-.6 .1v.2l.1 .3 .5-.1M179.1 193.6v.1M179.1 192.8v.2M179.6 182.6h.5"/>
<path d="M179.7 182.1v1.3l.4 .2M180.1 195.6l-.4-.1-.3 .3 .1 .6h.6M180.1 195.1v1.4M180.1 185.3h.6M180.3 184.8v1.3l.4 .3M180.6 183.5v.1M180.6 182.7v.2M180.7 193.7l.5-1.5 .5 1.5M180.8 193.3h.7M181.2 185.3l.1 1 .3 .1 .3-.2M181.6 198.2l-.3 .9h.8M181.9 185.3v1.1"/>
<path d="M181.9 198.7v.9M181.9 195.7h.6M182.5 192.2l-.4 1h.9M182.5 185.3v1.1M182.7 195.1h-.8v1.4h.8M182.8 192.7v1M183 185.3l-.5 .3M183.3 196.4v.1M183.5 185.4l.4-.1 .2 .2v.7l-.2 .2-.4-.1M183.5 184.8v1.6M184.1 195.1h.5a.78 .78 0 0 1 .3 .9 .78 .78 0 0 1-.8 .5zM184.7 185.6a.45 .45 0 0 1 .8-.1v.7l-.2 .2-.5-.2z"/>
<path d="M185.5 196.4v.1M186 196.5l.5-1.4 .5 1.4M186.2 196.1h.7M186.2 184.8v1.6M186.4 185.8l.4 .6M186.8 185.3l-.6 .6M187.4 184.8v.2M187.4 185.3v1.1M187.5 196.4v.1M187.9 185.3h.6M188.1 184.8v1.3l.4 .3M188.6 186.4h1.1"/>
<path d="M190.1 185.3v1.1M190.2 195.7l-.3 .3-.4-.1-.2-.2 .2-.6h.6a1.12 1.12 0 0 1-.4 1.4h-.2M190.5 185.3l-.4 .3M190.8 196.4v.1M191 185.8l.7-.1-.1-.3h-.6v.9h.6M191.6 195.2l.5-.1a.84 .84 0 0 1-.2 1.4l-.3-.1-.2-.4zM192.4 185.4l.4-.1 .2 .3v.4l-.2 .4-.4-.1M192.4 185.3v1.6M193 196.4v.1M193 191.4v3.1M193.6 195.2l.7-.1 .2 .4-1 1h1M193.7 184.8v1.5l.2 .1"/>
<path d="M194.5 184.8v.2M194.5 185.3v1.1M195.8 185.4a.52 .52 0 0 0-.7 .2l.1 .7h.6M196.4 192.2a.77 .77 0 0 1 .9 .8 .77 .77 0 0 1-.9 .7zM196.5 185.4h.5l.1 1M197.1 185.7l-.5 .1-.2 .2 .2 .4 .5-.1M197.9 192.8h.6v.9M197.9 186.2v.2M198.5 193.1l-.6 .1v.4h.6M198.5 184.8v1.6M198.7 185.8l.4 .6M199.1 192.7h.5"/>
<path d="M199.1 185.3l-.6 .6M199.2 192.2v1.3l.4 .2M199.7 184.8v.2M199.7 185.3v1.1M200.1 193.2l.6-.1-.1-.4-.4 .1-.1 .7 .1 .2 .5-.1M201.1 185.4l-.4-.1-.3 .3 .1 .6 .2 .2 .4-.1M201.4 193.6v.1M201.4 192.8v.2M201.8 185.4h.6v1M202.4 185.7l-.5 .1-.2 .2 .2 .4 .5-.1M203.2 192.4l.2-.2h.4a.45 .45 0 0 1 .2 .7l-.9 .8h.9M203.8 185.4l-.5-.1-.3 .3v.4l.3 .4 .5-.1"/>
<path d="M203.8 184.8v1.6M204.1 186.4h1.1M204.7 192.4l.3-.2a.88 .88 0 0 1 .1 1.5l-.4-.1zM205.6 185.4l.5-.1 .2 .3v.4l-.2 .4-.5-.1M205.6 185.3v1.6M205.9 198v2M206.1 192.4l.1-.2h.4l.2 .2 .1 .3-.9 1h.9M207.6 185.4l-.4-.1-.3 .3 .1 .7h.6M208.3 192.2h-.8l-.1 .8 .3-.2 .5 .1 .2 .2-.1 .5h-.9M208.3 185.4l.4-.1 .3 .3-.1 .6-.2 .2-.4-.1M208.3 184.8v1.6M209 193.1h1.1"/>
<path d="M211.1 192.2l.3 .1 .2 .2v1l-.4 .2a.81 .81 0 0 1-.6-.7 .81 .81 0 0 1 .5-.8zM213 192.9l-.1 .2-.6-.1a.6 .6 0 0 1 .1-.8l.5 .1a1.12 1.12 0 0 1-.3 1.4h-.3M213.7 193.1h1.1M215.6 192.3l.2-.1a.86 .86 0 0 1 .6 .7 .86 .86 0 0 1-.4 .8h-.2a1.1 1.1 0 0 1-.2-1.4zM216.9 192.7l.4-.5v1.5M216.9 193.7h.9M232 198.2h-.7v.7l.2-.2h.3l.3 .3v.3l-.3 .3h-.3l-.2-.2M255.9 198v2M257 191.4v6.6M259.4 195.1v1.4M260.8 195.6l-.5-.1-.3 .3 .1 .6h.7M260.8 195.1v1.4"/>
<path d="M261.5 196.4v.1M261.5 195.6v.1M263.2 195.5l.5-.4v1.4M263.2 196.5h.9M265.9 195l-1.3 1.8M266.3 195.5l.4-.4v1.4M266.3 196.5h.8M281.6 184.2a.71 .71 0 0 1 .7 .5 .71 .71 0 0 1-.2 .8h-.5zM281.9 198.2l-.5 .2a.92 .92 0 0 0 .1 1.2l.4-.1 .1-.5-.2-.3h-.3l-.2 .3"/>
</g>
<g fill="none" stroke="#d56bad" stroke-width=".34">
<path d="M174.5 179.2a.81 .81 0 0 1 .8 .4 .81 .81 0 0 1-.2 1h-.6zM176 179.7h.5l.1 .1v.8h-.6v-.5l.6-.1M177.2 179.7l.3 .9 .4-.9M178.5 179.2h.1M178.5 179.7v.9M179.8 179.2v1.4h-.5l-.1-.3v-.6h.6M183 179.8l.6-.1 .2-.1-.1-.4h-.7v1.4h.7l.2-.5-.4-.3M184.5 179.7l.1 .9 .6-.1M185.2 179.7v.9M186.5 179.7h-.6l-.1 .2 .1 .7h.6M187.8 179.7h-.6l-.2 .2 .2 .7h.6M188.4 179.2h.1"/>
<path d="M188.4 179.7v.9M180.5 180.1l.7-.1-.1-.3h-.5l-.1 .1 .1 .8h.5M259.5 193h.6a.47 .47 0 0 0 .3-.4 .47 .47 0 0 0-.3-.4h-.6v1.5M259.8 193l.5 .7M260.9 193.2l.7-.1-.1-.4-.5 .1-.1 .7 .2 .2 .4-.1M262.1 192.7l.4 1 .4-1M263.4 193.5v.2M263.4 192.8v.2M265.3 192.4l.3-.2a.82 .82 0 0 1 .5 .8 .82 .82 0 0 1-.5 .7 .93 .93 0 0 1-.3-1.3zM266.7 193.5v.2M267.4 192.6l.4-.4v1.5M267.4 193.7h.8"/>
</g>
<g fill="none" stroke="#d56bad" stroke-width=".42">
<path d="M174.7 188.2h1.1M175.2 188.2l-.2 2M176.4 188.8l-.2 1.4M176.5 188.2v.2M177.1 188.8h.7M177.4 188.2l-.2 1.7 .5 .3M178.6 188.2l-.2 1.7 .2 .3M179.4 189.5l1-.1-.1-.5h-.8l-.2 1 .2 .3 .6-.1M181.1 190l.1 .1h-.2l.1-.1v.2M181.2 188.9v.3M184.9 188.3a.77 .77 0 0 0-1 .2 1.18 1.18 0 0 0 0 1.6l.5 .1 .3-.2 .1-.6h-.4M185.5 189.5l1.1-.1-.1-.5-.6-.1-.3 .4-.1 .9h.8"/>
<path d="M187.4 189l.3-.2 .5 .1v1.3M187.4 188.8l-.1 1.4M188.3 189.2l.3-.4 .4 .1v1.3M191.5 188.2h1.1M192 188.2l-.3 2M193.2 188.8l-.1 1.3 .5 .1 .2-.2M194 188.8l-.2 1.4M194.9 188.8l-.1 1.4M195.5 188.8a.46 .46 0 0 0-.6 .5M196.2 188.9l.6-.1 .3 .2a.89 .89 0 0 1-.5 1.2l-.6-.1M196.3 188.2l-.3 2M198 189l.3-.2a.46 .46 0 0 1 .6 .5l-.1 .5a.52 .52 0 0 1-.5 .4 .52 .52 0 0 1-.5-.4z"/>
<path d="M199.9 188.2l-.2 2M199.9 189.4l.5 .8M200.6 188.8l-.8 .8M201.5 188.8l-.2 1.4M201.5 188.2v.2M202.1 188.8h.8M202.5 188.2l-.2 1.9 .4 .1M205 189.3l1-.1 .2-.4-.1-.5-.9-.1-.3 2M205.5 189.3l.5 .9M206.9 189.5l1-.1-.1-.5-.6-.1-.2 .4-.1 .9h.7M208.7 188.9a.64 .64 0 0 1 .9 .1l-.1 1-.3 .2-.5-.1M208.7 188.8l-.2 2.1"/>
<path d="M210.7 188.2l-.3 1.7 .3 .3M211.6 188.8l-.1 1.4M211.7 188.2v.2M213.4 188.9l-.5-.1-.3 .2-.1 1a.64 .64 0 0 0 .8 .1M214.3 188.9h.8l-.1 1.3M215.1 189.4h-.7l-.3 .3v.2l.2 .3 .7-.1"/>
</g>
<path d="M66.6 40.3h132.6l.1 79h-9.3l.1 30.5h-109.5v-12.6l12.6-1.4v-33.1l-26.6-5.7z" fill="none" stroke="#d0d2cd" stroke-width=".21"/>
<path d="M149 122.9h1.6v.3h-1.6z" fill="#e85bff"/>
<path d="M148.9 122.9h1.6v.3h-1.6z" fill="none" stroke="#e85bff" stroke-width=".34"/>
<path d="M149 124.2h1.6v.3h-1.6z" fill="#e85bff"/>
<path d="M148.9 124.1h1.6v.4h-1.6z" fill="none" stroke="#e85bff" stroke-width=".34"/>
<path d="M149 125.4h1.6v.4h-1.6z" fill="#e85bff"/>
<path d="M148.9 125.4h1.6v.3h-1.6z" fill="none" stroke="#e85bff" stroke-width=".34"/>
<path d="M149 126.7h1.6v.3h-1.6z" fill="#e85bff"/>
<path d="M148.9 126.7h1.6v.3h-1.6z" fill="none" stroke="#e85bff" stroke-width=".34"/>
<path d="M149 128h1.6v.3h-1.6z" fill="#e85bff"/>
<path d="M148.9 127.9h1.6v.4h-1.6z" fill="none" stroke="#e85bff" stroke-width=".34"/>
<path d="M149 129.2h1.6v.4h-1.6z" fill="#e85bff"/>
<path d="M148.9 129.2h1.6v.3h-1.6z" fill="none" stroke="#e85bff" stroke-width=".34"/>
<path d="M149 130.5h1.6v.4h-1.6z" fill="#e85bff"/>
<path d="M148.9 130.5h1.6v.3h-1.6z" fill="none" stroke="#e85bff" stroke-width=".34"/>
<path d="M149 131.8h1.6v.3h-1.6z" fill="#e85bff"/>
<path d="M148.9 131.7h1.6v.4h-1.6z" fill="none" stroke="#e85bff" stroke-width=".34"/>
<path d="M149 133.1h1.6v.3h-1.6z" fill="#e85bff"/>
<path d="M148.9 133h1.6v.3h-1.6z" fill="none" stroke="#e85bff" stroke-width=".34"/>
<path d="M149 134.3h1.6v.4h-1.6z" fill="#e85bff"/>
<path d="M148.9 134.3h1.6v.3h-1.6z" fill="none" stroke="#e85bff" stroke-width=".34"/>
<path d="M149 135.6h1.6v.3h-1.6z" fill="#e85bff"/>
<path d="M148.9 135.6h1.6v.3h-1.6z" fill="none" stroke="#e85bff" stroke-width=".34"/>
<path d="M162.3 135.6h1.5v.3h-1.5z" fill="#e85bff"/>
<path d="M162.2 135.6h1.5v.3h-1.5z" fill="none" stroke="#e85bff" stroke-width=".34"/>
<path d="M162.3 134.3h1.5v.4h-1.5z" fill="#e85bff"/>
<path d="M162.2 134.3h1.5v.3h-1.5z" fill="none" stroke="#e85bff" stroke-width=".34"/>
<path d="M162.3 133.1h1.5v.3h-1.5z" fill="#e85bff"/>
<path d="M162.2 133h1.5v.3h-1.5z" fill="none" stroke="#e85bff" stroke-width=".34"/>
<path d="M162.3 131.8h1.5v.3h-1.5z" fill="#e85bff"/>
<path d="M162.2 131.7h1.5v.4h-1.5z" fill="none" stroke="#e85bff" stroke-width=".34"/>
<path d="M162.3 130.5h1.5v.4h-1.5z" fill="#e85bff"/>
<path d="M162.2 130.5h1.5v.3h-1.5z" fill="none" stroke="#e85bff" stroke-width=".34"/>
<path d="M162.3 129.2h1.5v.4h-1.5z" fill="#e85bff"/>
<path d="M162.2 129.2h1.5v.3h-1.5z" fill="none" stroke="#e85bff" stroke-width=".34"/>
<path d="M162.3 128h1.5v.3h-1.5z" fill="#e85bff"/>
<path d="M162.2 127.9h1.5v.4h-1.5z" fill="none" stroke="#e85bff" stroke-width=".34"/>
<path d="M162.3 126.7h1.5v.3h-1.5z" fill="#e85bff"/>
<path d="M162.2 126.7h1.5v.3h-1.5z" fill="none" stroke="#e85bff" stroke-width=".34"/>
<g fill="#e85bff">
<path d="M162.3 125.4h1.5v.4h-1.5z"/>
<circle cx="115.4" cy="117" r=".8"/>
<circle cx="115.4" cy="119.5" r=".8"/>
<circle cx="115.4" cy="122" r=".8"/>
<circle cx="115.4" cy="124.6" r=".8"/>
<circle cx="115.4" cy="127.1" r=".8"/>
<circle cx="115.4" cy="129.7" r=".8"/>
<circle cx="115.4" cy="132.2" r=".8"/>
<circle cx="115.4" cy="134.7" r=".8"/>
<circle cx="115.4" cy="137.3" r=".8"/>
<circle cx="115.4" cy="139.8" r=".8"/>
<circle cx="115.4" cy="142.4" r=".8"/>
<circle cx="130.6" cy="142.4" r=".8"/>
<circle cx="130.6" cy="139.8" r=".8"/>
<circle cx="130.6" cy="137.3" r=".8"/>
<circle cx="130.6" cy="134.7" r=".8"/>
<circle cx="130.6" cy="132.2" r=".8"/>
<circle cx="130.6" cy="129.7" r=".8"/>
<circle cx="130.6" cy="127.1" r=".8"/>
<circle cx="130.6" cy="124.6" r=".8"/>
<circle cx="130.6" cy="122" r=".8"/>
<circle cx="130.6" cy="119.5" r=".8"/>
<circle cx="130.6" cy="117" r=".8"/>
<circle cx="130.6" cy="114.4" r=".8"/>
</g>
<path d="M162.2 125.4h1.5v.3h-1.5z" fill="none" stroke="#e85bff" stroke-width=".34"/>
<path d="M162.3 124.2h1.5v.3h-1.5z" fill="#e85bff"/>
<path d="M162.2 124.1h1.5v.4h-1.5z" fill="none" stroke="#e85bff" stroke-width=".34"/>
<path d="M162.3 122.9h1.5v.3h-1.5z" fill="#e85bff"/>
<path d="M162.2 122.9h1.5v.3h-1.5z" fill="none" stroke="#e85bff" stroke-width=".34"/>
<path d="M162.3 121.6h1.5v.4h-1.5z" fill="#e85bff"/>
<path d="M162.2 121.6h1.5v.3h-1.5z" fill="none" stroke="#e85bff" stroke-width=".34"/>
<path d="M162.3 120.4h1.5v.3h-1.5z" fill="#e85bff"/>
<path d="M162.2 120.3h1.5v.3h-1.5z" fill="none" stroke="#e85bff" stroke-width=".34"/>
<path d="M162.3 119.1h1.5v.3h-1.5z" fill="#e85bff"/>
<path d="M162.2 119h1.5v.4h-1.5z" fill="none" stroke="#e85bff" stroke-width=".34"/>
<path d="M162.3 117.8h1.5v.4h-1.5z" fill="#e85bff"/>
<path d="M162.2 117.8h1.5v.3h-1.5z" fill="none" stroke="#e85bff" stroke-width=".34"/>
<path d="M162.3 116.5h1.5v.4h-1.5z" fill="#e85bff"/>
<path d="M162.2 116.5h1.5v.3h-1.5z" fill="none" stroke="#e85bff" stroke-width=".34"/>
<path d="M171.7 116.5h1.5v.4h-1.5z" fill="#e85bff"/>
<path d="M171.6 116.5h1.5v.3h-1.5z" fill="none" stroke="#e85bff" stroke-width=".34"/>
<path d="M171.7 117.8h1.5v.4h-1.5z" fill="#e85bff"/>
<path d="M171.6 117.8h1.5v.3h-1.5z" fill="none" stroke="#e85bff" stroke-width=".34"/>
<path d="M171.7 119.1h1.5v.3h-1.5z" fill="#e85bff"/>
<path d="M171.6 119h1.5v.4h-1.5z" fill="none" stroke="#e85bff" stroke-width=".34"/>
<path d="M171.7 120.4h1.5v.3h-1.5z" fill="#e85bff"/>
<path d="M171.6 120.3h1.5v.3h-1.5z" fill="none" stroke="#e85bff" stroke-width=".34"/>
<path d="M171.7 121.6h1.5v.4h-1.5z" fill="#e85bff"/>
<path d="M171.6 121.6h1.5v.3h-1.5z" fill="none" stroke="#e85bff" stroke-width=".34"/>
<path d="M171.7 122.9h1.5v.3h-1.5z" fill="#e85bff"/>
<path d="M171.6 122.9h1.5v.3h-1.5z" fill="none" stroke="#e85bff" stroke-width=".34"/>
<path d="M171.7 124.2h1.5v.3h-1.5z" fill="#e85bff"/>
<path d="M171.6 124.1h1.5v.4h-1.5z" fill="none" stroke="#e85bff" stroke-width=".34"/>
<path d="M171.7 125.4h1.5v.4h-1.5z" fill="#e85bff"/>
<path d="M171.6 125.4h1.5v.3h-1.5z" fill="none" stroke="#e85bff" stroke-width=".34"/>
<path d="M171.7 126.7h1.5v.3h-1.5z" fill="#e85bff"/>
<path d="M171.6 126.7h1.5v.3h-1.5z" fill="none" stroke="#e85bff" stroke-width=".34"/>
<path d="M171.7 128h1.5v.3h-1.5z" fill="#e85bff"/>
<path d="M171.6 127.9h1.5v.4h-1.5z" fill="none" stroke="#e85bff" stroke-width=".34"/>
<path d="M171.7 129.2h1.5v.4h-1.5z" fill="#e85bff"/>
<path d="M171.6 129.2h1.5v.3h-1.5z" fill="none" stroke="#e85bff" stroke-width=".34"/>
<path d="M171.7 130.5h1.5v.4h-1.5z" fill="#e85bff"/>
<path d="M171.6 130.5h1.5v.3h-1.5z" fill="none" stroke="#e85bff" stroke-width=".34"/>
<path d="M171.7 131.8h1.5v.3h-1.5z" fill="#e85bff"/>
<path d="M171.6 131.7h1.5v.4h-1.5z" fill="none" stroke="#e85bff" stroke-width=".34"/>
<path d="M171.7 133.1h1.5v.3h-1.5z" fill="#e85bff"/>
<path d="M171.6 133h1.5v.3h-1.5z" fill="none" stroke="#e85bff" stroke-width=".34"/>
<path d="M171.7 134.3h1.5v.4h-1.5z" fill="#e85bff"/>
<path d="M171.6 134.3h1.5v.3h-1.5z" fill="none" stroke="#e85bff" stroke-width=".34"/>
<path d="M171.7 135.6h1.5v.3h-1.5z" fill="#e85bff"/>
<path d="M171.6 135.6h1.5v.3h-1.5z" fill="none" stroke="#e85bff" stroke-width=".34"/>
<path d="M185 135.6h1.5v.3h-1.5z" fill="#e85bff"/>
<path d="M184.9 135.6h1.5v.3h-1.5z" fill="none" stroke="#e85bff" stroke-width=".34"/>
<path d="M185 134.3h1.5v.4h-1.5z" fill="#e85bff"/>
<path d="M184.9 134.3h1.5v.3h-1.5z" fill="none" stroke="#e85bff" stroke-width=".34"/>
<path d="M185 133.1h1.5v.3h-1.5z" fill="#e85bff"/>
<path d="M184.9 133h1.5v.3h-1.5z" fill="none" stroke="#e85bff" stroke-width=".34"/>
<path d="M185 131.8h1.5v.3h-1.5z" fill="#e85bff"/>
<path d="M184.9 131.7h1.5v.4h-1.5z" fill="none" stroke="#e85bff" stroke-width=".34"/>
<path d="M185 130.5h1.5v.4h-1.5z" fill="#e85bff"/>
<path d="M184.9 130.5h1.5v.3h-1.5z" fill="none" stroke="#e85bff" stroke-width=".34"/>
<g fill="#e85bff">
<path d="M185 129.2h1.5v.4h-1.5z"/>
<circle cx="185" cy="145" r="2.84"/>
</g>
<path d="M184.9 129.2h1.5v.3h-1.5z" fill="none" stroke="#e85bff" stroke-width=".34"/>
<path d="M185 128h1.5v.3h-1.5z" fill="#e85bff"/>
<path d="M184.9 127.9h1.5v.4h-1.5z" fill="none" stroke="#e85bff" stroke-width=".34"/>
<path d="M185 126.7h1.5v.3h-1.5z" fill="#e85bff"/>
<path d="M184.9 126.7h1.5v.3h-1.5z" fill="none" stroke="#e85bff" stroke-width=".34"/>
<path d="M185 125.4h1.5v.4h-1.5z" fill="#e85bff"/>
<path d="M184.9 125.4h1.5v.3h-1.5z" fill="none" stroke="#e85bff" stroke-width=".34"/>
<path d="M185 124.2h1.5v.3h-1.5z" fill="#e85bff"/>
<path d="M184.9 124.1h1.5v.4h-1.5z" fill="none" stroke="#e85bff" stroke-width=".34"/>
<path d="M185 122.9h1.5v.3h-1.5z" fill="#e85bff"/>
<path d="M184.9 122.9h1.5v.3h-1.5z" fill="none" stroke="#e85bff" stroke-width=".34"/>
<path d="M185 121.6h1.5v.4h-1.5z" fill="#e85bff"/>
<path d="M184.9 121.6h1.5v.3h-1.5z" fill="none" stroke="#e85bff" stroke-width=".34"/>
<path d="M185 120.4h1.5v.3h-1.5z" fill="#e85bff"/>
<path d="M184.9 120.3h1.5v.3h-1.5z" fill="none" stroke="#e85bff" stroke-width=".34"/>
<path d="M185 119.1h1.5v.3h-1.5z" fill="#e85bff"/>
<path d="M184.9 119h1.5v.4h-1.5z" fill="none" stroke="#e85bff" stroke-width=".34"/>
<path d="M185 117.8h1.5v.4h-1.5z" fill="#e85bff"/>
<path d="M184.9 117.8h1.5v.3h-1.5z" fill="none" stroke="#e85bff" stroke-width=".34"/>
<path d="M185 116.5h1.5v.4h-1.5z" fill="#e85bff"/>
<path d="M184.9 116.5h1.5v.3h-1.5z" fill="none" stroke="#e85bff" stroke-width=".34"/>
<g fill="#e85bff">
<path d="M141 130.9h.9v.2h-.9z"/>
<path d="M141 131.4h.9v.2h-.9z"/>
<path d="M141 131.9h.9v.2h-.9z"/>
<path d="M141 132.3h.9v.3h-.9z"/>
<path d="M141 132.8h.9v.3h-.9z"/>
<path d="M141 133.3h.9v.3h-.9z"/>
<path d="M141 133.8h.9v.4h-.9z"/>
<path d="M141 134.3h.9v.4h-.9z"/>
<path d="M142.8 134.3h.8v.4h-.8z"/>
<path d="M142.8 133.8h.8v.4h-.8z"/>
<path d="M142.8 133.3h.8v.3h-.8z"/>
<path d="M142.8 132.8h.8v.3h-.8z"/>
<path d="M142.8 132.3h.8v.3h-.8z"/>
<path d="M142.8 131.9h.8v.2h-.8z"/>
<path d="M142.8 131.4h.8v.2h-.8z"/>
<path d="M142.8 130.9h.8v.2h-.8z"/>
<path d="M139.8 143.6h.9v.3h-.9z"/>
<path d="M139.8 143.1h.9v.3h-.9z"/>
<path d="M139.8 142.6h.9v.3h-.9z"/>
<path d="M139.8 142.1h.9v.3h-.9z"/>
<path d="M139.8 141.6h.9v.3h-.9z"/>
<path d="M139.8 141.1h.9v.3h-.9z"/>
<path d="M139.8 140.6h.9v.3h-.9z"/>
<path d="M139.8 140.1h.9v.3h-.9z"/>
<path d="M138 140.1h.9v.3h-.9z"/>
<path d="M138 140.6h.9v.3h-.9z"/>
<path d="M138 141.1h.9v.3h-.9z"/>
<path d="M138 141.6h.9v.3h-.9z"/>
<path d="M138 142.1h.9v.3h-.9z"/>
<path d="M138 142.6h.9v.3h-.9z"/>
<path d="M138 143.1h.9v.3h-.9z"/>
<path d="M138 143.6h.9v.3h-.9z"/>
<path d="M171.7 98.3h1.5v.2h-1.5z"/>
</g>
<path d="M171.6 98.2h1.5v.3h-1.5z" fill="none" stroke="#e85bff" stroke-width=".34"/>
<path d="M171.7 99.5h1.5v.3h-1.5z" fill="#e85bff"/>
<path d="M171.6 99.5h1.5v.2h-1.5z" fill="none" stroke="#e85bff" stroke-width=".34"/>
<path d="M171.7 100.8h1.5v.2h-1.5z" fill="#e85bff"/>
<path d="M171.6 100.8h1.5v.2h-1.5z" fill="none" stroke="#e85bff" stroke-width=".34"/>
<path d="M171.7 102.1h1.5v.2h-1.5z" fill="#e85bff"/>
<path d="M171.6 102h1.5v.3h-1.5z" fill="none" stroke="#e85bff" stroke-width=".34"/>
<path d="M171.7 103.3h1.5v.3h-1.5z" fill="#e85bff"/>
<path d="M171.6 103.3h1.5v.2h-1.5z" fill="none" stroke="#e85bff" stroke-width=".34"/>
<path d="M171.7 104.6h1.5v.3h-1.5z" fill="#e85bff"/>
<path d="M171.6 104.6h1.5v.2h-1.5z" fill="none" stroke="#e85bff" stroke-width=".34"/>
<path d="M171.7 105.9h1.5v.2h-1.5z" fill="#e85bff"/>
<path d="M171.6 105.8h1.5v.3h-1.5z" fill="none" stroke="#e85bff" stroke-width=".34"/>
<path d="M171.7 107.1h1.5v.3h-1.5z" fill="#e85bff"/>
<path d="M171.6 107.1h1.5v.3h-1.5z" fill="none" stroke="#e85bff" stroke-width=".34"/>
<path d="M171.7 108.4h1.5v.3h-1.5z" fill="#e85bff"/>
<path d="M171.6 108.4h1.5v.2h-1.5z" fill="none" stroke="#e85bff" stroke-width=".34"/>
<path d="M171.7 109.7h1.5v.2h-1.5z" fill="#e85bff"/>
<path d="M171.6 109.6h1.5v.3h-1.5z" fill="none" stroke="#e85bff" stroke-width=".34"/>
<path d="M171.7 111h1.5v.2h-1.5z" fill="#e85bff"/>
<path d="M171.6 110.9h1.5v.3h-1.5z" fill="none" stroke="#e85bff" stroke-width=".34"/>
<path d="M185 111h1.5v.2h-1.5z" fill="#e85bff"/>
<path d="M184.9 110.9h1.5v.3h-1.5z" fill="none" stroke="#e85bff" stroke-width=".34"/>
<path d="M185 109.7h1.5v.2h-1.5z" fill="#e85bff"/>
<path d="M184.9 109.6h1.5v.3h-1.5z" fill="none" stroke="#e85bff" stroke-width=".34"/>
<path d="M185 108.4h1.5v.3h-1.5z" fill="#e85bff"/>
<path d="M184.9 108.4h1.5v.2h-1.5z" fill="none" stroke="#e85bff" stroke-width=".34"/>
<path d="M186.5 113.4h.7v1.3h-.7z" fill="#e85bff"/>
<path d="M186.4 113.4h.8v1.2h-.8z" fill="none" stroke="#e85bff" stroke-width=".51"/>
<path d="M183.3 113.4h.9v1.3h-.9z" fill="#e85bff"/>
<path d="M183.3 113.4h.8v1.2h-.8z" fill="none" stroke="#e85bff" stroke-width=".51"/>
<path d="M185 107.1h1.5v.3h-1.5z" fill="#e85bff"/>
<path d="M184.9 107.1h1.5v.3h-1.5z" fill="none" stroke="#e85bff" stroke-width=".34"/>
<path d="M185 105.9h1.5v.2h-1.5z" fill="#e85bff"/>
<path d="M184.9 105.8h1.5v.3h-1.5z" fill="none" stroke="#e85bff" stroke-width=".34"/>
<path d="M185 104.6h1.5v.3h-1.5z" fill="#e85bff"/>
<path d="M184.9 104.6h1.5v.2h-1.5z" fill="none" stroke="#e85bff" stroke-width=".34"/>
<path d="M185 103.3h1.5v.3h-1.5z" fill="#e85bff"/>
<path d="M184.9 103.3h1.5v.2h-1.5z" fill="none" stroke="#e85bff" stroke-width=".34"/>
<path d="M185 102.1h1.5v.2h-1.5z" fill="#e85bff"/>
<path d="M184.9 102h1.5v.3h-1.5z" fill="none" stroke="#e85bff" stroke-width=".34"/>
<path d="M185 100.8h1.5v.2h-1.5z" fill="#e85bff"/>
<path d="M184.9 100.8h1.5v.2h-1.5z" fill="none" stroke="#e85bff" stroke-width=".34"/>
<path d="M185 99.5h1.5v.3h-1.5z" fill="#e85bff"/>
<path d="M184.9 99.5h1.5v.2h-1.5z" fill="none" stroke="#e85bff" stroke-width=".34"/>
<path d="M185 98.3h1.5v.2h-1.5z" fill="#e85bff"/>
<path d="M184.9 98.2h1.5v.3h-1.5z" fill="none" stroke="#e85bff" stroke-width=".34"/>
<path d="M185 97h1.5v.2h-1.5z" fill="#e85bff"/>
<path d="M184.9 96.9h1.5v.3h-1.5z" fill="none" stroke="#e85bff" stroke-width=".34"/>
<path d="M185 95.7h1.5v.3h-1.5z" fill="#e85bff"/>
<path d="M184.9 95.7h1.5v.2h-1.5z" fill="none" stroke="#e85bff" stroke-width=".34"/>
<path d="M146.2 43.8h1.1v1.1h-1.1z" fill="#e85bff"/>
<path d="M146.1 43.8h1.1v1.1h-1.1z" fill="none" stroke="#e85bff" stroke-width=".51"/>
<g fill="#e85bff">
<path d="M164 88.9h.9v1.3h-.9z"/>
<circle cx="146.8" cy="46.9" r=".8"/>
<circle cx="146.8" cy="49.5" r=".8"/>
<circle cx="146.8" cy="52" r=".8"/>
<circle cx="146.8" cy="54.6" r=".8"/>
<circle cx="146.8" cy="57.1" r=".8"/>
<circle cx="146.8" cy="59.6" r=".8"/>
<circle cx="146.8" cy="62.2" r=".8"/>
<circle cx="146.8" cy="64.7" r=".8"/>
<circle cx="146.8" cy="67.3" r=".8"/>
<circle cx="146.8" cy="69.8" r=".8"/>
<circle cx="146.8" cy="72.3" r=".8"/>
<circle cx="146.8" cy="74.9" r=".8"/>
<circle cx="146.8" cy="77.4" r=".8"/>
<circle cx="146.8" cy="80" r=".8"/>
<circle cx="162" cy="74.9" r=".8"/>
<circle cx="162" cy="72.3" r=".8"/>
<circle cx="162" cy="69.8" r=".8"/>
<circle cx="162" cy="67.3" r=".8"/>
<circle cx="162" cy="64.7" r=".8"/>
<circle cx="162" cy="62.2" r=".8"/>
<circle cx="162" cy="59.6" r=".8"/>
<circle cx="162" cy="57.1" r=".8"/>
<circle cx="162" cy="54.6" r=".8"/>
<circle cx="162" cy="52" r=".8"/>
<circle cx="162" cy="82.5" r=".8"/>
<circle cx="162" cy="80" r=".8"/>
<circle cx="162" cy="77.4" r=".8"/>
</g>
<path d="M164 88.8h.8v1.4h-.8z" fill="none" stroke="#e85bff" stroke-width=".51"/>
<path d="M160.9 88.9h.9v1.3h-.9z" fill="#e85bff"/>
<path d="M160.9 88.8h.8v1.4h-.8z" fill="none" stroke="#e85bff" stroke-width=".51"/>
<path d="M148.7 92h1.6v.3h-1.6z" fill="#e85bff"/>
<path d="M148.7 91.9h1.6v.4h-1.6z" fill="none" stroke="#e85bff" stroke-width=".34"/>
<path d="M148.7 93.3h1.6v.3h-1.6z" fill="#e85bff"/>
<path d="M148.7 93.2h1.6v.4h-1.6z" fill="none" stroke="#e85bff" stroke-width=".34"/>
<path d="M148.7 94.5h1.6v.4h-1.6z" fill="#e85bff"/>
<path d="M148.7 94.5h1.6v.3h-1.6z" fill="none" stroke="#e85bff" stroke-width=".34"/>
<path d="M148.7 95.8h1.6v.3h-1.6z" fill="#e85bff"/>
<path d="M148.7 95.8h1.6v.3h-1.6z" fill="none" stroke="#e85bff" stroke-width=".34"/>
<path d="M148.7 97.1h1.6v.3h-1.6z" fill="#e85bff"/>
<path d="M148.7 97h1.6v.4h-1.6z" fill="none" stroke="#e85bff" stroke-width=".34"/>
<path d="M162 104.7h1.5v.3h-1.5z" fill="#e85bff"/>
<path d="M162 104.6h1.5v.4h-1.5z" fill="none" stroke="#e85bff" stroke-width=".34"/>
<path d="M162 103.4h1.5v.4h-1.5z" fill="#e85bff"/>
<path d="M162 103.4h1.5v.3h-1.5z" fill="none" stroke="#e85bff" stroke-width=".34"/>
<path d="M162 102.2h1.5v.3h-1.5z" fill="#e85bff"/>
<path d="M162 102.1h1.5v.3h-1.5z" fill="none" stroke="#e85bff" stroke-width=".34"/>
<path d="M162 100.9h1.5v.3h-1.5z" fill="#e85bff"/>
<path d="M162 100.8h1.5v.4h-1.5z" fill="none" stroke="#e85bff" stroke-width=".34"/>
<path d="M162 99.6h1.5v.3h-1.5z" fill="#e85bff"/>
<path d="M162 99.6h1.5v.3h-1.5z" fill="none" stroke="#e85bff" stroke-width=".34"/>
<path d="M162 98.3h1.5v.4h-1.5z" fill="#e85bff"/>
<path d="M162 98.3h1.5v.3h-1.5z" fill="none" stroke="#e85bff" stroke-width=".34"/>
<path d="M162 97.1h1.5v.3h-1.5z" fill="#e85bff"/>
<path d="M162 97h1.5v.4h-1.5z" fill="none" stroke="#e85bff" stroke-width=".34"/>
<path d="M162 95.8h1.5v.3h-1.5z" fill="#e85bff"/>
<path d="M162 95.8h1.5v.3h-1.5z" fill="none" stroke="#e85bff" stroke-width=".34"/>
<path d="M162 94.5h1.5v.4h-1.5z" fill="#e85bff"/>
<path d="M162 94.5h1.5v.3h-1.5z" fill="none" stroke="#e85bff" stroke-width=".34"/>
<path d="M162 93.3h1.5v.3h-1.5z" fill="#e85bff"/>
<path d="M162 93.2h1.5v.4h-1.5z" fill="none" stroke="#e85bff" stroke-width=".34"/>
<path d="M162 92h1.5v.3h-1.5z" fill="#e85bff"/>
<path d="M162 91.9h1.5v.4h-1.5z" fill="none" stroke="#e85bff" stroke-width=".34"/>
<path d="M114.9 103.7h1.1v1.1h-1.1z" fill="#e85bff"/>
<path d="M114.8 103.6h1.1v1.1h-1.1z" fill="none" stroke="#e85bff" stroke-width=".51"/>
<g fill="#e85bff">
<path d="M132.7 109.1h.8v1.3h-.8z"/>
<circle cx="115.4" cy="106.8" r=".8"/>
<circle cx="115.4" cy="109.3" r=".8"/>
<circle cx="115.4" cy="111.9" r=".8"/>
<circle cx="115.4" cy="114.4" r=".8"/>
<circle cx="130.6" cy="111.9" r=".8"/>
<circle cx="130.6" cy="109.3" r=".8"/>
</g>
<path d="M132.7 109.1h.7v1.2h-.7z" fill="none" stroke="#e85bff" stroke-width=".51"/>
<path d="M135.8 109.1h.8v1.3h-.8z" fill="#e85bff"/>
<path d="M135.7 109.1h.9v1.2h-.9z" fill="none" stroke="#e85bff" stroke-width=".51"/>
<g fill="#e85bff">
<path d="M141 118.3h.9v.4h-.9z"/>
<path d="M141 118.8h.9v.4h-.9z"/>
<path d="M141 119.3h.9v.3h-.9z"/>
<path d="M141 119.8h.9v.3h-.9z"/>
<path d="M141 120.4h.9v.2h-.9z"/>
<path d="M141 120.9h.9v.2h-.9z"/>
<path d="M141 121.4h.9v.2h-.9z"/>
<path d="M141 121.8h.9v.3h-.9z"/>
<path d="M142.8 121.8h.8v.3h-.8z"/>
<path d="M142.8 121.4h.8v.2h-.8z"/>
<path d="M142.8 120.9h.8v.2h-.8z"/>
<path d="M142.8 120.4h.8v.2h-.8z"/>
<path d="M142.8 119.8h.8v.3h-.8z"/>
<path d="M142.8 119.3h.8v.3h-.8z"/>
<path d="M142.8 118.8h.8v.4h-.8z"/>
<path d="M142.8 118.3h.8v.4h-.8z"/>
<path d="M141.3 104.9h.8v.2h-.8z"/>
<path d="M141.3 105.4h.8v.2h-.8z"/>
<path d="M141.3 105.8h.8v.3h-.8z"/>
<path d="M141.3 106.3h.8v.3h-.8z"/>
<path d="M141.3 106.8h.8v.3h-.8z"/>
<path d="M141.3 107.3h.8v.4h-.8z"/>
<path d="M141.3 107.8h.8v.4h-.8z"/>
<path d="M141.3 108.3h.8v.4h-.8z"/>
<path d="M124.3 103.5h1.3v.8h-1.3z"/>
<circle cx="130.6" cy="106.8" r=".8"/>
<circle cx="130.6" cy="104.3" r=".8"/>
</g>
<path d="M124.3 103.5h1.3v.7h-1.3z" fill="none" stroke="#e85bff" stroke-width=".51"/>
<path d="M124.3 106.6h1.3v.8h-1.3z" fill="#e85bff"/>
<path d="M124.3 106.5h1.3v.9h-1.3z" fill="none" stroke="#e85bff" stroke-width=".51"/>
<path d="M126.4 98.9h1.2v.8h-1.2z" fill="#e85bff"/>
<path d="M126.3 98.9h1.3v.8h-1.3z" fill="none" stroke="#e85bff" stroke-width=".51"/>
<path d="M126.4 95.8h1.2v.8h-1.2z" fill="#e85bff"/>
<path d="M126.3 95.8h1.3v.8h-1.3z" fill="none" stroke="#e85bff" stroke-width=".51"/>
<g fill="#e85bff">
<path d="M143 46.6h1.4v.8h-1.4z"/>
<circle cx="146.8" cy="82.5" r=".8"/>
<circle cx="140.8" cy="82.5" r=".8"/>
<circle cx="140.8" cy="80" r=".8"/>
<circle cx="140.8" cy="74.9" r=".8"/>
<circle cx="125.5" cy="77.4" r=".8"/>
<circle cx="125.5" cy="80" r=".8"/>
<circle cx="125.5" cy="82.5" r=".8"/>
<circle cx="140.8" cy="77.4" r=".8"/>
<circle cx="140.8" cy="72.3" r=".8"/>
<circle cx="140.8" cy="69.8" r=".8"/>
<circle cx="140.8" cy="67.3" r=".8"/>
<circle cx="140.8" cy="64.7" r=".8"/>
<circle cx="140.8" cy="62.2" r=".8"/>
<circle cx="140.8" cy="59.6" r=".8"/>
<circle cx="140.8" cy="57.1" r=".8"/>
<circle cx="140.8" cy="54.6" r=".8"/>
<circle cx="140.8" cy="52" r=".8"/>
<circle cx="140.8" cy="49.5" r=".8"/>
<circle cx="140.8" cy="46.9" r=".8"/>
<circle cx="140.8" cy="44.4" r=".8"/>
</g>
<path d="M143 46.6h1.4v.7h-1.4z" fill="none" stroke="#e85bff" stroke-width=".51"/>
<path d="M149 120.4h1.6v.3h-1.6z" fill="#e85bff"/>
<path d="M148.9 120.3h1.6v.3h-1.6z" fill="none" stroke="#e85bff" stroke-width=".34"/>
<path d="M149 121.6h1.6v.4h-1.6z" fill="#e85bff"/>
<path d="M148.9 121.6h1.6v.3h-1.6z" fill="none" stroke="#e85bff" stroke-width=".34"/>
<path d="M161.4 113.4h.9v1.3h-.9z" fill="#e85bff"/>
<path d="M161.4 113.4h.8v1.2h-.8z" fill="none" stroke="#e85bff" stroke-width=".51"/>
<path d="M164.5 113.4h.9v1.3h-.9z" fill="#e85bff"/>
<path d="M164.5 113.4h.9v1.2h-.9z" fill="none" stroke="#e85bff" stroke-width=".51"/>
<path d="M149 116.5h1.6v.4h-1.6z" fill="#e85bff"/>
<path d="M148.9 116.5h1.6v.3h-1.6z" fill="none" stroke="#e85bff" stroke-width=".34"/>
<path d="M149 117.8h1.6v.4h-1.6z" fill="#e85bff"/>
<path d="M148.9 117.8h1.6v.3h-1.6z" fill="none" stroke="#e85bff" stroke-width=".34"/>
<path d="M149 119.1h1.6v.3h-1.6z" fill="#e85bff"/>
<path d="M148.9 119h1.6v.4h-1.6z" fill="none" stroke="#e85bff" stroke-width=".34"/>
<g fill="#e85bff">
<path d="M143 108.3h.9v.4h-.9z"/>
<path d="M148.7 108.5h1.6v.3h-1.6z"/>
</g>
<path d="M148.7 108.5h1.6v.3h-1.6z" fill="none" stroke="#e85bff" stroke-width=".34"/>
<path d="M148.7 109.8h1.6v.3h-1.6z" fill="#e85bff"/>
<path d="M148.7 109.7h1.6v.4h-1.6z" fill="none" stroke="#e85bff" stroke-width=".34"/>
<path d="M148.7 111h1.6v.4h-1.6z" fill="#e85bff"/>
<path d="M148.7 111h1.6v.3h-1.6z" fill="none" stroke="#e85bff" stroke-width=".34"/>
<g fill="#e85bff">
<path d="M143 107.8h.9v.4h-.9z"/>
<path d="M143 107.3h.9v.4h-.9z"/>
<path d="M143 106.8h.9v.3h-.9z"/>
<path d="M143 106.3h.9v.3h-.9z"/>
<path d="M143 105.8h.9v.3h-.9z"/>
<path d="M143 105.4h.9v.2h-.9z"/>
<path d="M143 104.9h.9v.2h-.9z"/>
<path d="M148.7 98.3h1.6v.4h-1.6z"/>
</g>
<path d="M148.7 98.3h1.6v.3h-1.6z" fill="none" stroke="#e85bff" stroke-width=".34"/>
<path d="M148.7 99.6h1.6v.3h-1.6z" fill="#e85bff"/>
<path d="M148.7 99.6h1.6v.3h-1.6z" fill="none" stroke="#e85bff" stroke-width=".34"/>
<path d="M148.7 100.9h1.6v.3h-1.6z" fill="#e85bff"/>
<path d="M148.7 100.8h1.6v.4h-1.6z" fill="none" stroke="#e85bff" stroke-width=".34"/>
<path d="M148.7 102.2h1.6v.3h-1.6z" fill="#e85bff"/>
<path d="M148.7 102.1h1.6v.3h-1.6z" fill="none" stroke="#e85bff" stroke-width=".34"/>
<path d="M148.7 103.4h1.6v.4h-1.6z" fill="#e85bff"/>
<path d="M148.7 103.4h1.6v.3h-1.6z" fill="none" stroke="#e85bff" stroke-width=".34"/>
<path d="M148.7 104.7h1.6v.3h-1.6z" fill="#e85bff"/>
<path d="M148.7 104.6h1.6v.4h-1.6z" fill="none" stroke="#e85bff" stroke-width=".34"/>
<path d="M148.7 106h1.6v.3h-1.6z" fill="#e85bff"/>
<path d="M148.7 105.9h1.6v.4h-1.6z" fill="none" stroke="#e85bff" stroke-width=".34"/>
<path d="M148.7 107.2h1.6v.4h-1.6z" fill="#e85bff"/>
<path d="M148.7 107.2h1.6v.3h-1.6z" fill="none" stroke="#e85bff" stroke-width=".34"/>
<path d="M162 111h1.5v.4h-1.5z" fill="#e85bff"/>
<path d="M162 111h1.5v.3h-1.5z" fill="none" stroke="#e85bff" stroke-width=".34"/>
<path d="M162 109.8h1.5v.3h-1.5z" fill="#e85bff"/>
<path d="M162 109.7h1.5v.4h-1.5z" fill="none" stroke="#e85bff" stroke-width=".34"/>
<path d="M162 108.5h1.5v.3h-1.5z" fill="#e85bff"/>
<path d="M162 108.5h1.5v.3h-1.5z" fill="none" stroke="#e85bff" stroke-width=".34"/>
<path d="M162 107.2h1.5v.4h-1.5z" fill="#e85bff"/>
<path d="M162 107.2h1.5v.3h-1.5z" fill="none" stroke="#e85bff" stroke-width=".34"/>
<path d="M162 106h1.5v.3h-1.5z" fill="#e85bff"/>
<path d="M162 105.9h1.5v.4h-1.5z" fill="none" stroke="#e85bff" stroke-width=".34"/>
<g fill="#e85bff">
<path d="M104.9 86h1.2v.8h-1.2z"/>
<circle cx="104.5" cy="69.8" r=".8"/>
<circle cx="104.5" cy="72.3" r=".8"/>
<circle cx="104.5" cy="74.9" r=".8"/>
<circle cx="98.5" cy="74.9" r=".8"/>
<circle cx="98.5" cy="72.3" r=".8"/>
<circle cx="98.5" cy="69.8" r=".8"/>
<circle cx="104.5" cy="82.5" r=".8"/>
<circle cx="119.8" cy="82.5" r=".8"/>
<circle cx="119.8" cy="80" r=".8"/>
<circle cx="119.8" cy="77.4" r=".8"/>
</g>
<path d="M104.8 85.9h1.3v.9h-1.3z" fill="none" stroke="#e85bff" stroke-width=".51"/>
<g fill="#e85bff">
<path d="M70.7 75.9h1.6v1.7h-1.6z"/>
<path d="M95 92.2h1.1v2.4h-1.1z"/>
<circle cx="71.5" cy="74.2" r=".89"/>
<circle cx="71.5" cy="71.7" r=".89"/>
<circle cx="71.5" cy="69.1" r=".89"/>
<circle cx="71.5" cy="66.6" r=".89"/>
</g>
<path d="M94.9 92.1h1.1v2.5h-1.1z" fill="none" stroke="#e85bff" stroke-width=".51"/>
<path d="M95 96.6h1.1v2.4h-1.1z" fill="#e85bff"/>
<path d="M94.9 96.5h1.1v2.5h-1.1z" fill="none" stroke="#e85bff" stroke-width=".51"/>
<path d="M89.4 87.5h1.2v.8h-1.2z" fill="#e85bff"/>
<path d="M89.3 87.5h1.3v.7h-1.3z" fill="none" stroke="#e85bff" stroke-width=".51"/>
<path d="M95.9 86.6h1.2v.8h-1.2z" fill="#e85bff"/>
<path d="M95.8 86.5h1.2v.9h-1.2z" fill="none" stroke="#e85bff" stroke-width=".51"/>
<path d="M95.9 89.7h1.2v.8h-1.2z" fill="#e85bff"/>
<path d="M95.8 89.7h1.2v.7h-1.2z" fill="none" stroke="#e85bff" stroke-width=".51"/>
<path d="M89.4 90.6h1.2v.8h-1.2z" fill="#e85bff"/>
<path d="M89.3 90.5h1.3v.9h-1.3z" fill="none" stroke="#e85bff" stroke-width=".51"/>
<path d="M83.5 94.9h1v1.2h-1z" fill="#e85bff"/>
<path d="M83.5 94.8h.9v1.3h-.9z" fill="none" stroke="#e85bff" stroke-width=".51"/>
<path d="M86.5 94.9h.9v1.2h-.9z" fill="#e85bff"/>
<path d="M86.4 94.8h1v1.3h-1z" fill="none" stroke="#e85bff" stroke-width=".51"/>
<g fill="#e85bff">
<path d="M74.4 83.9h1.2v.6h-1.2z"/>
<circle cx="72" cy="93" r="2.84"/>
</g>
<path d="M74.3 83.8h1.3v.7h-1.3z" fill="none" stroke="#e85bff" stroke-width=".51"/>
<path d="M74.7 86.1h.6" fill="none" stroke="#e85bff" stroke-width="1.2"/>
<g fill="#e85bff">
<path d="M124.9 43.8h1.1v1.1h-1.1z"/>
<circle cx="83.3" cy="69.8" r=".8"/>
<circle cx="83.3" cy="72.3" r=".8"/>
<circle cx="83.3" cy="74.9" r=".8"/>
<circle cx="83.3" cy="77.4" r=".8"/>
<circle cx="83.3" cy="80" r=".8"/>
<circle cx="83.3" cy="82.5" r=".8"/>
<circle cx="104.5" cy="77.4" r=".8"/>
<circle cx="104.5" cy="80" r=".8"/>
<circle cx="98.5" cy="82.5" r=".8"/>
<circle cx="98.5" cy="80" r=".8"/>
<circle cx="98.5" cy="77.4" r=".8"/>
<circle cx="119.8" cy="69.8" r=".8"/>
<circle cx="119.8" cy="67.3" r=".8"/>
<circle cx="119.8" cy="64.7" r=".8"/>
<circle cx="125.5" cy="67.3" r=".8"/>
<circle cx="119.8" cy="62.2" r=".8"/>
<circle cx="119.8" cy="59.6" r=".8"/>
<circle cx="119.8" cy="57.1" r=".8"/>
<circle cx="119.8" cy="54.6" r=".8"/>
<circle cx="125.5" cy="62.2" r=".8"/>
<circle cx="125.5" cy="64.7" r=".8"/>
<circle cx="119.8" cy="49.5" r=".8"/>
<circle cx="119.8" cy="46.9" r=".8"/>
<circle cx="119.8" cy="44.4" r=".8"/>
</g>
<path d="M124.9 43.8h1.1v1.1h-1.1z" fill="none" stroke="#e85bff" stroke-width=".51"/>
<g fill="#e85bff">
<path d="M122 43.5h1.4v.7h-1.4z"/>
<circle cx="125.5" cy="46.9" r=".8"/>
</g>
<path d="M122 43.4h1.4v.8h-1.4z" fill="none" stroke="#e85bff" stroke-width=".51"/>
<path d="M122 46.6h1.4v.8h-1.4z" fill="#e85bff"/>
<path d="M122 46.6h1.4v.7h-1.4z" fill="none" stroke="#e85bff" stroke-width=".51"/>
<g fill="#e85bff">
<path d="M100.4 87.1h1.2v.2h-1.2z"/>
<circle cx="119.8" cy="52" r=".8"/>
<circle cx="125.5" cy="49.5" r=".8"/>
<circle cx="125.5" cy="52" r=".8"/>
<circle cx="125.5" cy="54.6" r=".8"/>
<circle cx="125.5" cy="57.1" r=".8"/>
<circle cx="125.5" cy="59.6" r=".8"/>
<circle cx="119.8" cy="74.9" r=".8"/>
<circle cx="119.8" cy="72.3" r=".8"/>
<circle cx="125.5" cy="69.8" r=".8"/>
<circle cx="125.5" cy="72.3" r=".8"/>
<circle cx="125.5" cy="74.9" r=".8"/>
</g>
<path d="M100.3 87h1.2v.3h-1.2z" fill="none" stroke="#e85bff" stroke-width=".34"/>
<path d="M100.4 88.9h1.2v.4h-1.2z" fill="#e85bff"/>
<path d="M100.3 88.9h1.2v.3h-1.2z" fill="none" stroke="#e85bff" stroke-width=".34"/>
<path d="M102.2 88h1.2v.3h-1.2z" fill="#e85bff"/>
<path d="M102.2 88h1.2v.2h-1.2z" fill="none" stroke="#e85bff" stroke-width=".34"/>
<g fill="#e85bff">
<path d="M111.3 90.6h.8v.3h-.8z"/>
<path d="M104.9 89.1h1.2v.8h-1.2z"/>
</g>
<path d="M104.8 89.1h1.3v.7h-1.3z" fill="none" stroke="#e85bff" stroke-width=".51"/>
<path d="M101.6 92.1h1.1v2.5h-1.1z" fill="#e85bff"/>
<path d="M101.6 92h1.1v2.6h-1.1z" fill="none" stroke="#e85bff" stroke-width=".51"/>
<path d="M101.6 96.5h1.1v2.5h-1.1z" fill="#e85bff"/>
<path d="M101.6 96.4h1.1v2.6h-1.1z" fill="none" stroke="#e85bff" stroke-width=".51"/>
<path d="M107.3 100.7h1.4v.9h-1.4z" fill="#e85bff"/>
<path d="M107.3 100.7h1.3v.8h-1.3z" fill="none" stroke="#e85bff" stroke-width=".51"/>
<path d="M107.3 97.6h1.4v.8h-1.4z" fill="#e85bff"/>
<path d="M107.3 97.5h1.3v.9h-1.3z" fill="none" stroke="#e85bff" stroke-width=".51"/>
<g fill="#e85bff">
<path d="M111.3 91.1h.8v.3h-.8z"/>
<path d="M111.3 91.6h.8v.3h-.8z"/>
<path d="M111.3 92.1h.8v.3h-.8z"/>
<path d="M111.3 92.6h.8v.3h-.8z"/>
<path d="M111.3 93.1h.8v.3h-.8z"/>
<path d="M111.3 93.6h.8v.3h-.8z"/>
<path d="M111.3 94.1h.8v.3h-.8z"/>
<path d="M113.1 94.1h.8v.3h-.8z"/>
<path d="M113.1 93.6h.8v.3h-.8z"/>
<path d="M113.1 93.1h.8v.3h-.8z"/>
<path d="M113.1 92.6h.8v.3h-.8z"/>
<path d="M113.1 92.1h.8v.3h-.8z"/>
<path d="M113.1 91.6h.8v.3h-.8z"/>
<path d="M113.1 91.1h.8v.3h-.8z"/>
<path d="M113.1 90.6h.8v.3h-.8z"/>
<path d="M82.7 43.8h1.1v1.1h-1.1z"/>
<circle cx="104.5" cy="49.5" r=".8"/>
<circle cx="104.5" cy="52" r=".8"/>
<circle cx="104.5" cy="54.6" r=".8"/>
<circle cx="98.5" cy="49.5" r=".8"/>
<circle cx="104.5" cy="57.1" r=".8"/>
<circle cx="104.5" cy="59.6" r=".8"/>
<circle cx="104.5" cy="62.2" r=".8"/>
<circle cx="98.5" cy="59.6" r=".8"/>
<circle cx="98.5" cy="57.1" r=".8"/>
<circle cx="98.5" cy="54.6" r=".8"/>
<circle cx="98.5" cy="52" r=".8"/>
<circle cx="71.5" cy="64.1" r=".89"/>
<circle cx="71.5" cy="61.5" r=".89"/>
<circle cx="71.5" cy="59" r=".89"/>
<circle cx="71.5" cy="56.4" r=".89"/>
<circle cx="72" cy="46" r="2.84"/>
</g>
<path d="M82.6 43.8h1.1v1.1h-1.1z" fill="none" stroke="#e85bff" stroke-width=".51"/>
<g fill="#e85bff">
<path d="M103.9 43.8h1.1v1.1h-1.1z"/>
<circle cx="83.3" cy="46.9" r=".8"/>
<circle cx="83.3" cy="49.5" r=".8"/>
<circle cx="83.3" cy="52" r=".8"/>
<circle cx="83.3" cy="54.6" r=".8"/>
<circle cx="83.3" cy="57.1" r=".8"/>
<circle cx="83.3" cy="59.6" r=".8"/>
<circle cx="83.3" cy="62.2" r=".8"/>
<circle cx="83.3" cy="64.7" r=".8"/>
<circle cx="83.3" cy="67.3" r=".8"/>
<circle cx="104.5" cy="64.7" r=".8"/>
<circle cx="104.5" cy="67.3" r=".8"/>
<circle cx="98.5" cy="67.3" r=".8"/>
<circle cx="98.5" cy="64.7" r=".8"/>
<circle cx="98.5" cy="62.2" r=".8"/>
</g>
<path d="M103.9 43.8h1.1v1.1h-1.1z" fill="none" stroke="#e85bff" stroke-width=".51"/>
<g fill="#e85bff">
<path d="M100.8 43.5h1.4v.7h-1.4z"/>
<circle cx="104.5" cy="46.9" r=".8"/>
<circle cx="98.5" cy="46.9" r=".8"/>
<circle cx="98.5" cy="44.4" r=".8"/>
</g>
<path d="M100.8 43.4h1.3v.8h-1.3z" fill="none" stroke="#e85bff" stroke-width=".51"/>
<path d="M100.8 46.6h1.4v.8h-1.4z" fill="#e85bff"/>
<path d="M100.8 46.6h1.3v.7h-1.3z" fill="none" stroke="#e85bff" stroke-width=".51"/>
<path d="M94.5 103.7h1.1v1.1h-1.1z" fill="#e85bff"/>
<path d="M94.5 103.6h1.1v1.1h-1.1z" fill="none" stroke="#e85bff" stroke-width=".51"/>
<g fill="#e85bff">
<path d="M98.2 104h1.3v.9h-1.3z"/>
<circle cx="95" cy="106.8" r=".8"/>
<circle cx="95" cy="109.3" r=".8"/>
<circle cx="95" cy="111.9" r=".8"/>
<circle cx="95" cy="114.4" r=".8"/>
</g>
<path d="M98.1 104h1.4v.8h-1.4z" fill="none" stroke="#e85bff" stroke-width=".51"/>
<path d="M98.2 107.1h1.3v.9h-1.3z" fill="#e85bff"/>
<path d="M98.1 107.1h1.4v.8h-1.4z" fill="none" stroke="#e85bff" stroke-width=".51"/>
<g fill="#e85bff">
<path d="M166.9 56.8h1.7v.3h-1.7z"/>
<circle cx="95" cy="117" r=".8"/>
<circle cx="95" cy="119.5" r=".8"/>
<circle cx="95" cy="122" r=".8"/>
<circle cx="95" cy="124.6" r=".8"/>
<circle cx="95" cy="127.1" r=".8"/>
<circle cx="95" cy="129.7" r=".8"/>
<circle cx="95" cy="132.2" r=".8"/>
<circle cx="95" cy="134.7" r=".8"/>
<circle cx="95" cy="137.3" r=".8"/>
<circle cx="95" cy="139.8" r=".8"/>
<circle cx="85" cy="145" r="2.84"/>
<circle cx="95" cy="142.4" r=".8"/>
<circle cx="110.3" cy="142.4" r=".8"/>
<circle cx="110.3" cy="139.8" r=".8"/>
<circle cx="110.3" cy="137.3" r=".8"/>
<circle cx="110.3" cy="134.7" r=".8"/>
<circle cx="110.3" cy="132.2" r=".8"/>
<circle cx="110.3" cy="129.7" r=".8"/>
<circle cx="110.3" cy="127.1" r=".8"/>
<circle cx="110.3" cy="124.6" r=".8"/>
<circle cx="110.3" cy="122" r=".8"/>
<circle cx="110.3" cy="119.5" r=".8"/>
<circle cx="110.3" cy="117" r=".8"/>
<circle cx="110.3" cy="114.4" r=".8"/>
<circle cx="110.3" cy="111.9" r=".8"/>
<circle cx="110.3" cy="109.3" r=".8"/>
<circle cx="110.3" cy="106.8" r=".8"/>
<circle cx="110.3" cy="104.3" r=".8"/>
<circle cx="162" cy="49.5" r=".8"/>
<circle cx="162" cy="46.9" r=".8"/>
<circle cx="162" cy="44.4" r=".8"/>
</g>
<path d="M166.9 56.7h1.7v.4h-1.7z" fill="none" stroke="#e85bff" stroke-width=".34"/>
<path d="M164.3 43.5h1.4v.7h-1.4z" fill="#e85bff"/>
<path d="M164.3 43.4h1.3v.8h-1.3z" fill="none" stroke="#e85bff" stroke-width=".51"/>
<path d="M164.3 46.6h1.4v.8h-1.4z" fill="#e85bff"/>
<path d="M164.3 46.6h1.3v.7h-1.3z" fill="none" stroke="#e85bff" stroke-width=".51"/>
<path d="M143 43.5h1.4v.7h-1.4z" fill="#e85bff"/>
<path d="M143 43.4h1.4v.8h-1.4z" fill="none" stroke="#e85bff" stroke-width=".51"/>
<g fill="#e85bff">
<path d="M193 43h2.4v2h-2.4z"/>
<circle cx="191" cy="42.5" r=".8"/>
</g>
<path d="M193 42.9h2.3v2.1h-2.3z" fill="none" stroke="#e85bff" stroke-width=".51"/>
<path d="M194 48h.4M194 51.9h.4" fill="none" stroke="#e85bff" stroke-width="2.5"/>
<path d="M180.6 42.5h.8v1.3h-.8z" fill="#e85bff"/>
<path d="M180.5 42.5h.9v1.3h-.9z" fill="none" stroke="#e85bff" stroke-width=".51"/>
<path d="M179.8 50.4h1.2v.9h-1.2z" fill="#e85bff"/>
<path d="M179.7 50.4h1.2v.8h-1.2z" fill="none" stroke="#e85bff" stroke-width=".51"/>
<g fill="#e85bff">
<path d="M180.6 46.8h.8v1.2h-.8z"/>
<circle cx="172" cy="46" r="2.84"/>
</g>
<path d="M180.6 46.7h.8v1.2h-.8z" fill="none" stroke="#e85bff" stroke-width=".51"/>
<path d="M166.9 64.4h1.7v.3h-1.7z" fill="#e85bff"/>
<path d="M166.9 64.3h1.7v.4h-1.7z" fill="none" stroke="#e85bff" stroke-width=".34"/>
<path d="M171.9 64.4h1.6v.3h-1.6z" fill="#e85bff"/>
<path d="M171.9 64.3h1.6v.4h-1.6z" fill="none" stroke="#e85bff" stroke-width=".34"/>
<path d="M171.9 63.1h1.6v.4h-1.6z" fill="#e85bff"/>
<path d="M171.9 63.1h1.6v.3h-1.6z" fill="none" stroke="#e85bff" stroke-width=".34"/>
<path d="M171.9 61.8h1.6v.4h-1.6z" fill="#e85bff"/>
<path d="M171.9 61.8h1.6v.3h-1.6z" fill="none" stroke="#e85bff" stroke-width=".34"/>
<path d="M171.9 60.6h1.6v.3h-1.6z" fill="#e85bff"/>
<path d="M171.9 60.5h1.6v.4h-1.6z" fill="none" stroke="#e85bff" stroke-width=".34"/>
<path d="M171.9 59.3h1.6v.3h-1.6z" fill="#e85bff"/>
<path d="M171.9 59.3h1.6v.3h-1.6z" fill="none" stroke="#e85bff" stroke-width=".34"/>
<path d="M171.9 58h1.6v.4h-1.6z" fill="#e85bff"/>
<path d="M171.9 58h1.6v.3h-1.6z" fill="none" stroke="#e85bff" stroke-width=".34"/>
<path d="M171.9 56.8h1.6v.3h-1.6z" fill="#e85bff"/>
<path d="M171.9 56.7h1.6v.4h-1.6z" fill="none" stroke="#e85bff" stroke-width=".34"/>
<path d="M194 55.8h.4M194 59.8h.4M194 63.8h.4" fill="none" stroke="#e85bff" stroke-width="2.5"/>
<path d="M187.6 56.5h1.3v.8h-1.3z" fill="#e85bff"/>
<path d="M187.5 56.5h1.4v.7h-1.4z" fill="none" stroke="#e85bff" stroke-width=".51"/>
<path d="M184.1 56.9h1.6v.2h-1.6z" fill="#e85bff"/>
<path d="M184.1 56.8h1.6v.3h-1.6z" fill="none" stroke="#e85bff" stroke-width=".34"/>
<path d="M175.7 57.2h1.3v.8h-1.3z" fill="#e85bff"/>
<path d="M175.7 57.1h1.3v.8h-1.3z" fill="none" stroke="#e85bff" stroke-width=".51"/>
<path d="M175.7 60.3h1.3v.8h-1.3z" fill="#e85bff"/>
<path d="M175.7 60.3h1.3v.7h-1.3z" fill="none" stroke="#e85bff" stroke-width=".51"/>
<path d="M179.8 53.6h1.2v.8h-1.2z" fill="#e85bff"/>
<path d="M179.7 53.5h1.2v.9h-1.2z" fill="none" stroke="#e85bff" stroke-width=".51"/>
<path d="M172.7 53.3h.8v1.3h-.8z" fill="#e85bff"/>
<path d="M172.6 53.3h.9v1.2h-.9z" fill="none" stroke="#e85bff" stroke-width=".51"/>
<path d="M175.8 53.3h.9v1.3h-.9z" fill="#e85bff"/>
<path d="M175.8 53.3h.8v1.2h-.8z" fill="none" stroke="#e85bff" stroke-width=".51"/>
<path d="M179.2 56.9h1.6v.2h-1.6z" fill="#e85bff"/>
<path d="M179.2 56.8h1.6v.3h-1.6z" fill="none" stroke="#e85bff" stroke-width=".34"/>
<path d="M183.7 42.5h.8v1.3h-.8z" fill="#e85bff"/>
<path d="M183.6 42.5h.9v1.3h-.9z" fill="none" stroke="#e85bff" stroke-width=".51"/>
<path d="M187.6 53.4h1.3v.8h-1.3z" fill="#e85bff"/>
<path d="M187.5 53.3h1.4v.9h-1.4z" fill="none" stroke="#e85bff" stroke-width=".51"/>
<path d="M183.7 46.8h.8v1.2h-.8z" fill="#e85bff"/>
<path d="M183.6 46.7h.9v1.2h-.9z" fill="none" stroke="#e85bff" stroke-width=".51"/>
<path d="M183.5 51.5h1.1v.3h-1.1z" fill="#e85bff"/>
<path d="M183.5 51.5h1.1v.2h-1.1z" fill="none" stroke="#e85bff" stroke-width=".34"/>
<path d="M183.5 53.4h1.1v.3h-1.1z" fill="#e85bff"/>
<path d="M183.5 53.3h1.1v.4h-1.1z" fill="none" stroke="#e85bff" stroke-width=".34"/>
<path d="M185.4 52.5h1.2v.2h-1.2z" fill="#e85bff"/>
<path d="M185.3 52.4h1.2v.3h-1.2z" fill="none" stroke="#e85bff" stroke-width=".34"/>
<path d="M166.9 58h1.7v.4h-1.7z" fill="#e85bff"/>
<path d="M166.9 58h1.7v.3h-1.7z" fill="none" stroke="#e85bff" stroke-width=".34"/>
<path d="M166.9 59.3h1.7v.3h-1.7z" fill="#e85bff"/>
<path d="M166.9 59.3h1.7v.3h-1.7z" fill="none" stroke="#e85bff" stroke-width=".34"/>
<path d="M166.9 60.6h1.7v.3h-1.7z" fill="#e85bff"/>
<path d="M166.9 60.5h1.7v.4h-1.7z" fill="none" stroke="#e85bff" stroke-width=".34"/>
<path d="M166.9 61.8h1.7v.4h-1.7z" fill="#e85bff"/>
<path d="M166.9 61.8h1.7v.3h-1.7z" fill="none" stroke="#e85bff" stroke-width=".34"/>
<path d="M166.9 63.1h1.7v.4h-1.7z" fill="#e85bff"/>
<path d="M166.9 63.1h1.7v.3h-1.7z" fill="none" stroke="#e85bff" stroke-width=".34"/>
<g fill="#e85bff">
<path d="M183.4 73.8h1v.5h-1z"/>
<path d="M183.9 73.3h.6v1.5h-.6z"/>
<path d="M183.4 70.7h1v.5h-1z"/>
<path d="M183.9 70.3h.6v1.5h-.6z"/>
<path d="M184.7 67.4h1v1.5h-1z"/>
<path d="M186.1 67.9h1v.5h-1z"/>
<path d="M186 67.4h.6v1.5h-.6z"/>
<circle cx="183.9" cy="74.3" r=".55"/>
<circle cx="183.9" cy="73.8" r=".55"/>
<circle cx="183.9" cy="71.2" r=".55"/>
<circle cx="183.9" cy="70.7" r=".55"/>
<circle cx="186.6" cy="68.4" r=".55"/>
<circle cx="186.6" cy="67.9" r=".55"/>
</g>
<path d="M184.5 67.4h1.5v1.5h-1.5z" fill="none" stroke="#e85bff" stroke-width=".21"/>
<g fill="#e85bff">
<path d="M184.5 67.4h1.5v1.5h-1.5z"/>
<path d="M168.6 71.7h.4v.8h-.4z"/>
<path d="M169.4 71.7h.4v.8h-.4z"/>
<path d="M170.2 71.7h.4v.8h-.4z"/>
<path d="M171 71.7h.4v.8h-.4z"/>
<path d="M171 69.9h.4v.9h-.4z"/>
<path d="M170.2 69.9h.4v.9h-.4z"/>
<path d="M169.4 69.9h.4v.9h-.4z"/>
<path d="M168.6 69.9h.4v.9h-.4z"/>
<path d="M179.2 58.1h1.6v.3h-1.6z"/>
</g>
<path d="M179.2 58.1h1.6v.2h-1.6z" fill="none" stroke="#e85bff" stroke-width=".34"/>
<path d="M179.2 59.4h1.6v.2h-1.6z" fill="#e85bff"/>
<path d="M179.2 59.4h1.6v.2h-1.6z" fill="none" stroke="#e85bff" stroke-width=".34"/>
<path d="M179.2 60.7h1.6v.2h-1.6z" fill="#e85bff"/>
<path d="M179.2 60.6h1.6v.3h-1.6z" fill="none" stroke="#e85bff" stroke-width=".34"/>
<path d="M179.2 61.9h1.6v.3h-1.6z" fill="#e85bff"/>
<path d="M179.2 61.9h1.6v.2h-1.6z" fill="none" stroke="#e85bff" stroke-width=".34"/>
<path d="M179.2 63.2h1.6v.3h-1.6z" fill="#e85bff"/>
<path d="M179.2 63.2h1.6v.2h-1.6z" fill="none" stroke="#e85bff" stroke-width=".34"/>
<path d="M179.2 64.5h1.6v.2h-1.6z" fill="#e85bff"/>
<path d="M179.2 64.4h1.6v.3h-1.6z" fill="none" stroke="#e85bff" stroke-width=".34"/>
<path d="M184.1 64.5h1.6v.2h-1.6z" fill="#e85bff"/>
<path d="M184.1 64.4h1.6v.3h-1.6z" fill="none" stroke="#e85bff" stroke-width=".34"/>
<path d="M184.1 63.2h1.6v.3h-1.6z" fill="#e85bff"/>
<path d="M184.1 63.2h1.6v.2h-1.6z" fill="none" stroke="#e85bff" stroke-width=".34"/>
<path d="M184.1 61.9h1.6v.3h-1.6z" fill="#e85bff"/>
<path d="M184.1 61.9h1.6v.2h-1.6z" fill="none" stroke="#e85bff" stroke-width=".34"/>
<path d="M184.1 60.7h1.6v.2h-1.6z" fill="#e85bff"/>
<path d="M184.1 60.6h1.6v.3h-1.6z" fill="none" stroke="#e85bff" stroke-width=".34"/>
<path d="M184.1 59.4h1.6v.2h-1.6z" fill="#e85bff"/>
<path d="M184.1 59.4h1.6v.2h-1.6z" fill="none" stroke="#e85bff" stroke-width=".34"/>
<path d="M184.1 58.1h1.6v.3h-1.6z" fill="#e85bff"/>
<path d="M184.1 58.1h1.6v.2h-1.6z" fill="none" stroke="#e85bff" stroke-width=".34"/>
<path d="M179.9 70.7h.7v1.3h-.7z" fill="#e85bff"/>
<path d="M179.8 70.7h.8v1.3h-.8z" fill="none" stroke="#e85bff" stroke-width=".51"/>
<path d="M176.8 67.5h.8v1.3h-.8z" fill="#e85bff"/>
<path d="M176.8 67.5h.7v1.2h-.7z" fill="none" stroke="#e85bff" stroke-width=".51"/>
<path d="M179.9 67.5h.8v1.3h-.8z" fill="#e85bff"/>
<path d="M179.8 67.5h.9v1.2h-.9z" fill="none" stroke="#e85bff" stroke-width=".51"/>
<g fill="#e85bff">
<path d="M183.4 67.9h1v.5h-1z"/>
<path d="M183.9 67.4h.6v1.5h-.6z"/>
<path d="M171.7 91.9h1.5v.3h-1.5z"/>
<circle cx="183.9" cy="68.4" r=".55"/>
<circle cx="183.9" cy="67.9" r=".55"/>
</g>
<path d="M171.6 91.9h1.5v.2h-1.5z" fill="none" stroke="#e85bff" stroke-width=".34"/>
<path d="M171.7 93.2h1.5v.2h-1.5z" fill="#e85bff"/>
<path d="M171.6 93.1h1.5v.3h-1.5z" fill="none" stroke="#e85bff" stroke-width=".34"/>
<path d="M171.7 94.4h1.5v.3h-1.5z" fill="#e85bff"/>
<path d="M171.6 94.4h1.5v.3h-1.5z" fill="none" stroke="#e85bff" stroke-width=".34"/>
<path d="M171.7 95.7h1.5v.3h-1.5z" fill="#e85bff"/>
<path d="M171.6 95.7h1.5v.2h-1.5z" fill="none" stroke="#e85bff" stroke-width=".34"/>
<path d="M171.7 97h1.5v.2h-1.5z" fill="#e85bff"/>
<path d="M171.6 96.9h1.5v.3h-1.5z" fill="none" stroke="#e85bff" stroke-width=".34"/>
<path d="M185 94.4h1.5v.3h-1.5z" fill="#e85bff"/>
<path d="M184.9 94.4h1.5v.3h-1.5z" fill="none" stroke="#e85bff" stroke-width=".34"/>
<path d="M185 93.2h1.5v.2h-1.5z" fill="#e85bff"/>
<path d="M184.9 93.1h1.5v.3h-1.5z" fill="none" stroke="#e85bff" stroke-width=".34"/>
<path d="M185 91.9h1.5v.3h-1.5z" fill="#e85bff"/>
<path d="M184.9 91.9h1.5v.2h-1.5z" fill="none" stroke="#e85bff" stroke-width=".34"/>
<path d="M187.2 88.3h.9v1.4h-.9z" fill="#e85bff"/>
<path d="M187.2 88.3h.8v1.4h-.8z" fill="none" stroke="#e85bff" stroke-width=".51"/>
<path d="M184.2 88.3h.8v1.4h-.8z" fill="#e85bff"/>
<path d="M184.1 88.3h.8v1.4h-.8z" fill="none" stroke="#e85bff" stroke-width=".51"/>
<path d="M175.5 80.8h1.6v.4h-1.6z" fill="#e85bff"/>
<path d="M175.4 80.8h1.6v.3h-1.6z" fill="none" stroke="#e85bff" stroke-width=".34"/>
<path d="M175.5 82.1h1.6v.3h-1.6z" fill="#e85bff"/>
<path d="M175.4 82h1.6v.4h-1.6z" fill="none" stroke="#e85bff" stroke-width=".34"/>
<path d="M175.5 83.4h1.6v.3h-1.6z" fill="#e85bff"/>
<path d="M175.4 83.3h1.6v.4h-1.6z" fill="none" stroke="#e85bff" stroke-width=".34"/>
<path d="M175.5 84.6h1.6v.4h-1.6z" fill="#e85bff"/>
<path d="M175.4 84.6h1.6v.3h-1.6z" fill="none" stroke="#e85bff" stroke-width=".34"/>
<path d="M175.5 85.9h1.6v.3h-1.6z" fill="#e85bff"/>
<path d="M175.4 85.9h1.6v.3h-1.6z" fill="none" stroke="#e85bff" stroke-width=".34"/>
<path d="M180.4 85.9h1.7v.3h-1.7z" fill="#e85bff"/>
<path d="M180.3 85.9h1.7v.3h-1.7z" fill="none" stroke="#e85bff" stroke-width=".34"/>
<path d="M180.4 84.6h1.7v.4h-1.7z" fill="#e85bff"/>
<path d="M180.3 84.6h1.7v.3h-1.7z" fill="none" stroke="#e85bff" stroke-width=".34"/>
<path d="M180.4 83.4h1.7v.3h-1.7z" fill="#e85bff"/>
<path d="M180.3 83.3h1.7v.4h-1.7z" fill="none" stroke="#e85bff" stroke-width=".34"/>
<path d="M180.4 82.1h1.7v.3h-1.7z" fill="#e85bff"/>
<path d="M180.3 82h1.7v.4h-1.7z" fill="none" stroke="#e85bff" stroke-width=".34"/>
<path d="M180.4 80.8h1.7v.4h-1.7z" fill="#e85bff"/>
<path d="M180.3 80.8h1.7v.3h-1.7z" fill="none" stroke="#e85bff" stroke-width=".34"/>
<g fill="#e85bff">
<path d="M184.7 73.3h1v1.5h-1z"/>
<path d="M186.1 73.8h1v.5h-1z"/>
<path d="M186 73.3h.6v1.5h-.6z"/>
<circle cx="186.6" cy="74.3" r=".55"/>
<circle cx="186.6" cy="73.8" r=".55"/>
</g>
<path d="M184.5 73.3h1.5v1.5h-1.5z" fill="none" stroke="#e85bff" stroke-width=".21"/>
<g fill="#e85bff">
<path d="M184.5 73.3h1.5v1.5h-1.5z"/>
<path d="M184.7 70.3h1v1.5h-1z"/>
</g>
<path d="M184.5 70.3h1.5v1.5h-1.5z" fill="none" stroke="#e85bff" stroke-width=".21"/>
<g fill="#e85bff">
<path d="M184.5 70.3h1.5v1.5h-1.5z"/>
<path d="M176.7 70.7h.9v1.3h-.9z"/>
</g>
<path d="M176.7 70.7h.8v1.3h-.8z" fill="none" stroke="#e85bff" stroke-width=".51"/>
<path d="M175.5 77h1.6v.3h-1.6z" fill="#e85bff"/>
<path d="M175.4 77h1.6v.3h-1.6z" fill="none" stroke="#e85bff" stroke-width=".34"/>
<path d="M175.5 78.3h1.6v.3h-1.6z" fill="#e85bff"/>
<path d="M175.4 78.2h1.6v.4h-1.6z" fill="none" stroke="#e85bff" stroke-width=".34"/>
<path d="M175.5 79.5h1.6v.4h-1.6z" fill="#e85bff"/>
<path d="M175.4 79.5h1.6v.3h-1.6z" fill="none" stroke="#e85bff" stroke-width=".34"/>
<path d="M180.4 79.5h1.7v.4h-1.7z" fill="#e85bff"/>
<path d="M180.3 79.5h1.7v.3h-1.7z" fill="none" stroke="#e85bff" stroke-width=".34"/>
<path d="M180.4 78.3h1.7v.3h-1.7z" fill="#e85bff"/>
<path d="M180.3 78.2h1.7v.4h-1.7z" fill="none" stroke="#e85bff" stroke-width=".34"/>
<path d="M180.4 77h1.7v.3h-1.7z" fill="#e85bff"/>
<path d="M180.3 77h1.7v.3h-1.7z" fill="none" stroke="#e85bff" stroke-width=".34"/>
<g fill="#e85bff">
<path d="M186.1 70.7h1v.5h-1z"/>
<path d="M186 70.3h.6v1.5h-.6z"/>
<path d="M192 71.9h1.2v1.2h-1.2z"/>
<circle cx="186.6" cy="71.2" r=".55"/>
<circle cx="186.6" cy="70.7" r=".55"/>
</g>
<path d="M191.9 71.9h1.2v1.2h-1.2z" fill="none" stroke="#e85bff" stroke-width=".51"/>
<g fill="#e85bff">
<circle cx="195.1" cy="72.5" r=".89"/>
<circle cx="192.6" cy="75.1" r=".89"/>
<circle cx="195.1" cy="75.1" r=".89"/>
<circle cx="192.6" cy="77.6" r=".89"/>
<circle cx="195.1" cy="77.6" r=".89"/>
<circle cx="192.6" cy="80.1" r=".89"/>
<circle cx="195.1" cy="80.1" r=".89"/>
<circle cx="192.6" cy="82.7" r=".89"/>
<circle cx="195.1" cy="82.7" r=".89"/>
<circle cx="192.6" cy="85.2" r=".89"/>
<circle cx="195.1" cy="85.2" r=".89"/>
<circle cx="192.6" cy="87.8" r=".89"/>
<circle cx="195.1" cy="87.8" r=".89"/>
<circle cx="192.6" cy="90.3" r=".89"/>
<circle cx="195.1" cy="90.3" r=".89"/>
<circle cx="192.6" cy="92.8" r=".89"/>
<circle cx="195.1" cy="92.8" r=".89"/>
<circle cx="192.6" cy="95.4" r=".89"/>
<circle cx="195.1" cy="95.4" r=".89"/>
<circle cx="192.6" cy="97.9" r=".89"/>
<circle cx="195.1" cy="97.9" r=".89"/>
<circle cx="192.6" cy="100.5" r=".89"/>
<circle cx="195.1" cy="100.5" r=".89"/>
<circle cx="192.6" cy="103" r=".89"/>
<circle cx="195.1" cy="103" r=".89"/>
<circle cx="192.6" cy="105.5" r=".89"/>
<circle cx="195.1" cy="105.5" r=".89"/>
<circle cx="192.6" cy="108.1" r=".89"/>
<circle cx="195.1" cy="108.1" r=".89"/>
<circle cx="192.6" cy="110.6" r=".89"/>
<circle cx="195.1" cy="110.6" r=".89"/>
<circle cx="192.6" cy="113.2" r=".89"/>
<circle cx="195.1" cy="113.2" r=".89"/>
</g>
<g fill="#000">
<circle cx="71.5" cy="59" r=".72"/>
<circle cx="71.5" cy="56.4" r=".72"/>
<circle cx="71.5" cy="56.4" r=".55"/>
<circle cx="71.5" cy="59" r=".55"/>
<circle cx="72" cy="46" r="1.82"/>
<circle cx="72" cy="46" r="1.65"/>
<circle cx="83.3" cy="44.4" r=".47"/>
<circle cx="83.3" cy="49.5" r=".47"/>
<circle cx="83.3" cy="54.6" r=".47"/>
<circle cx="83.3" cy="57.1" r=".47"/>
<circle cx="83.3" cy="46.9" r=".47"/>
<circle cx="83.3" cy="59.6" r=".47"/>
<circle cx="83.3" cy="52" r=".47"/>
<circle cx="83.3" cy="54.6" r=".64"/>
<circle cx="83.3" cy="59.6" r=".64"/>
<circle cx="83.3" cy="46.9" r=".64"/>
<circle cx="83.3" cy="52" r=".64"/>
<circle cx="83.3" cy="57.1" r=".64"/>
<circle cx="83.3" cy="44.4" r=".64"/>
<circle cx="83.3" cy="49.5" r=".64"/>
<circle cx="98.5" cy="57.1" r=".47"/>
<circle cx="98.5" cy="44.4" r=".47"/>
<circle cx="98.5" cy="49.5" r=".47"/>
<circle cx="98.5" cy="54.6" r=".47"/>
<circle cx="98.5" cy="59.6" r=".47"/>
<circle cx="98.5" cy="52" r=".47"/>
<circle cx="98.5" cy="46.9" r=".47"/>
<circle cx="98.5" cy="54.6" r=".64"/>
<circle cx="98.5" cy="46.9" r=".64"/>
<circle cx="98.5" cy="59.6" r=".64"/>
<circle cx="98.5" cy="57.1" r=".64"/>
<circle cx="98.5" cy="44.4" r=".64"/>
<circle cx="98.5" cy="52" r=".64"/>
<circle cx="98.5" cy="49.5" r=".64"/>
<circle cx="104.5" cy="57.1" r=".47"/>
<circle cx="104.5" cy="54.6" r=".47"/>
<circle cx="104.5" cy="44.4" r=".47"/>
<circle cx="104.5" cy="49.5" r=".47"/>
<circle cx="104.5" cy="59.6" r=".47"/>
<circle cx="104.5" cy="46.9" r=".47"/>
<circle cx="104.5" cy="52" r=".47"/>
<circle cx="104.5" cy="54.6" r=".64"/>
<circle cx="104.5" cy="46.9" r=".64"/>
<circle cx="104.5" cy="59.6" r=".64"/>
<circle cx="104.5" cy="57.1" r=".64"/>
<circle cx="104.5" cy="52" r=".64"/>
<circle cx="104.5" cy="44.4" r=".64"/>
<circle cx="104.5" cy="49.5" r=".64"/>
<circle cx="119.8" cy="57.1" r=".47"/>
<circle cx="119.8" cy="54.6" r=".47"/>
<circle cx="119.8" cy="44.4" r=".47"/>
<circle cx="119.8" cy="49.5" r=".47"/>
<circle cx="119.8" cy="59.6" r=".47"/>
<circle cx="119.8" cy="46.9" r=".47"/>
<circle cx="119.8" cy="52" r=".47"/>
<circle cx="119.8" cy="54.6" r=".64"/>
<circle cx="119.8" cy="59.6" r=".64"/>
<circle cx="119.8" cy="46.9" r=".64"/>
<circle cx="119.8" cy="52" r=".64"/>
<circle cx="119.8" cy="57.1" r=".64"/>
<circle cx="119.8" cy="44.4" r=".64"/>
<circle cx="119.8" cy="49.5" r=".64"/>
<circle cx="125.5" cy="54.6" r=".47"/>
<circle cx="125.5" cy="44.4" r=".47"/>
<circle cx="125.5" cy="57.1" r=".47"/>
<circle cx="125.5" cy="49.5" r=".47"/>
<circle cx="125.5" cy="46.9" r=".47"/>
<circle cx="125.5" cy="59.6" r=".47"/>
<circle cx="125.5" cy="52" r=".47"/>
<circle cx="125.5" cy="54.6" r=".64"/>
<circle cx="125.5" cy="46.9" r=".64"/>
<circle cx="125.5" cy="59.6" r=".64"/>
<circle cx="125.5" cy="52" r=".64"/>
<circle cx="125.5" cy="57.1" r=".64"/>
<circle cx="125.5" cy="44.4" r=".64"/>
<circle cx="125.5" cy="49.5" r=".64"/>
<circle cx="140.8" cy="49.5" r=".47"/>
<circle cx="140.8" cy="44.4" r=".47"/>
<circle cx="140.8" cy="57.1" r=".47"/>
<circle cx="140.8" cy="54.6" r=".47"/>
<circle cx="140.8" cy="52" r=".47"/>
<circle cx="140.8" cy="59.6" r=".47"/>
<circle cx="140.8" cy="46.9" r=".47"/>
<circle cx="140.8" cy="54.6" r=".64"/>
<circle cx="140.8" cy="46.9" r=".64"/>
<circle cx="140.8" cy="59.6" r=".64"/>
<circle cx="140.8" cy="44.4" r=".64"/>
<circle cx="140.8" cy="57.1" r=".64"/>
<circle cx="140.8" cy="52" r=".64"/>
<circle cx="140.8" cy="49.5" r=".64"/>
<circle cx="146.8" cy="54.6" r=".47"/>
<circle cx="146.8" cy="49.5" r=".47"/>
<circle cx="146.8" cy="57.1" r=".47"/>
<circle cx="146.8" cy="44.4" r=".47"/>
<circle cx="146.8" cy="46.9" r=".47"/>
<circle cx="146.8" cy="52" r=".47"/>
<circle cx="146.8" cy="59.6" r=".47"/>
<circle cx="146.8" cy="54.6" r=".64"/>
<circle cx="146.8" cy="59.6" r=".64"/>
<circle cx="146.8" cy="46.9" r=".64"/>
<circle cx="146.8" cy="57.1" r=".64"/>
<circle cx="146.8" cy="52" r=".64"/>
<circle cx="146.8" cy="44.4" r=".64"/>
<circle cx="146.8" cy="49.5" r=".64"/>
<circle cx="162" cy="57.1" r=".47"/>
<circle cx="162" cy="49.5" r=".47"/>
<circle cx="162" cy="54.6" r=".47"/>
<circle cx="162" cy="44.4" r=".47"/>
<circle cx="162" cy="59.6" r=".47"/>
<circle cx="162" cy="52" r=".47"/>
<circle cx="162" cy="46.9" r=".47"/>
<circle cx="162" cy="54.6" r=".64"/>
<circle cx="162" cy="59.6" r=".64"/>
<circle cx="162" cy="46.9" r=".64"/>
<circle cx="162" cy="57.1" r=".64"/>
<circle cx="162" cy="52" r=".64"/>
<circle cx="162" cy="44.4" r=".64"/>
<circle cx="162" cy="49.5" r=".64"/>
<circle cx="172" cy="46" r="1.82"/>
<circle cx="172" cy="46" r="1.65"/>
<circle cx="191" cy="42.5" r=".8"/>
<circle cx="194.2" cy="44" r="1.14"/>
<circle cx="194.2" cy="51.9" r="1.14"/>
<circle cx="194.2" cy="48" r="1.14"/>
<circle cx="194.2" cy="59.8" r="1.14"/>
<circle cx="194.2" cy="55.8" r="1.14"/>
<circle cx="194.2" cy="59.8" r=".97"/>
<circle cx="194.2" cy="55.8" r=".97"/>
<circle cx="194.2" cy="51.9" r=".97"/>
<circle cx="194.2" cy="48" r=".97"/>
<circle cx="194.2" cy="44" r=".97"/>
<circle cx="71.5" cy="64.1" r=".72"/>
<circle cx="71.5" cy="71.7" r=".72"/>
<circle cx="71.5" cy="76.8" r=".72"/>
<circle cx="71.5" cy="69.1" r=".72"/>
<circle cx="71.5" cy="61.5" r=".72"/>
<circle cx="71.5" cy="74.2" r=".72"/>
<circle cx="71.5" cy="66.6" r=".72"/>
<circle cx="71.5" cy="74.2" r=".55"/>
<circle cx="71.5" cy="61.5" r=".55"/>
<circle cx="71.5" cy="64.1" r=".55"/>
<circle cx="71.5" cy="69.1" r=".55"/>
<circle cx="71.5" cy="76.8" r=".55"/>
<circle cx="71.5" cy="66.6" r=".55"/>
<circle cx="71.5" cy="71.7" r=".55"/>
<circle cx="83.3" cy="67.3" r=".47"/>
<circle cx="83.3" cy="80" r=".47"/>
<circle cx="83.3" cy="62.2" r=".47"/>
<circle cx="83.3" cy="69.8" r=".47"/>
<circle cx="83.3" cy="74.9" r=".47"/>
<circle cx="83.3" cy="72.3" r=".47"/>
<circle cx="83.3" cy="64.7" r=".47"/>
<circle cx="83.3" cy="77.4" r=".47"/>
<circle cx="83.3" cy="67.3" r=".64"/>
<circle cx="83.3" cy="80" r=".64"/>
<circle cx="83.3" cy="72.3" r=".64"/>
<circle cx="83.3" cy="77.4" r=".64"/>
<circle cx="83.3" cy="64.7" r=".64"/>
<circle cx="83.3" cy="69.8" r=".64"/>
<circle cx="83.3" cy="62.2" r=".64"/>
<circle cx="83.3" cy="74.9" r=".64"/>
<circle cx="98.5" cy="80" r=".47"/>
<circle cx="98.5" cy="69.8" r=".47"/>
<circle cx="98.5" cy="74.9" r=".47"/>
<circle cx="98.5" cy="62.2" r=".47"/>
<circle cx="98.5" cy="67.3" r=".47"/>
<circle cx="98.5" cy="72.3" r=".47"/>
<circle cx="98.5" cy="64.7" r=".47"/>
<circle cx="98.5" cy="77.4" r=".47"/>
<circle cx="98.5" cy="80" r=".64"/>
<circle cx="98.5" cy="67.3" r=".64"/>
<circle cx="98.5" cy="72.3" r=".64"/>
<circle cx="98.5" cy="77.4" r=".64"/>
<circle cx="98.5" cy="69.8" r=".64"/>
<circle cx="98.5" cy="64.7" r=".64"/>
<circle cx="98.5" cy="74.9" r=".64"/>
<circle cx="98.5" cy="62.2" r=".64"/>
<circle cx="104.5" cy="80" r=".47"/>
<circle cx="104.5" cy="74.9" r=".47"/>
<circle cx="104.5" cy="62.2" r=".47"/>
<circle cx="104.5" cy="69.8" r=".47"/>
<circle cx="104.5" cy="67.3" r=".47"/>
<circle cx="104.5" cy="72.3" r=".47"/>
<circle cx="104.5" cy="64.7" r=".47"/>
<circle cx="104.5" cy="77.4" r=".47"/>
<circle cx="104.5" cy="67.3" r=".64"/>
<circle cx="104.5" cy="80" r=".64"/>
<circle cx="104.5" cy="72.3" r=".64"/>
<circle cx="104.5" cy="64.7" r=".64"/>
<circle cx="104.5" cy="77.4" r=".64"/>
<circle cx="104.5" cy="69.8" r=".64"/>
<circle cx="104.5" cy="74.9" r=".64"/>
<circle cx="104.5" cy="62.2" r=".64"/>
<circle cx="119.8" cy="74.9" r=".47"/>
<circle cx="119.8" cy="62.2" r=".47"/>
<circle cx="119.8" cy="80" r=".47"/>
<circle cx="119.8" cy="69.8" r=".47"/>
<circle cx="119.8" cy="67.3" r=".47"/>
<circle cx="119.8" cy="72.3" r=".47"/>
<circle cx="119.8" cy="64.7" r=".47"/>
<circle cx="119.8" cy="77.4" r=".47"/>
<circle cx="119.8" cy="67.3" r=".64"/>
<circle cx="119.8" cy="80" r=".64"/>
<circle cx="119.8" cy="72.3" r=".64"/>
<circle cx="119.8" cy="69.8" r=".64"/>
<circle cx="119.8" cy="77.4" r=".64"/>
<circle cx="119.8" cy="64.7" r=".64"/>
<circle cx="119.8" cy="62.2" r=".64"/>
<circle cx="119.8" cy="74.9" r=".64"/>
<circle cx="125.5" cy="74.9" r=".47"/>
<circle cx="125.5" cy="80" r=".47"/>
<circle cx="125.5" cy="62.2" r=".47"/>
<circle cx="125.5" cy="67.3" r=".47"/>
<circle cx="125.5" cy="69.8" r=".47"/>
<circle cx="125.5" cy="77.4" r=".47"/>
<circle cx="125.5" cy="64.7" r=".47"/>
<circle cx="125.5" cy="72.3" r=".47"/>
<circle cx="125.5" cy="80" r=".64"/>
<circle cx="125.5" cy="67.3" r=".64"/>
<circle cx="125.5" cy="72.3" r=".64"/>
<circle cx="125.5" cy="64.7" r=".64"/>
<circle cx="125.5" cy="69.8" r=".64"/>
<circle cx="125.5" cy="77.4" r=".64"/>
<circle cx="125.5" cy="62.2" r=".64"/>
<circle cx="125.5" cy="74.9" r=".64"/>
<circle cx="140.8" cy="67.3" r=".47"/>
<circle cx="140.8" cy="69.8" r=".47"/>
<circle cx="140.8" cy="80" r=".47"/>
<circle cx="140.8" cy="74.9" r=".47"/>
<circle cx="140.8" cy="62.2" r=".47"/>
<circle cx="140.8" cy="77.4" r=".47"/>
<circle cx="140.8" cy="64.7" r=".47"/>
<circle cx="140.8" cy="72.3" r=".47"/>
<circle cx="140.8" cy="67.3" r=".64"/>
<circle cx="140.8" cy="80" r=".64"/>
<circle cx="140.8" cy="72.3" r=".64"/>
<circle cx="140.8" cy="77.4" r=".64"/>
<circle cx="140.8" cy="64.7" r=".64"/>
<circle cx="140.8" cy="69.8" r=".64"/>
<circle cx="140.8" cy="74.9" r=".64"/>
<circle cx="140.8" cy="62.2" r=".64"/>
<circle cx="146.8" cy="74.9" r=".47"/>
<circle cx="146.8" cy="67.3" r=".47"/>
<circle cx="146.8" cy="69.8" r=".47"/>
<circle cx="146.8" cy="80" r=".47"/>
<circle cx="146.8" cy="62.2" r=".47"/>
<circle cx="146.8" cy="72.3" r=".47"/>
<circle cx="146.8" cy="64.7" r=".47"/>
<circle cx="146.8" cy="77.4" r=".47"/>
<circle cx="146.8" cy="67.3" r=".64"/>
<circle cx="146.8" cy="80" r=".64"/>
<circle cx="146.8" cy="72.3" r=".64"/>
<circle cx="146.8" cy="77.4" r=".64"/>
<circle cx="146.8" cy="64.7" r=".64"/>
<circle cx="146.8" cy="69.8" r=".64"/>
<circle cx="146.8" cy="74.9" r=".64"/>
<circle cx="146.8" cy="62.2" r=".64"/>
<circle cx="162" cy="62.2" r=".47"/>
<circle cx="162" cy="80" r=".47"/>
<circle cx="162" cy="74.9" r=".47"/>
<circle cx="162" cy="69.8" r=".47"/>
<circle cx="162" cy="67.3" r=".47"/>
<circle cx="162" cy="77.4" r=".47"/>
<circle cx="162" cy="64.7" r=".47"/>
<circle cx="162" cy="72.3" r=".47"/>
<circle cx="162" cy="80" r=".64"/>
<circle cx="162" cy="67.3" r=".64"/>
<circle cx="162" cy="72.3" r=".64"/>
<circle cx="162" cy="64.7" r=".64"/>
<circle cx="162" cy="69.8" r=".64"/>
<circle cx="162" cy="77.4" r=".64"/>
<circle cx="162" cy="62.2" r=".64"/>
<circle cx="162" cy="74.9" r=".64"/>
<circle cx="192.6" cy="72.5" r=".72"/>
<circle cx="192.6" cy="77.6" r=".72"/>
<circle cx="192.6" cy="75.1" r=".72"/>
<circle cx="192.6" cy="72.5" r=".55"/>
<circle cx="192.6" cy="75.1" r=".55"/>
<circle cx="192.6" cy="77.6" r=".55"/>
<circle cx="194.2" cy="63.8" r="1.14"/>
<circle cx="194.2" cy="63.8" r=".97"/>
<circle cx="195.1" cy="72.5" r=".72"/>
<circle cx="195.1" cy="77.6" r=".72"/>
<circle cx="195.1" cy="75.1" r=".72"/>
<circle cx="195.1" cy="75.1" r=".55"/>
<circle cx="195.1" cy="72.5" r=".55"/>
<circle cx="195.1" cy="77.6" r=".55"/>
<circle cx="72" cy="93" r="1.82"/>
<circle cx="72" cy="93" r="1.65"/>
<circle cx="75.1" cy="86.1" r=".38"/>
<circle cx="75.1" cy="84.2" r=".38"/>
<circle cx="75.1" cy="86.1" r=".55"/>
<circle cx="75.1" cy="84.2" r=".55"/>
<circle cx="83.3" cy="82.5" r=".47"/>
<circle cx="83.3" cy="82.5" r=".64"/>
<circle cx="98.5" cy="82.5" r=".47"/>
<circle cx="98.5" cy="82.5" r=".64"/>
<circle cx="104.5" cy="82.5" r=".47"/>
<circle cx="104.5" cy="82.5" r=".64"/>
<circle cx="119.8" cy="82.5" r=".47"/>
<circle cx="119.8" cy="82.5" r=".64"/>
<circle cx="125.5" cy="82.5" r=".47"/>
<circle cx="125.5" cy="82.5" r=".64"/>
<circle cx="140.8" cy="82.5" r=".47"/>
<circle cx="140.8" cy="82.5" r=".64"/>
<circle cx="146.8" cy="82.5" r=".47"/>
<circle cx="146.8" cy="82.5" r=".64"/>
<circle cx="162" cy="82.5" r=".47"/>
<circle cx="162" cy="82.5" r=".64"/>
<circle cx="192.6" cy="97.9" r=".72"/>
<circle cx="192.6" cy="80.1" r=".72"/>
<circle cx="192.6" cy="85.2" r=".72"/>
<circle cx="192.6" cy="92.8" r=".72"/>
<circle cx="192.6" cy="82.7" r=".72"/>
<circle cx="192.6" cy="95.4" r=".72"/>
<circle cx="192.6" cy="90.3" r=".72"/>
<circle cx="192.6" cy="87.8" r=".72"/>
<circle cx="192.6" cy="95.4" r=".55"/>
<circle cx="192.6" cy="82.7" r=".55"/>
<circle cx="192.6" cy="97.9" r=".55"/>
<circle cx="192.6" cy="92.8" r=".55"/>
<circle cx="192.6" cy="85.2" r=".55"/>
<circle cx="192.6" cy="87.8" r=".55"/>
<circle cx="192.6" cy="80.1" r=".55"/>
<circle cx="192.6" cy="90.3" r=".55"/>
<circle cx="195.1" cy="97.9" r=".72"/>
<circle cx="195.1" cy="80.1" r=".72"/>
<circle cx="195.1" cy="85.2" r=".72"/>
<circle cx="195.1" cy="92.8" r=".72"/>
<circle cx="195.1" cy="82.7" r=".72"/>
<circle cx="195.1" cy="90.3" r=".72"/>
<circle cx="195.1" cy="95.4" r=".72"/>
<circle cx="195.1" cy="87.8" r=".72"/>
<circle cx="195.1" cy="95.4" r=".55"/>
<circle cx="195.1" cy="82.7" r=".55"/>
<circle cx="195.1" cy="97.9" r=".55"/>
<circle cx="195.1" cy="80.1" r=".55"/>
<circle cx="195.1" cy="87.8" r=".55"/>
<circle cx="195.1" cy="85.2" r=".55"/>
<circle cx="195.1" cy="90.3" r=".55"/>
<circle cx="195.1" cy="92.8" r=".55"/>
<circle cx="95" cy="117" r=".47"/>
<circle cx="95" cy="104.3" r=".47"/>
<circle cx="95" cy="111.9" r=".47"/>
<circle cx="95" cy="119.5" r=".47"/>
<circle cx="95" cy="109.3" r=".47"/>
<circle cx="95" cy="106.8" r=".47"/>
<circle cx="95" cy="114.4" r=".47"/>
<circle cx="95" cy="109.3" r=".64"/>
<circle cx="95" cy="114.4" r=".64"/>
<circle cx="95" cy="106.8" r=".64"/>
<circle cx="95" cy="111.9" r=".64"/>
<circle cx="95" cy="119.5" r=".64"/>
<circle cx="95" cy="104.3" r=".64"/>
<circle cx="95" cy="117" r=".64"/>
<circle cx="110.3" cy="111.9" r=".47"/>
<circle cx="110.3" cy="117" r=".47"/>
<circle cx="110.3" cy="104.3" r=".47"/>
<circle cx="110.3" cy="119.5" r=".47"/>
<circle cx="110.3" cy="106.8" r=".47"/>
<circle cx="110.3" cy="109.3" r=".47"/>
<circle cx="110.3" cy="114.4" r=".47"/>
<circle cx="110.3" cy="109.3" r=".64"/>
<circle cx="110.3" cy="114.4" r=".64"/>
<circle cx="110.3" cy="111.9" r=".64"/>
<circle cx="110.3" cy="119.5" r=".64"/>
<circle cx="110.3" cy="106.8" r=".64"/>
<circle cx="110.3" cy="104.3" r=".64"/>
<circle cx="110.3" cy="117" r=".64"/>
<circle cx="115.4" cy="111.9" r=".47"/>
<circle cx="115.4" cy="104.3" r=".47"/>
<circle cx="115.4" cy="117" r=".47"/>
<circle cx="115.4" cy="119.5" r=".47"/>
<circle cx="115.4" cy="109.3" r=".47"/>
<circle cx="115.4" cy="106.8" r=".47"/>
<circle cx="115.4" cy="114.4" r=".47"/>
<circle cx="115.4" cy="109.3" r=".64"/>
<circle cx="115.4" cy="114.4" r=".64"/>
<circle cx="115.4" cy="119.5" r=".64"/>
<circle cx="115.4" cy="106.8" r=".64"/>
<circle cx="115.4" cy="111.9" r=".64"/>
<circle cx="115.4" cy="117" r=".64"/>
<circle cx="115.4" cy="104.3" r=".64"/>
<circle cx="130.6" cy="104.3" r=".47"/>
<circle cx="130.6" cy="111.9" r=".47"/>
<circle cx="130.6" cy="117" r=".47"/>
<circle cx="130.6" cy="119.5" r=".47"/>
<circle cx="130.6" cy="109.3" r=".47"/>
<circle cx="130.6" cy="106.8" r=".47"/>
<circle cx="130.6" cy="114.4" r=".47"/>
<circle cx="130.6" cy="109.3" r=".64"/>
<circle cx="130.6" cy="114.4" r=".64"/>
<circle cx="130.6" cy="111.9" r=".64"/>
<circle cx="130.6" cy="106.8" r=".64"/>
<circle cx="130.6" cy="119.5" r=".64"/>
<circle cx="130.6" cy="104.3" r=".64"/>
<circle cx="130.6" cy="117" r=".64"/>
<circle cx="192.6" cy="105.5" r=".72"/>
<circle cx="192.6" cy="110.6" r=".72"/>
<circle cx="192.6" cy="108.1" r=".72"/>
<circle cx="192.6" cy="103" r=".72"/>
<circle cx="192.6" cy="113.2" r=".72"/>
<circle cx="192.6" cy="100.5" r=".72"/>
<circle cx="192.6" cy="108.1" r=".55"/>
<circle cx="192.6" cy="100.5" r=".55"/>
<circle cx="192.6" cy="110.6" r=".55"/>
<circle cx="192.6" cy="113.2" r=".55"/>
<circle cx="192.6" cy="103" r=".55"/>
<circle cx="192.6" cy="105.5" r=".55"/>
<circle cx="195.1" cy="105.5" r=".72"/>
<circle cx="195.1" cy="110.6" r=".72"/>
<circle cx="195.1" cy="103" r=".72"/>
<circle cx="195.1" cy="108.1" r=".72"/>
<circle cx="195.1" cy="100.5" r=".72"/>
<circle cx="195.1" cy="113.2" r=".72"/>
<circle cx="195.1" cy="108.1" r=".55"/>
<circle cx="195.1" cy="103" r=".55"/>
<circle cx="195.1" cy="105.5" r=".55"/>
<circle cx="195.1" cy="110.6" r=".55"/>
<circle cx="195.1" cy="100.5" r=".55"/>
<circle cx="195.1" cy="113.2" r=".55"/>
<circle cx="95" cy="127.1" r=".47"/>
<circle cx="95" cy="132.2" r=".47"/>
<circle cx="95" cy="122" r=".47"/>
<circle cx="95" cy="124.6" r=".47"/>
<circle cx="95" cy="134.7" r=".47"/>
<circle cx="95" cy="129.7" r=".47"/>
<circle cx="95" cy="137.3" r=".47"/>
<circle cx="95" cy="139.8" r=".47"/>
<circle cx="95" cy="127.1" r=".64"/>
<circle cx="95" cy="137.3" r=".64"/>
<circle cx="95" cy="129.7" r=".64"/>
<circle cx="95" cy="139.8" r=".64"/>
<circle cx="95" cy="124.6" r=".64"/>
<circle cx="95" cy="134.7" r=".64"/>
<circle cx="95" cy="122" r=".64"/>
<circle cx="95" cy="132.2" r=".64"/>
<circle cx="110.3" cy="137.3" r=".47"/>
<circle cx="110.3" cy="132.2" r=".47"/>
<circle cx="110.3" cy="122" r=".47"/>
<circle cx="110.3" cy="129.7" r=".47"/>
<circle cx="110.3" cy="124.6" r=".47"/>
<circle cx="110.3" cy="134.7" r=".47"/>
<circle cx="110.3" cy="127.1" r=".47"/>
<circle cx="110.3" cy="139.8" r=".47"/>
<circle cx="110.3" cy="124.6" r=".64"/>
<circle cx="110.3" cy="137.3" r=".64"/>
<circle cx="110.3" cy="129.7" r=".64"/>
<circle cx="110.3" cy="127.1" r=".64"/>
<circle cx="110.3" cy="139.8" r=".64"/>
<circle cx="110.3" cy="134.7" r=".64"/>
<circle cx="110.3" cy="122" r=".64"/>
<circle cx="110.3" cy="132.2" r=".64"/>
<circle cx="115.4" cy="137.3" r=".47"/>
<circle cx="115.4" cy="132.2" r=".47"/>
<circle cx="115.4" cy="134.7" r=".47"/>
<circle cx="115.4" cy="124.6" r=".47"/>
<circle cx="115.4" cy="129.7" r=".47"/>
<circle cx="115.4" cy="139.8" r=".47"/>
<circle cx="115.4" cy="122" r=".47"/>
<circle cx="115.4" cy="127.1" r=".47"/>
<circle cx="115.4" cy="124.6" r=".64"/>
<circle cx="115.4" cy="129.7" r=".64"/>
<circle cx="115.4" cy="139.8" r=".64"/>
<circle cx="115.4" cy="137.3" r=".64"/>
<circle cx="115.4" cy="127.1" r=".64"/>
<circle cx="115.4" cy="122" r=".64"/>
<circle cx="115.4" cy="134.7" r=".64"/>
<circle cx="115.4" cy="132.2" r=".64"/>
<circle cx="130.6" cy="134.7" r=".47"/>
<circle cx="130.6" cy="132.2" r=".47"/>
<circle cx="130.6" cy="129.7" r=".47"/>
<circle cx="130.6" cy="137.3" r=".47"/>
<circle cx="130.6" cy="124.6" r=".47"/>
<circle cx="130.6" cy="122" r=".47"/>
<circle cx="130.6" cy="139.8" r=".47"/>
<circle cx="130.6" cy="127.1" r=".47"/>
<circle cx="130.6" cy="124.6" r=".64"/>
<circle cx="130.6" cy="137.3" r=".64"/>
<circle cx="130.6" cy="139.8" r=".64"/>
<circle cx="130.6" cy="127.1" r=".64"/>
<circle cx="130.6" cy="129.7" r=".64"/>
<circle cx="130.6" cy="134.7" r=".64"/>
<circle cx="130.6" cy="122" r=".64"/>
<circle cx="130.6" cy="132.2" r=".64"/>
<circle cx="85" cy="145" r="1.82"/>
<circle cx="85" cy="145" r="1.65"/>
<circle cx="95" cy="142.4" r=".47"/>
<circle cx="95" cy="142.4" r=".64"/>
<circle cx="110.3" cy="142.4" r=".47"/>
<circle cx="110.3" cy="142.4" r=".64"/>
<circle cx="115.4" cy="142.4" r=".47"/>
<circle cx="115.4" cy="142.4" r=".64"/>
<circle cx="130.6" cy="142.4" r=".47"/>
<circle cx="130.6" cy="142.4" r=".64"/>
<circle cx="185" cy="145" r="1.82"/>
<circle cx="185" cy="145" r="1.65"/>
</g>
<path d="M92.1 41.2l.3 .2-.1 .1-.4-.1z" fill="#ececec"/>
<path d="M92.1 41.2l.3 .2-.1 .1-.4-.1z" fill="none" stroke="#ececec" stroke-width=".21"/>
<path d="M86.9 44.9l.3 .2-.1 .2-.3-.2z" fill="#ececec"/>
<path d="M86.9 44.9l.3 .2-.1 .2-.3-.2z" fill="none" stroke="#ececec" stroke-width=".21"/>
<path d="M78.4 41.2l.3 .2-.1 .1-.3-.1z" fill="#ececec"/>
<path d="M78.4 41.2l.3 .2-.1 .1-.3-.1z" fill="none" stroke="#ececec" stroke-width=".21"/>
<path d="M77.8 44.5l.3 .2-.1 .1-.3-.1z" fill="#ececec"/>
<path d="M77.8 44.5l.3 .2-.1 .1-.3-.1z" fill="none" stroke="#ececec" stroke-width=".21"/>
<path d="M85.4 46.5l.3 .2-.1 .2-.3-.2z" fill="#ececec"/>
<path d="M85.4 46.5l.3 .2-.1 .2-.3-.2z" fill="none" stroke="#ececec" stroke-width=".21"/>
<path d="M83.4 98.5l.3 .2-.1 .2-.3-.2z" fill="#ececec"/>
<path d="M83.4 98.5l.3 .2-.1 .2-.3-.2z" fill="none" stroke="#ececec" stroke-width=".21"/>
<path d="M89 99.7l.3 .2-.1 .2-.3-.2z" fill="#ececec"/>
<path d="M89 99.7l.3 .2-.1 .2-.3-.2z" fill="none" stroke="#ececec" stroke-width=".21"/>
<path d="M86.8 90.9l.3 .2-.1 .1-.3-.1z" fill="#ececec"/>
<path d="M86.8 90.9l.3 .2-.1 .1-.3-.1z" fill="none" stroke="#ececec" stroke-width=".21"/>
<path d="M75.3 96.7l.3 .2-.1 .2-.3-.2z" fill="#ececec"/>
<path d="M75.3 96.7l.3 .2-.1 .2-.3-.2z" fill="none" stroke="#ececec" stroke-width=".21"/>
<path d="M79.4 97.6l.4 .2-.2 .2-.3-.2z" fill="#ececec"/>
<path d="M79.4 97.6l.4 .2-.2 .2-.3-.2z" fill="none" stroke="#ececec" stroke-width=".21"/>
<path d="M87.1 83.3l.3 .1-.1 .2-.3-.2z" fill="#ececec"/>
<path d="M87.1 83.3l.3 .1-.1 .2-.3-.2z" fill="none" stroke="#ececec" stroke-width=".21"/>
<path d="M79.5 85.7l.3 .2-.1 .2-.3-.2z" fill="#ececec"/>
<path d="M79.5 85.7l.3 .2-.1 .2-.3-.2z" fill="none" stroke="#ececec" stroke-width=".21"/>
<path d="M81.6 88.1l.3 .2-.1 .2-.4-.2z" fill="#ececec"/>
<path d="M81.6 88.1l.3 .2-.1 .2-.4-.2z" fill="none" stroke="#ececec" stroke-width=".21"/>
<path d="M75.2 75.7l.3 .2-.1 .2-.3-.2z" fill="#ececec"/>
<path d="M75.2 75.7l.3 .2-.1 .2-.3-.2z" fill="none" stroke="#ececec" stroke-width=".21"/>
<path d="M73 81.4l.3 .2-.1 .2-.3-.2z" fill="#ececec"/>
<path d="M73 81.4l.3 .2-.1 .2-.3-.2z" fill="none" stroke="#ececec" stroke-width=".21"/>
<path d="M93.8 86.8l.3 .2-.1 .2-.3-.2z" fill="#ececec"/>
<path d="M93.8 86.8l.3 .2-.1 .2-.3-.2z" fill="none" stroke="#ececec" stroke-width=".21"/>
<path d="M84.9 88.3l.3 .2-.1 .2-.3-.2z" fill="#ececec"/>
<path d="M84.9 88.3l.3 .2-.1 .2-.3-.2z" fill="none" stroke="#ececec" stroke-width=".21"/>
<path d="M80.7 69.9l.3 .2-.1 .1-.3-.1z" fill="#ececec"/>
<path d="M80.7 69.9l.3 .2-.1 .1-.3-.1z" fill="none" stroke="#ececec" stroke-width=".21"/>
<path d="M68.2 58.8l.3 .2-.1 .2-.3-.2z" fill="#ececec"/>
<path d="M68.2 58.8l.3 .2-.1 .2-.3-.2z" fill="none" stroke="#ececec" stroke-width=".21"/>
<path d="M68.3 70.9l.3 .2-.1 .2-.3-.2z" fill="#ececec"/>
<path d="M68.3 70.9l.3 .2-.1 .2-.3-.2z" fill="none" stroke="#ececec" stroke-width=".21"/>
<path d="M77.2 57.7l.4 .2-.2 .2-.3-.2z" fill="#ececec"/>
<path d="M77.2 57.7l.4 .2-.2 .2-.3-.2z" fill="none" stroke="#ececec" stroke-width=".21"/>
<path d="M80.8 61.2l.3 .2-.1 .2-.3-.2z" fill="#ececec"/>
<path d="M80.8 61.2l.3 .2-.1 .2-.3-.2z" fill="none" stroke="#ececec" stroke-width=".21"/>
<path d="M85.6 63.6l.3 .2-.1 .2-.3-.2z" fill="#ececec"/>
<path d="M85.6 63.6l.3 .2-.1 .2-.3-.2z" fill="none" stroke="#ececec" stroke-width=".21"/>
<path d="M96 66.9l.3 .2-.1 .2-.4-.2z" fill="#ececec"/>
<path d="M96 66.9l.3 .2-.1 .2-.4-.2z" fill="none" stroke="#ececec" stroke-width=".21"/>
<path d="M90.6 56.4l.3 .2-.1 .2-.3-.2z" fill="#ececec"/>
<path d="M90.6 56.4l.3 .2-.1 .2-.3-.2z" fill="none" stroke="#ececec" stroke-width=".21"/>
<path d="M85.6 55.6l.3 .2-.1 .2-.3-.2z" fill="#ececec"/>
<path d="M85.6 55.6l.3 .2-.1 .2-.3-.2z" fill="none" stroke="#ececec" stroke-width=".21"/>
<path d="M90.5 62l.3 .2-.1 .2-.3-.2z" fill="#ececec"/>
<path d="M90.5 62l.3 .2-.1 .2-.3-.2z" fill="none" stroke="#ececec" stroke-width=".21"/>
<path d="M87.7 66.8l.3 .2-.1 .2-.4-.2z" fill="#ececec"/>
<path d="M87.7 66.8l.3 .2-.1 .2-.4-.2z" fill="none" stroke="#ececec" stroke-width=".21"/>
<path d="M91.3 69.1l.3 .2-.1 .2-.3-.2z" fill="#ececec"/>
<path d="M91.3 69.1l.3 .2-.1 .2-.3-.2z" fill="none" stroke="#ececec" stroke-width=".21"/>
<path d="M67.9 41.6l.3 .2-.1 .2-.3-.2z" fill="#ececec"/>
<path d="M67.9 41.6l.3 .2-.1 .2-.3-.2z" fill="none" stroke="#ececec" stroke-width=".21"/>
<path d="M74.4 51.1l.4 .2-.1 .2-.4-.2z" fill="#ececec"/>
<path d="M74.4 51.1l.4 .2-.1 .2-.4-.2z" fill="none" stroke="#ececec" stroke-width=".21"/>
<path d="M69.4 51.8l.3 .1-.1 .2-.3-.2z" fill="#ececec"/>
<path d="M69.4 51.8l.3 .1-.1 .2-.3-.2z" fill="none" stroke="#ececec" stroke-width=".21"/>
<path d="M76.1 41.8l.4 .2-.2 .2-.3-.2z" fill="#ececec"/>
<path d="M76.1 41.8l.4 .2-.2 .2-.3-.2z" fill="none" stroke="#ececec" stroke-width=".21"/>
<path d="M68.5 48.2l.3 .2-.1 .2-.3-.2z" fill="#ececec"/>
<path d="M68.5 48.2l.3 .2-.1 .2-.3-.2z" fill="none" stroke="#ececec" stroke-width=".21"/>
<path d="M108.2 43.8l.3 .2-.1 .2-.3-.2z" fill="#ececec"/>
<path d="M108.2 43.8l.3 .2-.1 .2-.3-.2z" fill="none" stroke="#ececec" stroke-width=".21"/>
<path d="M94 44.8l.3 .2-.1 .2-.3-.2z" fill="#ececec"/>
<path d="M94 44.8l.3 .2-.1 .2-.3-.2z" fill="none" stroke="#ececec" stroke-width=".21"/>
<path d="M101.4 45.1l.3 .2-.1 .1-.3-.1z" fill="#ececec"/>
<path d="M101.4 45.1l.3 .2-.1 .1-.3-.1z" fill="none" stroke="#ececec" stroke-width=".21"/>
<path d="M95.9 46.4l.3 .2-.1 .2-.3-.2z" fill="#ececec"/>
<path d="M95.9 46.4l.3 .2-.1 .2-.3-.2z" fill="none" stroke="#ececec" stroke-width=".21"/>
<path d="M107.6 47.4l.3 .2-.1 .2-.3-.2z" fill="#ececec"/>
<path d="M107.6 47.4l.3 .2-.1 .2-.3-.2z" fill="none" stroke="#ececec" stroke-width=".21"/>
<path d="M105.8 41.8l.3 .2-.1 .2-.3-.2z" fill="#ececec"/>
<path d="M105.8 41.8l.3 .2-.1 .2-.3-.2z" fill="none" stroke="#ececec" stroke-width=".21"/>
<path d="M122.6 45.1l.3 .2-.1 .1-.3-.1z" fill="#ececec"/>
<path d="M122.6 45.1l.3 .2-.1 .1-.3-.1z" fill="none" stroke="#ececec" stroke-width=".21"/>
<path d="M130 43.6l.3 .2-.1 .2-.3-.2z" fill="#ececec"/>
<path d="M130 43.6l.3 .2-.1 .2-.3-.2z" fill="none" stroke="#ececec" stroke-width=".21"/>
<path d="M127.6 41.7l.3 .2-.1 .2-.3-.2z" fill="#ececec"/>
<path d="M127.6 41.7l.3 .2-.1 .2-.3-.2z" fill="none" stroke="#ececec" stroke-width=".21"/>
<path d="M127.8 46.6l.3 .2-.1 .2-.3-.2z" fill="#ececec"/>
<path d="M127.8 46.6l.3 .2-.1 .2-.3-.2z" fill="none" stroke="#ececec" stroke-width=".21"/>
<path d="M128.1 50.1l.3 .1-.1 .2-.3-.2z" fill="#ececec"/>
<path d="M128.1 50.1l.3 .1-.1 .2-.3-.2z" fill="none" stroke="#ececec" stroke-width=".21"/>
<path d="M128.9 52.6l.3 .2-.1 .2-.3-.2z" fill="#ececec"/>
<path d="M128.9 52.6l.3 .2-.1 .2-.3-.2z" fill="none" stroke="#ececec" stroke-width=".21"/>
<path d="M130 64.5l.3 .2-.1 .2-.3-.2z" fill="#ececec"/>
<path d="M130 64.5l.3 .2-.1 .2-.3-.2z" fill="none" stroke="#ececec" stroke-width=".21"/>
<path d="M122.8 57.9l.3 .1-.1 .2-.3-.2z" fill="#ececec"/>
<path d="M122.8 57.9l.3 .1-.1 .2-.3-.2z" fill="none" stroke="#ececec" stroke-width=".21"/>
<path d="M129 57.1l.3 .2-.1 .2-.3-.2z" fill="#ececec"/>
<path d="M129 57.1l.3 .2-.1 .2-.3-.2z" fill="none" stroke="#ececec" stroke-width=".21"/>
<path d="M127.1 64.5l.3 .2-.1 .2-.3-.2z" fill="#ececec"/>
<path d="M127.1 64.5l.3 .2-.1 .2-.3-.2z" fill="none" stroke="#ececec" stroke-width=".21"/>
<path d="M116.3 44.1l.3 .2-.1 .2-.3-.2z" fill="#ececec"/>
<path d="M116.3 44.1l.3 .2-.1 .2-.3-.2z" fill="none" stroke="#ececec" stroke-width=".21"/>
<path d="M117.5 41.2l.4 .2-.2 .1-.3-.1z" fill="#ececec"/>
<path d="M117.5 41.2l.4 .2-.2 .1-.3-.1z" fill="none" stroke="#ececec" stroke-width=".21"/>
<path d="M115.4 51.1l.3 .2-.1 .2-.3-.2z" fill="#ececec"/>
<path d="M115.4 51.1l.3 .2-.1 .2-.3-.2z" fill="none" stroke="#ececec" stroke-width=".21"/>
<path d="M122.5 50.1l.3 .1-.1 .2-.4-.2z" fill="#ececec"/>
<path d="M122.5 50.1l.3 .1-.1 .2-.4-.2z" fill="none" stroke="#ececec" stroke-width=".21"/>
<path d="M112 49.1l.4 .2-.2 .2-.3-.2z" fill="#ececec"/>
<path d="M112 49.1l.4 .2-.2 .2-.3-.2z" fill="none" stroke="#ececec" stroke-width=".21"/>
<path d="M116.7 47.7l.3 .2-.1 .2-.3-.2z" fill="#ececec"/>
<path d="M116.7 47.7l.3 .2-.1 .2-.3-.2z" fill="none" stroke="#ececec" stroke-width=".21"/>
<path d="M116.9 50.4l.4 .2-.1 .2-.4-.2z" fill="#ececec"/>
<path d="M116.9 50.4l.4 .2-.1 .2-.4-.2z" fill="none" stroke="#ececec" stroke-width=".21"/>
<path d="M113.2 52.9l.3 .2-.1 .2-.3-.2z" fill="#ececec"/>
<path d="M113.2 52.9l.3 .2-.1 .2-.3-.2z" fill="none" stroke="#ececec" stroke-width=".21"/>
<path d="M127.2 75l.3 .2-.1 .2-.3-.2z" fill="#ececec"/>
<path d="M127.2 75l.3 .2-.1 .2-.3-.2z" fill="none" stroke="#ececec" stroke-width=".21"/>
<path d="M112.5 60.9l.4 .2-.1 .2-.4-.2z" fill="#ececec"/>
<path d="M112.5 60.9l.4 .2-.1 .2-.4-.2z" fill="none" stroke="#ececec" stroke-width=".21"/>
<path d="M121.6 64.5l.3 .1-.1 .2-.3-.2z" fill="#ececec"/>
<path d="M121.6 64.5l.3 .1-.1 .2-.3-.2z" fill="none" stroke="#ececec" stroke-width=".21"/>
<path d="M115.3 65.4l.3 .2-.1 .2-.4-.2z" fill="#ececec"/>
<path d="M115.3 65.4l.3 .2-.1 .2-.4-.2z" fill="none" stroke="#ececec" stroke-width=".21"/>
<path d="M117.5 72.4l.3 .2-.1 .2-.4-.2z" fill="#ececec"/>
<path d="M117.5 72.4l.3 .2-.1 .2-.4-.2z" fill="none" stroke="#ececec" stroke-width=".21"/>
<path d="M101.6 83.7l.3 .2-.1 .2-.3-.2z" fill="#ececec"/>
<path d="M101.6 83.7l.3 .2-.1 .2-.3-.2z" fill="none" stroke="#ececec" stroke-width=".21"/>
<path d="M108.7 86.4l.3 .2-.1 .2-.4-.2z" fill="#ececec"/>
<path d="M108.7 86.4l.3 .2-.1 .2-.4-.2z" fill="none" stroke="#ececec" stroke-width=".21"/>
<path d="M114.1 100.9l.3 .1-.1 .2-.3-.2z" fill="#ececec"/>
<path d="M114.1 100.9l.3 .1-.1 .2-.3-.2z" fill="none" stroke="#ececec" stroke-width=".21"/>
<path d="M114.6 92.1l.3 .1-.1 .2-.3-.2z" fill="#ececec"/>
<path d="M114.6 92.1l.3 .1-.1 .2-.3-.2z" fill="none" stroke="#ececec" stroke-width=".21"/>
<path d="M114.7 90.3l.3 .2-.1 .2-.3-.2z" fill="#ececec"/>
<path d="M114.7 90.3l.3 .2-.1 .2-.3-.2z" fill="none" stroke="#ececec" stroke-width=".21"/>
<path d="M104.8 96.5l.3 .2-.1 .2-.4-.2z" fill="#ececec"/>
<path d="M104.8 96.5l.3 .2-.1 .2-.4-.2z" fill="none" stroke="#ececec" stroke-width=".21"/>
<path d="M100.8 96.2l.3 .2-.1 .2-.3-.2z" fill="#ececec"/>
<path d="M100.8 96.2l.3 .2-.1 .2-.3-.2z" fill="none" stroke="#ececec" stroke-width=".21"/>
<path d="M104.5 103.9l.3 .2-.1 .2-.3-.2z" fill="#ececec"/>
<path d="M104.5 103.9l.3 .2-.1 .2-.3-.2z" fill="none" stroke="#ececec" stroke-width=".21"/>
<path d="M97.1 96.2l.3 .2-.1 .2-.4-.2z" fill="#ececec"/>
<path d="M97.1 96.2l.3 .2-.1 .2-.4-.2z" fill="none" stroke="#ececec" stroke-width=".21"/>
<path d="M95.1 101.2l.3 .2-.1 .2-.3-.2z" fill="#ececec"/>
<path d="M95.1 101.2l.3 .2-.1 .2-.3-.2z" fill="none" stroke="#ececec" stroke-width=".21"/>
<path d="M106.5 105.4l.3 .2-.1 .2-.3-.2z" fill="#ececec"/>
<path d="M106.5 105.4l.3 .2-.1 .2-.3-.2z" fill="none" stroke="#ececec" stroke-width=".21"/>
<path d="M104 100.5l.3 .2-.1 .2-.3-.2z" fill="#ececec"/>
<path d="M104 100.5l.3 .2-.1 .2-.3-.2z" fill="none" stroke="#ececec" stroke-width=".21"/>
<path d="M99.7 90l.3 .2-.1 .2-.3-.2z" fill="#ececec"/>
<path d="M99.7 90l.3 .2-.1 .2-.3-.2z" fill="none" stroke="#ececec" stroke-width=".21"/>
<path d="M98.3 86.2l.3 .2-.1 .2-.3-.2z" fill="#ececec"/>
<path d="M98.3 86.2l.3 .2-.1 .2-.3-.2z" fill="none" stroke="#ececec" stroke-width=".21"/>
<path d="M93.2 90l.3 .2-.1 .2-.4-.2z" fill="#ececec"/>
<path d="M93.2 90l.3 .2-.1 .2-.4-.2z" fill="none" stroke="#ececec" stroke-width=".21"/>
<path d="M86 86.6l.3 .1-.1 .2-.3-.2z" fill="#ececec"/>
<path d="M86 86.6l.3 .1-.1 .2-.3-.2z" fill="none" stroke="#ececec" stroke-width=".21"/>
<path d="M85.5 92.9l.3 .2-.1 .2-.4-.2z" fill="#ececec"/>
<path d="M85.5 92.9l.3 .2-.1 .2-.4-.2z" fill="none" stroke="#ececec" stroke-width=".21"/>
<path d="M97.4 106.6l.3 .2-.1 .2-.3-.2z" fill="#ececec"/>
<path d="M97.4 106.6l.3 .2-.1 .2-.3-.2z" fill="none" stroke="#ececec" stroke-width=".21"/>
<path d="M103.5 111.3l.3 .2-.1 .2-.3-.2z" fill="#ececec"/>
<path d="M103.5 111.3l.3 .2-.1 .2-.3-.2z" fill="none" stroke="#ececec" stroke-width=".21"/>
<path d="M103.4 121.5l.3 .2-.1 .2-.3-.2z" fill="#ececec"/>
<path d="M103.4 121.5l.3 .2-.1 .2-.3-.2z" fill="none" stroke="#ececec" stroke-width=".21"/>
<path d="M103.5 107.3l.3 .2-.1 .2-.3-.2z" fill="#ececec"/>
<path d="M103.5 107.3l.3 .2-.1 .2-.3-.2z" fill="none" stroke="#ececec" stroke-width=".21"/>
<path d="M107.6 112.8l.3 .2-.1 .2-.3-.2z" fill="#ececec"/>
<path d="M107.6 112.8l.3 .2-.1 .2-.3-.2z" fill="none" stroke="#ececec" stroke-width=".21"/>
<path d="M105.9 114.2l.4 .1-.2 .2-.3-.2z" fill="#ececec"/>
<path d="M105.9 114.2l.4 .1-.2 .2-.3-.2z" fill="none" stroke="#ececec" stroke-width=".21"/>
<path d="M111.7 109.5l.3 .2-.1 .2-.3-.2z" fill="#ececec"/>
<path d="M111.7 109.5l.3 .2-.1 .2-.3-.2z" fill="none" stroke="#ececec" stroke-width=".21"/>
<path d="M125.7 85.6l.3 .2-.1 .2-.3-.2z" fill="#ececec"/>
<path d="M125.7 85.6l.3 .2-.1 .2-.3-.2z" fill="none" stroke="#ececec" stroke-width=".21"/>
<path d="M125.2 94.4l.4 .2-.1 .2-.4-.2z" fill="#ececec"/>
<path d="M125.2 94.4l.4 .2-.1 .2-.4-.2z" fill="none" stroke="#ececec" stroke-width=".21"/>
<path d="M115.3 93.8l.3 .2-.1 .2-.4-.2z" fill="#ececec"/>
<path d="M115.3 93.8l.3 .2-.1 .2-.4-.2z" fill="none" stroke="#ececec" stroke-width=".21"/>
<path d="M119.9 94.4l.3 .2-.1 .2-.3-.2z" fill="#ececec"/>
<path d="M119.9 94.4l.3 .2-.1 .2-.3-.2z" fill="none" stroke="#ececec" stroke-width=".21"/>
<path d="M116.9 90.3l.3 .2-.1 .2-.3-.2z" fill="#ececec"/>
<path d="M116.9 90.3l.3 .2-.1 .2-.3-.2z" fill="none" stroke="#ececec" stroke-width=".21"/>
<path d="M116.3 91.8l.3 .2-.1 .2-.3-.2z" fill="#ececec"/>
<path d="M116.3 91.8l.3 .2-.1 .2-.3-.2z" fill="none" stroke="#ececec" stroke-width=".21"/>
<path d="M118.4 85.6l.3 .2-.1 .2-.3-.2z" fill="#ececec"/>
<path d="M118.4 85.6l.3 .2-.1 .2-.3-.2z" fill="none" stroke="#ececec" stroke-width=".21"/>
<path d="M122 82.5l.3 .2-.1 .2-.3-.2z" fill="#ececec"/>
<path d="M122 82.5l.3 .2-.1 .2-.3-.2z" fill="none" stroke="#ececec" stroke-width=".21"/>
<path d="M125.4 101.1l.3 .2-.1 .2-.3-.2z" fill="#ececec"/>
<path d="M125.4 101.1l.3 .2-.1 .2-.3-.2z" fill="none" stroke="#ececec" stroke-width=".21"/>
<path d="M127.8 93.9l.3 .2-.1 .2-.3-.2z" fill="#ececec"/>
<path d="M127.8 93.9l.3 .2-.1 .2-.3-.2z" fill="none" stroke="#ececec" stroke-width=".21"/>
<path d="M126.9 92.6l.3 .2-.1 .2-.4-.2z" fill="#ececec"/>
<path d="M126.9 92.6l.3 .2-.1 .2-.4-.2z" fill="none" stroke="#ececec" stroke-width=".21"/>
<path d="M133.6 84.8l.3 .2-.1 .2-.3-.2z" fill="#ececec"/>
<path d="M133.6 84.8l.3 .2-.1 .2-.3-.2z" fill="none" stroke="#ececec" stroke-width=".21"/>
<path d="M134.1 79.8l.3 .2-.1 .2-.4-.2z" fill="#ececec"/>
<path d="M134.1 79.8l.3 .2-.1 .2-.4-.2z" fill="none" stroke="#ececec" stroke-width=".21"/>
<path d="M133.5 74.4l.4 .1-.2 .2-.3-.2z" fill="#ececec"/>
<path d="M133.5 74.4l.4 .1-.2 .2-.3-.2z" fill="none" stroke="#ececec" stroke-width=".21"/>
<path d="M138.5 65l.3 .2-.1 .2-.4-.2z" fill="#ececec"/>
<path d="M138.5 65l.3 .2-.1 .2-.4-.2z" fill="none" stroke="#ececec" stroke-width=".21"/>
<path d="M133.2 64.5l.3 .2-.1 .2-.3-.2z" fill="#ececec"/>
<path d="M133.2 64.5l.3 .2-.1 .2-.3-.2z" fill="none" stroke="#ececec" stroke-width=".21"/>
<path d="M133.7 82.2l.3 .1-.1 .2-.3-.2z" fill="#ececec"/>
<path d="M133.7 82.2l.3 .1-.1 .2-.3-.2z" fill="none" stroke="#ececec" stroke-width=".21"/>
<path d="M121.9 71.5l.3 .2-.1 .2-.3-.2z" fill="#ececec"/>
<path d="M121.9 71.5l.3 .2-.1 .2-.3-.2z" fill="none" stroke="#ececec" stroke-width=".21"/>
<path d="M128.9 75l.3 .2-.1 .2-.3-.2z" fill="#ececec"/>
<path d="M128.9 75l.3 .2-.1 .2-.3-.2z" fill="none" stroke="#ececec" stroke-width=".21"/>
<path d="M121.2 105.3l.3 .2-.1 .2-.3-.2z" fill="#ececec"/>
<path d="M121.2 105.3l.3 .2-.1 .2-.3-.2z" fill="none" stroke="#ececec" stroke-width=".21"/>
<path d="M132.6 105.1l.3 .2-.1 .2-.3-.2z" fill="#ececec"/>
<path d="M132.6 105.1l.3 .2-.1 .2-.3-.2z" fill="none" stroke="#ececec" stroke-width=".21"/>
<path d="M127.1 106.4l.3 .2-.1 .2-.3-.2z" fill="#ececec"/>
<path d="M127.1 106.4l.3 .2-.1 .2-.3-.2z" fill="none" stroke="#ececec" stroke-width=".21"/>
<path d="M131.4 99.1l.3 .2-.1 .2-.3-.2z" fill="#ececec"/>
<path d="M131.4 99.1l.3 .2-.1 .2-.3-.2z" fill="none" stroke="#ececec" stroke-width=".21"/>
<path d="M132.4 107.2l.4 .2-.2 .2-.3-.2z" fill="#ececec"/>
<path d="M132.4 107.2l.4 .2-.2 .2-.3-.2z" fill="none" stroke="#ececec" stroke-width=".21"/>
<path d="M137.5 107.3l.3 .2-.1 .2-.3-.2z" fill="#ececec"/>
<path d="M137.5 107.3l.3 .2-.1 .2-.3-.2z" fill="none" stroke="#ececec" stroke-width=".21"/>
<path d="M137 106.4l.3 .2-.1 .1-.3-.1z" fill="#ececec"/>
<path d="M137 106.4l.3 .2-.1 .1-.3-.1z" fill="none" stroke="#ececec" stroke-width=".21"/>
<path d="M135.2 105.5l.4 .2-.2 .2-.3-.2z" fill="#ececec"/>
<path d="M135.2 105.5l.4 .2-.2 .2-.3-.2z" fill="none" stroke="#ececec" stroke-width=".21"/>
<path d="M134.4 104.8l.3 .2-.1 .2-.3-.2z" fill="#ececec"/>
<path d="M134.4 104.8l.3 .2-.1 .2-.3-.2z" fill="none" stroke="#ececec" stroke-width=".21"/>
<path d="M137 112.8l.3 .2-.1 .2-.3-.2z" fill="#ececec"/>
<path d="M137 112.8l.3 .2-.1 .2-.3-.2z" fill="none" stroke="#ececec" stroke-width=".21"/>
<path d="M135.9 106.4l.3 .2-.1 .1-.3-.1z" fill="#ececec"/>
<path d="M135.9 106.4l.3 .2-.1 .1-.3-.1z" fill="none" stroke="#ececec" stroke-width=".21"/>
<path d="M135.7 118.1l.3 .2-.1 .2-.3-.2z" fill="#ececec"/>
<path d="M135.7 118.1l.3 .2-.1 .2-.3-.2z" fill="none" stroke="#ececec" stroke-width=".21"/>
<path d="M133.6 94.2l.3 .2-.1 .1-.3-.1z" fill="#ececec"/>
<path d="M133.6 94.2l.3 .2-.1 .1-.3-.1z" fill="none" stroke="#ececec" stroke-width=".21"/>
<path d="M132.6 100.4l.3 .1-.1 .2-.3-.2z" fill="#ececec"/>
<path d="M132.6 100.4l.3 .1-.1 .2-.3-.2z" fill="none" stroke="#ececec" stroke-width=".21"/>
<path d="M133.4 91.2l.3 .2-.1 .2-.3-.2z" fill="#ececec"/>
<path d="M133.4 91.2l.3 .2-.1 .2-.3-.2z" fill="none" stroke="#ececec" stroke-width=".21"/>
<path d="M134 89.7l.3 .2-.1 .2-.3-.2z" fill="#ececec"/>
<path d="M134 89.7l.3 .2-.1 .2-.3-.2z" fill="none" stroke="#ececec" stroke-width=".21"/>
<path d="M137.4 98.1l.4 .2-.2 .1-.3-.1z" fill="#ececec"/>
<path d="M137.4 98.1l.4 .2-.2 .1-.3-.1z" fill="none" stroke="#ececec" stroke-width=".21"/>
<path d="M100.3 146.2l.3 .2-.1 .2-.3-.2z" fill="#ececec"/>
<path d="M100.3 146.2l.3 .2-.1 .2-.3-.2z" fill="none" stroke="#ececec" stroke-width=".21"/>
<path d="M102.6 147.9l.4 .2-.2 .2-.3-.2z" fill="#ececec"/>
<path d="M102.6 147.9l.4 .2-.2 .2-.3-.2z" fill="none" stroke="#ececec" stroke-width=".21"/>
<path d="M101.9 142.3l.3 .2-.1 .2-.3-.2z" fill="#ececec"/>
<path d="M101.9 142.3l.3 .2-.1 .2-.3-.2z" fill="none" stroke="#ececec" stroke-width=".21"/>
<path d="M97.1 141.5l.4 .2-.2 .2-.3-.2z" fill="#ececec"/>
<path d="M97.1 141.5l.4 .2-.2 .2-.3-.2z" fill="none" stroke="#ececec" stroke-width=".21"/>
<path d="M103.6 145.3l.3 .2-.1 .2-.3-.2z" fill="#ececec"/>
<path d="M103.6 145.3l.3 .2-.1 .2-.3-.2z" fill="none" stroke="#ececec" stroke-width=".21"/>
<path d="M90.4 137.5l.4 .2-.1 .2-.4-.2z" fill="#ececec"/>
<path d="M90.4 137.5l.4 .2-.1 .2-.4-.2z" fill="none" stroke="#ececec" stroke-width=".21"/>
<path d="M91.6 147.9l.3 .1-.1 .2-.3-.2z" fill="#ececec"/>
<path d="M91.6 147.9l.3 .1-.1 .2-.3-.2z" fill="none" stroke="#ececec" stroke-width=".21"/>
<path d="M90.2 142.9l.3 .1-.1 .2-.3-.2z" fill="#ececec"/>
<path d="M90.2 142.9l.3 .1-.1 .2-.3-.2z" fill="none" stroke="#ececec" stroke-width=".21"/>
<path d="M82.2 138.3l.3 .2-.1 .2-.3-.2z" fill="#ececec"/>
<path d="M82.2 138.3l.3 .2-.1 .2-.3-.2z" fill="none" stroke="#ececec" stroke-width=".21"/>
<path d="M112.1 142.3l.3 .2-.1 .2-.3-.2z" fill="#ececec"/>
<path d="M112.1 142.3l.3 .2-.1 .2-.3-.2z" fill="none" stroke="#ececec" stroke-width=".21"/>
<path d="M117.5 142.4l.3 .2-.1 .2-.4-.2z" fill="#ececec"/>
<path d="M117.5 142.4l.3 .2-.1 .2-.4-.2z" fill="none" stroke="#ececec" stroke-width=".21"/>
<path d="M120.5 136.8l.3 .2-.1 .2-.3-.2z" fill="#ececec"/>
<path d="M120.5 136.8l.3 .2-.1 .2-.3-.2z" fill="none" stroke="#ececec" stroke-width=".21"/>
<path d="M118 134.5l.3 .2-.1 .2-.3-.2z" fill="#ececec"/>
<path d="M118 134.5l.3 .2-.1 .2-.3-.2z" fill="none" stroke="#ececec" stroke-width=".21"/>
<path d="M123 138.5l.4 .1-.2 .2-.3-.2z" fill="#ececec"/>
<path d="M123 138.5l.4 .1-.2 .2-.3-.2z" fill="none" stroke="#ececec" stroke-width=".21"/>
<path d="M112.1 145.5l.3 .2-.1 .2-.3-.2z" fill="#ececec"/>
<path d="M112.1 145.5l.3 .2-.1 .2-.3-.2z" fill="none" stroke="#ececec" stroke-width=".21"/>
<path d="M125.3 137.2l.3 .2-.1 .2-.3-.2z" fill="#ececec"/>
<path d="M125.3 137.2l.3 .2-.1 .2-.3-.2z" fill="none" stroke="#ececec" stroke-width=".21"/>
<path d="M137.1 144l.3 .1-.1 .2-.3-.2z" fill="#ececec"/>
<path d="M137.1 144l.3 .1-.1 .2-.3-.2z" fill="none" stroke="#ececec" stroke-width=".21"/>
<path d="M128.7 134.6l.3 .1-.1 .2-.3-.2z" fill="#ececec"/>
<path d="M128.7 134.6l.3 .1-.1 .2-.3-.2z" fill="none" stroke="#ececec" stroke-width=".21"/>
<path d="M129.6 144.4l.4 .2-.1 .2-.4-.2z" fill="#ececec"/>
<path d="M129.6 144.4l.4 .2-.1 .2-.4-.2z" fill="none" stroke="#ececec" stroke-width=".21"/>
<path d="M133.2 144.2l.3 .2-.1 .2-.3-.2z" fill="#ececec"/>
<path d="M133.2 144.2l.3 .2-.1 .2-.3-.2z" fill="none" stroke="#ececec" stroke-width=".21"/>
<path d="M136.3 140.7l.3 .2-.1 .2-.4-.2z" fill="#ececec"/>
<path d="M136.3 140.7l.3 .2-.1 .2-.4-.2z" fill="none" stroke="#ececec" stroke-width=".21"/>
<path d="M123.3 130.1l.3 .2-.1 .1-.3-.1z" fill="#ececec"/>
<path d="M123.3 130.1l.3 .2-.1 .1-.3-.1z" fill="none" stroke="#ececec" stroke-width=".21"/>
<path d="M134.7 132.2l.3 .2-.1 .2-.3-.2z" fill="#ececec"/>
<path d="M134.7 132.2l.3 .2-.1 .2-.3-.2z" fill="none" stroke="#ececec" stroke-width=".21"/>
<path d="M133.7 122.1l.3 .2-.1 .2-.3-.2z" fill="#ececec"/>
<path d="M133.7 122.1l.3 .2-.1 .2-.3-.2z" fill="none" stroke="#ececec" stroke-width=".21"/>
<path d="M131.8 121.8l.3 .2-.1 .2-.3-.2z" fill="#ececec"/>
<path d="M131.8 121.8l.3 .2-.1 .2-.3-.2z" fill="none" stroke="#ececec" stroke-width=".21"/>
<path d="M135.3 121.9l.3 .1-.1 .2-.3-.2z" fill="#ececec"/>
<path d="M135.3 121.9l.3 .1-.1 .2-.3-.2z" fill="none" stroke="#ececec" stroke-width=".21"/>
<path d="M123.2 128l.3 .2-.1 .2-.3-.2z" fill="#ececec"/>
<path d="M123.2 128l.3 .2-.1 .2-.3-.2z" fill="none" stroke="#ececec" stroke-width=".21"/>
<path d="M122.9 126.4l.3 .2-.1 .2-.3-.2z" fill="#ececec"/>
<path d="M122.9 126.4l.3 .2-.1 .2-.3-.2z" fill="none" stroke="#ececec" stroke-width=".21"/>
<path d="M103.5 133.7l.3 .2-.1 .2-.3-.2z" fill="#ececec"/>
<path d="M103.5 133.7l.3 .2-.1 .2-.3-.2z" fill="none" stroke="#ececec" stroke-width=".21"/>
<path d="M105.6 140.7l.3 .2-.1 .2-.3-.2z" fill="#ececec"/>
<path d="M105.6 140.7l.3 .2-.1 .2-.3-.2z" fill="none" stroke="#ececec" stroke-width=".21"/>
<path d="M106.5 142.1l.3 .2-.1 .2-.3-.2z" fill="#ececec"/>
<path d="M106.5 142.1l.3 .2-.1 .2-.3-.2z" fill="none" stroke="#ececec" stroke-width=".21"/>
<path d="M102 140.5l.4 .2-.1 .2-.4-.2z" fill="#ececec"/>
<path d="M102 140.5l.4 .2-.1 .2-.4-.2z" fill="none" stroke="#ececec" stroke-width=".21"/>
<path d="M127 84.5l.3 .2-.1 .2-.3-.2z" fill="#ececec"/>
<path d="M127 84.5l.3 .2-.1 .2-.3-.2z" fill="none" stroke="#ececec" stroke-width=".21"/>
<path d="M121.4 96.1l.3 .2-.1 .2-.4-.2z" fill="#ececec"/>
<path d="M121.4 96.1l.3 .2-.1 .2-.4-.2z" fill="none" stroke="#ececec" stroke-width=".21"/>
<path d="M128.9 96.4l.3 .2-.1 .2-.3-.2z" fill="#ececec"/>
<path d="M128.9 96.4l.3 .2-.1 .2-.3-.2z" fill="none" stroke="#ececec" stroke-width=".21"/>
<path d="M129.9 77.9l.3 .2-.1 .2-.3-.2z" fill="#ececec"/>
<path d="M129.9 77.9l.3 .2-.1 .2-.3-.2z" fill="none" stroke="#ececec" stroke-width=".21"/>
<path d="M129.5 84.5l.3 .2-.1 .2-.3-.2z" fill="#ececec"/>
<path d="M129.5 84.5l.3 .2-.1 .2-.3-.2z" fill="none" stroke="#ececec" stroke-width=".21"/>
<path d="M109.8 99.3l.4 .2-.2 .2-.3-.2z" fill="#ececec"/>
<path d="M109.8 99.3l.4 .2-.2 .2-.3-.2z" fill="none" stroke="#ececec" stroke-width=".21"/>
<path d="M98.7 92.4l.3 .2-.1 .2-.3-.2z" fill="#ececec"/>
<path d="M98.7 92.4l.3 .2-.1 .2-.3-.2z" fill="none" stroke="#ececec" stroke-width=".21"/>
<path d="M110.4 93.2l.3 .1-.1 .2-.3-.2z" fill="#ececec"/>
<path d="M110.4 93.2l.3 .1-.1 .2-.3-.2z" fill="none" stroke="#ececec" stroke-width=".21"/>
<path d="M109.6 91.2l.3 .2-.1 .2-.3-.2z" fill="#ececec"/>
<path d="M109.6 91.2l.3 .2-.1 .2-.3-.2z" fill="none" stroke="#ececec" stroke-width=".21"/>
<path d="M115.1 96l.3 .2-.1 .2-.3-.2z" fill="#ececec"/>
<path d="M115.1 96l.3 .2-.1 .2-.3-.2z" fill="none" stroke="#ececec" stroke-width=".21"/>
<path d="M109.2 92.6l.3 .2-.1 .2-.3-.2z" fill="#ececec"/>
<path d="M109.2 92.6l.3 .2-.1 .2-.3-.2z" fill="none" stroke="#ececec" stroke-width=".21"/>
<path d="M111.3 95.3l.3 .2-.1 .1-.3-.1z" fill="#ececec"/>
<path d="M111.3 95.3l.3 .2-.1 .1-.3-.1z" fill="none" stroke="#ececec" stroke-width=".21"/>
<path d="M109.6 94.3l.3 .1-.1 .2-.3-.2z" fill="#ececec"/>
<path d="M109.6 94.3l.3 .1-.1 .2-.3-.2z" fill="none" stroke="#ececec" stroke-width=".21"/>
<path d="M112.1 74.9l.3 .2-.1 .1-.3-.1z" fill="#ececec"/>
<path d="M112.1 74.9l.3 .2-.1 .1-.3-.1z" fill="none" stroke="#ececec" stroke-width=".21"/>
<path d="M113.4 82.8l.3 .2-.1 .2-.3-.2z" fill="#ececec"/>
<path d="M113.4 82.8l.3 .2-.1 .2-.3-.2z" fill="none" stroke="#ececec" stroke-width=".21"/>
<path d="M107.5 87.7l.3 .1-.1 .2-.3-.2z" fill="#ececec"/>
<path d="M107.5 87.7l.3 .1-.1 .2-.3-.2z" fill="none" stroke="#ececec" stroke-width=".21"/>
<path d="M110.7 90.1l.3 .2-.1 .2-.3-.2z" fill="#ececec"/>
<path d="M110.7 90.1l.3 .2-.1 .2-.3-.2z" fill="none" stroke="#ececec" stroke-width=".21"/>
<path d="M111.8 88.5l.3 .2-.1 .2-.3-.2z" fill="#ececec"/>
<path d="M111.8 88.5l.3 .2-.1 .2-.3-.2z" fill="none" stroke="#ececec" stroke-width=".21"/>
<path d="M96.3 72l.3 .2-.1 .2-.3-.2z" fill="#ececec"/>
<path d="M96.3 72l.3 .2-.1 .2-.3-.2z" fill="none" stroke="#ececec" stroke-width=".21"/>
<path d="M112.4 67l.3 .2-.1 .2-.3-.2z" fill="#ececec"/>
<path d="M112.4 67l.3 .2-.1 .2-.3-.2z" fill="none" stroke="#ececec" stroke-width=".21"/>
<path d="M112.8 71.4l.3 .2-.1 .2-.3-.2z" fill="#ececec"/>
<path d="M112.8 71.4l.3 .2-.1 .2-.3-.2z" fill="none" stroke="#ececec" stroke-width=".21"/>
<path d="M106.3 72.4l.3 .2-.1 .2-.3-.2z" fill="#ececec"/>
<path d="M106.3 72.4l.3 .2-.1 .2-.3-.2z" fill="none" stroke="#ececec" stroke-width=".21"/>
<path d="M196.2 91.5l.3 .2-.1 .1-.3-.1z" fill="#ececec"/>
<path d="M196.2 91.5l.3 .2-.1 .1-.3-.1z" fill="none" stroke="#ececec" stroke-width=".21"/>
<path d="M190.5 91.6l.3 .2-.1 .2-.3-.2z" fill="#ececec"/>
<path d="M190.5 91.6l.3 .2-.1 .2-.3-.2z" fill="none" stroke="#ececec" stroke-width=".21"/>
<path d="M190.2 99.3l.3 .1-.1 .2-.3-.2z" fill="#ececec"/>
<path d="M190.2 99.3l.3 .1-.1 .2-.3-.2z" fill="none" stroke="#ececec" stroke-width=".21"/>
<path d="M187.7 91.8l.3 .2-.1 .2-.3-.2z" fill="#ececec"/>
<path d="M187.7 91.8l.3 .2-.1 .2-.3-.2z" fill="none" stroke="#ececec" stroke-width=".21"/>
<path d="M186.4 88.9l.3 .2-.1 .2-.3-.2z" fill="#ececec"/>
<path d="M186.4 88.9l.3 .2-.1 .2-.3-.2z" fill="none" stroke="#ececec" stroke-width=".21"/>
<path d="M178.3 85.3l.3 .2-.1 .2-.3-.2z" fill="#ececec"/>
<path d="M178.3 85.3l.3 .2-.1 .2-.3-.2z" fill="none" stroke="#ececec" stroke-width=".21"/>
<path d="M179.9 88.9l.3 .2-.1 .2-.4-.2z" fill="#ececec"/>
<path d="M179.9 88.9l.3 .2-.1 .2-.4-.2z" fill="none" stroke="#ececec" stroke-width=".21"/>
<path d="M188.2 86.7l.3 .2-.1 .2-.4-.2z" fill="#ececec"/>
<path d="M188.2 86.7l.3 .2-.1 .2-.4-.2z" fill="none" stroke="#ececec" stroke-width=".21"/>
<path d="M185.9 85.8l.3 .2-.1 .2-.3-.2z" fill="#ececec"/>
<path d="M185.9 85.8l.3 .2-.1 .2-.3-.2z" fill="none" stroke="#ececec" stroke-width=".21"/>
<path d="M174.6 91.6l.3 .2-.1 .2-.3-.2z" fill="#ececec"/>
<path d="M174.6 91.6l.3 .2-.1 .2-.3-.2z" fill="none" stroke="#ececec" stroke-width=".21"/>
<path d="M176.7 87.3l.3 .2-.1 .2-.3-.2z" fill="#ececec"/>
<path d="M176.7 87.3l.3 .2-.1 .2-.3-.2z" fill="none" stroke="#ececec" stroke-width=".21"/>
<path d="M174.3 88.8l.3 .2-.1 .2-.3-.2z" fill="#ececec"/>
<path d="M174.3 88.8l.3 .2-.1 .2-.3-.2z" fill="none" stroke="#ececec" stroke-width=".21"/>
<path d="M178.9 91.1l.3 .2-.1 .2-.3-.2z" fill="#ececec"/>
<path d="M178.9 91.1l.3 .2-.1 .2-.3-.2z" fill="none" stroke="#ececec" stroke-width=".21"/>
<path d="M173.9 97.7l.3 .2-.1 .2-.3-.2z" fill="#ececec"/>
<path d="M173.9 97.7l.3 .2-.1 .2-.3-.2z" fill="none" stroke="#ececec" stroke-width=".21"/>
<path d="M176 97.7l.3 .2-.1 .2-.3-.2z" fill="#ececec"/>
<path d="M176 97.7l.3 .2-.1 .2-.3-.2z" fill="none" stroke="#ececec" stroke-width=".21"/>
<path d="M170.1 95.7l.3 .2-.1 .2-.3-.2z" fill="#ececec"/>
<path d="M170.1 95.7l.3 .2-.1 .2-.3-.2z" fill="none" stroke="#ececec" stroke-width=".21"/>
<path d="M173.8 103.5l.4 .2-.2 .2-.3-.2z" fill="#ececec"/>
<path d="M173.8 103.5l.4 .2-.2 .2-.3-.2z" fill="none" stroke="#ececec" stroke-width=".21"/>
<path d="M174.3 104.9l.3 .2-.1 .2-.3-.2z" fill="#ececec"/>
<path d="M174.3 104.9l.3 .2-.1 .2-.3-.2z" fill="none" stroke="#ececec" stroke-width=".21"/>
<path d="M170 105.6l.3 .2-.1 .2-.3-.2z" fill="#ececec"/>
<path d="M170 105.6l.3 .2-.1 .2-.3-.2z" fill="none" stroke="#ececec" stroke-width=".21"/>
<path d="M170 108l.3 .2-.1 .1-.3-.1z" fill="#ececec"/>
<path d="M170 108l.3 .2-.1 .1-.3-.1z" fill="none" stroke="#ececec" stroke-width=".21"/>
<path d="M177.7 104.8l.3 .1-.1 .2-.4-.2z" fill="#ececec"/>
<path d="M177.7 104.8l.3 .1-.1 .2-.4-.2z" fill="none" stroke="#ececec" stroke-width=".21"/>
<path d="M168.4 107.6l.3 .2-.1 .2-.3-.2z" fill="#ececec"/>
<path d="M168.4 107.6l.3 .2-.1 .2-.3-.2z" fill="none" stroke="#ececec" stroke-width=".21"/>
<path d="M181.2 94.4l.3 .2-.1 .2-.3-.2z" fill="#ececec"/>
<path d="M181.2 94.4l.3 .2-.1 .2-.3-.2z" fill="none" stroke="#ececec" stroke-width=".21"/>
<path d="M187.1 93.2l.4 .2-.2 .2-.3-.2z" fill="#ececec"/>
<path d="M187.1 93.2l.4 .2-.2 .2-.3-.2z" fill="none" stroke="#ececec" stroke-width=".21"/>
<path d="M181.6 92.3l.3 .2-.1 .2-.3-.2z" fill="#ececec"/>
<path d="M181.6 92.3l.3 .2-.1 .2-.3-.2z" fill="none" stroke="#ececec" stroke-width=".21"/>
<path d="M181.4 100.4l.3 .1-.1 .2-.3-.2z" fill="#ececec"/>
<path d="M181.4 100.4l.3 .1-.1 .2-.3-.2z" fill="none" stroke="#ececec" stroke-width=".21"/>
<path d="M187.8 99l.3 .2-.1 .2-.3-.2z" fill="#ececec"/>
<path d="M187.8 99l.3 .2-.1 .2-.3-.2z" fill="none" stroke="#ececec" stroke-width=".21"/>
<path d="M161.4 84.8l.3 .2-.1 .2-.3-.2z" fill="#ececec"/>
<path d="M161.4 84.8l.3 .2-.1 .2-.3-.2z" fill="none" stroke="#ececec" stroke-width=".21"/>
<path d="M148.4 84.8l.4 .2-.2 .2-.3-.2z" fill="#ececec"/>
<path d="M148.4 84.8l.4 .2-.2 .2-.3-.2z" fill="none" stroke="#ececec" stroke-width=".21"/>
<path d="M166.1 85.2l.4 .2-.2 .2-.3-.2z" fill="#ececec"/>
<path d="M166.1 85.2l.4 .2-.2 .2-.3-.2z" fill="none" stroke="#ececec" stroke-width=".21"/>
<path d="M158.4 88.9l.3 .2-.1 .2-.3-.2z" fill="#ececec"/>
<path d="M158.4 88.9l.3 .2-.1 .2-.3-.2z" fill="none" stroke="#ececec" stroke-width=".21"/>
<path d="M155 85.3l.3 .2-.1 .2-.3-.2z" fill="#ececec"/>
<path d="M155 85.3l.3 .2-.1 .2-.3-.2z" fill="none" stroke="#ececec" stroke-width=".21"/>
<path d="M162.7 88.8l.3 .2-.1 .2-.3-.2z" fill="#ececec"/>
<path d="M162.7 88.8l.3 .2-.1 .2-.3-.2z" fill="none" stroke="#ececec" stroke-width=".21"/>
<path d="M162.3 91l.3 .2-.1 .2-.3-.2z" fill="#ececec"/>
<path d="M162.3 91l.3 .2-.1 .2-.3-.2z" fill="none" stroke="#ececec" stroke-width=".21"/>
<path d="M161.2 93.4l.3 .2-.1 .2-.3-.2z" fill="#ececec"/>
<path d="M161.2 93.4l.3 .2-.1 .2-.3-.2z" fill="none" stroke="#ececec" stroke-width=".21"/>
<path d="M158.3 91.7l.3 .2-.1 .2-.3-.2z" fill="#ececec"/>
<path d="M158.3 91.7l.3 .2-.1 .2-.3-.2z" fill="none" stroke="#ececec" stroke-width=".21"/>
<path d="M155 91.8l.4 .2-.1 .2-.4-.2z" fill="#ececec"/>
<path d="M155 91.8l.4 .2-.1 .2-.4-.2z" fill="none" stroke="#ececec" stroke-width=".21"/>
<path d="M151.2 94.9l.3 .2-.1 .2-.4-.2z" fill="#ececec"/>
<path d="M151.2 94.9l.3 .2-.1 .2-.4-.2z" fill="none" stroke="#ececec" stroke-width=".21"/>
<path d="M155.4 95.1l.3 .2-.1 .2-.3-.2z" fill="#ececec"/>
<path d="M155.4 95.1l.3 .2-.1 .2-.3-.2z" fill="none" stroke="#ececec" stroke-width=".21"/>
<path d="M157.9 101.5l.3 .1-.1 .2-.3-.2z" fill="#ececec"/>
<path d="M157.9 101.5l.3 .1-.1 .2-.3-.2z" fill="none" stroke="#ececec" stroke-width=".21"/>
<path d="M156 101.3l.3 .2-.1 .2-.3-.2z" fill="#ececec"/>
<path d="M156 101.3l.3 .2-.1 .2-.3-.2z" fill="none" stroke="#ececec" stroke-width=".21"/>
<path d="M160.2 105.9l.3 .1-.1 .2-.3-.2z" fill="#ececec"/>
<path d="M160.2 105.9l.3 .1-.1 .2-.3-.2z" fill="none" stroke="#ececec" stroke-width=".21"/>
<path d="M160.3 107.1l.3 .2-.1 .2-.3-.2z" fill="#ececec"/>
<path d="M160.3 107.1l.3 .2-.1 .2-.3-.2z" fill="none" stroke="#ececec" stroke-width=".21"/>
<path d="M147.4 103.7l.3 .1-.1 .2-.3-.2z" fill="#ececec"/>
<path d="M147.4 103.7l.3 .1-.1 .2-.3-.2z" fill="none" stroke="#ececec" stroke-width=".21"/>
<path d="M147.4 101.5l.3 .1-.1 .2-.3-.2z" fill="#ececec"/>
<path d="M147.4 101.5l.3 .1-.1 .2-.3-.2z" fill="none" stroke="#ececec" stroke-width=".21"/>
<path d="M146.9 100.5l.3 .2-.1 .2-.3-.2z" fill="#ececec"/>
<path d="M146.9 100.5l.3 .2-.1 .2-.3-.2z" fill="none" stroke="#ececec" stroke-width=".21"/>
<path d="M146.4 102.6l.3 .1-.1 .2-.3-.2z" fill="#ececec"/>
<path d="M146.4 102.6l.3 .1-.1 .2-.3-.2z" fill="none" stroke="#ececec" stroke-width=".21"/>
<path d="M146.2 107.6l.3 .1-.1 .2-.4-.2z" fill="#ececec"/>
<path d="M146.2 107.6l.3 .1-.1 .2-.4-.2z" fill="none" stroke="#ececec" stroke-width=".21"/>
<path d="M147.8 106.1l.3 .2-.1 .2-.3-.2z" fill="#ececec"/>
<path d="M147.8 106.1l.3 .2-.1 .2-.3-.2z" fill="none" stroke="#ececec" stroke-width=".21"/>
<path d="M151.7 97.7l.3 .2-.1 .2-.3-.2z" fill="#ececec"/>
<path d="M151.7 97.7l.3 .2-.1 .2-.3-.2z" fill="none" stroke="#ececec" stroke-width=".21"/>
<path d="M146.5 95.2l.3 .2-.1 .2-.3-.2z" fill="#ececec"/>
<path d="M146.5 95.2l.3 .2-.1 .2-.3-.2z" fill="none" stroke="#ececec" stroke-width=".21"/>
<path d="M145.9 93.7l.3 .2-.1 .2-.3-.2z" fill="#ececec"/>
<path d="M145.9 93.7l.3 .2-.1 .2-.3-.2z" fill="none" stroke="#ececec" stroke-width=".21"/>
<path d="M143.9 96.4l.3 .2-.1 .2-.3-.2z" fill="#ececec"/>
<path d="M143.9 96.4l.3 .2-.1 .2-.3-.2z" fill="none" stroke="#ececec" stroke-width=".21"/>
<path d="M147.7 95l.3 .2-.1 .2-.3-.2z" fill="#ececec"/>
<path d="M147.7 95l.3 .2-.1 .2-.3-.2z" fill="none" stroke="#ececec" stroke-width=".21"/>
<path d="M143.2 99.1l.3 .2-.1 .2-.3-.2z" fill="#ececec"/>
<path d="M143.2 99.1l.3 .2-.1 .2-.3-.2z" fill="none" stroke="#ececec" stroke-width=".21"/>
<path d="M129.7 86.4l.3 .2-.1 .2-.3-.2z" fill="#ececec"/>
<path d="M129.7 86.4l.3 .2-.1 .2-.3-.2z" fill="none" stroke="#ececec" stroke-width=".21"/>
<path d="M144.6 106l.3 .2-.1 .2-.3-.2z" fill="#ececec"/>
<path d="M144.6 106l.3 .2-.1 .2-.3-.2z" fill="none" stroke="#ececec" stroke-width=".21"/>
<path d="M144.6 107.5l.3 .2-.1 .1-.3-.1z" fill="#ececec"/>
<path d="M144.6 107.5l.3 .2-.1 .1-.3-.1z" fill="none" stroke="#ececec" stroke-width=".21"/>
<path d="M145.2 104.3l.3 .2-.1 .2-.3-.2z" fill="#ececec"/>
<path d="M145.2 104.3l.3 .2-.1 .2-.3-.2z" fill="none" stroke="#ececec" stroke-width=".21"/>
<path d="M136.5 103.7l.3 .1-.1 .2-.3-.2z" fill="#ececec"/>
<path d="M136.5 103.7l.3 .1-.1 .2-.3-.2z" fill="none" stroke="#ececec" stroke-width=".21"/>
<path d="M153.2 106.6l.3 .2-.1 .2-.3-.2z" fill="#ececec"/>
<path d="M153.2 106.6l.3 .2-.1 .2-.3-.2z" fill="none" stroke="#ececec" stroke-width=".21"/>
<path d="M156.2 106.6l.3 .2-.1 .2-.4-.2z" fill="#ececec"/>
<path d="M156.2 106.6l.3 .2-.1 .2-.4-.2z" fill="none" stroke="#ececec" stroke-width=".21"/>
<path d="M153 104.9l.3 .2-.1 .2-.3-.2z" fill="#ececec"/>
<path d="M153 104.9l.3 .2-.1 .2-.3-.2z" fill="none" stroke="#ececec" stroke-width=".21"/>
<path d="M151.9 104.9l.3 .2-.1 .2-.3-.2z" fill="#ececec"/>
<path d="M151.9 104.9l.3 .2-.1 .2-.3-.2z" fill="none" stroke="#ececec" stroke-width=".21"/>
<path d="M151.3 107.3l.3 .2-.1 .2-.3-.2z" fill="#ececec"/>
<path d="M151.3 107.3l.3 .2-.1 .2-.3-.2z" fill="none" stroke="#ececec" stroke-width=".21"/>
<path d="M165.5 103.4l.4 .2-.1 .2-.4-.2z" fill="#ececec"/>
<path d="M165.5 103.4l.4 .2-.1 .2-.4-.2z" fill="none" stroke="#ececec" stroke-width=".21"/>
<path d="M164.4 105l.4 .2-.1 .2-.4-.2z" fill="#ececec"/>
<path d="M164.4 105l.4 .2-.1 .2-.4-.2z" fill="none" stroke="#ececec" stroke-width=".21"/>
<path d="M164.2 108.5l.3 .2-.1 .2-.3-.2z" fill="#ececec"/>
<path d="M164.2 108.5l.3 .2-.1 .2-.3-.2z" fill="none" stroke="#ececec" stroke-width=".21"/>
<path d="M167.2 106.6l.3 .2-.1 .2-.4-.2z" fill="#ececec"/>
<path d="M167.2 106.6l.3 .2-.1 .2-.4-.2z" fill="none" stroke="#ececec" stroke-width=".21"/>
<path d="M165 108.1l.3 .2-.1 .2-.4-.2z" fill="#ececec"/>
<path d="M165 108.1l.3 .2-.1 .2-.4-.2z" fill="none" stroke="#ececec" stroke-width=".21"/>
<path d="M185.7 112.8l.3 .2-.1 .2-.3-.2z" fill="#ececec"/>
<path d="M185.7 112.8l.3 .2-.1 .2-.3-.2z" fill="none" stroke="#ececec" stroke-width=".21"/>
<path d="M179.2 108.3l.3 .2-.1 .2-.3-.2z" fill="#ececec"/>
<path d="M179.2 108.3l.3 .2-.1 .2-.3-.2z" fill="none" stroke="#ececec" stroke-width=".21"/>
<path d="M179.3 110.3l.3 .1-.1 .2-.3-.2z" fill="#ececec"/>
<path d="M179.3 110.3l.3 .1-.1 .2-.3-.2z" fill="none" stroke="#ececec" stroke-width=".21"/>
<path d="M183.4 108.7l.3 .2-.1 .2-.3-.2z" fill="#ececec"/>
<path d="M183.4 108.7l.3 .2-.1 .2-.3-.2z" fill="none" stroke="#ececec" stroke-width=".21"/>
<path d="M185.9 115.3l.3 .1-.1 .2-.3-.2z" fill="#ececec"/>
<path d="M185.9 115.3l.3 .1-.1 .2-.3-.2z" fill="none" stroke="#ececec" stroke-width=".21"/>
<path d="M177.3 109.5l.3 .2-.1 .2-.3-.2z" fill="#ececec"/>
<path d="M177.3 109.5l.3 .2-.1 .2-.3-.2z" fill="none" stroke="#ececec" stroke-width=".21"/>
<path d="M181.5 114.1l.3 .2-.1 .1-.3-.1z" fill="#ececec"/>
<path d="M181.5 114.1l.3 .2-.1 .1-.3-.1z" fill="none" stroke="#ececec" stroke-width=".21"/>
<path d="M197.6 104.5l.3 .2-.1 .2-.4-.2z" fill="#ececec"/>
<path d="M197.6 104.5l.3 .2-.1 .2-.4-.2z" fill="none" stroke="#ececec" stroke-width=".21"/>
<path d="M197.5 101.5l.3 .2-.1 .2-.3-.2z" fill="#ececec"/>
<path d="M197.5 101.5l.3 .2-.1 .2-.3-.2z" fill="none" stroke="#ececec" stroke-width=".21"/>
<path d="M190 101.8l.3 .2-.1 .2-.3-.2z" fill="#ececec"/>
<path d="M190 101.8l.3 .2-.1 .2-.3-.2z" fill="none" stroke="#ececec" stroke-width=".21"/>
<path d="M190 103.1l.3 .2-.1 .2-.3-.2z" fill="#ececec"/>
<path d="M190 103.1l.3 .2-.1 .2-.3-.2z" fill="none" stroke="#ececec" stroke-width=".21"/>
<path d="M197.3 115.3l.3 .2-.1 .2-.3-.2z" fill="#ececec"/>
<path d="M197.3 115.3l.3 .2-.1 .2-.3-.2z" fill="none" stroke="#ececec" stroke-width=".21"/>
<path d="M189.1 114.7l.3 .2-.1 .2-.3-.2z" fill="#ececec"/>
<path d="M189.1 114.7l.3 .2-.1 .2-.3-.2z" fill="none" stroke="#ececec" stroke-width=".21"/>
<path d="M189.1 113.1l.3 .1-.1 .2-.3-.2z" fill="#ececec"/>
<path d="M189.1 113.1l.3 .1-.1 .2-.3-.2z" fill="none" stroke="#ececec" stroke-width=".21"/>
<path d="M190.1 110l.3 .2-.1 .2-.3-.2z" fill="#ececec"/>
<path d="M190.1 110l.3 .2-.1 .2-.3-.2z" fill="none" stroke="#ececec" stroke-width=".21"/>
<path d="M188.5 109.7l.3 .2-.1 .1-.3-.1z" fill="#ececec"/>
<path d="M188.5 109.7l.3 .2-.1 .1-.3-.1z" fill="none" stroke="#ececec" stroke-width=".21"/>
<path d="M196.7 110.9l.3 .2-.1 .2-.3-.2z" fill="#ececec"/>
<path d="M196.7 110.9l.3 .2-.1 .2-.3-.2z" fill="none" stroke="#ececec" stroke-width=".21"/>
<path d="M190.4 114.9l.3 .2-.1 .2-.4-.2z" fill="#ececec"/>
<path d="M190.4 114.9l.3 .2-.1 .2-.4-.2z" fill="none" stroke="#ececec" stroke-width=".21"/>
<path d="M187.5 110.9l.3 .1-.1 .2-.3-.2z" fill="#ececec"/>
<path d="M187.5 110.9l.3 .1-.1 .2-.3-.2z" fill="none" stroke="#ececec" stroke-width=".21"/>
<path d="M171.5 112.4l.3 .2-.1 .2-.3-.2z" fill="#ececec"/>
<path d="M171.5 112.4l.3 .2-.1 .2-.3-.2z" fill="none" stroke="#ececec" stroke-width=".21"/>
<path d="M173.8 114.4l.4 .2-.2 .2-.3-.2z" fill="#ececec"/>
<path d="M173.8 114.4l.4 .2-.2 .2-.3-.2z" fill="none" stroke="#ececec" stroke-width=".21"/>
<path d="M174.4 109.6l.3 .2-.1 .2-.4-.2z" fill="#ececec"/>
<path d="M174.4 109.6l.3 .2-.1 .2-.4-.2z" fill="none" stroke="#ececec" stroke-width=".21"/>
<path d="M174 110.5l.3 .2-.1 .2-.3-.2z" fill="#ececec"/>
<path d="M174 110.5l.3 .2-.1 .2-.3-.2z" fill="none" stroke="#ececec" stroke-width=".21"/>
<path d="M190 105l.3 .2-.1 .2-.3-.2z" fill="#ececec"/>
<path d="M190 105l.3 .2-.1 .2-.3-.2z" fill="none" stroke="#ececec" stroke-width=".21"/>
<path d="M188.4 105.9l.3 .2-.1 .2-.3-.2z" fill="#ececec"/>
<path d="M188.4 105.9l.3 .2-.1 .2-.3-.2z" fill="none" stroke="#ececec" stroke-width=".21"/>
<path d="M188.4 107l.3 .1-.1 .2-.3-.2z" fill="#ececec"/>
<path d="M188.4 107l.3 .1-.1 .2-.3-.2z" fill="none" stroke="#ececec" stroke-width=".21"/>
<path d="M188.2 104.8l.4 .2-.2 .2-.3-.2z" fill="#ececec"/>
<path d="M188.2 104.8l.4 .2-.2 .2-.3-.2z" fill="none" stroke="#ececec" stroke-width=".21"/>
<path d="M191.1 107.2l.3 .2-.1 .2-.3-.2z" fill="#ececec"/>
<path d="M191.1 107.2l.3 .2-.1 .2-.3-.2z" fill="none" stroke="#ececec" stroke-width=".21"/>
<path d="M183.4 101.9l.3 .2-.1 .2-.3-.2z" fill="#ececec"/>
<path d="M183.4 101.9l.3 .2-.1 .2-.3-.2z" fill="none" stroke="#ececec" stroke-width=".21"/>
<path d="M195.4 116.9l.3 .2-.1 .1-.4-.1z" fill="#ececec"/>
<path d="M195.4 116.9l.3 .2-.1 .1-.4-.1z" fill="none" stroke="#ececec" stroke-width=".21"/>
<path d="M192.4 116.3l.3 .2-.1 .1-.3-.1z" fill="#ececec"/>
<path d="M192.4 116.3l.3 .2-.1 .1-.3-.1z" fill="none" stroke="#ececec" stroke-width=".21"/>
<path d="M187.6 115.9l.4 .2-.1 .2-.4-.2z" fill="#ececec"/>
<path d="M187.6 115.9l.4 .2-.1 .2-.4-.2z" fill="none" stroke="#ececec" stroke-width=".21"/>
<path d="M187.8 119l.3 .2-.1 .2-.3-.2z" fill="#ececec"/>
<path d="M187.8 119l.3 .2-.1 .2-.3-.2z" fill="none" stroke="#ececec" stroke-width=".21"/>
<path d="M180.7 136.4l.3 .2-.1 .2-.3-.2z" fill="#ececec"/>
<path d="M180.7 136.4l.3 .2-.1 .2-.3-.2z" fill="none" stroke="#ececec" stroke-width=".21"/>
<path d="M176.8 140l.3 .2-.1 .2-.3-.2z" fill="#ececec"/>
<path d="M176.8 140l.3 .2-.1 .2-.3-.2z" fill="none" stroke="#ececec" stroke-width=".21"/>
<path d="M183.1 139.1l.3 .2-.1 .2-.3-.2z" fill="#ececec"/>
<path d="M183.1 139.1l.3 .2-.1 .2-.3-.2z" fill="none" stroke="#ececec" stroke-width=".21"/>
<path d="M183.6 133.7l.3 .2-.1 .2-.3-.2z" fill="#ececec"/>
<path d="M183.6 133.7l.3 .2-.1 .2-.3-.2z" fill="none" stroke="#ececec" stroke-width=".21"/>
<path d="M177.9 134.6l.3 .1-.1 .2-.3-.2z" fill="#ececec"/>
<path d="M177.9 134.6l.3 .1-.1 .2-.3-.2z" fill="none" stroke="#ececec" stroke-width=".21"/>
<path d="M176.6 136.6l.4 .2-.2 .2-.3-.2z" fill="#ececec"/>
<path d="M176.6 136.6l.4 .2-.2 .2-.3-.2z" fill="none" stroke="#ececec" stroke-width=".21"/>
<path d="M179.8 130.7l.3 .2-.1 .1-.3-.1z" fill="#ececec"/>
<path d="M179.8 130.7l.3 .2-.1 .1-.3-.1z" fill="none" stroke="#ececec" stroke-width=".21"/>
<path d="M183.9 131.1l.3 .2-.1 .2-.3-.2z" fill="#ececec"/>
<path d="M183.9 131.1l.3 .2-.1 .2-.3-.2z" fill="none" stroke="#ececec" stroke-width=".21"/>
<path d="M181.9 130.1l.3 .2-.1 .1-.3-.1z" fill="#ececec"/>
<path d="M181.9 130.1l.3 .2-.1 .1-.3-.1z" fill="none" stroke="#ececec" stroke-width=".21"/>
<path d="M182.6 133.8l.3 .2-.1 .2-.3-.2z" fill="#ececec"/>
<path d="M182.6 133.8l.3 .2-.1 .2-.3-.2z" fill="none" stroke="#ececec" stroke-width=".21"/>
<path d="M184 132.6l.3 .2-.1 .2-.3-.2z" fill="#ececec"/>
<path d="M184 132.6l.3 .2-.1 .2-.3-.2z" fill="none" stroke="#ececec" stroke-width=".21"/>
<path d="M188 132.2l.3 .2-.1 .2-.3-.2z" fill="#ececec"/>
<path d="M188 132.2l.3 .2-.1 .2-.3-.2z" fill="none" stroke="#ececec" stroke-width=".21"/>
<path d="M189 130.4l.3 .2-.1 .2-.3-.2z" fill="#ececec"/>
<path d="M189 130.4l.3 .2-.1 .2-.3-.2z" fill="none" stroke="#ececec" stroke-width=".21"/>
<path d="M187.3 129.5l.3 .2-.1 .2-.3-.2z" fill="#ececec"/>
<path d="M187.3 129.5l.3 .2-.1 .2-.3-.2z" fill="none" stroke="#ececec" stroke-width=".21"/>
<path d="M187.7 134.1l.3 .1-.1 .2-.3-.2z" fill="#ececec"/>
<path d="M187.7 134.1l.3 .1-.1 .2-.3-.2z" fill="none" stroke="#ececec" stroke-width=".21"/>
<path d="M181.8 125.4l.3 .2-.1 .2-.3-.2z" fill="#ececec"/>
<path d="M181.8 125.4l.3 .2-.1 .2-.3-.2z" fill="none" stroke="#ececec" stroke-width=".21"/>
<path d="M187.8 124.7l.3 .2-.1 .2-.3-.2z" fill="#ececec"/>
<path d="M187.8 124.7l.3 .2-.1 .2-.3-.2z" fill="none" stroke="#ececec" stroke-width=".21"/>
<path d="M183.8 120.4l.3 .2-.1 .2-.4-.2z" fill="#ececec"/>
<path d="M183.8 120.4l.3 .2-.1 .2-.4-.2z" fill="none" stroke="#ececec" stroke-width=".21"/>
<path d="M182.9 120l.3 .2-.1 .2-.3-.2z" fill="#ececec"/>
<path d="M182.9 120l.3 .2-.1 .2-.3-.2z" fill="none" stroke="#ececec" stroke-width=".21"/>
<path d="M183.2 118l.3 .2-.1 .1-.4-.1z" fill="#ececec"/>
<path d="M183.2 118l.3 .2-.1 .1-.4-.1z" fill="none" stroke="#ececec" stroke-width=".21"/>
<path d="M188 126.9l.3 .2-.1 .2-.3-.2z" fill="#ececec"/>
<path d="M188 126.9l.3 .2-.1 .2-.3-.2z" fill="none" stroke="#ececec" stroke-width=".21"/>
<path d="M197.1 46.8l.3 .1-.1 .2-.3-.2z" fill="#ececec"/>
<path d="M197.1 46.8l.3 .1-.1 .2-.3-.2z" fill="none" stroke="#ececec" stroke-width=".21"/>
<path d="M189.6 47.3l.3 .2-.1 .1-.3-.1z" fill="#ececec"/>
<path d="M189.6 47.3l.3 .2-.1 .1-.3-.1z" fill="none" stroke="#ececec" stroke-width=".21"/>
<path d="M189.6 49.3l.3 .2-.1 .2-.3-.2z" fill="#ececec"/>
<path d="M189.6 49.3l.3 .2-.1 .2-.3-.2z" fill="none" stroke="#ececec" stroke-width=".21"/>
<path d="M188.7 41.8l.4 .2-.1 .2-.4-.2z" fill="#ececec"/>
<path d="M188.7 41.8l.4 .2-.1 .2-.4-.2z" fill="none" stroke="#ececec" stroke-width=".21"/>
<path d="M187.3 45.4l.3 .2-.1 .2-.3-.2z" fill="#ececec"/>
<path d="M187.3 45.4l.3 .2-.1 .2-.3-.2z" fill="none" stroke="#ececec" stroke-width=".21"/>
<path d="M169.4 53.2l.4 .2-.2 .2-.3-.2z" fill="#ececec"/>
<path d="M169.4 53.2l.4 .2-.2 .2-.3-.2z" fill="none" stroke="#ececec" stroke-width=".21"/>
<path d="M165.2 51.3l.3 .2-.1 .2-.3-.2z" fill="#ececec"/>
<path d="M165.2 51.3l.3 .2-.1 .2-.3-.2z" fill="none" stroke="#ececec" stroke-width=".21"/>
<path d="M164.9 45.6l.3 .2-.1 .2-.3-.2z" fill="#ececec"/>
<path d="M164.9 45.6l.3 .2-.1 .2-.3-.2z" fill="none" stroke="#ececec" stroke-width=".21"/>
<path d="M167.7 48.8l.4 .2-.1 .2-.4-.2z" fill="#ececec"/>
<path d="M167.7 48.8l.4 .2-.1 .2-.4-.2z" fill="none" stroke="#ececec" stroke-width=".21"/>
<path d="M172.8 51.1l.3 .2-.1 .2-.3-.2z" fill="#ececec"/>
<path d="M172.8 51.1l.3 .2-.1 .2-.3-.2z" fill="none" stroke="#ececec" stroke-width=".21"/>
<path d="M174.4 63.9l.3 .2-.1 .2-.4-.2z" fill="#ececec"/>
<path d="M174.4 63.9l.3 .2-.1 .2-.4-.2z" fill="none" stroke="#ececec" stroke-width=".21"/>
<path d="M174.4 62.8l.4 .2-.2 .2-.3-.2z" fill="#ececec"/>
<path d="M174.4 62.8l.4 .2-.2 .2-.3-.2z" fill="none" stroke="#ececec" stroke-width=".21"/>
<path d="M175.4 64l.3 .2-.1 .2-.3-.2z" fill="#ececec"/>
<path d="M175.4 64l.3 .2-.1 .2-.3-.2z" fill="none" stroke="#ececec" stroke-width=".21"/>
<path d="M175.4 68.2l.3 .2-.1 .2-.3-.2z" fill="#ececec"/>
<path d="M175.4 68.2l.3 .2-.1 .2-.3-.2z" fill="none" stroke="#ececec" stroke-width=".21"/>
<path d="M179.1 44.5l.3 .2-.1 .1-.3-.1z" fill="#ececec"/>
<path d="M179.1 44.5l.3 .2-.1 .1-.3-.1z" fill="none" stroke="#ececec" stroke-width=".21"/>
<path d="M175.5 49.3l.4 .2-.2 .2-.3-.2z" fill="#ececec"/>
<path d="M175.5 49.3l.4 .2-.2 .2-.3-.2z" fill="none" stroke="#ececec" stroke-width=".21"/>
<path d="M178.4 46.7l.3 .2-.1 .2-.3-.2z" fill="#ececec"/>
<path d="M178.4 46.7l.3 .2-.1 .2-.3-.2z" fill="none" stroke="#ececec" stroke-width=".21"/>
<path d="M178.2 42.7l.4 .2-.1 .2-.4-.2z" fill="#ececec"/>
<path d="M178.2 42.7l.4 .2-.1 .2-.4-.2z" fill="none" stroke="#ececec" stroke-width=".21"/>
<path d="M188.8 51.8l.3 .1-.1 .2-.3-.2z" fill="#ececec"/>
<path d="M188.8 51.8l.3 .1-.1 .2-.3-.2z" fill="none" stroke="#ececec" stroke-width=".21"/>
<path d="M182.3 51.6l.3 .2-.1 .2-.3-.2z" fill="#ececec"/>
<path d="M182.3 51.6l.3 .2-.1 .2-.3-.2z" fill="none" stroke="#ececec" stroke-width=".21"/>
<path d="M182 59.3l.3 .2-.1 .2-.3-.2z" fill="#ececec"/>
<path d="M182 59.3l.3 .2-.1 .2-.3-.2z" fill="none" stroke="#ececec" stroke-width=".21"/>
<path d="M188.3 59.3l.3 .2-.1 .2-.3-.2z" fill="#ececec"/>
<path d="M188.3 59.3l.3 .2-.1 .2-.3-.2z" fill="none" stroke="#ececec" stroke-width=".21"/>
<path d="M182.1 56.3l.3 .2-.1 .2-.4-.2z" fill="#ececec"/>
<path d="M182.1 56.3l.3 .2-.1 .2-.4-.2z" fill="none" stroke="#ececec" stroke-width=".21"/>
<path d="M186.1 54.8l.3 .2-.1 .2-.3-.2z" fill="#ececec"/>
<path d="M186.1 54.8l.3 .2-.1 .2-.3-.2z" fill="none" stroke="#ececec" stroke-width=".21"/>
<path d="M167.2 65.5l.4 .2-.2 .1-.3-.1z" fill="#ececec"/>
<path d="M167.2 65.5l.4 .2-.2 .1-.3-.1z" fill="none" stroke="#ececec" stroke-width=".21"/>
<path d="M165.7 61l.3 .2-.1 .2-.3-.2z" fill="#ececec"/>
<path d="M165.7 61l.3 .2-.1 .2-.3-.2z" fill="none" stroke="#ececec" stroke-width=".21"/>
<path d="M171.1 68.2l.3 .2-.1 .2-.3-.2z" fill="#ececec"/>
<path d="M171.1 68.2l.3 .2-.1 .2-.3-.2z" fill="none" stroke="#ececec" stroke-width=".21"/>
<path d="M167.2 66.4l.4 .2-.2 .2-.3-.2z" fill="#ececec"/>
<path d="M167.2 66.4l.4 .2-.2 .2-.3-.2z" fill="none" stroke="#ececec" stroke-width=".21"/>
<path d="M166.1 62.5l.3 .2-.1 .2-.4-.2z" fill="#ececec"/>
<path d="M166.1 62.5l.3 .2-.1 .2-.4-.2z" fill="none" stroke="#ececec" stroke-width=".21"/>
<path d="M168.9 65.8l.3 .2-.1 .2-.4-.2z" fill="#ececec"/>
<path d="M168.9 65.8l.3 .2-.1 .2-.4-.2z" fill="none" stroke="#ececec" stroke-width=".21"/>
<path d="M188.2 60.8l.4 .2-.2 .2-.3-.2z" fill="#ececec"/>
<path d="M188.2 60.8l.4 .2-.2 .2-.3-.2z" fill="none" stroke="#ececec" stroke-width=".21"/>
<path d="M181.8 64.2l.3 .2-.1 .2-.3-.2z" fill="#ececec"/>
<path d="M181.8 64.2l.3 .2-.1 .2-.3-.2z" fill="none" stroke="#ececec" stroke-width=".21"/>
<path d="M183.8 66.2l.3 .2-.1 .2-.4-.2z" fill="#ececec"/>
<path d="M183.8 66.2l.3 .2-.1 .2-.4-.2z" fill="none" stroke="#ececec" stroke-width=".21"/>
<path d="M183.3 61.5l.3 .2-.1 .2-.3-.2z" fill="#ececec"/>
<path d="M183.3 61.5l.3 .2-.1 .2-.3-.2z" fill="none" stroke="#ececec" stroke-width=".21"/>
<path d="M185.9 66.5l.3 .2-.1 .2-.3-.2z" fill="#ececec"/>
<path d="M185.9 66.5l.3 .2-.1 .2-.3-.2z" fill="none" stroke="#ececec" stroke-width=".21"/>
<path d="M187.8 65.8l.3 .2-.1 .2-.3-.2z" fill="#ececec"/>
<path d="M187.8 65.8l.3 .2-.1 .2-.3-.2z" fill="none" stroke="#ececec" stroke-width=".21"/>
<path d="M171.1 62.2l.3 .2-.1 .1-.4-.1z" fill="#ececec"/>
<path d="M171.1 62.2l.3 .2-.1 .1-.4-.1z" fill="none" stroke="#ececec" stroke-width=".21"/>
<path d="M177.8 60.6l.3 .1-.1 .2-.3-.2z" fill="#ececec"/>
<path d="M177.8 60.6l.3 .1-.1 .2-.3-.2z" fill="none" stroke="#ececec" stroke-width=".21"/>
<path d="M174.9 59.4l.3 .2-.1 .2-.3-.2z" fill="#ececec"/>
<path d="M174.9 59.4l.3 .2-.1 .2-.3-.2z" fill="none" stroke="#ececec" stroke-width=".21"/>
<path d="M178 58.9l.3 .2-.1 .1-.3-.1z" fill="#ececec"/>
<path d="M178 58.9l.3 .2-.1 .1-.3-.1z" fill="none" stroke="#ececec" stroke-width=".21"/>
<path d="M171.3 58.6l.3 .2-.1 .2-.3-.2z" fill="#ececec"/>
<path d="M171.3 58.6l.3 .2-.1 .2-.3-.2z" fill="none" stroke="#ececec" stroke-width=".21"/>
<path d="M171.9 83.2l.3 .2-.1 .1-.3-.1z" fill="#ececec"/>
<path d="M171.9 83.2l.3 .2-.1 .1-.3-.1z" fill="none" stroke="#ececec" stroke-width=".21"/>
<path d="M172 87.4l.3 .2-.1 .2-.3-.2z" fill="#ececec"/>
<path d="M172 87.4l.3 .2-.1 .2-.3-.2z" fill="none" stroke="#ececec" stroke-width=".21"/>
<path d="M170 85.5l.3 .2-.1 .2-.3-.2z" fill="#ececec"/>
<path d="M170 85.5l.3 .2-.1 .2-.3-.2z" fill="none" stroke="#ececec" stroke-width=".21"/>
<path d="M166.1 87.3l.4 .2-.2 .2-.3-.2z" fill="#ececec"/>
<path d="M166.1 87.3l.4 .2-.2 .2-.3-.2z" fill="none" stroke="#ececec" stroke-width=".21"/>
<path d="M174.4 84.4l.4 .2-.2 .2-.3-.2z" fill="#ececec"/>
<path d="M174.4 84.4l.4 .2-.2 .2-.3-.2z" fill="none" stroke="#ececec" stroke-width=".21"/>
<path d="M177.8 83.4l.3 .2-.1 .2-.3-.2z" fill="#ececec"/>
<path d="M177.8 83.4l.3 .2-.1 .2-.3-.2z" fill="none" stroke="#ececec" stroke-width=".21"/>
<path d="M170.5 94.4l.4 .2-.2 .2-.3-.2z" fill="#ececec"/>
<path d="M170.5 94.4l.4 .2-.2 .2-.3-.2z" fill="none" stroke="#ececec" stroke-width=".21"/>
<path d="M170.2 100.7l.3 .2-.1 .2-.3-.2z" fill="#ececec"/>
<path d="M170.2 100.7l.3 .2-.1 .2-.3-.2z" fill="none" stroke="#ececec" stroke-width=".21"/>
<path d="M177.7 99.5l.3 .2-.1 .2-.4-.2z" fill="#ececec"/>
<path d="M177.7 99.5l.3 .2-.1 .2-.4-.2z" fill="none" stroke="#ececec" stroke-width=".21"/>
<path d="M170.5 92.6l.3 .2-.1 .2-.4-.2z" fill="#ececec"/>
<path d="M170.5 92.6l.3 .2-.1 .2-.4-.2z" fill="none" stroke="#ececec" stroke-width=".21"/>
<path d="M170 102.7l.3 .2-.1 .2-.4-.2z" fill="#ececec"/>
<path d="M170 102.7l.3 .2-.1 .2-.4-.2z" fill="none" stroke="#ececec" stroke-width=".21"/>
<path d="M164.3 100.3l.3 .2-.1 .1-.3-.1z" fill="#ececec"/>
<path d="M164.3 100.3l.3 .2-.1 .1-.3-.1z" fill="none" stroke="#ececec" stroke-width=".21"/>
<path d="M165.8 98.8l.3 .2-.1 .2-.3-.2z" fill="#ececec"/>
<path d="M165.8 98.8l.3 .2-.1 .2-.3-.2z" fill="none" stroke="#ececec" stroke-width=".21"/>
<path d="M164.3 99.3l.3 .1-.1 .2-.3-.2z" fill="#ececec"/>
<path d="M164.3 99.3l.3 .1-.1 .2-.3-.2z" fill="none" stroke="#ececec" stroke-width=".21"/>
<path d="M161.1 99.2l.4 .2-.2 .1-.3-.1z" fill="#ececec"/>
<path d="M161.1 99.2l.4 .2-.2 .1-.3-.1z" fill="none" stroke="#ececec" stroke-width=".21"/>
<path d="M164.4 97.1l.3 .2-.1 .2-.3-.2z" fill="#ececec"/>
<path d="M164.4 97.1l.3 .2-.1 .2-.3-.2z" fill="none" stroke="#ececec" stroke-width=".21"/>
<path d="M161 97l.3 .2-.1 .1-.3-.1z" fill="#ececec"/>
<path d="M161 97l.3 .2-.1 .1-.3-.1z" fill="none" stroke="#ececec" stroke-width=".21"/>
<path d="M160.2 98.3l.3 .2-.1 .2-.3-.2z" fill="#ececec"/>
<path d="M160.2 98.3l.3 .2-.1 .2-.3-.2z" fill="none" stroke="#ececec" stroke-width=".21"/>
<path d="M160.6 102.8l.3 .2-.1 .2-.4-.2z" fill="#ececec"/>
<path d="M160.6 102.8l.3 .2-.1 .2-.4-.2z" fill="none" stroke="#ececec" stroke-width=".21"/>
<path d="M166 97l.3 .2-.1 .1-.3-.1z" fill="#ececec"/>
<path d="M166 97l.3 .2-.1 .1-.3-.1z" fill="none" stroke="#ececec" stroke-width=".21"/>
<path d="M165.4 90.7l.3 .2-.1 .2-.3-.2z" fill="#ececec"/>
<path d="M165.4 90.7l.3 .2-.1 .2-.3-.2z" fill="none" stroke="#ececec" stroke-width=".21"/>
<path d="M166.8 89.5l.3 .2-.1 .2-.3-.2z" fill="#ececec"/>
<path d="M166.8 89.5l.3 .2-.1 .2-.3-.2z" fill="none" stroke="#ececec" stroke-width=".21"/>
<path d="M166.5 94.5l.3 .2-.1 .2-.3-.2z" fill="#ececec"/>
<path d="M166.5 94.5l.3 .2-.1 .2-.3-.2z" fill="none" stroke="#ececec" stroke-width=".21"/>
<path d="M165.5 93.2l.3 .2-.1 .2-.3-.2z" fill="#ececec"/>
<path d="M165.5 93.2l.3 .2-.1 .2-.3-.2z" fill="none" stroke="#ececec" stroke-width=".21"/>
<path d="M164.3 94.3l.3 .1-.1 .2-.3-.2z" fill="#ececec"/>
<path d="M164.3 94.3l.3 .1-.1 .2-.3-.2z" fill="none" stroke="#ececec" stroke-width=".21"/>
<path d="M166.8 91.6l.3 .2-.1 .2-.3-.2z" fill="#ececec"/>
<path d="M166.8 91.6l.3 .2-.1 .2-.3-.2z" fill="none" stroke="#ececec" stroke-width=".21"/>
<path d="M177.3 93.1l.3 .2-.1 .1-.3-.1z" fill="#ececec"/>
<path d="M177.3 93.1l.3 .2-.1 .1-.3-.1z" fill="none" stroke="#ececec" stroke-width=".21"/>
<path d="M174.4 94.4l.3 .2-.1 .2-.4-.2z" fill="#ececec"/>
<path d="M174.4 94.4l.3 .2-.1 .2-.4-.2z" fill="none" stroke="#ececec" stroke-width=".21"/>
<path d="M173.8 96l.3 .1-.1 .2-.3-.2z" fill="#ececec"/>
<path d="M173.8 96l.3 .1-.1 .2-.3-.2z" fill="none" stroke="#ececec" stroke-width=".21"/>
<path d="M175.6 95.6l.3 .2-.1 .2-.3-.2z" fill="#ececec"/>
<path d="M175.6 95.6l.3 .2-.1 .2-.3-.2z" fill="none" stroke="#ececec" stroke-width=".21"/>
<path d="M176.6 89.3l.4 .2-.2 .2-.3-.2z" fill="#ececec"/>
<path d="M176.6 89.3l.4 .2-.2 .2-.3-.2z" fill="none" stroke="#ececec" stroke-width=".21"/>
<path d="M180.3 91.8l.3 .2-.1 .2-.3-.2z" fill="#ececec"/>
<path d="M180.3 91.8l.3 .2-.1 .2-.3-.2z" fill="none" stroke="#ececec" stroke-width=".21"/>
<path d="M181 86.8l.4 .2-.2 .2-.3-.2z" fill="#ececec"/>
<path d="M181 86.8l.4 .2-.2 .2-.3-.2z" fill="none" stroke="#ececec" stroke-width=".21"/>
<path d="M156.6 96l.3 .2-.1 .2-.3-.2z" fill="#ececec"/>
<path d="M156.6 96l.3 .2-.1 .2-.3-.2z" fill="none" stroke="#ececec" stroke-width=".21"/>
<path d="M153 93.6l.3 .2-.1 .2-.3-.2z" fill="#ececec"/>
<path d="M153 93.6l.3 .2-.1 .2-.3-.2z" fill="none" stroke="#ececec" stroke-width=".21"/>
<path d="M149.8 87.3l.3 .2-.1 .2-.3-.2z" fill="#ececec"/>
<path d="M149.8 87.3l.3 .2-.1 .2-.3-.2z" fill="none" stroke="#ececec" stroke-width=".21"/>
<path d="M163.3 88l.3 .2-.1 .2-.3-.2z" fill="#ececec"/>
<path d="M163.3 88l.3 .2-.1 .2-.3-.2z" fill="none" stroke="#ececec" stroke-width=".21"/>
<path d="M149.8 91l.3 .2-.1 .2-.3-.2z" fill="#ececec"/>
<path d="M149.8 91l.3 .2-.1 .2-.3-.2z" fill="none" stroke="#ececec" stroke-width=".21"/>
<path d="M158.2 44.1l.3 .1-.1 .2-.3-.2z" fill="#ececec"/>
<path d="M158.2 44.1l.3 .1-.1 .2-.3-.2z" fill="none" stroke="#ececec" stroke-width=".21"/>
<path d="M174.7 53.4l.3 .2-.1 .1-.3-.1z" fill="#ececec"/>
<path d="M174.7 53.4l.3 .2-.1 .1-.3-.1z" fill="none" stroke="#ececec" stroke-width=".21"/>
<path d="M165.9 41.9l.3 .2-.1 .2-.3-.2z" fill="#ececec"/>
<path d="M165.9 41.9l.3 .2-.1 .2-.3-.2z" fill="none" stroke="#ececec" stroke-width=".21"/>
<path d="M159.3 41.1l.3 .2-.1 .2-.3-.2z" fill="#ececec"/>
<path d="M159.3 41.1l.3 .2-.1 .2-.3-.2z" fill="none" stroke="#ececec" stroke-width=".21"/>
<path d="M159.6 46.3l.3 .1-.1 .2-.3-.2z" fill="#ececec"/>
<path d="M159.6 46.3l.3 .1-.1 .2-.3-.2z" fill="none" stroke="#ececec" stroke-width=".21"/>
<path d="M144.7 41.1l.3 .2-.1 .2-.3-.2z" fill="#ececec"/>
<path d="M144.7 41.1l.3 .2-.1 .2-.3-.2z" fill="none" stroke="#ececec" stroke-width=".21"/>
<path d="M150.7 43.9l.3 .2-.1 .2-.3-.2z" fill="#ececec"/>
<path d="M150.7 43.9l.3 .2-.1 .2-.3-.2z" fill="none" stroke="#ececec" stroke-width=".21"/>
<path d="M143.7 44.9l.3 .2-.1 .2-.3-.2z" fill="#ececec"/>
<path d="M143.7 44.9l.3 .2-.1 .2-.3-.2z" fill="none" stroke="#ececec" stroke-width=".21"/>
<path d="M149.3 49.9l.3 .2-.1 .2-.3-.2z" fill="#ececec"/>
<path d="M149.3 49.9l.3 .2-.1 .2-.3-.2z" fill="none" stroke="#ececec" stroke-width=".21"/>
<path d="M143.6 43.7l.3 .2-.1 .2-.3-.2z" fill="#ececec"/>
<path d="M143.6 43.7l.3 .2-.1 .2-.3-.2z" fill="none" stroke="#ececec" stroke-width=".21"/>
<path d="M149.4 41.9l.3 .2-.1 .2-.3-.2z" fill="#ececec"/>
<path d="M149.4 41.9l.3 .2-.1 .2-.3-.2z" fill="none" stroke="#ececec" stroke-width=".21"/>
<path d="M155 79.4l.3 .2-.1 .2-.3-.2z" fill="#ececec"/>
<path d="M155 79.4l.3 .2-.1 .2-.3-.2z" fill="none" stroke="#ececec" stroke-width=".21"/>
<path d="M155 69.5l.3 .2-.1 .2-.3-.2z" fill="#ececec"/>
<path d="M155 69.5l.3 .2-.1 .2-.3-.2z" fill="none" stroke="#ececec" stroke-width=".21"/>
<path d="M159.2 73.9l.3 .1-.1 .2-.3-.2z" fill="#ececec"/>
<path d="M159.2 73.9l.3 .1-.1 .2-.3-.2z" fill="none" stroke="#ececec" stroke-width=".21"/>
<path d="M158.4 82l.3 .2-.1 .2-.4-.2z" fill="#ececec"/>
<path d="M158.4 82l.3 .2-.1 .2-.4-.2z" fill="none" stroke="#ececec" stroke-width=".21"/>
<path d="M163.3 69.5l.3 .1-.1 .2-.3-.2z" fill="#ececec"/>
<path d="M163.3 69.5l.3 .1-.1 .2-.3-.2z" fill="none" stroke="#ececec" stroke-width=".21"/>
<path d="M149.1 74.4l.3 .2-.1 .2-.3-.2z" fill="#ececec"/>
<path d="M149.1 74.4l.3 .2-.1 .2-.3-.2z" fill="none" stroke="#ececec" stroke-width=".21"/>
<path d="M165.1 72.2l.3 .2-.1 .2-.3-.2z" fill="#ececec"/>
<path d="M165.1 72.2l.3 .2-.1 .2-.3-.2z" fill="none" stroke="#ececec" stroke-width=".21"/>
<path d="M137.1 43.9l.3 .2-.1 .2-.3-.2z" fill="#ececec"/>
<path d="M137.1 43.9l.3 .2-.1 .2-.3-.2z" fill="none" stroke="#ececec" stroke-width=".21"/>
<path d="M138.5 53.7l.3 .2-.1 .2-.4-.2z" fill="#ececec"/>
<path d="M138.5 53.7l.3 .2-.1 .2-.4-.2z" fill="none" stroke="#ececec" stroke-width=".21"/>
<path d="M138 41.8l.3 .2-.1 .2-.3-.2z" fill="#ececec"/>
<path d="M138 41.8l.3 .2-.1 .2-.3-.2z" fill="none" stroke="#ececec" stroke-width=".21"/>
<path d="M138.3 47l.3 .2-.1 .2-.3-.2z" fill="#ececec"/>
<path d="M138.3 47l.3 .2-.1 .2-.3-.2z" fill="none" stroke="#ececec" stroke-width=".21"/>
<path d="M165 59.3l.4 .2-.2 .2-.3-.2z" fill="#ececec"/>
<path d="M165 59.3l.4 .2-.2 .2-.3-.2z" fill="none" stroke="#ececec" stroke-width=".21"/>
<path d="M153 54.1l.3 .2-.1 .2-.3-.2z" fill="#ececec"/>
<path d="M153 54.1l.3 .2-.1 .2-.3-.2z" fill="none" stroke="#ececec" stroke-width=".21"/>
<path d="M155 59.5l.3 .1-.1 .2-.3-.2z" fill="#ececec"/>
<path d="M155 59.5l.3 .1-.1 .2-.3-.2z" fill="none" stroke="#ececec" stroke-width=".21"/>
<path d="M159.8 61.9l.3 .2-.1 .2-.3-.2z" fill="#ececec"/>
<path d="M159.8 61.9l.3 .2-.1 .2-.3-.2z" fill="none" stroke="#ececec" stroke-width=".21"/>
<path d="M159.3 54.4l.3 .2-.1 .2-.3-.2z" fill="#ececec"/>
<path d="M159.3 54.4l.3 .2-.1 .2-.3-.2z" fill="none" stroke="#ececec" stroke-width=".21"/>
<path d="M151.5 64.7l.3 .2-.1 .2-.3-.2z" fill="#ececec"/>
<path d="M151.5 64.7l.3 .2-.1 .2-.3-.2z" fill="none" stroke="#ececec" stroke-width=".21"/>
<path d="M163.9 64.7l.3 .2-.1 .2-.4-.2z" fill="#ececec"/>
<path d="M163.9 64.7l.3 .2-.1 .2-.4-.2z" fill="none" stroke="#ececec" stroke-width=".21"/>
<path d="M137.9 58.9l.4 .2-.1 .1-.4-.1z" fill="#ececec"/>
<path d="M137.9 58.9l.4 .2-.1 .1-.4-.1z" fill="none" stroke="#ececec" stroke-width=".21"/>
<path d="M134.2 60.2l.3 .2-.1 .2-.3-.2z" fill="#ececec"/>
<path d="M134.2 60.2l.3 .2-.1 .2-.3-.2z" fill="none" stroke="#ececec" stroke-width=".21"/>
<path d="M144.5 59.5l.3 .1-.1 .2-.3-.2z" fill="#ececec"/>
<path d="M144.5 59.5l.3 .1-.1 .2-.3-.2z" fill="none" stroke="#ececec" stroke-width=".21"/>
<path d="M136.8 69.1l.4 .2-.1 .2-.4-.2z" fill="#ececec"/>
<path d="M136.8 69.1l.4 .2-.1 .2-.4-.2z" fill="none" stroke="#ececec" stroke-width=".21"/>
<path d="M138 69.7l.3 .2-.1 .2-.3-.2z" fill="#ececec"/>
<path d="M138 69.7l.3 .2-.1 .2-.3-.2z" fill="none" stroke="#ececec" stroke-width=".21"/>
<path d="M138.8 71.2l.3 .2-.1 .2-.3-.2z" fill="#ececec"/>
<path d="M138.8 71.2l.3 .2-.1 .2-.3-.2z" fill="none" stroke="#ececec" stroke-width=".21"/>
<path d="M138.1 80.9l.3 .2-.1 .2-.3-.2z" fill="#ececec"/>
<path d="M138.1 80.9l.3 .2-.1 .2-.3-.2z" fill="none" stroke="#ececec" stroke-width=".21"/>
<path d="M138.9 72.6l.3 .2-.1 .2-.3-.2z" fill="#ececec"/>
<path d="M138.9 72.6l.3 .2-.1 .2-.3-.2z" fill="none" stroke="#ececec" stroke-width=".21"/>
<path d="M138.5 76l.4 .2-.2 .1-.3-.1z" fill="#ececec"/>
<path d="M138.5 76l.4 .2-.2 .1-.3-.1z" fill="none" stroke="#ececec" stroke-width=".21"/>
<path d="M136.8 75l.4 .1-.1 .2-.4-.2z" fill="#ececec"/>
<path d="M136.8 75l.4 .1-.1 .2-.4-.2z" fill="none" stroke="#ececec" stroke-width=".21"/>
<path d="M187.8 71.1l.3 .1-.1 .2-.3-.2z" fill="#ececec"/>
<path d="M187.8 71.1l.3 .1-.1 .2-.3-.2z" fill="none" stroke="#ececec" stroke-width=".21"/>
<path d="M187.8 75.4l.3 .2-.1 .2-.3-.2z" fill="#ececec"/>
<path d="M187.8 75.4l.3 .2-.1 .2-.3-.2z" fill="none" stroke="#ececec" stroke-width=".21"/>
<path d="M185.2 72.1l.3 .2-.1 .2-.3-.2z" fill="#ececec"/>
<path d="M185.2 72.1l.3 .2-.1 .2-.3-.2z" fill="none" stroke="#ececec" stroke-width=".21"/>
<path d="M184.9 76.1l.4 .1-.2 .2-.3-.2z" fill="#ececec"/>
<path d="M184.9 76.1l.4 .1-.2 .2-.3-.2z" fill="none" stroke="#ececec" stroke-width=".21"/>
<path d="M183.1 74.7l.3 .2-.1 .2-.3-.2z" fill="#ececec"/>
<path d="M183.1 74.7l.3 .2-.1 .2-.3-.2z" fill="none" stroke="#ececec" stroke-width=".21"/>
<path d="M178.6 65.8l.3 .2-.1 .2-.3-.2z" fill="#ececec"/>
<path d="M178.6 65.8l.3 .2-.1 .2-.3-.2z" fill="none" stroke="#ececec" stroke-width=".21"/>
<path d="M173.5 69.3l.3 .2-.1 .2-.3-.2z" fill="#ececec"/>
<path d="M173.5 69.3l.3 .2-.1 .2-.3-.2z" fill="none" stroke="#ececec" stroke-width=".21"/>
<path d="M176.8 62.8l.3 .1-.1 .2-.3-.2z" fill="#ececec"/>
<path d="M176.8 62.8l.3 .1-.1 .2-.3-.2z" fill="none" stroke="#ececec" stroke-width=".21"/>
<path d="M175.4 71.1l.3 .1-.1 .2-.3-.2z" fill="#ececec"/>
<path d="M175.4 71.1l.3 .1-.1 .2-.3-.2z" fill="none" stroke="#ececec" stroke-width=".21"/>
<path d="M180.2 71.1l.3 .2-.1 .2-.3-.2z" fill="#ececec"/>
<path d="M180.2 71.1l.3 .2-.1 .2-.3-.2z" fill="none" stroke="#ececec" stroke-width=".21"/>
<path d="M177.4 74.2l.3 .2-.1 .2-.3-.2z" fill="#ececec"/>
<path d="M177.4 74.2l.3 .2-.1 .2-.3-.2z" fill="none" stroke="#ececec" stroke-width=".21"/>
<path d="M197.1 62.1l.3 .2-.1 .2-.3-.2z" fill="#ececec"/>
<path d="M197.1 62.1l.3 .2-.1 .2-.3-.2z" fill="none" stroke="#ececec" stroke-width=".21"/>
<path d="M196.6 69.8l.3 .2-.1 .2-.3-.2z" fill="#ececec"/>
<path d="M196.6 69.8l.3 .2-.1 .2-.3-.2z" fill="none" stroke="#ececec" stroke-width=".21"/>
<path d="M192.1 67l.3 .2-.1 .2-.3-.2z" fill="#ececec"/>
<path d="M192.1 67l.3 .2-.1 .2-.3-.2z" fill="none" stroke="#ececec" stroke-width=".21"/>
<path d="M197.2 55.1l.3 .2-.1 .2-.3-.2z" fill="#ececec"/>
<path d="M197.2 55.1l.3 .2-.1 .2-.3-.2z" fill="none" stroke="#ececec" stroke-width=".21"/>
<path d="M193.7 69.8l.3 .2-.1 .2-.4-.2z" fill="#ececec"/>
<path d="M193.7 69.8l.3 .2-.1 .2-.4-.2z" fill="none" stroke="#ececec" stroke-width=".21"/>
<path d="M188.4 68.3l.3 .2-.1 .1-.3-.1z" fill="#ececec"/>
<path d="M188.4 68.3l.3 .2-.1 .1-.3-.1z" fill="none" stroke="#ececec" stroke-width=".21"/>
<path d="M189.8 70.3l.3 .2-.1 .2-.3-.2z" fill="#ececec"/>
<path d="M189.8 70.3l.3 .2-.1 .2-.3-.2z" fill="none" stroke="#ececec" stroke-width=".21"/>
<path d="M169.3 77.3l.3 .2-.1 .2-.3-.2z" fill="#ececec"/>
<path d="M169.3 77.3l.3 .2-.1 .2-.3-.2z" fill="none" stroke="#ececec" stroke-width=".21"/>
<path d="M165.5 80.9l.3 .2-.1 .2-.3-.2z" fill="#ececec"/>
<path d="M165.5 80.9l.3 .2-.1 .2-.3-.2z" fill="none" stroke="#ececec" stroke-width=".21"/>
<path d="M173.7 81l.3 .2-.1 .2-.3-.2z" fill="#ececec"/>
<path d="M173.7 81l.3 .2-.1 .2-.3-.2z" fill="none" stroke="#ececec" stroke-width=".21"/>
<path d="M168.4 82.1l.3 .2-.1 .1-.3-.1z" fill="#ececec"/>
<path d="M168.4 82.1l.3 .2-.1 .1-.3-.1z" fill="none" stroke="#ececec" stroke-width=".21"/>
<path d="M166.1 78.8l.3 .2-.1 .1-.4-.1z" fill="#ececec"/>
<path d="M166.1 78.8l.3 .2-.1 .1-.4-.1z" fill="none" stroke="#ececec" stroke-width=".21"/>
<path d="M172.2 77.1l.4 .2-.2 .1-.3-.1z" fill="#ececec"/>
<path d="M172.2 77.1l.4 .2-.2 .1-.3-.1z" fill="none" stroke="#ececec" stroke-width=".21"/>
<path d="M173.9 78.2l.3 .2-.1 .1-.3-.1z" fill="#ececec"/>
<path d="M173.9 78.2l.3 .2-.1 .1-.3-.1z" fill="none" stroke="#ececec" stroke-width=".21"/>
<path d="M189.8 75.4l.4 .2-.1 .2-.4-.2z" fill="#ececec"/>
<path d="M189.8 75.4l.4 .2-.1 .2-.4-.2z" fill="none" stroke="#ececec" stroke-width=".21"/>
<path d="M196.6 83.8l.3 .2-.1 .2-.3-.2z" fill="#ececec"/>
<path d="M196.6 83.8l.3 .2-.1 .2-.3-.2z" fill="none" stroke="#ececec" stroke-width=".21"/>
<path d="M190.4 81.8l.4 .2-.2 .2-.3-.2z" fill="#ececec"/>
<path d="M190.4 81.8l.4 .2-.2 .2-.3-.2z" fill="none" stroke="#ececec" stroke-width=".21"/>
<path d="M197.5 74.4l.3 .1-.1 .2-.3-.2z" fill="#ececec"/>
<path d="M197.5 74.4l.3 .1-.1 .2-.3-.2z" fill="none" stroke="#ececec" stroke-width=".21"/>
<path d="M173.9 73.3l.3 .1-.1 .2-.3-.2z" fill="#ececec"/>
<path d="M173.9 73.3l.3 .1-.1 .2-.3-.2z" fill="none" stroke="#ececec" stroke-width=".21"/>
<path d="M165.5 74.3l.3 .2-.1 .2-.3-.2z" fill="#ececec"/>
<path d="M165.5 74.3l.3 .2-.1 .2-.3-.2z" fill="none" stroke="#ececec" stroke-width=".21"/>
<path d="M166.8 76.6l.3 .2-.1 .1-.3-.1z" fill="#ececec"/>
<path d="M166.8 76.6l.3 .2-.1 .1-.3-.1z" fill="none" stroke="#ececec" stroke-width=".21"/>
<path d="M166.4 71.8l.3 .2-.1 .2-.3-.2z" fill="#ececec"/>
<path d="M166.4 71.8l.3 .2-.1 .2-.3-.2z" fill="none" stroke="#ececec" stroke-width=".21"/>
<path d="M169.8 68.4l.3 .2-.1 .2-.3-.2z" fill="#ececec"/>
<path d="M169.8 68.4l.3 .2-.1 .2-.3-.2z" fill="none" stroke="#ececec" stroke-width=".21"/>
<path d="M167.2 68.3l.3 .2-.1 .1-.4-.1z" fill="#ececec"/>
<path d="M167.2 68.3l.3 .2-.1 .1-.4-.1z" fill="none" stroke="#ececec" stroke-width=".21"/>
<path d="M184.3 77.7l.3 .2-.1 .1-.4-.1z" fill="#ececec"/>
<path d="M184.3 77.7l.3 .2-.1 .1-.4-.1z" fill="none" stroke="#ececec" stroke-width=".21"/>
<path d="M181.7 75.2l.3 .2-.1 .2-.3-.2z" fill="#ececec"/>
<path d="M181.7 75.2l.3 .2-.1 .2-.3-.2z" fill="none" stroke="#ececec" stroke-width=".21"/>
<path d="M178.1 78.6l.3 .2-.1 .2-.3-.2z" fill="#ececec"/>
<path d="M178.1 78.6l.3 .2-.1 .2-.3-.2z" fill="none" stroke="#ececec" stroke-width=".21"/>
<path d="M177.8 82.4l.3 .2-.1 .2-.3-.2z" fill="#ececec"/>
<path d="M177.8 82.4l.3 .2-.1 .2-.3-.2z" fill="none" stroke="#ececec" stroke-width=".21"/>
<path d="M177.6 81.3l.3 .2-.1 .2-.3-.2z" fill="#ececec"/>
<path d="M177.6 81.3l.3 .2-.1 .2-.3-.2z" fill="none" stroke="#ececec" stroke-width=".21"/>
<path d="M184.8 80.5l.3 .2-.1 .2-.3-.2z" fill="#ececec"/>
<path d="M184.8 80.5l.3 .2-.1 .2-.3-.2z" fill="none" stroke="#ececec" stroke-width=".21"/>
<path d="M183.2 81.4l.3 .2-.1 .2-.4-.2z" fill="#ececec"/>
<path d="M183.2 81.4l.3 .2-.1 .2-.4-.2z" fill="none" stroke="#ececec" stroke-width=".21"/>
<path d="M183.7 84.1l.3 .2-.1 .2-.3-.2z" fill="#ececec"/>
<path d="M183.7 84.1l.3 .2-.1 .2-.3-.2z" fill="none" stroke="#ececec" stroke-width=".21"/>
<path d="M186.8 82.5l.3 .2-.1 .2-.3-.2z" fill="#ececec"/>
<path d="M186.8 82.5l.3 .2-.1 .2-.3-.2z" fill="none" stroke="#ececec" stroke-width=".21"/>
<path d="M185.3 84.4l.3 .1-.1 .2-.3-.2z" fill="#ececec"/>
<path d="M185.3 84.4l.3 .1-.1 .2-.3-.2z" fill="none" stroke="#ececec" stroke-width=".21"/>
<path d="M174.3 142.9l.3 .1-.1 .2-.3-.2z" fill="#ececec"/>
<path d="M174.3 142.9l.3 .1-.1 .2-.3-.2z" fill="none" stroke="#ececec" stroke-width=".21"/>
<path d="M180.5 147.9l.3 .2-.1 .2-.3-.2z" fill="#ececec"/>
<path d="M180.5 147.9l.3 .2-.1 .2-.3-.2z" fill="none" stroke="#ececec" stroke-width=".21"/>
<path d="M159.2 145.6l.3 .2-.1 .1-.3-.1z" fill="#ececec"/>
<path d="M159.2 145.6l.3 .2-.1 .1-.3-.1z" fill="none" stroke="#ececec" stroke-width=".21"/>
<path d="M171.9 144.5l.3 .2-.1 .1-.3-.1z" fill="#ececec"/>
<path d="M171.9 144.5l.3 .2-.1 .1-.3-.1z" fill="none" stroke="#ececec" stroke-width=".21"/>
<path d="M171.8 140.7l.3 .2-.1 .2-.3-.2z" fill="#ececec"/>
<path d="M171.8 140.7l.3 .2-.1 .2-.3-.2z" fill="none" stroke="#ececec" stroke-width=".21"/>
<path d="M150.3 145.4l.3 .2-.1 .2-.3-.2z" fill="#ececec"/>
<path d="M150.3 145.4l.3 .2-.1 .2-.3-.2z" fill="none" stroke="#ececec" stroke-width=".21"/>
<path d="M143.7 145.4l.3 .2-.1 .2-.3-.2z" fill="#ececec"/>
<path d="M143.7 145.4l.3 .2-.1 .2-.3-.2z" fill="none" stroke="#ececec" stroke-width=".21"/>
<path d="M151.2 140.7l.4 .2-.2 .2-.3-.2z" fill="#ececec"/>
<path d="M151.2 140.7l.4 .2-.2 .2-.3-.2z" fill="none" stroke="#ececec" stroke-width=".21"/>
<path d="M146.3 138.9l.3 .2-.1 .2-.3-.2z" fill="#ececec"/>
<path d="M146.3 138.9l.3 .2-.1 .2-.3-.2z" fill="none" stroke="#ececec" stroke-width=".21"/>
<path d="M144.7 143.4l.3 .2-.1 .2-.3-.2z" fill="#ececec"/>
<path d="M144.7 143.4l.3 .2-.1 .2-.3-.2z" fill="none" stroke="#ececec" stroke-width=".21"/>
<path d="M136.2 139.2l.3 .2-.1 .2-.3-.2z" fill="#ececec"/>
<path d="M136.2 139.2l.3 .2-.1 .2-.3-.2z" fill="none" stroke="#ececec" stroke-width=".21"/>
<path d="M134.2 140l.3 .2-.1 .2-.3-.2z" fill="#ececec"/>
<path d="M134.2 140l.3 .2-.1 .2-.3-.2z" fill="none" stroke="#ececec" stroke-width=".21"/>
<path d="M138.5 138.7l.4 .2-.2 .2-.3-.2z" fill="#ececec"/>
<path d="M138.5 138.7l.4 .2-.2 .2-.3-.2z" fill="none" stroke="#ececec" stroke-width=".21"/>
<path d="M136 141.5l.3 .2-.1 .2-.3-.2z" fill="#ececec"/>
<path d="M136 141.5l.3 .2-.1 .2-.3-.2z" fill="none" stroke="#ececec" stroke-width=".21"/>
<path d="M141.1 140.2l.3 .2-.1 .2-.3-.2z" fill="#ececec"/>
<path d="M141.1 140.2l.3 .2-.1 .2-.3-.2z" fill="none" stroke="#ececec" stroke-width=".21"/>
<path d="M134.5 136.9l.3 .2-.1 .2-.3-.2z" fill="#ececec"/>
<path d="M134.5 136.9l.3 .2-.1 .2-.3-.2z" fill="none" stroke="#ececec" stroke-width=".21"/>
<path d="M139.4 132.7l.3 .2-.1 .2-.3-.2z" fill="#ececec"/>
<path d="M139.4 132.7l.3 .2-.1 .2-.3-.2z" fill="none" stroke="#ececec" stroke-width=".21"/>
<path d="M137 135.7l.3 .1-.1 .2-.3-.2z" fill="#ececec"/>
<path d="M137 135.7l.3 .1-.1 .2-.3-.2z" fill="none" stroke="#ececec" stroke-width=".21"/>
<path d="M138.5 132.3l.3 .2-.1 .1-.4-.1z" fill="#ececec"/>
<path d="M138.5 132.3l.3 .2-.1 .1-.4-.1z" fill="none" stroke="#ececec" stroke-width=".21"/>
<path d="M140.2 132.8l.3 .2-.1 .2-.3-.2z" fill="#ececec"/>
<path d="M140.2 132.8l.3 .2-.1 .2-.3-.2z" fill="none" stroke="#ececec" stroke-width=".21"/>
<path d="M134.2 145.3l.3 .2-.1 .2-.3-.2z" fill="#ececec"/>
<path d="M134.2 145.3l.3 .2-.1 .2-.3-.2z" fill="none" stroke="#ececec" stroke-width=".21"/>
<path d="M136 145.3l.3 .2-.1 .2-.3-.2z" fill="#ececec"/>
<path d="M136 145.3l.3 .2-.1 .2-.3-.2z" fill="none" stroke="#ececec" stroke-width=".21"/>
<path d="M139 145.1l.4 .2-.1 .2-.4-.2z" fill="#ececec"/>
<path d="M139 145.1l.4 .2-.1 .2-.4-.2z" fill="none" stroke="#ececec" stroke-width=".21"/>
<path d="M141.1 145.7l.3 .2-.1 .2-.3-.2z" fill="#ececec"/>
<path d="M141.1 145.7l.3 .2-.1 .2-.3-.2z" fill="none" stroke="#ececec" stroke-width=".21"/>
<path d="M143.1 136.1l.3 .2-.1 .2-.3-.2z" fill="#ececec"/>
<path d="M143.1 136.1l.3 .2-.1 .2-.3-.2z" fill="none" stroke="#ececec" stroke-width=".21"/>
<path d="M142.9 141.7l.3 .2-.1 .1-.4-.1z" fill="#ececec"/>
<path d="M142.9 141.7l.3 .2-.1 .1-.4-.1z" fill="none" stroke="#ececec" stroke-width=".21"/>
<path d="M142.6 143l.3 .2-.1 .2-.3-.2z" fill="#ececec"/>
<path d="M142.6 143l.3 .2-.1 .2-.3-.2z" fill="none" stroke="#ececec" stroke-width=".21"/>
<path d="M143.3 140.7l.3 .1-.1 .2-.3-.2z" fill="#ececec"/>
<path d="M143.3 140.7l.3 .1-.1 .2-.3-.2z" fill="none" stroke="#ececec" stroke-width=".21"/>
<path d="M142.6 139l.3 .1-.1 .2-.3-.2z" fill="#ececec"/>
<path d="M142.6 139l.3 .1-.1 .2-.3-.2z" fill="none" stroke="#ececec" stroke-width=".21"/>
<path d="M141.8 137.4l.4 .1-.2 .2-.3-.2z" fill="#ececec"/>
<path d="M141.8 137.4l.4 .1-.2 .2-.3-.2z" fill="none" stroke="#ececec" stroke-width=".21"/>
<path d="M154.7 135.8l.3 .2-.1 .2-.3-.2z" fill="#ececec"/>
<path d="M154.7 135.8l.3 .2-.1 .2-.3-.2z" fill="none" stroke="#ececec" stroke-width=".21"/>
<path d="M166 133.5l.3 .2-.1 .2-.3-.2z" fill="#ececec"/>
<path d="M166 133.5l.3 .2-.1 .2-.3-.2z" fill="none" stroke="#ececec" stroke-width=".21"/>
<path d="M167.8 138.2l.3 .2-.1 .2-.3-.2z" fill="#ececec"/>
<path d="M167.8 138.2l.3 .2-.1 .2-.3-.2z" fill="none" stroke="#ececec" stroke-width=".21"/>
<path d="M157.1 136.1l.3 .2-.1 .2-.3-.2z" fill="#ececec"/>
<path d="M157.1 136.1l.3 .2-.1 .2-.3-.2z" fill="none" stroke="#ececec" stroke-width=".21"/>
<path d="M163.4 136.8l.3 .2-.1 .2-.3-.2z" fill="#ececec"/>
<path d="M163.4 136.8l.3 .2-.1 .2-.3-.2z" fill="none" stroke="#ececec" stroke-width=".21"/>
<path d="M159.1 134.9l.3 .2-.1 .2-.3-.2z" fill="#ececec"/>
<path d="M159.1 134.9l.3 .2-.1 .2-.3-.2z" fill="none" stroke="#ececec" stroke-width=".21"/>
<path d="M156.5 138.7l.3 .2-.1 .2-.3-.2z" fill="#ececec"/>
<path d="M156.5 138.7l.3 .2-.1 .2-.3-.2z" fill="none" stroke="#ececec" stroke-width=".21"/>
<path d="M157.1 133.5l.3 .1-.1 .2-.3-.2z" fill="#ececec"/>
<path d="M157.1 133.5l.3 .1-.1 .2-.3-.2z" fill="none" stroke="#ececec" stroke-width=".21"/>
<path d="M160.5 131.5l.3 .2-.1 .2-.3-.2z" fill="#ececec"/>
<path d="M160.5 131.5l.3 .2-.1 .2-.3-.2z" fill="none" stroke="#ececec" stroke-width=".21"/>
<path d="M157.5 126.6l.3 .2-.1 .2-.3-.2z" fill="#ececec"/>
<path d="M157.5 126.6l.3 .2-.1 .2-.3-.2z" fill="none" stroke="#ececec" stroke-width=".21"/>
<path d="M164.4 132.8l.3 .2-.1 .2-.3-.2z" fill="#ececec"/>
<path d="M164.4 132.8l.3 .2-.1 .2-.3-.2z" fill="none" stroke="#ececec" stroke-width=".21"/>
<path d="M165.9 122.2l.3 .2-.1 .2-.3-.2z" fill="#ececec"/>
<path d="M165.9 122.2l.3 .2-.1 .2-.3-.2z" fill="none" stroke="#ececec" stroke-width=".21"/>
<path d="M164.4 131.4l.4 .2-.1 .2-.4-.2z" fill="#ececec"/>
<path d="M164.4 131.4l.4 .2-.1 .2-.4-.2z" fill="none" stroke="#ececec" stroke-width=".21"/>
<path d="M166.7 126.4l.3 .2-.1 .2-.3-.2z" fill="#ececec"/>
<path d="M166.7 126.4l.3 .2-.1 .2-.3-.2z" fill="none" stroke="#ececec" stroke-width=".21"/>
<path d="M151.8 135.8l.3 .2-.1 .2-.3-.2z" fill="#ececec"/>
<path d="M151.8 135.8l.3 .2-.1 .2-.3-.2z" fill="none" stroke="#ececec" stroke-width=".21"/>
<path d="M148.9 138.9l.3 .2-.1 .2-.3-.2z" fill="#ececec"/>
<path d="M148.9 138.9l.3 .2-.1 .2-.3-.2z" fill="none" stroke="#ececec" stroke-width=".21"/>
<path d="M148.5 137.2l.3 .2-.1 .2-.3-.2z" fill="#ececec"/>
<path d="M148.5 137.2l.3 .2-.1 .2-.3-.2z" fill="none" stroke="#ececec" stroke-width=".21"/>
<path d="M146.4 135.7l.3 .2-.1 .2-.3-.2z" fill="#ececec"/>
<path d="M146.4 135.7l.3 .2-.1 .2-.3-.2z" fill="none" stroke="#ececec" stroke-width=".21"/>
<path d="M144.6 137.7l.3 .2-.1 .2-.4-.2z" fill="#ececec"/>
<path d="M144.6 137.7l.3 .2-.1 .2-.4-.2z" fill="none" stroke="#ececec" stroke-width=".21"/>
<path d="M151.2 127.4l.3 .2-.1 .1-.4-.1z" fill="#ececec"/>
<path d="M151.2 127.4l.3 .2-.1 .1-.4-.1z" fill="none" stroke="#ececec" stroke-width=".21"/>
<path d="M151.2 124.2l.3 .2-.1 .2-.4-.2z" fill="#ececec"/>
<path d="M151.2 124.2l.3 .2-.1 .2-.4-.2z" fill="none" stroke="#ececec" stroke-width=".21"/>
<path d="M152.4 122.1l.3 .2-.1 .2-.3-.2z" fill="#ececec"/>
<path d="M152.4 122.1l.3 .2-.1 .2-.3-.2z" fill="none" stroke="#ececec" stroke-width=".21"/>
<path d="M152.2 133l.3 .2-.1 .2-.3-.2z" fill="#ececec"/>
<path d="M152.2 133l.3 .2-.1 .2-.3-.2z" fill="none" stroke="#ececec" stroke-width=".21"/>
<path d="M151.2 131.7l.3 .2-.1 .2-.4-.2z" fill="#ececec"/>
<path d="M151.2 131.7l.3 .2-.1 .2-.4-.2z" fill="none" stroke="#ececec" stroke-width=".21"/>
<path d="M154.3 132.4l.3 .1-.1 .2-.3-.2z" fill="#ececec"/>
<path d="M154.3 132.4l.3 .1-.1 .2-.3-.2z" fill="none" stroke="#ececec" stroke-width=".21"/>
<path d="M152.8 129.3l.4 .2-.1 .2-.4-.2z" fill="#ececec"/>
<path d="M152.8 129.3l.4 .2-.1 .2-.4-.2z" fill="none" stroke="#ececec" stroke-width=".21"/>
<path d="M144.8 134.1l.3 .2-.1 .2-.3-.2z" fill="#ececec"/>
<path d="M144.8 134.1l.3 .2-.1 .2-.3-.2z" fill="none" stroke="#ececec" stroke-width=".21"/>
<path d="M145.6 131.8l.3 .2-.1 .2-.3-.2z" fill="#ececec"/>
<path d="M145.6 131.8l.3 .2-.1 .2-.3-.2z" fill="none" stroke="#ececec" stroke-width=".21"/>
<path d="M147.9 133.4l.3 .2-.1 .1-.4-.1z" fill="#ececec"/>
<path d="M147.9 133.4l.3 .2-.1 .1-.4-.1z" fill="none" stroke="#ececec" stroke-width=".21"/>
<path d="M144.5 134.8l.3 .2-.1 .2-.3-.2z" fill="#ececec"/>
<path d="M144.5 134.8l.3 .2-.1 .2-.3-.2z" fill="none" stroke="#ececec" stroke-width=".21"/>
<path d="M147.4 129.5l.3 .2-.1 .2-.3-.2z" fill="#ececec"/>
<path d="M147.4 129.5l.3 .2-.1 .2-.3-.2z" fill="none" stroke="#ececec" stroke-width=".21"/>
<path d="M163.3 114.1l.4 .2-.1 .1-.4-.1z" fill="#ececec"/>
<path d="M163.3 114.1l.4 .2-.1 .1-.4-.1z" fill="none" stroke="#ececec" stroke-width=".21"/>
<path d="M158.9 113.6l.3 .2-.1 .2-.4-.2z" fill="#ececec"/>
<path d="M158.9 113.6l.3 .2-.1 .2-.4-.2z" fill="none" stroke="#ececec" stroke-width=".21"/>
<path d="M160.4 120.1l.3 .2-.1 .2-.3-.2z" fill="#ececec"/>
<path d="M160.4 120.1l.3 .2-.1 .2-.3-.2z" fill="none" stroke="#ececec" stroke-width=".21"/>
<path d="M164.4 118.8l.3 .2-.1 .2-.3-.2z" fill="#ececec"/>
<path d="M164.4 118.8l.3 .2-.1 .2-.3-.2z" fill="none" stroke="#ececec" stroke-width=".21"/>
<path d="M175.5 113.6l.4 .1-.2 .2-.3-.2z" fill="#ececec"/>
<path d="M175.5 113.6l.4 .1-.2 .2-.3-.2z" fill="none" stroke="#ececec" stroke-width=".21"/>
<path d="M179.2 115.1l.3 .2-.1 .2-.3-.2z" fill="#ececec"/>
<path d="M179.2 115.1l.3 .2-.1 .2-.3-.2z" fill="none" stroke="#ececec" stroke-width=".21"/>
<path d="M181.6 126.9l.3 .2-.1 .2-.4-.2z" fill="#ececec"/>
<path d="M181.6 126.9l.3 .2-.1 .2-.4-.2z" fill="none" stroke="#ececec" stroke-width=".21"/>
<path d="M175.4 118.2l.3 .2-.1 .2-.3-.2z" fill="#ececec"/>
<path d="M175.4 118.2l.3 .2-.1 .2-.3-.2z" fill="none" stroke="#ececec" stroke-width=".21"/>
<path d="M174.2 122.6l.3 .2-.1 .2-.3-.2z" fill="#ececec"/>
<path d="M174.2 122.6l.3 .2-.1 .2-.3-.2z" fill="none" stroke="#ececec" stroke-width=".21"/>
<path d="M177.7 119.1l.3 .2-.1 .2-.4-.2z" fill="#ececec"/>
<path d="M177.7 119.1l.3 .2-.1 .2-.4-.2z" fill="none" stroke="#ececec" stroke-width=".21"/>
<path d="M175.4 128.1l.3 .2-.1 .2-.3-.2z" fill="#ececec"/>
<path d="M175.4 128.1l.3 .2-.1 .2-.3-.2z" fill="none" stroke="#ececec" stroke-width=".21"/>
<path d="M180.4 118.3l.4 .2-.1 .2-.4-.2z" fill="#ececec"/>
<path d="M180.4 118.3l.4 .2-.1 .2-.4-.2z" fill="none" stroke="#ececec" stroke-width=".21"/>
<path d="M170.3 122.9l.3 .2-.1 .2-.3-.2z" fill="#ececec"/>
<path d="M170.3 122.9l.3 .2-.1 .2-.3-.2z" fill="none" stroke="#ececec" stroke-width=".21"/>
<path d="M170 118.2l.3 .2-.1 .2-.4-.2z" fill="#ececec"/>
<path d="M170 118.2l.3 .2-.1 .2-.4-.2z" fill="none" stroke="#ececec" stroke-width=".21"/>
<path d="M166.6 123.5l.4 .2-.1 .1-.4-.1z" fill="#ececec"/>
<path d="M166.6 123.5l.4 .2-.1 .1-.4-.1z" fill="none" stroke="#ececec" stroke-width=".21"/>
<path d="M166.6 117.4l.4 .2-.1 .1-.4-.1z" fill="#ececec"/>
<path d="M166.6 117.4l.4 .2-.1 .1-.4-.1z" fill="none" stroke="#ececec" stroke-width=".21"/>
<path d="M170.7 118.1l.3 .2-.1 .2-.3-.2z" fill="#ececec"/>
<path d="M170.7 118.1l.3 .2-.1 .2-.3-.2z" fill="none" stroke="#ececec" stroke-width=".21"/>
<path d="M170 128.6l.3 .2-.1 .2-.3-.2z" fill="#ececec"/>
<path d="M170 128.6l.3 .2-.1 .2-.3-.2z" fill="none" stroke="#ececec" stroke-width=".21"/>
<path d="M170 115.3l.3 .2-.1 .2-.3-.2z" fill="#ececec"/>
<path d="M170 115.3l.3 .2-.1 .2-.3-.2z" fill="none" stroke="#ececec" stroke-width=".21"/>
<path d="M170.5 120.5l.3 .2-.1 .2-.4-.2z" fill="#ececec"/>
<path d="M170.5 120.5l.3 .2-.1 .2-.4-.2z" fill="none" stroke="#ececec" stroke-width=".21"/>
<path d="M172.4 136.9l.3 .2-.1 .2-.3-.2z" fill="#ececec"/>
<path d="M172.4 136.9l.3 .2-.1 .2-.3-.2z" fill="none" stroke="#ececec" stroke-width=".21"/>
<path d="M175.6 133.1l.3 .2-.1 .2-.3-.2z" fill="#ececec"/>
<path d="M175.6 133.1l.3 .2-.1 .2-.3-.2z" fill="none" stroke="#ececec" stroke-width=".21"/>
<path d="M170.3 132.9l.3 .2-.1 .1-.3-.1z" fill="#ececec"/>
<path d="M170.3 132.9l.3 .2-.1 .1-.3-.1z" fill="none" stroke="#ececec" stroke-width=".21"/>
<path d="M174.6 130.5l.3 .2-.1 .2-.3-.2z" fill="#ececec"/>
<path d="M174.6 130.5l.3 .2-.1 .2-.3-.2z" fill="none" stroke="#ececec" stroke-width=".21"/>
<path d="M169.9 135.2l.3 .2-.1 .2-.3-.2z" fill="#ececec"/>
<path d="M169.9 135.2l.3 .2-.1 .2-.3-.2z" fill="none" stroke="#ececec" stroke-width=".21"/>
<path d="M165.6 139.6l.3 .2-.1 .2-.3-.2z" fill="#ececec"/>
<path d="M165.6 139.6l.3 .2-.1 .2-.3-.2z" fill="none" stroke="#ececec" stroke-width=".21"/>
<path d="M133.8 147.9l.3 .2-.1 .2-.3-.2z" fill="#ececec"/>
<path d="M133.8 147.9l.3 .2-.1 .2-.3-.2z" fill="none" stroke="#ececec" stroke-width=".21"/>
<path d="M122.9 148.1l.3 .2-.1 .2-.3-.2z" fill="#ececec"/>
<path d="M122.9 148.1l.3 .2-.1 .2-.3-.2z" fill="none" stroke="#ececec" stroke-width=".21"/>
<path d="M127.4 142.3l.3 .2-.1 .2-.3-.2z" fill="#ececec"/>
<path d="M127.4 142.3l.3 .2-.1 .2-.3-.2z" fill="none" stroke="#ececec" stroke-width=".21"/>
<path d="M127 139.6l.3 .1-.1 .2-.3-.2z" fill="#ececec"/>
<path d="M127 139.6l.3 .1-.1 .2-.3-.2z" fill="none" stroke="#ececec" stroke-width=".21"/>
<path d="M126.9 136.3l.3 .1-.1 .2-.4-.2z" fill="#ececec"/>
<path d="M126.9 136.3l.3 .1-.1 .2-.4-.2z" fill="none" stroke="#ececec" stroke-width=".21"/>
<path d="M132.8 141.4l.3 .2-.1 .2-.3-.2z" fill="#ececec"/>
<path d="M132.8 141.4l.3 .2-.1 .2-.3-.2z" fill="none" stroke="#ececec" stroke-width=".21"/>
<path d="M125.5 131.6l.3 .2-.1 .2-.3-.2z" fill="#ececec"/>
<path d="M125.5 131.6l.3 .2-.1 .2-.3-.2z" fill="none" stroke="#ececec" stroke-width=".21"/>
<path d="M119.5 124.1l.3 .2-.1 .2-.3-.2z" fill="#ececec"/>
<path d="M119.5 124.1l.3 .2-.1 .2-.3-.2z" fill="none" stroke="#ececec" stroke-width=".21"/>
<path d="M127.1 114.9l.3 .2-.1 .2-.3-.2z" fill="#ececec"/>
<path d="M127.1 114.9l.3 .2-.1 .2-.3-.2z" fill="none" stroke="#ececec" stroke-width=".21"/>
<path d="M128.2 128.9l.3 .2-.1 .2-.3-.2z" fill="#ececec"/>
<path d="M128.2 128.9l.3 .2-.1 .2-.3-.2z" fill="none" stroke="#ececec" stroke-width=".21"/>
<path d="M129.3 120.7l.3 .2-.1 .1-.3-.1z" fill="#ececec"/>
<path d="M129.3 120.7l.3 .2-.1 .1-.3-.1z" fill="none" stroke="#ececec" stroke-width=".21"/>
<path d="M132.1 128l.3 .2-.1 .2-.3-.2z" fill="#ececec"/>
<path d="M132.1 128l.3 .2-.1 .2-.3-.2z" fill="none" stroke="#ececec" stroke-width=".21"/>
<path d="M132.7 116l.3 .2-.1 .2-.3-.2z" fill="#ececec"/>
<path d="M132.7 116l.3 .2-.1 .2-.3-.2z" fill="none" stroke="#ececec" stroke-width=".21"/>
<path d="M137.3 108.4l.3 .2-.1 .2-.3-.2z" fill="#ececec"/>
<path d="M137.3 108.4l.3 .2-.1 .2-.3-.2z" fill="none" stroke="#ececec" stroke-width=".21"/>
<path d="M138.5 118.7l.3 .2-.1 .2-.4-.2z" fill="#ececec"/>
<path d="M138.5 118.7l.3 .2-.1 .2-.4-.2z" fill="none" stroke="#ececec" stroke-width=".21"/>
<path d="M140.4 116.3l.3 .2-.1 .1-.3-.1z" fill="#ececec"/>
<path d="M140.4 116.3l.3 .2-.1 .1-.3-.1z" fill="none" stroke="#ececec" stroke-width=".21"/>
<path d="M133 112.3l.3 .2-.1 .2-.3-.2z" fill="#ececec"/>
<path d="M133 112.3l.3 .2-.1 .2-.3-.2z" fill="none" stroke="#ececec" stroke-width=".21"/>
<path d="M138.2 109.4l.3 .2-.1 .2-.3-.2z" fill="#ececec"/>
<path d="M138.2 109.4l.3 .2-.1 .2-.3-.2z" fill="none" stroke="#ececec" stroke-width=".21"/>
<path d="M122.5 142.3l.4 .2-.2 .2-.3-.2z" fill="#ececec"/>
<path d="M122.5 142.3l.4 .2-.2 .2-.3-.2z" fill="none" stroke="#ececec" stroke-width=".21"/>
<path d="M113.1 148l.4 .2-.2 .2-.3-.2z" fill="#ececec"/>
<path d="M113.1 148l.4 .2-.2 .2-.3-.2z" fill="none" stroke="#ececec" stroke-width=".21"/>
<path d="M122.2 133.9l.3 .2-.1 .2-.3-.2z" fill="#ececec"/>
<path d="M122.2 133.9l.3 .2-.1 .2-.3-.2z" fill="none" stroke="#ececec" stroke-width=".21"/>
<path d="M112.9 134.9l.3 .2-.1 .2-.3-.2z" fill="#ececec"/>
<path d="M112.9 134.9l.3 .2-.1 .2-.3-.2z" fill="none" stroke="#ececec" stroke-width=".21"/>
<path d="M117.3 133l.3 .1-.1 .2-.3-.2z" fill="#ececec"/>
<path d="M117.3 133l.3 .1-.1 .2-.3-.2z" fill="none" stroke="#ececec" stroke-width=".21"/>
<path d="M137.9 110.8l.3 .2-.1 .1-.3-.1z" fill="#ececec"/>
<path d="M137.9 110.8l.3 .2-.1 .1-.3-.1z" fill="none" stroke="#ececec" stroke-width=".21"/>
<path d="M143.4 109.1l.3 .2-.1 .2-.3-.2z" fill="#ececec"/>
<path d="M143.4 109.1l.3 .2-.1 .2-.3-.2z" fill="none" stroke="#ececec" stroke-width=".21"/>
<path d="M152.2 108.7l.3 .2-.1 .2-.3-.2z" fill="#ececec"/>
<path d="M152.2 108.7l.3 .2-.1 .2-.3-.2z" fill="none" stroke="#ececec" stroke-width=".21"/>
<path d="M147.9 109.7l.4 .2-.2 .1-.3-.1z" fill="#ececec"/>
<path d="M147.9 109.7l.4 .2-.2 .1-.3-.1z" fill="none" stroke="#ececec" stroke-width=".21"/>
<path d="M151.6 109.3l.3 .2-.1 .2-.3-.2z" fill="#ececec"/>
<path d="M151.6 109.3l.3 .2-.1 .2-.3-.2z" fill="none" stroke="#ececec" stroke-width=".21"/>
<path d="M142.7 109.6l.3 .2-.1 .2-.3-.2z" fill="#ececec"/>
<path d="M142.7 109.6l.3 .2-.1 .2-.3-.2z" fill="none" stroke="#ececec" stroke-width=".21"/>
<path d="M136 119l.3 .2-.1 .2-.3-.2z" fill="#ececec"/>
<path d="M136 119l.3 .2-.1 .2-.3-.2z" fill="none" stroke="#ececec" stroke-width=".21"/>
<path d="M142.9 129.3l.4 .2-.2 .2-.3-.2z" fill="#ececec"/>
<path d="M142.9 129.3l.4 .2-.2 .2-.3-.2z" fill="none" stroke="#ececec" stroke-width=".21"/>
<path d="M140.3 123.3l.3 .2-.1 .2-.3-.2z" fill="#ececec"/>
<path d="M140.3 123.3l.3 .2-.1 .2-.3-.2z" fill="none" stroke="#ececec" stroke-width=".21"/>
<path d="M144 120.2l.4 .2-.2 .1-.3-.1z" fill="#ececec"/>
<path d="M144 120.2l.4 .2-.2 .1-.3-.1z" fill="none" stroke="#ececec" stroke-width=".21"/>
<path d="M143.3 117.6l.3 .2-.1 .2-.3-.2z" fill="#ececec"/>
<path d="M143.3 117.6l.3 .2-.1 .2-.3-.2z" fill="none" stroke="#ececec" stroke-width=".21"/>
<path d="M143.8 124.7l.3 .1-.1 .2-.3-.2z" fill="#ececec"/>
<path d="M143.8 124.7l.3 .1-.1 .2-.3-.2z" fill="none" stroke="#ececec" stroke-width=".21"/>
<path d="M142 127l.3 .2-.1 .2-.3-.2z" fill="#ececec"/>
<path d="M142 127l.3 .2-.1 .2-.3-.2z" fill="none" stroke="#ececec" stroke-width=".21"/>
<path d="M141.6 130.1l.3 .2-.1 .1-.3-.1z" fill="#ececec"/>
<path d="M141.6 130.1l.3 .2-.1 .1-.3-.1z" fill="none" stroke="#ececec" stroke-width=".21"/>
<path d="M127.3 108.7l.3 .1-.1 .2-.3-.2z" fill="#ececec"/>
<path d="M127.3 108.7l.3 .1-.1 .2-.3-.2z" fill="none" stroke="#ececec" stroke-width=".21"/>
<path d="M126.6 110.9l.3 .2-.1 .2-.3-.2z" fill="#ececec"/>
<path d="M126.6 110.9l.3 .2-.1 .2-.3-.2z" fill="none" stroke="#ececec" stroke-width=".21"/>
<path d="M123 98.4l.4 .2-.2 .2-.3-.2z" fill="#ececec"/>
<path d="M123 98.4l.4 .2-.2 .2-.3-.2z" fill="none" stroke="#ececec" stroke-width=".21"/>
<path d="M118.6 108.9l.4 .2-.2 .2-.3-.2z" fill="#ececec"/>
<path d="M118.6 108.9l.4 .2-.2 .2-.3-.2z" fill="none" stroke="#ececec" stroke-width=".21"/>
<path d="M145.2 118.6l.3 .2-.1 .2-.3-.2z" fill="#ececec"/>
<path d="M145.2 118.6l.3 .2-.1 .2-.3-.2z" fill="none" stroke="#ececec" stroke-width=".21"/>
<path d="M148.1 113.6l.3 .1-.1 .2-.3-.2z" fill="#ececec"/>
<path d="M148.1 113.6l.3 .1-.1 .2-.3-.2z" fill="none" stroke="#ececec" stroke-width=".21"/>
<path d="M144.1 113.6l.3 .1-.1 .2-.3-.2z" fill="#ececec"/>
<path d="M144.1 113.6l.3 .1-.1 .2-.3-.2z" fill="none" stroke="#ececec" stroke-width=".21"/>
<path d="M146 117.4l.3 .2-.1 .1-.3-.1z" fill="#ececec"/>
<path d="M146 117.4l.3 .2-.1 .1-.3-.1z" fill="none" stroke="#ececec" stroke-width=".21"/>
<path d="M147.6 118.9l.3 .2-.1 .2-.3-.2z" fill="#ececec"/>
<path d="M147.6 118.9l.3 .2-.1 .2-.3-.2z" fill="none" stroke="#ececec" stroke-width=".21"/>
<path d="M144.2 121.4l.3 .2-.1 .2-.3-.2z" fill="#ececec"/>
<path d="M144.2 121.4l.3 .2-.1 .2-.3-.2z" fill="none" stroke="#ececec" stroke-width=".21"/>
<path d="M144.9 120.9l.3 .2-.1 .2-.3-.2z" fill="#ececec"/>
<path d="M144.9 120.9l.3 .2-.1 .2-.3-.2z" fill="none" stroke="#ececec" stroke-width=".21"/>
<path d="M145 122l.3 .2-.1 .2-.3-.2z" fill="#ececec"/>
<path d="M145 122l.3 .2-.1 .2-.3-.2z" fill="none" stroke="#ececec" stroke-width=".21"/>
<path d="M147.9 110.5l.4 .2-.2 .2-.3-.2z" fill="#ececec"/>
<path d="M147.9 110.5l.4 .2-.2 .2-.3-.2z" fill="none" stroke="#ececec" stroke-width=".21"/>
<path d="M151.2 119l.3 .2-.1 .2-.4-.2z" fill="#ececec"/>
<path d="M151.2 119l.3 .2-.1 .2-.4-.2z" fill="none" stroke="#ececec" stroke-width=".21"/>
<path d="M154.1 121l.3 .2-.1 .2-.3-.2z" fill="#ececec"/>
<path d="M154.1 121l.3 .2-.1 .2-.3-.2z" fill="none" stroke="#ececec" stroke-width=".21"/>
<path d="M151.2 117.9l.3 .2-.1 .2-.4-.2z" fill="#ececec"/>
<path d="M151.2 117.9l.3 .2-.1 .2-.4-.2z" fill="none" stroke="#ececec" stroke-width=".21"/>
<path d="M151.2 115.4l.3 .2-.1 .2-.4-.2z" fill="#ececec"/>
<path d="M151.2 115.4l.3 .2-.1 .2-.4-.2z" fill="none" stroke="#ececec" stroke-width=".21"/>
<path d="M152.4 114.5l.3 .2-.1 .2-.3-.2z" fill="#ececec"/>
<path d="M152.4 114.5l.3 .2-.1 .2-.3-.2z" fill="none" stroke="#ececec" stroke-width=".21"/>
<path d="M154.3 113l.3 .2-.1 .1-.3-.1z" fill="#ececec"/>
<path d="M154.3 113l.3 .2-.1 .1-.3-.1z" fill="none" stroke="#ececec" stroke-width=".21"/>
<path d="M157.5 110.6l.3 .2-.1 .2-.3-.2z" fill="#ececec"/>
<path d="M157.5 110.6l.3 .2-.1 .2-.3-.2z" fill="none" stroke="#ececec" stroke-width=".21"/>
<path d="M160.2 111.5l.3 .2-.1 .2-.3-.2z" fill="#ececec"/>
<path d="M160.2 111.5l.3 .2-.1 .2-.3-.2z" fill="none" stroke="#ececec" stroke-width=".21"/>
<path d="M160.4 110.2l.3 .2-.1 .2-.3-.2z" fill="#ececec"/>
<path d="M160.4 110.2l.3 .2-.1 .2-.3-.2z" fill="none" stroke="#ececec" stroke-width=".21"/>
<path d="M170 126.8l.3 .2-.1 .1-.4-.1z" fill="#ececec"/>
<path d="M170 126.8l.3 .2-.1 .1-.4-.1z" fill="none" stroke="#ececec" stroke-width=".21"/>
<path d="M169.6 120.8l.3 .2-.1 .2-.3-.2z" fill="#ececec"/>
<path d="M169.6 120.8l.3 .2-.1 .2-.3-.2z" fill="none" stroke="#ececec" stroke-width=".21"/>
<path d="M165 128.1l.4 .2-.2 .2-.3-.2z" fill="#ececec"/>
<path d="M165 128.1l.4 .2-.2 .2-.3-.2z" fill="none" stroke="#ececec" stroke-width=".21"/>
<path d="M169.3 131.1l.3 .2-.1 .2-.3-.2z" fill="#ececec"/>
<path d="M169.3 131.1l.3 .2-.1 .2-.3-.2z" fill="none" stroke="#ececec" stroke-width=".21"/>
<path d="M164.7 121.4l.3 .2-.1 .2-.3-.2z" fill="#ececec"/>
<path d="M164.7 121.4l.3 .2-.1 .2-.3-.2z" fill="none" stroke="#ececec" stroke-width=".21"/>
<path d="M168.2 129.1l.3 .2-.1 .2-.3-.2z" fill="#ececec"/>
<path d="M168.2 129.1l.3 .2-.1 .2-.3-.2z" fill="none" stroke="#ececec" stroke-width=".21"/>
<path d="M170 109.9l.3 .2-.1 .2-.3-.2z" fill="#ececec"/>
<path d="M170 109.9l.3 .2-.1 .2-.3-.2z" fill="none" stroke="#ececec" stroke-width=".21"/>
<path d="M169.1 111.4l.3 .1-.1 .2-.3-.2z" fill="#ececec"/>
<path d="M169.1 111.4l.3 .1-.1 .2-.3-.2z" fill="none" stroke="#ececec" stroke-width=".21"/>
<path d="M168.6 112l.3 .2-.1 .2-.3-.2z" fill="#ececec"/>
<path d="M168.6 112l.3 .2-.1 .2-.3-.2z" fill="none" stroke="#ececec" stroke-width=".21"/>
<path d="M168.8 117.3l.3 .2-.1 .2-.3-.2z" fill="#ececec"/>
<path d="M168.8 117.3l.3 .2-.1 .2-.3-.2z" fill="none" stroke="#ececec" stroke-width=".21"/>
<path d="M169.1 101.7l.3 .2-.1 .2-.3-.2z" fill="#ececec"/>
<path d="M169.1 101.7l.3 .2-.1 .2-.3-.2z" fill="none" stroke="#ececec" stroke-width=".21"/>
<g fill="#000">
<path d="M67.9 41.6l.3 .2-.1 .2-.3-.2zM68.2 58.8l.3 .2-.1 .2-.3-.2zM68.5 48.2l.3 .2-.1 .2-.3-.2zM69.4 51.8l.3 .1-.1 .2-.3-.2zM74.4 51.1l.4 .2-.1 .2-.4-.2zM76.1 41.8l.4 .2-.2 .2-.3-.2zM77.2 57.7l.4 .2-.2 .2-.3-.2zM77.8 44.5l.3 .2-.1 .1-.3-.1zM78.4 41.2l.3 .2-.1 .1-.3-.1zM85.4 46.5l.3 .2-.1 .2-.3-.2zM85.6 55.6l.3 .2-.1 .2-.3-.2zM86.9 44.9l.3 .2-.1 .2-.3-.2z"/>
<path d="M90.6 56.4l.3 .2-.1 .2-.3-.2zM92.1 41.2l.3 .2-.1 .1-.4-.1zM94 44.8l.3 .2-.1 .2-.3-.2zM95.9 46.4l.3 .2-.1 .2-.3-.2zM101.4 45.1l.3 .2-.1 .1-.3-.1zM105.8 41.8l.3 .2-.1 .2-.3-.2zM107.6 47.4l.3 .2-.1 .2-.3-.2zM108.2 43.8l.3 .2-.1 .2-.3-.2zM112 49.1l.4 .2-.2 .2-.3-.2zM113.2 52.9l.3 .2-.1 .2-.3-.2zM115.4 51.1l.3 .2-.1 .2-.3-.2zM116.3 44.1l.3 .2-.1 .2-.3-.2z"/>
<path d="M116.7 47.7l.3 .2-.1 .2-.3-.2zM116.9 50.4l.4 .2-.1 .2-.4-.2zM117.5 41.2l.4 .2-.2 .1-.3-.1zM122.5 50.1l.3 .1-.1 .2-.4-.2zM122.6 45.1l.3 .2-.1 .1-.3-.1zM122.8 57.9l.3 .1-.1 .2-.3-.2zM127.6 41.7l.3 .2-.1 .2-.3-.2zM127.8 46.6l.3 .2-.1 .2-.3-.2zM128.1 50.1l.3 .1-.1 .2-.3-.2zM128.9 52.6l.3 .2-.1 .2-.3-.2zM129 57.1l.3 .2-.1 .2-.3-.2zM130 43.6l.3 .2-.1 .2-.3-.2z"/>
<path d="M137.1 43.9l.3 .2-.1 .2-.3-.2zM137.9 58.9l.4 .2-.1 .1-.4-.1zM138 41.8l.3 .2-.1 .2-.3-.2zM138.3 47l.3 .2-.1 .2-.3-.2zM138.5 53.7l.3 .2-.1 .2-.4-.2zM143.6 43.7l.3 .2-.1 .2-.3-.2zM143.7 44.9l.3 .2-.1 .2-.3-.2zM144.5 59.5l.3 .1-.1 .2-.3-.2zM144.7 41.1l.3 .2-.1 .2-.3-.2zM149.3 49.9l.3 .2-.1 .2-.3-.2zM149.4 41.9l.3 .2-.1 .2-.3-.2zM150.7 43.9l.3 .2-.1 .2-.3-.2z"/>
<path d="M153 54.1l.3 .2-.1 .2-.3-.2zM155 59.5l.3 .1-.1 .2-.3-.2zM158.2 44.1l.3 .1-.1 .2-.3-.2zM159.3 41.1l.3 .2-.1 .2-.3-.2zM159.3 54.4l.3 .2-.1 .2-.3-.2zM159.6 46.3l.3 .1-.1 .2-.3-.2zM164.9 45.6l.3 .2-.1 .2-.3-.2zM165 59.3l.4 .2-.2 .2-.3-.2zM165.2 51.3l.3 .2-.1 .2-.3-.2zM165.9 41.9l.3 .2-.1 .2-.3-.2zM167.7 48.8l.4 .2-.1 .2-.4-.2zM169.4 53.2l.4 .2-.2 .2-.3-.2z"/>
<path d="M171.3 58.6l.3 .2-.1 .2-.3-.2zM172.8 51.1l.3 .2-.1 .2-.3-.2zM174.7 53.4l.3 .2-.1 .1-.3-.1zM174.9 59.4l.3 .2-.1 .2-.3-.2zM175.5 49.3l.4 .2-.2 .2-.3-.2zM178 58.9l.3 .2-.1 .1-.3-.1zM178.2 42.7l.4 .2-.1 .2-.4-.2zM178.4 46.7l.3 .2-.1 .2-.3-.2zM179.1 44.5l.3 .2-.1 .1-.3-.1zM182 59.3l.3 .2-.1 .2-.3-.2zM182.1 56.3l.3 .2-.1 .2-.4-.2zM182.3 51.6l.3 .2-.1 .2-.3-.2z"/>
<path d="M186.1 54.8l.3 .2-.1 .2-.3-.2zM187.3 45.4l.3 .2-.1 .2-.3-.2zM188.3 59.3l.3 .2-.1 .2-.3-.2zM188.7 41.8l.4 .2-.1 .2-.4-.2zM188.8 51.8l.3 .1-.1 .2-.3-.2zM189.6 47.3l.3 .2-.1 .1-.3-.1zM189.6 49.3l.3 .2-.1 .2-.3-.2zM197.1 46.8l.3 .1-.1 .2-.3-.2zM197.2 55.1l.3 .2-.1 .2-.3-.2zM68.3 70.9l.3 .2-.1 .2-.3-.2zM75.2 75.7l.3 .2-.1 .2-.3-.2zM80.7 69.9l.3 .2-.1 .1-.3-.1z"/>
<path d="M80.8 61.2l.3 .2-.1 .2-.3-.2zM85.6 63.6l.3 .2-.1 .2-.3-.2zM87.7 66.8l.3 .2-.1 .2-.4-.2zM90.5 62l.3 .2-.1 .2-.3-.2zM91.3 69.1l.3 .2-.1 .2-.3-.2zM96 66.9l.3 .2-.1 .2-.4-.2zM96.3 72l.3 .2-.1 .2-.3-.2zM106.3 72.4l.3 .2-.1 .2-.3-.2zM112.1 74.9l.3 .2-.1 .1-.3-.1zM112.4 67l.3 .2-.1 .2-.3-.2zM112.5 60.9l.4 .2-.1 .2-.4-.2zM112.8 71.4l.3 .2-.1 .2-.3-.2z"/>
<path d="M115.3 65.4l.3 .2-.1 .2-.4-.2zM117.5 72.4l.3 .2-.1 .2-.4-.2zM121.6 64.5l.3 .1-.1 .2-.3-.2zM121.9 71.5l.3 .2-.1 .2-.3-.2zM127.1 64.5l.3 .2-.1 .2-.3-.2zM127.2 75l.3 .2-.1 .2-.3-.2zM128.9 75l.3 .2-.1 .2-.3-.2zM129.9 77.9l.3 .2-.1 .2-.3-.2zM130 64.5l.3 .2-.1 .2-.3-.2zM133.2 64.5l.3 .2-.1 .2-.3-.2zM133.5 74.4l.4 .1-.2 .2-.3-.2zM134.1 79.8l.3 .2-.1 .2-.4-.2z"/>
<path d="M134.2 60.2l.3 .2-.1 .2-.3-.2zM136.8 69.1l.4 .2-.1 .2-.4-.2zM136.8 75l.4 .1-.1 .2-.4-.2zM138 69.7l.3 .2-.1 .2-.3-.2zM138.5 65l.3 .2-.1 .2-.4-.2zM138.5 76l.4 .2-.2 .1-.3-.1zM138.8 71.2l.3 .2-.1 .2-.3-.2zM138.9 72.6l.3 .2-.1 .2-.3-.2zM149.1 74.4l.3 .2-.1 .2-.3-.2zM151.5 64.7l.3 .2-.1 .2-.3-.2zM155 79.4l.3 .2-.1 .2-.3-.2zM155 69.5l.3 .2-.1 .2-.3-.2z"/>
<path d="M159.2 73.9l.3 .1-.1 .2-.3-.2zM159.8 61.9l.3 .2-.1 .2-.3-.2zM163.3 69.5l.3 .1-.1 .2-.3-.2zM163.9 64.7l.3 .2-.1 .2-.4-.2zM165.1 72.2l.3 .2-.1 .2-.3-.2zM165.5 74.3l.3 .2-.1 .2-.3-.2zM165.7 61l.3 .2-.1 .2-.3-.2zM166.1 62.5l.3 .2-.1 .2-.4-.2zM166.1 78.8l.3 .2-.1 .1-.4-.1zM166.4 71.8l.3 .2-.1 .2-.3-.2zM166.8 76.6l.3 .2-.1 .1-.3-.1zM167.2 68.3l.3 .2-.1 .1-.4-.1z"/>
<path d="M167.2 65.5l.4 .2-.2 .1-.3-.1zM167.2 66.4l.4 .2-.2 .2-.3-.2zM168.9 65.8l.3 .2-.1 .2-.4-.2zM169.3 77.3l.3 .2-.1 .2-.3-.2zM169.8 68.4l.3 .2-.1 .2-.3-.2zM171.1 62.2l.3 .2-.1 .1-.4-.1zM171.1 68.2l.3 .2-.1 .2-.3-.2zM172.2 77.1l.4 .2-.2 .1-.3-.1zM173.5 69.3l.3 .2-.1 .2-.3-.2zM173.9 78.2l.3 .2-.1 .1-.3-.1zM173.9 73.3l.3 .1-.1 .2-.3-.2zM174.4 63.9l.3 .2-.1 .2-.4-.2z"/>
<path d="M174.4 62.8l.4 .2-.2 .2-.3-.2zM175.4 64l.3 .2-.1 .2-.3-.2zM175.4 68.2l.3 .2-.1 .2-.3-.2zM175.4 71.1l.3 .1-.1 .2-.3-.2zM176.8 62.8l.3 .1-.1 .2-.3-.2zM177.4 74.2l.3 .2-.1 .2-.3-.2zM177.8 60.6l.3 .1-.1 .2-.3-.2zM178.1 78.6l.3 .2-.1 .2-.3-.2zM178.6 65.8l.3 .2-.1 .2-.3-.2zM180.2 71.1l.3 .2-.1 .2-.3-.2zM181.7 75.2l.3 .2-.1 .2-.3-.2zM181.8 64.2l.3 .2-.1 .2-.3-.2z"/>
<path d="M183.1 74.7l.3 .2-.1 .2-.3-.2zM183.3 61.5l.3 .2-.1 .2-.3-.2zM183.8 66.2l.3 .2-.1 .2-.4-.2zM184.3 77.7l.3 .2-.1 .1-.4-.1zM184.9 76.1l.4 .1-.2 .2-.3-.2zM185.2 72.1l.3 .2-.1 .2-.3-.2zM185.9 66.5l.3 .2-.1 .2-.3-.2zM187.8 65.8l.3 .2-.1 .2-.3-.2zM187.8 71.1l.3 .1-.1 .2-.3-.2zM187.8 75.4l.3 .2-.1 .2-.3-.2zM188.2 60.8l.4 .2-.2 .2-.3-.2zM188.4 68.3l.3 .2-.1 .1-.3-.1z"/>
<path d="M189.8 70.3l.3 .2-.1 .2-.3-.2zM189.8 75.4l.4 .2-.1 .2-.4-.2zM192.1 67l.3 .2-.1 .2-.3-.2zM193.7 69.8l.3 .2-.1 .2-.4-.2zM196.6 69.8l.3 .2-.1 .2-.3-.2zM197.1 62.1l.3 .2-.1 .2-.3-.2zM197.5 74.4l.3 .1-.1 .2-.3-.2zM73 81.4l.3 .2-.1 .2-.3-.2zM75.3 96.7l.3 .2-.1 .2-.3-.2zM79.4 97.6l.4 .2-.2 .2-.3-.2zM79.5 85.7l.3 .2-.1 .2-.3-.2zM81.6 88.1l.3 .2-.1 .2-.4-.2z"/>
<path d="M83.4 98.5l.3 .2-.1 .2-.3-.2zM84.9 88.3l.3 .2-.1 .2-.3-.2zM85.5 92.9l.3 .2-.1 .2-.4-.2zM86 86.6l.3 .1-.1 .2-.3-.2zM86.8 90.9l.3 .2-.1 .1-.3-.1zM87.1 83.3l.3 .1-.1 .2-.3-.2zM89 99.7l.3 .2-.1 .2-.3-.2zM93.2 90l.3 .2-.1 .2-.4-.2zM93.8 86.8l.3 .2-.1 .2-.3-.2zM97.1 96.2l.3 .2-.1 .2-.4-.2zM98.3 86.2l.3 .2-.1 .2-.3-.2zM98.7 92.4l.3 .2-.1 .2-.3-.2z"/>
<path d="M99.7 90l.3 .2-.1 .2-.3-.2zM100.8 96.2l.3 .2-.1 .2-.3-.2zM101.6 83.7l.3 .2-.1 .2-.3-.2zM104.8 96.5l.3 .2-.1 .2-.4-.2zM107.5 87.7l.3 .1-.1 .2-.3-.2zM108.7 86.4l.3 .2-.1 .2-.4-.2zM109.2 92.6l.3 .2-.1 .2-.3-.2zM109.6 91.2l.3 .2-.1 .2-.3-.2zM109.6 94.3l.3 .1-.1 .2-.3-.2zM109.8 99.3l.4 .2-.2 .2-.3-.2zM110.4 93.2l.3 .1-.1 .2-.3-.2zM110.7 90.1l.3 .2-.1 .2-.3-.2z"/>
<path d="M111.3 95.3l.3 .2-.1 .1-.3-.1zM111.8 88.5l.3 .2-.1 .2-.3-.2zM113.4 82.8l.3 .2-.1 .2-.3-.2zM114.6 92.1l.3 .1-.1 .2-.3-.2zM114.7 90.3l.3 .2-.1 .2-.3-.2zM115.1 96l.3 .2-.1 .2-.3-.2zM115.3 93.8l.3 .2-.1 .2-.4-.2zM116.3 91.8l.3 .2-.1 .2-.3-.2zM116.9 90.3l.3 .2-.1 .2-.3-.2zM118.4 85.6l.3 .2-.1 .2-.3-.2zM119.9 94.4l.3 .2-.1 .2-.3-.2zM121.4 96.1l.3 .2-.1 .2-.4-.2z"/>
<path d="M122 82.5l.3 .2-.1 .2-.3-.2zM123 98.4l.4 .2-.2 .2-.3-.2zM125.2 94.4l.4 .2-.1 .2-.4-.2zM125.7 85.6l.3 .2-.1 .2-.3-.2zM126.9 92.6l.3 .2-.1 .2-.4-.2zM127 84.5l.3 .2-.1 .2-.3-.2zM127.8 93.9l.3 .2-.1 .2-.3-.2zM128.9 96.4l.3 .2-.1 .2-.3-.2zM129.5 84.5l.3 .2-.1 .2-.3-.2zM129.7 86.4l.3 .2-.1 .2-.3-.2zM131.4 99.1l.3 .2-.1 .2-.3-.2zM133.4 91.2l.3 .2-.1 .2-.3-.2z"/>
<path d="M133.6 84.8l.3 .2-.1 .2-.3-.2zM133.6 94.2l.3 .2-.1 .1-.3-.1zM133.7 82.2l.3 .1-.1 .2-.3-.2zM134 89.7l.3 .2-.1 .2-.3-.2zM137.4 98.1l.4 .2-.2 .1-.3-.1zM138.1 80.9l.3 .2-.1 .2-.3-.2zM143.2 99.1l.3 .2-.1 .2-.3-.2zM143.9 96.4l.3 .2-.1 .2-.3-.2zM145.9 93.7l.3 .2-.1 .2-.3-.2zM146.5 95.2l.3 .2-.1 .2-.3-.2zM147.7 95l.3 .2-.1 .2-.3-.2zM148.4 84.8l.4 .2-.2 .2-.3-.2z"/>
<path d="M149.8 87.3l.3 .2-.1 .2-.3-.2zM149.8 91l.3 .2-.1 .2-.3-.2zM151.2 94.9l.3 .2-.1 .2-.4-.2zM151.7 97.7l.3 .2-.1 .2-.3-.2zM153 93.6l.3 .2-.1 .2-.3-.2zM155 85.3l.3 .2-.1 .2-.3-.2zM155 91.8l.4 .2-.1 .2-.4-.2zM155.4 95.1l.3 .2-.1 .2-.3-.2zM156.6 96l.3 .2-.1 .2-.3-.2zM158.3 91.7l.3 .2-.1 .2-.3-.2zM158.4 82l.3 .2-.1 .2-.4-.2zM158.4 88.9l.3 .2-.1 .2-.3-.2z"/>
<path d="M160.2 98.3l.3 .2-.1 .2-.3-.2zM161 97l.3 .2-.1 .1-.3-.1zM161.1 99.2l.4 .2-.2 .1-.3-.1zM161.2 93.4l.3 .2-.1 .2-.3-.2zM161.4 84.8l.3 .2-.1 .2-.3-.2zM162.3 91l.3 .2-.1 .2-.3-.2zM162.7 88.8l.3 .2-.1 .2-.3-.2zM163.3 88l.3 .2-.1 .2-.3-.2zM164.3 99.3l.3 .1-.1 .2-.3-.2zM164.3 94.3l.3 .1-.1 .2-.3-.2zM164.4 97.1l.3 .2-.1 .2-.3-.2zM165.4 90.7l.3 .2-.1 .2-.3-.2z"/>
<path d="M165.5 93.2l.3 .2-.1 .2-.3-.2zM165.5 80.9l.3 .2-.1 .2-.3-.2zM165.8 98.8l.3 .2-.1 .2-.3-.2zM166 97l.3 .2-.1 .1-.3-.1zM166.1 85.2l.4 .2-.2 .2-.3-.2zM166.1 87.3l.4 .2-.2 .2-.3-.2zM166.5 94.5l.3 .2-.1 .2-.3-.2zM166.8 89.5l.3 .2-.1 .2-.3-.2zM166.8 91.6l.3 .2-.1 .2-.3-.2zM168.4 82.1l.3 .2-.1 .1-.3-.1zM170 85.5l.3 .2-.1 .2-.3-.2zM170.1 95.7l.3 .2-.1 .2-.3-.2z"/>
<path d="M170.5 92.6l.3 .2-.1 .2-.4-.2zM170.5 94.4l.4 .2-.2 .2-.3-.2zM171.9 83.2l.3 .2-.1 .1-.3-.1zM172 87.4l.3 .2-.1 .2-.3-.2zM173.7 81l.3 .2-.1 .2-.3-.2zM173.8 96l.3 .1-.1 .2-.3-.2zM173.9 97.7l.3 .2-.1 .2-.3-.2zM174.3 88.8l.3 .2-.1 .2-.3-.2zM174.4 94.4l.3 .2-.1 .2-.4-.2zM174.4 84.4l.4 .2-.2 .2-.3-.2zM174.6 91.6l.3 .2-.1 .2-.3-.2zM175.6 95.6l.3 .2-.1 .2-.3-.2z"/>
<path d="M176 97.7l.3 .2-.1 .2-.3-.2zM176.6 89.3l.4 .2-.2 .2-.3-.2zM176.7 87.3l.3 .2-.1 .2-.3-.2zM177.3 93.1l.3 .2-.1 .1-.3-.1zM177.6 81.3l.3 .2-.1 .2-.3-.2zM177.7 99.5l.3 .2-.1 .2-.4-.2zM177.8 83.4l.3 .2-.1 .2-.3-.2zM177.8 82.4l.3 .2-.1 .2-.3-.2zM178.3 85.3l.3 .2-.1 .2-.3-.2zM178.9 91.1l.3 .2-.1 .2-.3-.2zM179.9 88.9l.3 .2-.1 .2-.4-.2zM180.3 91.8l.3 .2-.1 .2-.3-.2z"/>
<path d="M181 86.8l.4 .2-.2 .2-.3-.2zM181.2 94.4l.3 .2-.1 .2-.3-.2zM181.6 92.3l.3 .2-.1 .2-.3-.2zM183.2 81.4l.3 .2-.1 .2-.4-.2zM183.7 84.1l.3 .2-.1 .2-.3-.2zM184.8 80.5l.3 .2-.1 .2-.3-.2zM185.3 84.4l.3 .1-.1 .2-.3-.2zM185.9 85.8l.3 .2-.1 .2-.3-.2zM186.4 88.9l.3 .2-.1 .2-.3-.2zM186.8 82.5l.3 .2-.1 .2-.3-.2zM187.1 93.2l.4 .2-.2 .2-.3-.2zM187.7 91.8l.3 .2-.1 .2-.3-.2z"/>
<path d="M187.8 99l.3 .2-.1 .2-.3-.2zM188.2 86.7l.3 .2-.1 .2-.4-.2zM190.2 99.3l.3 .1-.1 .2-.3-.2zM190.4 81.8l.4 .2-.2 .2-.3-.2zM190.5 91.6l.3 .2-.1 .2-.3-.2zM196.2 91.5l.3 .2-.1 .1-.3-.1zM196.6 83.8l.3 .2-.1 .2-.3-.2zM95.1 101.2l.3 .2-.1 .2-.3-.2zM97.4 106.6l.3 .2-.1 .2-.3-.2zM103.5 111.3l.3 .2-.1 .2-.3-.2zM103.5 107.3l.3 .2-.1 .2-.3-.2zM104 100.5l.3 .2-.1 .2-.3-.2z"/>
<path d="M104.5 103.9l.3 .2-.1 .2-.3-.2zM105.9 114.2l.4 .1-.2 .2-.3-.2zM106.5 105.4l.3 .2-.1 .2-.3-.2zM107.6 112.8l.3 .2-.1 .2-.3-.2zM111.7 109.5l.3 .2-.1 .2-.3-.2zM114.1 100.9l.3 .1-.1 .2-.3-.2zM118.6 108.9l.4 .2-.2 .2-.3-.2zM121.2 105.3l.3 .2-.1 .2-.3-.2zM125.4 101.1l.3 .2-.1 .2-.3-.2zM126.6 110.9l.3 .2-.1 .2-.3-.2zM127.1 106.4l.3 .2-.1 .2-.3-.2zM127.1 114.9l.3 .2-.1 .2-.3-.2z"/>
<path d="M127.3 108.7l.3 .1-.1 .2-.3-.2zM132.4 107.2l.4 .2-.2 .2-.3-.2zM132.6 105.1l.3 .2-.1 .2-.3-.2zM132.6 100.4l.3 .1-.1 .2-.3-.2zM132.7 116l.3 .2-.1 .2-.3-.2zM133 112.3l.3 .2-.1 .2-.3-.2zM134.4 104.8l.3 .2-.1 .2-.3-.2zM135.2 105.5l.4 .2-.2 .2-.3-.2zM135.7 118.1l.3 .2-.1 .2-.3-.2zM135.9 106.4l.3 .2-.1 .1-.3-.1zM136 119l.3 .2-.1 .2-.3-.2zM136.5 103.7l.3 .1-.1 .2-.3-.2z"/>
<path d="M137 106.4l.3 .2-.1 .1-.3-.1zM137 112.8l.3 .2-.1 .2-.3-.2zM137.3 108.4l.3 .2-.1 .2-.3-.2zM137.5 107.3l.3 .2-.1 .2-.3-.2zM137.9 110.8l.3 .2-.1 .1-.3-.1zM138.2 109.4l.3 .2-.1 .2-.3-.2zM138.5 118.7l.3 .2-.1 .2-.4-.2zM140.4 116.3l.3 .2-.1 .1-.3-.1zM142.7 109.6l.3 .2-.1 .2-.3-.2zM143.3 117.6l.3 .2-.1 .2-.3-.2zM143.4 109.1l.3 .2-.1 .2-.3-.2zM144.1 113.6l.3 .1-.1 .2-.3-.2z"/>
<path d="M144.6 106l.3 .2-.1 .2-.3-.2zM144.6 107.5l.3 .2-.1 .1-.3-.1zM145.2 104.3l.3 .2-.1 .2-.3-.2zM145.2 118.6l.3 .2-.1 .2-.3-.2zM146 117.4l.3 .2-.1 .1-.3-.1zM146.2 107.6l.3 .1-.1 .2-.4-.2zM146.4 102.6l.3 .1-.1 .2-.3-.2zM146.9 100.5l.3 .2-.1 .2-.3-.2zM147.4 103.7l.3 .1-.1 .2-.3-.2zM147.4 101.5l.3 .1-.1 .2-.3-.2zM147.6 118.9l.3 .2-.1 .2-.3-.2zM147.8 106.1l.3 .2-.1 .2-.3-.2z"/>
<path d="M147.9 109.7l.4 .2-.2 .1-.3-.1zM147.9 110.5l.4 .2-.2 .2-.3-.2zM148.1 113.6l.3 .1-.1 .2-.3-.2zM151.2 119l.3 .2-.1 .2-.4-.2zM151.2 117.9l.3 .2-.1 .2-.4-.2zM151.2 115.4l.3 .2-.1 .2-.4-.2zM151.3 107.3l.3 .2-.1 .2-.3-.2zM151.6 109.3l.3 .2-.1 .2-.3-.2zM151.9 104.9l.3 .2-.1 .2-.3-.2zM152.2 108.7l.3 .2-.1 .2-.3-.2zM152.4 114.5l.3 .2-.1 .2-.3-.2zM153 104.9l.3 .2-.1 .2-.3-.2z"/>
<path d="M153.2 106.6l.3 .2-.1 .2-.3-.2zM154.3 113l.3 .2-.1 .1-.3-.1zM156 101.3l.3 .2-.1 .2-.3-.2zM156.2 106.6l.3 .2-.1 .2-.4-.2zM157.5 110.6l.3 .2-.1 .2-.3-.2zM157.9 101.5l.3 .1-.1 .2-.3-.2zM158.9 113.6l.3 .2-.1 .2-.4-.2zM160.2 105.9l.3 .1-.1 .2-.3-.2zM160.2 111.5l.3 .2-.1 .2-.3-.2zM160.3 107.1l.3 .2-.1 .2-.3-.2zM160.4 110.2l.3 .2-.1 .2-.3-.2zM160.6 102.8l.3 .2-.1 .2-.4-.2z"/>
<path d="M163.3 114.1l.4 .2-.1 .1-.4-.1zM164.2 108.5l.3 .2-.1 .2-.3-.2zM164.3 100.3l.3 .2-.1 .1-.3-.1zM164.4 118.8l.3 .2-.1 .2-.3-.2zM164.4 105l.4 .2-.1 .2-.4-.2zM165 108.1l.3 .2-.1 .2-.4-.2zM165.5 103.4l.4 .2-.1 .2-.4-.2zM166.6 117.4l.4 .2-.1 .1-.4-.1zM167.2 106.6l.3 .2-.1 .2-.4-.2zM168.4 107.6l.3 .2-.1 .2-.3-.2zM168.6 112l.3 .2-.1 .2-.3-.2zM168.8 117.3l.3 .2-.1 .2-.3-.2z"/>
<path d="M169.1 111.4l.3 .1-.1 .2-.3-.2zM169.1 101.7l.3 .2-.1 .2-.3-.2zM170 102.7l.3 .2-.1 .2-.4-.2zM170 118.2l.3 .2-.1 .2-.4-.2zM170 105.6l.3 .2-.1 .2-.3-.2zM170 108l.3 .2-.1 .1-.3-.1zM170 115.3l.3 .2-.1 .2-.3-.2zM170 109.9l.3 .2-.1 .2-.3-.2zM170.2 100.7l.3 .2-.1 .2-.3-.2zM170.7 118.1l.3 .2-.1 .2-.3-.2zM171.5 112.4l.3 .2-.1 .2-.3-.2zM173.8 103.5l.4 .2-.2 .2-.3-.2z"/>
<path d="M173.8 114.4l.4 .2-.2 .2-.3-.2zM174 110.5l.3 .2-.1 .2-.3-.2zM174.3 104.9l.3 .2-.1 .2-.3-.2zM174.4 109.6l.3 .2-.1 .2-.4-.2zM175.4 118.2l.3 .2-.1 .2-.3-.2zM175.5 113.6l.4 .1-.2 .2-.3-.2zM177.3 109.5l.3 .2-.1 .2-.3-.2zM177.7 104.8l.3 .1-.1 .2-.4-.2zM177.7 119.1l.3 .2-.1 .2-.4-.2zM179.2 108.3l.3 .2-.1 .2-.3-.2zM179.2 115.1l.3 .2-.1 .2-.3-.2zM179.3 110.3l.3 .1-.1 .2-.3-.2z"/>
<path d="M180.4 118.3l.4 .2-.1 .2-.4-.2zM181.4 100.4l.3 .1-.1 .2-.3-.2zM181.5 114.1l.3 .2-.1 .1-.3-.1zM183.2 118l.3 .2-.1 .1-.4-.1zM183.4 108.7l.3 .2-.1 .2-.3-.2zM183.4 101.9l.3 .2-.1 .2-.3-.2zM185.7 112.8l.3 .2-.1 .2-.3-.2zM185.9 115.3l.3 .1-.1 .2-.3-.2zM187.5 110.9l.3 .1-.1 .2-.3-.2zM187.6 115.9l.4 .2-.1 .2-.4-.2zM187.8 119l.3 .2-.1 .2-.3-.2zM188.2 104.8l.4 .2-.2 .2-.3-.2z"/>
<path d="M188.4 105.9l.3 .2-.1 .2-.3-.2zM188.4 107l.3 .1-.1 .2-.3-.2zM188.5 109.7l.3 .2-.1 .1-.3-.1zM189.1 114.7l.3 .2-.1 .2-.3-.2zM189.1 113.1l.3 .1-.1 .2-.3-.2zM190 101.8l.3 .2-.1 .2-.3-.2zM190 103.1l.3 .2-.1 .2-.3-.2zM190 105l.3 .2-.1 .2-.3-.2zM190.1 110l.3 .2-.1 .2-.3-.2zM190.4 114.9l.3 .2-.1 .2-.4-.2zM191.1 107.2l.3 .2-.1 .2-.3-.2zM192.4 116.3l.3 .2-.1 .1-.3-.1z"/>
<path d="M195.4 116.9l.3 .2-.1 .1-.4-.1zM196.7 110.9l.3 .2-.1 .2-.3-.2zM197.3 115.3l.3 .2-.1 .2-.3-.2zM197.5 101.5l.3 .2-.1 .2-.3-.2zM197.6 104.5l.3 .2-.1 .2-.4-.2zM82.2 138.3l.3 .2-.1 .2-.3-.2zM90.4 137.5l.4 .2-.1 .2-.4-.2zM103.4 121.5l.3 .2-.1 .2-.3-.2zM103.5 133.7l.3 .2-.1 .2-.3-.2zM112.9 134.9l.3 .2-.1 .2-.3-.2zM117.3 133l.3 .1-.1 .2-.3-.2zM118 134.5l.3 .2-.1 .2-.3-.2z"/>
<path d="M119.5 124.1l.3 .2-.1 .2-.3-.2zM120.5 136.8l.3 .2-.1 .2-.3-.2zM122.2 133.9l.3 .2-.1 .2-.3-.2zM122.9 126.4l.3 .2-.1 .2-.3-.2zM123 138.5l.4 .1-.2 .2-.3-.2zM123.2 128l.3 .2-.1 .2-.3-.2zM123.3 130.1l.3 .2-.1 .1-.3-.1zM125.3 137.2l.3 .2-.1 .2-.3-.2zM125.5 131.6l.3 .2-.1 .2-.3-.2zM126.9 136.3l.3 .1-.1 .2-.4-.2zM127 139.6l.3 .1-.1 .2-.3-.2zM128.2 128.9l.3 .2-.1 .2-.3-.2z"/>
<path d="M128.7 134.6l.3 .1-.1 .2-.3-.2zM129.3 120.7l.3 .2-.1 .1-.3-.1zM131.8 121.8l.3 .2-.1 .2-.3-.2zM132.1 128l.3 .2-.1 .2-.3-.2zM133.7 122.1l.3 .2-.1 .2-.3-.2zM134.5 136.9l.3 .2-.1 .2-.3-.2zM134.7 132.2l.3 .2-.1 .2-.3-.2zM135.3 121.9l.3 .1-.1 .2-.3-.2zM136.2 139.2l.3 .2-.1 .2-.3-.2zM137 135.7l.3 .1-.1 .2-.3-.2zM138.5 132.3l.3 .2-.1 .1-.4-.1zM138.5 138.7l.4 .2-.2 .2-.3-.2z"/>
<path d="M139.4 132.7l.3 .2-.1 .2-.3-.2zM140.2 132.8l.3 .2-.1 .2-.3-.2zM140.3 123.3l.3 .2-.1 .2-.3-.2zM141.6 130.1l.3 .2-.1 .1-.3-.1zM141.8 137.4l.4 .1-.2 .2-.3-.2zM142 127l.3 .2-.1 .2-.3-.2zM142.6 139l.3 .1-.1 .2-.3-.2zM142.9 129.3l.4 .2-.2 .2-.3-.2zM143.1 136.1l.3 .2-.1 .2-.3-.2zM143.8 124.7l.3 .1-.1 .2-.3-.2zM144 120.2l.4 .2-.2 .1-.3-.1zM144.2 121.4l.3 .2-.1 .2-.3-.2z"/>
<path d="M144.5 134.8l.3 .2-.1 .2-.3-.2zM144.6 137.7l.3 .2-.1 .2-.4-.2zM144.8 134.1l.3 .2-.1 .2-.3-.2zM144.9 120.9l.3 .2-.1 .2-.3-.2zM145 122l.3 .2-.1 .2-.3-.2zM145.6 131.8l.3 .2-.1 .2-.3-.2zM146.3 138.9l.3 .2-.1 .2-.3-.2zM146.4 135.7l.3 .2-.1 .2-.3-.2zM147.4 129.5l.3 .2-.1 .2-.3-.2zM147.9 133.4l.3 .2-.1 .1-.4-.1zM148.5 137.2l.3 .2-.1 .2-.3-.2zM148.9 138.9l.3 .2-.1 .2-.3-.2z"/>
<path d="M151.2 127.4l.3 .2-.1 .1-.4-.1zM151.2 124.2l.3 .2-.1 .2-.4-.2zM151.2 131.7l.3 .2-.1 .2-.4-.2zM151.8 135.8l.3 .2-.1 .2-.3-.2zM152.2 133l.3 .2-.1 .2-.3-.2zM152.4 122.1l.3 .2-.1 .2-.3-.2zM152.8 129.3l.4 .2-.1 .2-.4-.2zM154.1 121l.3 .2-.1 .2-.3-.2zM154.3 132.4l.3 .1-.1 .2-.3-.2zM154.7 135.8l.3 .2-.1 .2-.3-.2zM156.5 138.7l.3 .2-.1 .2-.3-.2zM157.1 136.1l.3 .2-.1 .2-.3-.2z"/>
<path d="M157.1 133.5l.3 .1-.1 .2-.3-.2zM157.5 126.6l.3 .2-.1 .2-.3-.2zM159.1 134.9l.3 .2-.1 .2-.3-.2zM160.4 120.1l.3 .2-.1 .2-.3-.2zM160.5 131.5l.3 .2-.1 .2-.3-.2zM163.4 136.8l.3 .2-.1 .2-.3-.2zM164.4 132.8l.3 .2-.1 .2-.3-.2zM164.4 131.4l.4 .2-.1 .2-.4-.2zM164.7 121.4l.3 .2-.1 .2-.3-.2zM165 128.1l.4 .2-.2 .2-.3-.2zM165.6 139.6l.3 .2-.1 .2-.3-.2zM165.9 122.2l.3 .2-.1 .2-.3-.2z"/>
<path d="M166 133.5l.3 .2-.1 .2-.3-.2zM166.6 123.5l.4 .2-.1 .1-.4-.1zM166.7 126.4l.3 .2-.1 .2-.3-.2zM167.8 138.2l.3 .2-.1 .2-.3-.2zM168.2 129.1l.3 .2-.1 .2-.3-.2zM169.3 131.1l.3 .2-.1 .2-.3-.2zM169.6 120.8l.3 .2-.1 .2-.3-.2zM169.9 135.2l.3 .2-.1 .2-.3-.2zM170 126.8l.3 .2-.1 .1-.4-.1zM170 128.6l.3 .2-.1 .2-.3-.2zM170.3 122.9l.3 .2-.1 .2-.3-.2zM170.3 132.9l.3 .2-.1 .1-.3-.1z"/>
<path d="M170.5 120.5l.3 .2-.1 .2-.4-.2zM172.4 136.9l.3 .2-.1 .2-.3-.2zM174.2 122.6l.3 .2-.1 .2-.3-.2zM174.6 130.5l.3 .2-.1 .2-.3-.2zM175.4 128.1l.3 .2-.1 .2-.3-.2zM175.6 133.1l.3 .2-.1 .2-.3-.2zM176.6 136.6l.4 .2-.2 .2-.3-.2zM177.9 134.6l.3 .1-.1 .2-.3-.2zM179.8 130.7l.3 .2-.1 .1-.3-.1zM180.7 136.4l.3 .2-.1 .2-.3-.2zM181.6 126.9l.3 .2-.1 .2-.4-.2zM181.8 125.4l.3 .2-.1 .2-.3-.2z"/>
<path d="M181.9 130.1l.3 .2-.1 .1-.3-.1zM182.6 133.8l.3 .2-.1 .2-.3-.2zM182.9 120l.3 .2-.1 .2-.3-.2zM183.1 139.1l.3 .2-.1 .2-.3-.2zM183.6 133.7l.3 .2-.1 .2-.3-.2zM183.8 120.4l.3 .2-.1 .2-.4-.2zM183.9 131.1l.3 .2-.1 .2-.3-.2zM184 132.6l.3 .2-.1 .2-.3-.2zM187.3 129.5l.3 .2-.1 .2-.3-.2zM187.7 134.1l.3 .1-.1 .2-.3-.2zM187.8 124.7l.3 .2-.1 .2-.3-.2zM188 132.2l.3 .2-.1 .2-.3-.2z"/>
<path d="M188 126.9l.3 .2-.1 .2-.3-.2zM189 130.4l.3 .2-.1 .2-.3-.2zM90.2 142.9l.3 .1-.1 .2-.3-.2zM91.6 147.9l.3 .1-.1 .2-.3-.2zM97.1 141.5l.4 .2-.2 .2-.3-.2zM100.3 146.2l.3 .2-.1 .2-.3-.2zM101.9 142.3l.3 .2-.1 .2-.3-.2zM102 140.5l.4 .2-.1 .2-.4-.2zM102.6 147.9l.4 .2-.2 .2-.3-.2zM103.6 145.3l.3 .2-.1 .2-.3-.2zM105.6 140.7l.3 .2-.1 .2-.3-.2zM106.5 142.1l.3 .2-.1 .2-.3-.2z"/>
<path d="M112.1 142.3l.3 .2-.1 .2-.3-.2zM112.1 145.5l.3 .2-.1 .2-.3-.2zM113.1 148l.4 .2-.2 .2-.3-.2zM117.5 142.4l.3 .2-.1 .2-.4-.2zM122.5 142.3l.4 .2-.2 .2-.3-.2zM122.9 148.1l.3 .2-.1 .2-.3-.2zM127.4 142.3l.3 .2-.1 .2-.3-.2zM129.6 144.4l.4 .2-.1 .2-.4-.2zM132.8 141.4l.3 .2-.1 .2-.3-.2zM133.2 144.2l.3 .2-.1 .2-.3-.2zM133.8 147.9l.3 .2-.1 .2-.3-.2zM134.2 140l.3 .2-.1 .2-.3-.2z"/>
<path d="M134.2 145.3l.3 .2-.1 .2-.3-.2zM136 141.5l.3 .2-.1 .2-.3-.2zM136 145.3l.3 .2-.1 .2-.3-.2zM136.3 140.7l.3 .2-.1 .2-.4-.2zM137.1 144l.3 .1-.1 .2-.3-.2zM139 145.1l.4 .2-.1 .2-.4-.2zM141.1 140.2l.3 .2-.1 .2-.3-.2zM141.1 145.7l.3 .2-.1 .2-.3-.2zM142.6 143l.3 .2-.1 .2-.3-.2zM142.9 141.7l.3 .2-.1 .1-.4-.1zM143.3 140.7l.3 .1-.1 .2-.3-.2zM143.7 145.4l.3 .2-.1 .2-.3-.2z"/>
<path d="M144.7 143.4l.3 .2-.1 .2-.3-.2zM150.3 145.4l.3 .2-.1 .2-.3-.2zM151.2 140.7l.4 .2-.2 .2-.3-.2zM159.2 145.6l.3 .2-.1 .1-.3-.1zM171.8 140.7l.3 .2-.1 .2-.3-.2zM171.9 144.5l.3 .2-.1 .1-.3-.1zM174.3 142.9l.3 .1-.1 .2-.3-.2zM176.8 140l.3 .2-.1 .2-.3-.2zM180.5 147.9l.3 .2-.1 .2-.3-.2z"/>
</g>
</svg>
